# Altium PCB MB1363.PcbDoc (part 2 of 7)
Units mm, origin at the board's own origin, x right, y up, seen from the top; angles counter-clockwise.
Board outline 70 x 133.34 mm, 6 copper layers (Top Layer, Signal Layer 1, Signal Layer 2, Signal Layer 3, Signal Layer 4, Bottom Layer), stack 1.57 mm thick; 355 components, 293 nets, 1446 pads, 1145 vias.

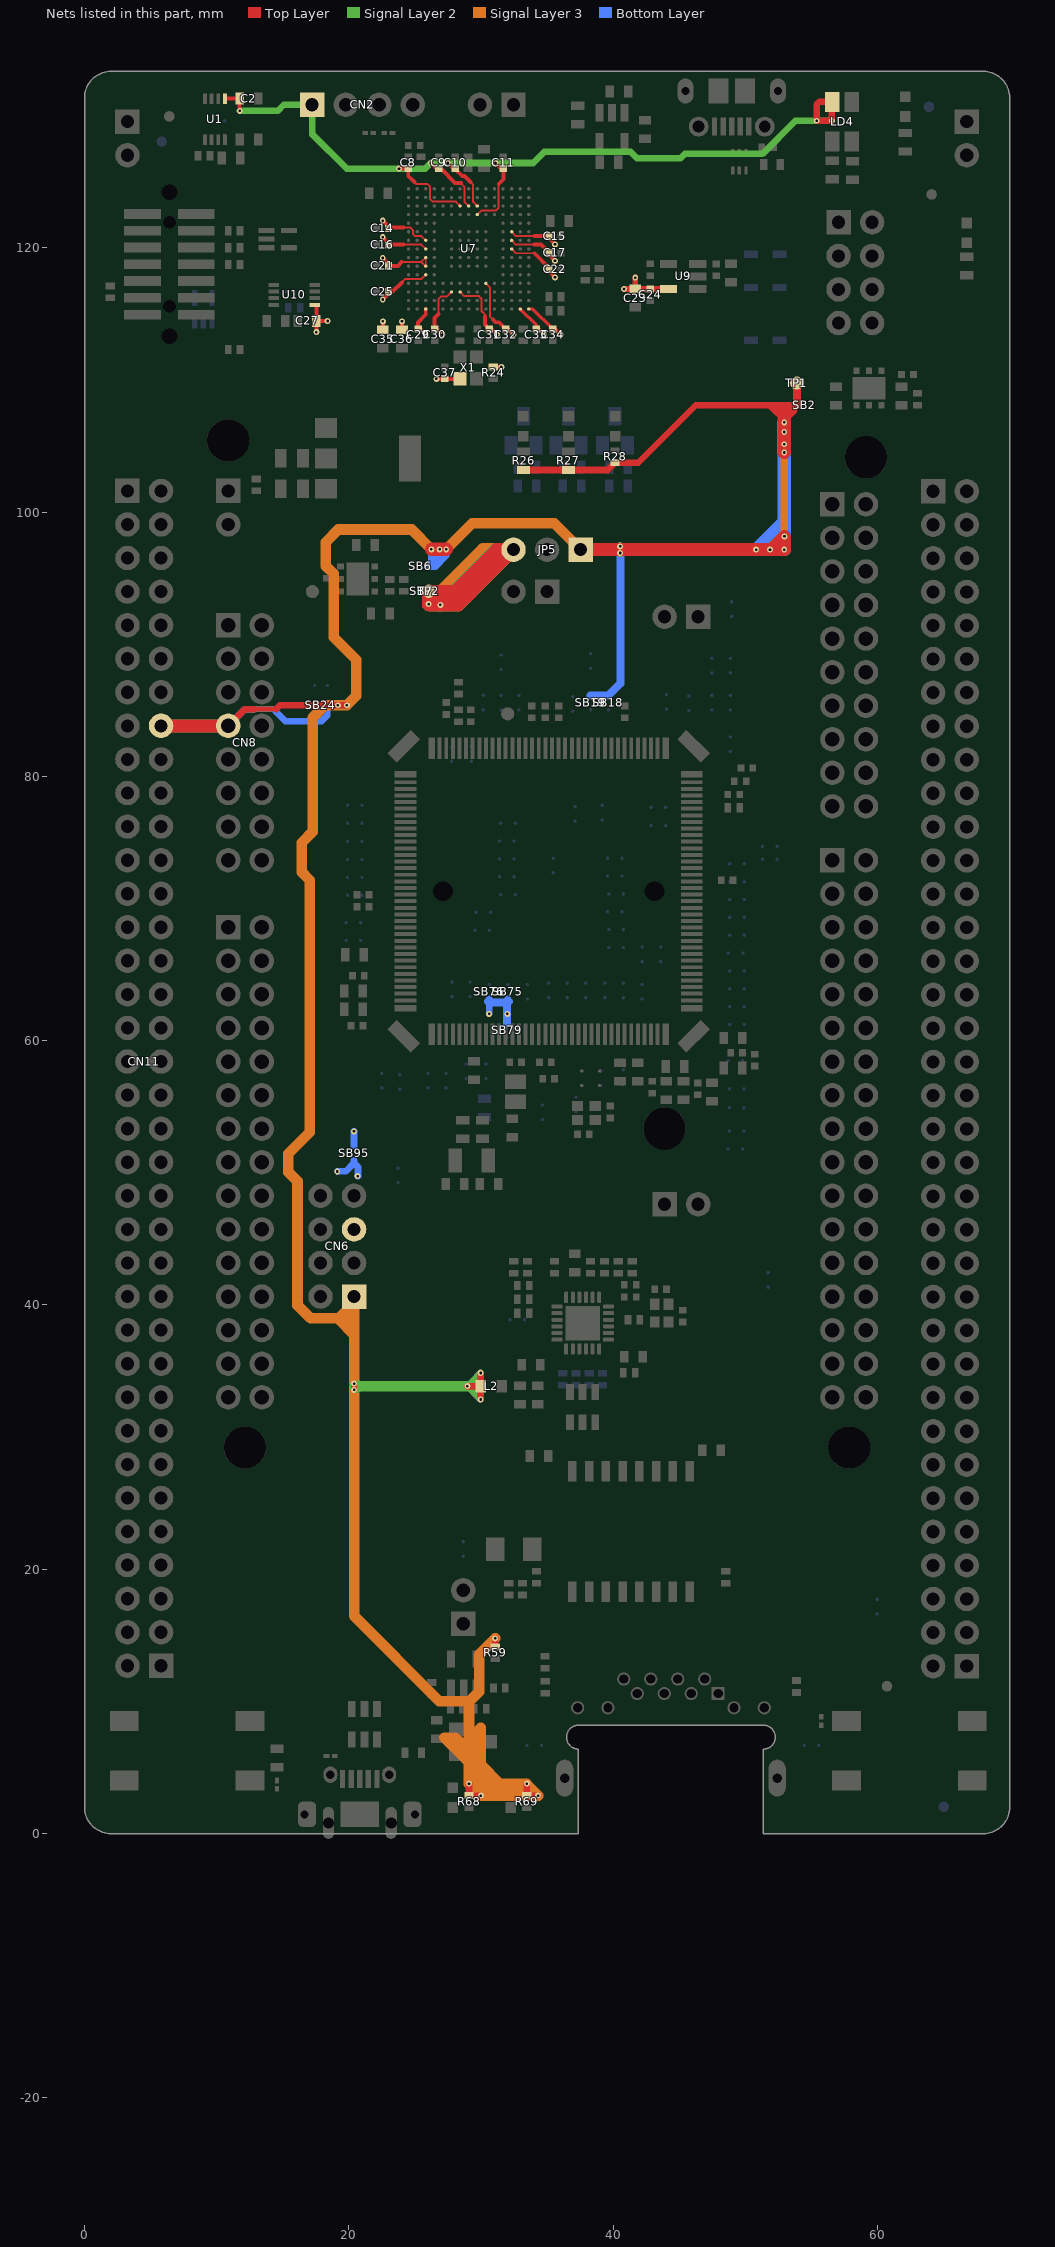
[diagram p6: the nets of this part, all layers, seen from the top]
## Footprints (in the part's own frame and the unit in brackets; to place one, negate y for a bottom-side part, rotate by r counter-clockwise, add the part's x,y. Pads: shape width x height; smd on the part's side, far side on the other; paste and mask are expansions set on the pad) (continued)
ICC_LQFP144_20X20_P050_SOCKET_YAMAICHI_IC149-144-145-B5_NM [mm]
  rect 1x2.5 smd rot 45 mask+0.05: 0(-10.96,-10.96) 0(10.96,10.96)
  rect 1x2.5 smd rot 135 mask+0.05: 0(-10.96,10.96) 0(10.96,-10.96)
  round 0 hole 1.5 unplated mask+0.05: 0(0,8) 0(0,-8)
  rect 1.65x0.5 smd mask+0.05: 1(-10.825,8.85) 36(-10.825,-8.85) 73(10.825,-8.85) 108(10.825,8.85)
  rect 1.65x0.3 smd mask+0.05: 2(-10.825,8.25) 3(-10.825,7.75) 4(-10.825,7.25) 5(-10.825,6.75) 6(-10.825,6.25) 7(-10.825,5.75) 8(-10.825,5.25) 9(-10.825,4.75) 10(-10.825,4.25) 11(-10.825,3.75) 12(-10.825,3.25) 13(-10.825,2.75) 14(-10.825,2.25) 15(-10.825,1.75) 16(-10.825,1.25) 17(-10.825,0.75) 18(-10.825,0.25) 19(-10.825,-0.25) 20(-10.825,-0.75) 21(-10.825,-1.25) 22(-10.825,-1.75) 23(-10.825,-2.25) 24(-10.825,-2.75) 25(-10.825,-3.25) 26(-10.825,-3.75) 27(-10.825,-4.25) 28(-10.825,-4.75) 29(-10.825,-5.25) 30(-10.825,-5.75) 31(-10.825,-6.25) 32(-10.825,-6.75) 33(-10.825,-7.25) 34(-10.825,-7.75) 35(-10.825,-8.25) 74(10.825,-8.25) 75(10.825,-7.75) 76(10.825,-7.25) 77(10.825,-6.75) 78(10.825,-6.25) 79(10.825,-5.75) 80(10.825,-5.25) 81(10.825,-4.75) 82(10.825,-4.25) 83(10.825,-3.75) 84(10.825,-3.25) 85(10.825,-2.75) 86(10.825,-2.25) 87(10.825,-1.75) 88(10.825,-1.25) 89(10.825,-0.75) 90(10.825,-0.25) 91(10.825,0.25) 92(10.825,0.75) 93(10.825,1.25) 94(10.825,1.75) 95(10.825,2.25) 96(10.825,2.75) 97(10.825,3.25) 98(10.825,3.75) 99(10.825,4.25) 100(10.825,4.75) 101(10.825,5.25) 102(10.825,5.75) 103(10.825,6.25) 104(10.825,6.75) 105(10.825,7.25) 106(10.825,7.75) 107(10.825,8.25)
  rect 0.5x1.65 smd mask+0.05: 37(-8.85,-10.825) 72(8.85,-10.825) 109(8.85,10.825) 144(-8.85,10.825)
  rect 0.3x1.65 smd mask+0.05: 38(-8.25,-10.825) 39(-7.75,-10.825) 40(-7.25,-10.825) 41(-6.75,-10.825) 42(-6.25,-10.825) 43(-5.75,-10.825) 44(-5.25,-10.825) 45(-4.75,-10.825) 46(-4.25,-10.825) 47(-3.75,-10.825) 48(-3.25,-10.825) 49(-2.75,-10.825) 50(-2.25,-10.825) 51(-1.75,-10.825) 52(-1.25,-10.825) 53(-0.75,-10.825) 54(-0.25,-10.825) 55(0.25,-10.825) 56(0.75,-10.825) 57(1.25,-10.825) 58(1.75,-10.825) 59(2.25,-10.825) 60(2.75,-10.825) 61(3.25,-10.825) 62(3.75,-10.825) 63(4.25,-10.825) 64(4.75,-10.825) 65(5.25,-10.825) 66(5.75,-10.825) 67(6.25,-10.825) 68(6.75,-10.825) 69(7.25,-10.825) 70(7.75,-10.825) 71(8.25,-10.825) 110(8.25,10.825) 111(7.75,10.825) 112(7.25,10.825) 113(6.75,10.825) 114(6.25,10.825) 115(5.75,10.825) 116(5.25,10.825) 117(4.75,10.825) 118(4.25,10.825) 119(3.75,10.825) 120(3.25,10.825) 121(2.75,10.825) 122(2.25,10.825) 123(1.75,10.825) 124(1.25,10.825) 125(0.75,10.825) 126(0.25,10.825) 127(-0.25,10.825) 128(-0.75,10.825) 129(-1.25,10.825) 130(-1.75,10.825) 131(-2.25,10.825) 132(-2.75,10.825) 133(-3.25,10.825) 134(-3.75,10.825) 135(-4.25,10.825) 136(-4.75,10.825) 137(-5.25,10.825) 138(-5.75,10.825) 139(-6.25,10.825) 140(-6.75,10.825) 141(-7.25,10.825) 142(-7.75,10.825) 143(-8.25,10.825)
  silkscreen extent -10.1,-10.1 10.1,10.1, body extent -11,-11 11,11, height 1.6
ICC_UFBGA201_176+25_10X10_P065 [mm] "IPC"
  round 0.25 smd mask+0.05: A1(-4.55,4.55) A2(-3.9,4.55) A3(-3.25,4.55) A4(-2.6,4.55) A5(-1.95,4.55) A6(-1.3,4.55) A7(-0.65,4.55) A8(0,4.55) A9(0.65,4.55) A10(1.3,4.55) A11(1.95,4.55) A12(2.6,4.55) A13(3.25,4.55) A14(3.9,4.55) A15(4.55,4.55) B1(-4.55,3.9) B2(-3.9,3.9) B3(-3.25,3.9) B4(-2.6,3.9) B5(-1.95,3.9) B6(-1.3,3.9) B7(-0.65,3.9) B8(0,3.9) B9(0.65,3.9) B10(1.3,3.9) B11(1.95,3.9) B12(2.6,3.9) B13(3.25,3.9) B14(3.9,3.9) B15(4.55,3.9) C1(-4.55,3.25) C2(-3.9,3.25) C3(-3.25,3.25) C4(-2.6,3.25) C5(-1.95,3.25) C6(-1.3,3.25) C7(-0.65,3.25) C8(0,3.25) C9(0.65,3.25) C10(1.3,3.25) C11(1.95,3.25) C12(2.6,3.25) C13(3.25,3.25) C14(3.9,3.25) C15(4.55,3.25) D1(-4.55,2.6) D2(-3.9,2.6) D3(-3.25,2.6) D4(-2.6,2.6) D5(-1.95,2.6) D6(-1.3,2.6) D7(-0.65,2.6) D8(0,2.6) D9(0.65,2.6) D10(1.3,2.6) D11(1.95,2.6) D12(2.6,2.6) D13(3.25,2.6) D14(3.9,2.6) D15(4.55,2.6) E1(-4.55,1.95) E2(-3.9,1.95) E3(-3.25,1.95) E4(-2.6,1.95) E12(2.6,1.95) E13(3.25,1.95) E14(3.9,1.95) E15(4.55,1.95) F1(-4.55,1.3) F2(-3.9,1.3) F3(-3.25,1.3) F4(-2.6,1.3) F6(-1.3,1.3) F7(-0.65,1.3) F8(0,1.3) F9(0.65,1.3) F10(1.3,1.3) F12(2.6,1.3) F13(3.25,1.3) F14(3.9,1.3) F15(4.55,1.3) G1(-4.55,0.65) G2(-3.9,0.65) G3(-3.25,0.65) G4(-2.6,0.65) G6(-1.3,0.65) G7(-0.65,0.65) G8(0,0.65) G9(0.65,0.65) G10(1.3,0.65) G12(2.6,0.65) G13(3.25,0.65) G14(3.9,0.65) G15(4.55,0.65) H1(-4.55,0) H2(-3.9,0) H3(-3.25,0) H4(-2.6,0) H6(-1.3,0) H7(-0.65,0) H8(0,0) H9(0.65,0) H10(1.3,0) H12(2.6,0) H13(3.25,0) H14(3.9,0) H15(4.55,0) J1(-4.55,-0.65) J2(-3.9,-0.65) J3(-3.25,-0.65) J4(-2.6,-0.65) J6(-1.3,-0.65) J7(-0.65,-0.65) J8(0,-0.65) J9(0.65,-0.65) J10(1.3,-0.65) J12(2.6,-0.65) J13(3.25,-0.65) J14(3.9,-0.65) J15(4.55,-0.65) K1(-4.55,-1.3) K2(-3.9,-1.3) K3(-3.25,-1.3) K4(-2.6,-1.3) K6(-1.3,-1.3) K7(-0.65,-1.3) K8(0,-1.3) K9(0.65,-1.3) K10(1.3,-1.3) K12(2.6,-1.3) K13(3.25,-1.3) K14(3.9,-1.3) K15(4.55,-1.3) L1(-4.55,-1.95) L2(-3.9,-1.95) L3(-3.25,-1.95) L4(-2.6,-1.95) L12(2.6,-1.95) L13(3.25,-1.95) L14(3.9,-1.95) L15(4.55,-1.95) M1(-4.55,-2.6) M2(-3.9,-2.6) M3(-3.25,-2.6) M4(-2.6,-2.6) M5(-1.95,-2.6) M6(-1.3,-2.6) M7(-0.65,-2.6) M8(0,-2.6) M9(0.65,-2.6) M10(1.3,-2.6) M11(1.95,-2.6) M12(2.6,-2.6) M13(3.25,-2.6) M14(3.9,-2.6) M15(4.55,-2.6) N1(-4.55,-3.25) N2(-3.9,-3.25) N3(-3.25,-3.25) N4(-2.6,-3.25) N5(-1.95,-3.25) N6(-1.3,-3.25) N7(-0.65,-3.25) N8(0,-3.25) N9(0.65,-3.25) N10(1.3,-3.25) N11(1.95,-3.25) N12(2.6,-3.25) N13(3.25,-3.25) N14(3.9,-3.25) N15(4.55,-3.25) P1(-4.55,-3.9) P2(-3.9,-3.9) P3(-3.25,-3.9) P4(-2.6,-3.9) P5(-1.95,-3.9) P6(-1.3,-3.9) P7(-0.65,-3.9) P8(0,-3.9) P9(0.65,-3.9) P10(1.3,-3.9) P11(1.95,-3.9) P12(2.6,-3.9) P13(3.25,-3.9) P14(3.9,-3.9) P15(4.55,-3.9) R1(-4.55,-4.55) R2(-3.9,-4.55) R3(-3.25,-4.55) R4(-2.6,-4.55) R5(-1.95,-4.55) R6(-1.3,-4.55) R7(-0.65,-4.55) R8(0,-4.55) R9(0.65,-4.55) R10(1.3,-4.55) R11(1.95,-4.55) R12(2.6,-4.55) R13(3.25,-4.55) R14(3.9,-4.55) R15(4.55,-4.55)
  silkscreen extent -5.22,-5.07 5.07,5.23, body extent -5.07,-5.07 5.07,5.07, height 0.61
ICC_VQFN24-EPAD_4X4_P050 [mm]
  rrect50% 0.85x0.3 smd mask+0.05: 1(-1.95,1.25) 2(-1.95,0.75) 3(-1.95,0.25) 4(-1.95,-0.25) 5(-1.95,-0.75) 6(-1.95,-1.25) 13(1.95,-1.25) 14(1.95,-0.75) 15(1.95,-0.25) 16(1.95,0.25) 17(1.95,0.75) 18(1.95,1.25)
  rrect50% 0.3x0.85 smd mask+0.05: 7(-1.25,-1.95) 8(-0.75,-1.95) 9(-0.25,-1.95) 10(0.25,-1.95) 11(0.75,-1.95) 12(1.25,-1.95) 19(1.25,1.95) 20(0.75,1.95) 21(0.25,1.95) 22(-0.25,1.95) 23(-0.75,1.95) 24(-1.25,1.95)
  rect 2.6x2.6 smd paste-10 mask+0.05: EP(0,0)
  silkscreen extent -2,-2 2,2, body extent -2.05,-2.05 2.05,2.05, height 1.1
ICC_VSSOP8_DCU_R-PDSO-G8_2X2P30_P050 [mm]
  rect 0.3x0.8 smd mask+0.05: 1(-0.75,-1.55) 2(-0.25,-1.55) 3(0.25,-1.55) 4(0.75,-1.55) 5(0.75,1.55) 6(0.25,1.55) 7(-0.25,1.55) 8(-0.75,1.55)
  silkscreen extent -1.05,-1.2 1.05,1.2, body extent -1.05,-1.62 1.05,1.62, height 0.9
L0603 [mm]
  rect 0.8x0.95 smd mask+0.05: 1(-0.8,0) 2(0.8,0)
  silkscreen extent -1.33,-0.6 1.33,0.6, body extent -0.87,-0.47 0.87,0.47, height 0.95
L0805_H0P9 [mm]
  rect 1.1x1.6 smd mask+0.05: 1(-0.75,0) 2(0.75,0)
  silkscreen extent -0.08,-0.7 0.08,0.7, body extent -1.07,-0.7 1.07,0.7, height 1.2
LED_0603_OSRAM_LG-Q396-PS-35_GREEN_1A2K_H0P4 [mm]
  rect 0.8x0.8 smd mask+0.05: 1(-0.75,0) 2(0.75,0)
  silkscreen extent -0.85,-0.53 1.28,0.53, body extent -0.85,-0.45 0.85,0.45, height 0.6
LED_0603_OSRAM_LS-Q976-NR-1_RED_1A2K_H0P8 [mm]
  rect 0.8x0.8 smd mask+0.05: 1(-0.75,0) 2(0.75,0)
  silkscreen extent -0.85,-0.53 1.28,0.53, body extent -0.85,-0.45 0.85,0.45, height 0.8
LED_0603_OSRAM_LY-Q396-P1Q2-36_YELLOW_1A2K_H0P4 [mm]
  rect 0.8x0.8 smd mask+0.05: 1(-0.75,0) 2(0.75,0)
  silkscreen extent -0.85,-0.53 1.28,0.53, body extent -0.85,-0.45 0.85,0.45, height 0.4
LED_0603_RED [mm]
  rect 0.8x0.8 smd mask+0.05: 1(-0.75,0) 2(0.75,0)
  silkscreen extent -0.25,-0.4 1.25,0.4, body extent -0.8,-0.4 0.8,0.4, height 0.6
LED_0603_VISHAY_VLMS1300-GS08_RED_1A2K_H0P8 [mm]
  rect 0.8x0.8 smd mask+0.05: 1(-0.75,0) 2(0.75,0)
  silkscreen extent -0.85,-0.53 1.28,0.53, body extent -0.85,-0.45 0.85,0.45, height 0.8
LED_BI-GR_HSMF-A201-A00J1 [mm]
  rect 1.1x1.5 smd mask+0.05: 1(-0.75,-1.5) 2(-0.75,1.5) 3(0.75,1.5) 4(0.75,-1.5)
  silkscreen extent -1.65,-1.85 1.65,1.85, body extent -1.5,-1.85 1.5,1.85, height 2.1
MIRE_PLACE_SMD_0P8MM [mm]
  round 0.8 smd paste-10 mask+0.2: 1(0,0)
  Top Layer keep-out circle w0.01: c0,0 r0.804
MOS_SOT23-5L [mm]
  rect 0.6x1.3 smd mask+0.05: 1(-0.95,-1.1) 2(0,-1.1) 3(0.95,-1.1) 4(0.95,1.1) 5(-0.95,1.1)
  silkscreen extent -1.6,-0.95 1.6,0.97, body extent -1.52,-1.25 1.52,1.25, height 1.45
NPN_SOT23 [mm]
  rect 1x1.4 smd mask+0.05: 1(-0.95,-1.1) 2(0.95,-1.1) 3(0,1.1)
  silkscreen extent -1.63,-0.82 1.63,0.82, body extent -1.56,-1.25 1.56,1.25, height 1.1
OSC_NDK_NZ2520SB_4P [mm]
  rect 1x1 smd mask+0.05: 1(-0.825,-0.625) 2(0.825,-0.625) 3(0.825,0.625) 4(-0.825,0.625)
  silkscreen extent -1.43,-1.22 1.2,1.05, body extent -1.3,-1.05 1.3,1.05, height 0.91
R0402 [mm]
  rect 0.51x0.7 smd mask+0.05: 1(-0.45,0) 2(0.45,0)
  silkscreen extent -0.72,-0.43 0.72,0.43, body extent -0.52,-0.3 0.52,0.3, height 0.4
R0603 [mm]
  rect 0.64x1 smd mask+0.05: 1(-0.7,0) 2(0.7,0)
  silkscreen extent -1.05,-0.58 1.05,0.58, body extent -0.9,-0.5 0.9,0.5, height 0.56
REG_SOT23-5L [mm]
  rect 0.6x1.3 smd mask+0.05: 1(-0.95,-1.1) 2(0,-1.1) 3(0.95,-1.1) 4(0.95,1.1) 5(-0.95,1.1)
  silkscreen extent -1.6,-0.95 1.6,0.97, body extent -1.52,-1.25 1.52,1.25, height 1.1
REG_SOT223-TAB [mm]
  rect 1.5x1.65 smd mask+0.05: 1(-2.3,-3.175) 2(0,-3.175) 3(2.3,-3.175)
  rect 3.5x1.65 smd mask+0.05: 4(0,3.175)
  silkscreen extent -3.35,-2.15 3.35,2.12, body extent -3.35,-3.48 3.35,3.48, height 1.8
Sheetbox_6L2S [mil] "Sheetbox 6 layers / 2 silkscreens"
  round 20 on Mech16: 1(813.5,208.05) 1(2736.63,208.05)
SOLDER-BRIDGE_R0402-0R [mil]
  round 10 smd paste-393.7: 1(-17.72,0) 2(20.67,0)
  Top Layer region: 1.48,13.78 8.37,0 1.48,-13.78 30.51,-13.78 30.51,13.78
  Top Layer region: -30.51,-13.78 -30.51,13.78 -8.37,13.78 -1.48,0 -8.37,-13.78
  silkscreen extent -11,-17 11,17, body extent -36,-20 36,20, height 20
SOLDER-BRIDGE_R0603-0R [mil]
  round 10 smd paste-393.7: 1(-19.68,0) 2(23.62,0)
  Top Layer region: -47.24,-19.69 -47.24,19.68 -15.75,19.68 3.94,0 -15.75,-19.69 -47.24,-19.69
  Top Layer region: -5.91,19.68 13.78,0 -5.91,-19.69 47.24,-19.69 47.24,19.68 -5.91,19.68
  silkscreen extent -50,-23 50,23, body extent -36,-20 36,20, height 22
SWI_WEALTHMETAL_TD-0341_4P_BLACK [mm]
  rect 1.52x2.16 smd mask+0.05: 1(-2.25,-4.75) 2(-2.25,4.75) 3(2.25,-4.75) 4(2.25,4.75)
  silkscreen extent -3,-3.5 3,3.5, body extent -3,-5.15 3,5.15, height 7.55
SWI_WEALTHMETAL_TD-0341_4P_BLUE [mm]
  rect 1.52x2.16 smd mask+0.05: 1(-2.25,-4.75) 2(-2.25,4.75) 3(2.25,-4.75) 4(2.25,4.75)
  silkscreen extent -3,-3.5 3,3.5, body extent -3,-5.15 3,5.15, height 7.55
TP_SMD_1MM [mm]
  round 1 smd paste-10 mask+0.05: 1(0,0)
  silkscreen extent -0.7,-0.7 0.7,0.7
TRS_DGKYD_KMS-1102NL [mm]
  rect 0.64x1.55 smd mask+0.05: 1(-4.445,-4.575) 2(-3.175,-4.575) 3(-1.905,-4.575) 4(-0.635,-4.575) 5(0.635,-4.575) 6(1.905,-4.575) 7(3.175,-4.575) 8(4.445,-4.575) 9(4.445,4.575) 10(3.175,4.575) 11(1.905,4.575) 12(0.635,4.575) 13(-0.635,4.575) 14(-1.905,4.575) 15(-3.175,4.575) 16(-4.445,4.575)
  silkscreen extent -6.35,-3.7 6.35,3.7, body extent -6.35,-4.7 6.35,4.7, height 6.3

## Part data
B1: library part MCD-00002, "Non-Open Push-Button 0.1A 24V", Manufacturer=WEALTHMETAL, Manufacturer_Part_Number=TD-0341
B2: library part MCD-00001, "Non-Open Push-Button 0.1A 24V BLACK", Manufacturer=WEALTHMETAL, Manufacturer_Part_Number=TD-0341
C1 C3 C18 C63 C69 C72: library part MCD-00238, "Capacitor, MLCC, 1uF, 6V3, X5R, 10%, 0603, T=0,8mm", Manufacturer=YAGEO, Manufacturer_Part_Number=CC0603KRX5R5BB105, Package=C0603
C2 C4: library part MCD-00211, "Capacitor, MLCC, 100nF, 16V, X7R, 10%, 0603, T=0,8mm", Manufacturer=YAGEO, Manufacturer_Part_Number=CC0603KRX7R7BB104, Package=C0603
C5: library part MCD-00016, "Capacitor, MLCC, 20pF, 50V, NPO, 5%, 0402, T=0,5mm", Manufacturer=YAGEO, Manufacturer_Part_Number=CC0402JRNPO9BN200, Package=C0402
C6: library part MCD-00205, "Capacitor, MLCC, 100pF, 50V, NPO, 5%, 0402, T=0,5mm", Manufacturer=YAGEO, Manufacturer_Part_Number=CC0402JRNPO9BN101, Package=C0402
C7 C12 C13: library part MCD-00012, "Capacitor, MLCC, 2.2uF, 10V, X5R, 10%, 0603, T=0,8mm", Alternate_Manufacturer=KEMET, Alternate_Manufacturer_Part_Number=C0603C225K8PACTU, Manufacturer=YAGEO, Manufacturer_Part_Number=CC0603KRX5R6BB225, Package=C0603
C8 C9 C10 C11 C14 C15 C16 C17 C20 C21 C22 C24 C25 C28 C29 C30 C31 C32 C33 C34 C37: library part MCD-00102, "Capacitor, MLCC, 100nF, 16V, X7R, 10%, 0402, T=0,5mm", Alternate_Manufacturer=MURATA, Alternate_Manufacturer_Part_Number=GCM155R71C104KA55D, Manufacturer=YAGEO, Manufacturer_Part_Number=CC0402KRX7R7BB104, Package=C0402
C19: library part MCD-00011, "Capacitor, MLCC, 10nF, 16V, X7R, 10%, 0402, T=0.5mm", Manufacturer=YAGEO, Manufacturer_Part_Number=CC0402KRX7R7BB103, Package=C0402
C23 C36: library part MCD-00010, "Capacitor, MLCC, 1uF, 16V, X5R, 10%, 0603, T=0,8mm", Manufacturer=YAGEO, Manufacturer_Part_Number=CC0603KRX5R7BB105, Package=C0603
C26 C27 C60 C66 C70 C79 C84 C85 C86 C88 C89: library part MCD-00237, "Capacitor, MLCC, 100nF, 6V3, X5R, 10%, 0603, T=0,8mm", Manufacturer=YAGEO, Manufacturer_Part_Number=CC0603KRX5R5BB104, Package=C0603
C35 C91: library part MCD-00009, "Capacitor, MLCC, 4.7uF, 16V, X5R, 10%, 0603, T=0.8mm", Manufacturer=YAGEO, Manufacturer_Part_Number=CC0603KRX5R7BB475, Package=C0603
C38 C44 C46 C47 C48 C49 C50 C51 C52 C53 C54 C55 C56 C57 C58 C59 C61 C62 C71 C73: library part MCD-00006, "Capacitor, MLCC, 100nF, 16V, X7R, 10%, 0402, T=0.5mm", Alternate_Manufacturer=MURATA, Alternate_Manufacturer_Part_Number=GCM155R71C104KA55D, Manufacturer=YAGEO, Manufacturer_Part_Number=CC0402KRX7R7BB104, Package=C0402
C39 C43 C45 C67: library part MCD-01121, "Capacitor, MLCC, 4.7µF, 10V, X5R, 20%, 0603, T=0,8mm", Manufacturer=MURATA, Manufacturer_Part_Number=GRM188R61A475ME15, Package=C0603
C40: library part MCD-00097, "Capacitor, MLCC, 4.7uF, 16V, X5R, 20%, 0603, T=0,8mm", Alternate_Manufacturer=Murata, Alternate_Manufacturer_Part_Number=GRM188R61C475MAAJ, Manufacturer=MURATA, Manufacturer_Part_Number=GRM188R61C475KE11, Package=C0603
C41 C42: library part MCD-00014, "Capacitor, MLCC, 10uF, 25V, X5R, 10%, 0805, T=0,85mm", Manufacturer=YAGEO, Manufacturer_Part_Number=CC0805KRX5R8BB106, Package=C0805
C64: library part MCD-01225, "Capacitor, MLCC, 220pF, 50V, NPO, 5%, 0402, T=0,5mm", Manufacturer=YAGEO, Manufacturer_Part_Number=CC0402JRNPO9BN221, Package=C0402
C65 C68: library part MCD-01716, "Capacitor, MLCC, 10uF, 6V3, X5R, 20%, 0402, T=0.5mm", Manufacturer=YAGEO, Manufacturer_Part_Number=CC0402MRX5R5BB106, Package=C0402
C74 C76 C81 C83: library part MCD-01374, "Capacitor, MLCC, 5.6pF, 50V, NPO, 5%, 0402, T=0,5mm", Manufacturer=YAGEO, Manufacturer_Part_Number=CC0402BRNPO9BN5R6, Package=C0402
C75: library part MCD-01341, "Capacitor, MLCC, 10uF, 6V3, X5R, 20%, 0603, T=0,8mm", Manufacturer=MURATA, Manufacturer_Part_Number=GRM188R60J106ME47D, Package=C0603
C77 C78: library part MCD-01367, "Capacitor,5.1pF,0.25pF,50V,NPO,0603", Manufacturer=YAGEO, Manufacturer_Part_Number=CC0603CRNPO9BN5R1, Package=C0603
C80: library part MCD-00095, "Capacitor, MLCC, 1uF, 6V3, X5R, 10%, 0402, T=0,5mm", Alternate_Manufacturer=MURATA, Alternate_Manufacturer_Part_Number=GRM155R60J105KE19, Manufacturer_Part_Number=GRM155R61E105KA12, Package=C0402
C82: library part MCD-00724, "Capacitor, MLCC, 470pF, 50V, NPO, 5%, 0402, T=0,5mm", Manufacturer=YAGEO, Manufacturer_Part_Number=CC0402JRNPO9BN471, Package=C0402
C87: library part MCD-01124, "Capacitor, MLCC, 10µF, 10V, X5R, 10%, 0603, T=0.8mm", Manufacturer=MURATA, Manufacturer_Part_Number=GRM188R61A106KAAL, Package=C0603
C90: library part MCD-00722, "Capacitor, MLCC, 1nF, 2KV, X7R, 10%, 1206, T=1,25mm", Manufacturer=YAGEO, Manufacturer_Part_Number=CC1206KKX7RDBB102, Package=C1206
CN1: library part MCD-00028, "USB-MICRO-B, 0.65mm, RA, SMT, Bottom Mount,", Manufacturer=MOLEX, Manufacturer_Part_Number=1050170001
CN2: library part MCD-00029, "Header, 4x1, 2,54mm, VR, TH, Height 5.84mm/2.54mm", Manufacturer=SAMTEC, Manufacturer_Part_Number=TSW-104-07-x-S
CN3 CN4 CN15 CN16: library part MCD-00214, "Header, 2x1, 2,54mm, VR, TH, Height 5.84mm/10.16mm", Manufacturer=SAMTEC, Manufacturer_Part_Number=TSW-102-09-x-S
CN5: library part MCD-01226, "Header 5x2, 1.27mm, Dual row, Straight, Surface mount, vertical male connector. 3.05mm lead. Mates with FFSD connector. Footprint compatible with FTSH-107-01-L-DV,-K,-A,-P,-ES (STDC14 MEDIUM)", Alternate_Manufacturer=JIUBABA, Alternate_Manufacturer_Part_Number=P127B-2x05MGF-079-1A, Manufacturer=SAMTEC, Manufacturer_Part_Number=FTSH-105-01-L-DV-K
CN6: library part MCD-00633, "Header, 4x2, 2,54mm, VR, TH, Height 5.84mm/2.54mm", Manufacturer=SAMTEC, Manufacturer_Part_Number=TSW-104-07-x-D
CN7: library part MCD-01039, "Socket, 10x2, 2.54mm, VR, TH, Height 8.51mm/10mm, Low insertion force.", Manufacturer=SAMTEC, Manufacturer_Part_Number=SSW-110-23-x-D
CN8: library part MCD-01037, "Socket, 8x2, 2.54mm, VR, TH, Height 8.51mm/10mm, Low insertion force.", Manufacturer=SAMTEC, Manufacturer_Part_Number=SSW-108-23-x-D
CN9: library part MCD-01040, "Socket, 15x2, 2.54mm, VR, TH, Height 8.51mm/10mm, Low insertion force.", Manufacturer=SAMTEC, Manufacturer_Part_Number=SSW-115-23-x-D
CN10: library part MCD-01041, "Socket, 17x2, 2.54mm, VR, TH, Height 8.51mm/10mm, Low insertion force", Manufacturer=SAMTEC, Manufacturer_Part_Number=SSW-117-23-x-D
CN11 CN12: library part MCD-01210, "Header, 35x2, 2,54mm, VR, TH, Height 5.84mm/2.54mm", Manufacturer=SAMTEC, Manufacturer_Part_Number=TSW-135-07-x-D
CN13: library part MCD-00661, "USB-MICRO-AB Receptacle, RA, SMT + DIP, Standard, Top Mount, USB certified (symbol & footprint compatible with MCD-00022)", Manufacturer=HIROSE, Manufacturer_Part_Number=ZX62RD-AB-5P8(30)
CN14: library part MCD-00717, "RJ45 jack, single port, with LEDS, Metal shielded dip low profile", Manufacturer="DONGGUAN KEYOUDA ELECTRONIC TECHNOLOGY", Manufacturer_Part_Number=KRJ-CB4.2GYZNL
D1 D2 D3: library part MCD-00034, Manufacturer=STMICROELECTRONICS
JP1: library part MCD-00045, "Header, 2x1, 2,54mm, VR, TH, Height 5.84mm/2.54mm", Alternate_Manufacturer="JIUBABA; LIANYI", Alternate_Manufacturer_Part_Number=313102S111116;313102S111116, Manufacturer=SAMTEC, Manufacturer_Part_Number=TSW-102-07-x-S
JP2: library part MCD-00686, "Header, 4x2, 2,54mm, VR, TH, Height 5.84mm/2.54mm - Shunt Fitted 1-2", Manufacturer=SAMTEC, Manufacturer_Part_Number=TSW-104-07-x-D
JP3 JP4 JP6 JP7 JP8: library part MCD-00683, "Header, 2x1, 2,54mm, VR, TH, Height 5.84mm/2.54mm - Shunt Fitted by default", Alternate_Manufacturer=LIANYI, Alternate_Manufacturer_Part_Number=313102S111116, Manufacturer=SAMTEC, Manufacturer_Part_Number=TSW-102-07-x-S
JP5: library part MCD-00684, "Header, 3x1, 2,54mm, VR, TH, Height 5.84mm/2.54mm - Shunt Fitted 1-2 by default", Manufacturer=SAMTEC, Manufacturer_Part_Number=TSW-103-07-F-S
L1: library part MCD-01340, "Inductor, 2.2uH, 20%, Isat 1.2A, DCR 0.228Ohm, 0805", Manufacturer=MURATA, Manufacturer_Part_Number=DFE201210U-2R2M{}P2, Package=L0805
L2: library part MCD-00047, "SMD Chip ferrite bead, 600R@100MHz +/-25%, 350mA, 500mohm DC, 0603, T=0.8mm", Manufacturer=TAI-TECH, Manufacturer_Part_Number=FCM1608KF-601T03
LD1 LD5 LD8: library part MCD-00588, "LED Green, 0603 SMD, Forward Voltage Typ=2V, Max=2.5V", Alternate_Manufacturer="VISHAY SEMICONDUCTOR OPTO DIVISION", Alternate_Manufacturer_Part_Number=VLMTG1300-GS08, Manufacturer="OSRAM OPTO SEMICONDUCTORS", Manufacturer_Part_Number="LG Q396-PS-35", Package="LED 0603"
LD2: library part MCD-01061, "LED Yellow, 0603 SMD, Forward Voltage min=1.7V, Typ=2V, Max=2.3V", Manufacturer="OSRAM OPTO SEMICONDUCTORS", Manufacturer_Part_Number="LY Q396-P1Q2-36"
LD3: library part MCD-00586, "LED Red, 0603 SMD, Forward Voltage Typ=2V, Max=2.5V", Alternate_Manufacturer="VISHAY SEMICONDUCTOR OPTO DIVISION", Alternate_Manufacturer_Part_Number=VLMS1300-GS08, Manufacturer="OSRAM OPTO SEMICONDUCTORS", Manufacturer_Part_Number="LS Q976-NR-1", Package="LED 0603"
LD4: library part MCD-00051, "LED Bicolor", Alternate_Manufacturer=EVERLUCK, Alternate_Manufacturer_Part_Number=LE-RGW35280, Manufacturer="AVAGO TECHNOLOGIES", Manufacturer_Part_Number=HSMF-A201-A00J1
LD6: library part MCD-00049, "LED, Red, 0603", Manufacturer=EVERLIGHT, Manufacturer_Part_Number=19-213-R6C-AP1Q2B/3T, Package="LED 0603"
LD7: library part MCD-00587, "LED Red, 0603 SMD, 2V Forward Voltage", Alternate_Manufacturer="OSRAM OPTO SEMICONDUCTORS", Alternate_Manufacturer_Part_Number="LS Q976-NR-1", Manufacturer=VISHAY, Manufacturer_Part_Number=VLMS1300-GS08, Package="LED 0603"
Q1 Q2 Q3 T1: library part MCD-00073, "NPN Bipolar Transistor", Alternate_Manufacturer="ON SEMICONDUCTOR", Alternate_Manufacturer_Part_Number="MMBT2222LT1G / MMBT2222ALT1G / MMBT2222ALT3G", Manufacturer_Part_Number=BSR14, Package=SOT23
R1 R4 R67 R71 R72 R73: library part MCD-00223, "Resistor,100K,0603,1%,1/10W", Manufacturer=YAGEO, Manufacturer_Part_Number=RC0603FR-07100KL, Package=R0603
R2: library part MCD-00070, "Resistor,1K,0603,1%,1/10W", Manufacturer=YAGEO, Manufacturer_Part_Number=RC0603FR-071KL, Package=R0603
R3 R10 R11 R13 R23 R29: library part MCD-00481, "Resistor,47R,0402,1%,1/16W", Manufacturer=YAGEO, Manufacturer_Part_Number=RC0402FR-0747RL, Package=R0402
R5 R17 R21 R70: library part MCD-00119, "Resistor,100R,0402,1%,1/16W", Manufacturer=YAGEO, Manufacturer_Part_Number=RC0402FR-07100RL, Package=R0402
R6: library part MCD-00185, "Resistor,3K,0402,1%,1/16W", Manufacturer=YAGEO, Manufacturer_Part_Number=RC0402FR-073KL, Package=R0402
R7 R36 R37 R38: library part MCD-00220, "Resistor,10K,0603,1%,1/10W", Manufacturer=YAGEO, Manufacturer_Part_Number=RC0603FR-0710KL, Package=R0603
R8 R9 R77: library part MCD-00197, "Resistor,330R,0603,1%,1/10W", Manufacturer=YAGEO, Manufacturer_Part_Number=RC0603FR-07330RL, Package=R0603
R12: library part MCD-00500, "Resistor,620R,0603,1%,1/10W", Manufacturer=YAGEO, Manufacturer_Part_Number=RC0603FR-07620RL, Package=R0603
R14 R18 R20: library part MCD-00065, "Resistor,4K7,0402,1%,1/16W", Alternate_Manufacturer=YAGEO, Alternate_Manufacturer_Part_Number=RT0402FRE074K7L, Manufacturer_Part_Number=RC0402FR-074K7L, Package=R0402
R15: library part MCD-00055, "Resistor,2K7,0402,1%,1/16W", Manufacturer=YAGEO, Manufacturer_Part_Number=RC0402FR-072K7L, Package=R0402
R22 R24 R25 R30 R43 R45 R46 R49 R51 R60 R63 R66: library part MCD-00053, "Resistor,10K,0402,1%,1/16W", Manufacturer=YAGEO, Manufacturer_Part_Number=RC0402FR-0710KL, Package=R0402
R26: library part MCD-00462, "Resistor,360R,0603,1%,1/10W", Manufacturer=YAGEO, Manufacturer_Part_Number=RC0603FR-07360RL, Package=R0603
R27: library part MCD-00354, "Resistor,470R,0603,1%,1/10W", Manufacturer=YAGEO, Manufacturer_Part_Number=RC0603FR-07470RL, Package=R0603
R28 R61 R62 R69: library part MCD-00441, "Resistor,270R,0402,1%,1/16W", Manufacturer=YAGEO, Manufacturer_Part_Number=RC0402FR-07270RL, Package=R0402
R31: library part MCD-00443, "Resistor,27K,0402,1%,1/16W", Manufacturer=YAGEO, Manufacturer_Part_Number=RC0402FR-0727KL, Package=R0402
R32: library part MCD-00493, "Resistor,56K,0402,1%,1/16W", Manufacturer=YAGEO, Manufacturer_Part_Number=RC0402FR-0756KL, Package=R0402
R33 R34 R35 R53: library part MCD-00052, "Resistor,0R,0402,5%,1/16W", Manufacturer=YAGEO, Manufacturer_Part_Number=RC0402JR-070RL, Package=R0402
R39 R40 R41 R42: library part MCD-00056, "Resistor,0R,0603,5%,1/10W", Manufacturer=YAGEO, Manufacturer_Part_Number=RC0603JR-070RL, Package=R0603
R44 R47 R48 R52: library part MCD-00455, "Resistor,33R,0402,1%,1/16W", Manufacturer=YAGEO, Manufacturer_Part_Number=RC0402FR-0733RL, Package=R0402
R50: library part MCD-00068, "Resistor,1K5,0402,1%,1/16W", Manufacturer=YAGEO, Manufacturer_Part_Number=RC0402FR-071K5L, Package=R0402
R54: library part MCD-00723, "Resistor,12K1,0402,1%,1/16W", Manufacturer=YAGEO, Manufacturer_Part_Number=RC0402FR-0712K1L, Package=R0402
R55 R56 R57 R58: library part MCD-00515, "Resistor,75R,0402,1%,1/16W", Manufacturer=YAGEO, Manufacturer_Part_Number=RC0402FR-0775RL, Package=R0402
R59 R64 R65: library part MCD-00063, "Resistor,47K,0402,1%,1/16W", Manufacturer=YAGEO, Manufacturer_Part_Number=RC0402FR-0747KL, Package=R0402
R68: library part MCD-00461, "Resistor,360R,0402,1%,1/16W", Manufacturer=YAGEO, Manufacturer_Part_Number=RC0402FR-07360RL, Package=R0402
R74 R75 R76: library part MCD-00222, "Resistor,47K,0603,1%,1/10W", Manufacturer=YAGEO, Manufacturer_Part_Number=RC0603FR-0747KL, Package=R0603
R78 R79 R80 R81: library part MCD-00565, "Resistor,49R9,0402,1%,1/16W", Manufacturer=YAGEO, Manufacturer_Part_Number=RC0402FR-0749R9L, Package=R0402
SB2 SB3 SB4 SB5 SB6 SB7 SB8 SB9 SB10 SB11 SB12 SB13 SB15 SB16 SB17 SB18 SB19 SB20 SB21 SB22 SB23 SB25 SB26 SB27 SB28 SB29 SB30 SB31 SB32 SB33 SB34 SB35 SB36 SB39 SB40 SB41 SB42 SB43 SB44 SB45 SB46 SB47 SB48 SB49 SB50 SB51 SB52 SB53 SB54 SB55 SB56 SB57 SB58 SB59 SB60 SB61 SB62 SB63 SB64 SB65 SB66 SB67 SB68 SB69 SB70 SB71 SB72 SB73 SB74 SB75 SB76 SB77 SB78 SB79 SB80 SB81 SB82 SB83 SB84 SB85 SB86 SB87 SB88 SB89 SB90 SB91 SB92 SB93 SB94 SB95 SB96 SB97 SB98 SB99 SB100 SB101 SB102 SB103 SB104: library part MCD-00071, "Solder Bridge ON", Manufacturer=YAGEO, Manufacturer_Part_Number=RC0603JR-070RL, Package=SB0603
SB14 SB24 SB37 SB38: library part MCD-01618, "Solder Bridge 0402 ON", Manufacturer=YAGEO, Manufacturer_Part_Number=RC0402JR-070RL, Package=SB0402
TP1 TP2 TP3 TP4: library part MCD-00074, "Test Point 1mm", Manufacturer=n/a
U1 U10: library part MCD-00264, "Dual bit dual supply bus transceiver", Manufacturer="TEXAS INSTRUMENTS"
U2: library part MCD-00159, "500mA, Enhanced single channel power switches with active high enable pin", Alternate_Manufacturer="TEXAS INSTRUMENTS", Alternate_Manufacturer_Part_Number=TPS2051C, Manufacturer=STMICROELECTRONICS
U3 U4 U20 U22 U23: library part MCD-00170, "ESD protection 6V1", Manufacturer=STMICROELECTRONICS, Manufacturer_Part_Number=ESDALC6V1-1U2
U5: library part MCD-00649, "Common mode filter with ESD protection for USB 2.0 interface", Manufacturer=STMICROELECTRONICS
U6 U21: library part MCD-00251, "High power transient voltage suppressor, 7V breakdown", Manufacturer=STMICROELECTRONICS, Manufacturer_Part_Number=ESDA7P60-1U1M
U7: library part MCD-00596, "STM32F723IEK  (STM32F7) BGA176", Manufacturer=STMICROELECTRONICS, Manufacturer_Part_Number=STM32F723IEK6
U8 U24: library part MCD-00136, "Dual Transil array for ESD protection", Manufacturer=STMICROELECTRONICS
U9: library part MCD-00086, "Ultra low drop-low noise BiCMOS voltage, regulators low ESR capacitors compatible", Manufacturer=STMICROELECTRONICS
U11: library part MCD-01025, "LDO, 3.3V, 1.3A, Very low quiescent current BiCMOS voltage regulator", Manufacturer=STMICROELECTRONICS, Package=DFN6-3x3
U12: library part MCD-00088, "IC REG LDO 5V 0.8A SOT223", Manufacturer=STMICROELECTRONICS, Package=SOT-223
U13: library part MCD-00581, "LDO Linear Voltage Regulator IC Positive Adjustable 1 Output Adjustable 1.3A 6-DFN (3x3)", Manufacturer=STMICROELECTRONICS, Package="DFN6 (3x3)"
U14: library part MCD-01401, "STM32H745ZIT6U, LQFP144 package, 20x20, with socket footprint", Manufacturer=STMICROELECTRONICS, Manufacturer_Part_Number=STM32H745ZIT6U, Package="LQFP144 20x20"
U15: library part MCD-00719, "10/100M RMII Ethernet transceiver", Manufacturer=MICROCHIP
U16: library part MCD-00250, "Very low capacitance ESD protection , 4 lines", Manufacturer=STMICROELECTRONICS
U17: library part MCD-00718, "Discrete Magnetic Transformer Module, 16 pins, SMT, 100 Base-TX", Manufacturer="DONGGUAN KEYOUDA ELECTRONIC TECHNOLOGY"
U18: library part MCD-00083, "Enhanced single channel power switches with active low enable pin", Alternate_Manufacturer="TEXAS INSTRUMENTS", Alternate_Manufacturer_Part_Number=TPS2041C, Manufacturer=STMICROELECTRONICS
U19: library part MCD-00163, "Very low capacitance ESD protection", Manufacturer=STMICROELECTRONICS
X1: library part MCD-00597, "Oscillator 25Mhz, +-50ppm, Vcc:3.3V typ, square wave: [0.1Vcc;0.9Vcc], Enable pin, SMD", Alternate_Manufacturer=NDK, Alternate_Manufacturer_Part_Number="NZ2520SB 25MHz END4869B", Manufacturer_Part_Number="NZ2520SH 25MHz END4869C"
X2 X4: library part MCD-01364, "Crystal 25MHz, 6pF, +-20ppm, 80ohms max, SMD", Manufacturer=NDK, Manufacturer_Part_Number="NX2016SA 25MHz EXS00A-CS11321", Package=NX2016SA
X3: library part MCD-00091, "Crystal 32.768kHz, 6pF, +-20ppm, 50Kohms max, SMD", Manufacturer=NDK, Manufacturer_Part_Number="NX3215SA 32.768KHz EXS00A-MU00525"

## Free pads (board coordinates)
  round 3.2 hole 3.2 unplated: 0(10.866,105.409) 0(12.136,29.209) 0(43.886,53.339) 0(57.856,29.209) 0(59.126,104.139)

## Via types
v1: diameter 0.45, hole 0.2, Top Layer to Bottom Layer, tented both sides, 1136 vias
v2: diameter 0.6, hole 0.3, Top Layer to Bottom Layer, tented both sides, 9 vias

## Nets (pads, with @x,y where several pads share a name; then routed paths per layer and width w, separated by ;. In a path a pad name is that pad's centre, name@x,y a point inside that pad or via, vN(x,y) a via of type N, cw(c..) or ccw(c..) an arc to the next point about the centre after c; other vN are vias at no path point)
1V2_MCU: SB75.2 SB76.2 SB79.1 SB95.2 | length 6.8
  Bottom Layer w0.4: v1(31.991,62.029) 31.991,62.729 32.215,62.953 SB75.2@32.015,63.153
  Bottom Layer w0.5: SB95.2@20.391,52.034 v1(20.391,53.134) ; v1(30.616,62.029) 30.616,62.879 ; SB76.2@30.616,63.153 30.616,62.879 ; 30.89,62.879 30.616,62.879 ; 31.741,62.879 SB75.2@32.015,63.153
  Bottom Layer w0.6: 30.516,62.979 30.616,62.879 ; 30.89,62.879 31.741,62.879 ; SB79.1@31.966,61.329 31.966,62.953
1V2_VOUTCORE: CN6.5 SB95.1 | length 2.9
  Bottom Layer w0.5: v1(19.121,50.105) 19.762,50.105 20.391,50.734 ; SB95.1@20.391,50.934 20.391,50.734 ; v1(20.666,49.754) 20.691,49.729 20.691,50.434 20.391,50.734
1V8: JP5.3 SB7.2 TP2.1 | length 58.6
  Top Layer w0.5: TP2.1@26.041,94.004 TP2.1@26.066,93.979
  Top Layer w1: TP2.1@26.041,94.004 v1(26.041,93.029) 26.091,92.979 v1(26.916,92.979) ; TP2.1@26.066,93.979 27.916,93.979 ; v1(26.916,92.979) 28.281,92.979 29.281,93.979 ; v1(26.916,92.979) 27.406,93.469 ; 27.406,93.469 27.497,93.469 28.007,93.979 ; 27.406,93.469 27.916,93.979 ; 27.916,93.979 28.007,93.979 ; 28.007,93.979 31.182,97.154 JP5.3@32.456,97.154 29.3,93.998 ; 28.007,93.979 29.281,93.979 ; 29.281,93.979 29.3,93.998 ; 29.281,93.979 29.3,93.979 29.3,93.998
  Signal Layer 2 w1: v1(26.041,93.029) 26.091,92.979 v1(26.916,92.979) 28.281,92.979 JP5.3@32.456,97.154 31.129,97.154 27.75,93.775 26.787,93.775 v1(26.041,93.029)
  Signal Layer 3 w0.5: v1@26.866,93.029 v1(26.916,92.979)
  Signal Layer 3 w1: v1@26.866,93.029 v1(26.041,93.029) 26.916,93.904 ; v1(26.916,92.979) v1@26.916,93.183 ; v1@26.916,93.183 30.461,96.729 32.031,96.729 JP5.3@32.456,97.154 30.166,97.154 26.916,93.904 ; v1@26.916,93.183 26.916,93.904
  Bottom Layer w0.5: 26.041,93.854 v1@26.891,93.004 ; 26.041,93.854 v1(26.041,93.029) 26.066,93.004 v1@26.891,93.004 ; 26.041,93.854 SB7.2@26.041,94.004 26.471,94.004 26.916,93.559 v1@26.916,93.004 ; v1@26.891,93.004 v1(26.916,92.979) v1@26.916,93.004 ; v1@26.891,93.004 v1@26.916,93.004
3V3: CN6.1 CN8.7 CN11.16 JP5.1 L2.2 R26.2 R27.2 R28.2 R59.2 R68.2 R69.2 SB2.2 SB6.1 SB18.2 SB19.2 SB24.1 TP1.1 | length 358.9
  Top Layer w0.4: 12.845,85.089 14.501,85.089
  Top Layer w0.45: v1(20.4,33.575) v1(20.4,34.05)
  Top Layer w0.5: CN8.7@10.866,83.819 12.136,85.089 12.845,85.089 ; 14.501,85.089 14.791,85.379 v1(19.166,85.379) v1(19.841,85.379) ; v1(28.966,33.854) L2.2@29.966,33.854 ; v1(29.091,3.779) R68.2@29.091,2.879 v1(29.991,2.879) ; v1(29.966,32.854) L2.2@29.966,33.854 ; v1(29.966,34.854) L2.2@29.966,33.854 ; R59.2@31.066,14.129 v1(31.066,14.779) ; R26.2@33.216,103.179 R27.2@36.616,103.179 39.591,103.179 R28.2@40.141,103.729 41.891,103.729 46.241,108.079 51.85,108.079 ; v1(33.466,3.779) R69.2@33.466,2.879 v1(34.316,2.879) ; v1(52.941,106.779) 52.941,106.988 51.989,107.94 ; 53.45,107.775 53.754,108.079 ; SB2.2@53.891,108.079 53.754,108.079 ; 51.85,108.079 52.128,108.079 ; 51.85,108.079 51.989,107.94 ; 51.989,107.94 52.267,107.94 ; 52.128,108.079 52.267,107.94 ; 52.128,108.079 52.5,108.079 ; 52.267,107.94 52.941,107.266 52.941,107.638 52.5,108.079 ; 52.5,108.079 53.754,108.079
  Top Layer w0.6: SB2.2@53.891,108.079 TP1.1@53.891,109.754
  Top Layer w1: CN11.16@5.786,83.819 CN8.7@10.866,83.819 ; v1(26.241,97.179) v1(26.866,97.179) v1(27.366,97.179) ; JP5.1@37.536,97.154 v1(50.816,97.154) v1(51.866,97.154) v1@51.966,97.154 ; v1(52.941,104.504) v1(52.941,105.129) v1(52.941,106.054) v1(52.941,106.779) ; v1@52.941,106.988 52.941,107.266 53.45,107.775 ; v1@51.966,97.154 52.941,98.129 v1(52.941,97.154) v1@51.966,97.154
  Signal Layer 2 w0.4: v1@20.4,33.7 v1@20.4,33.854
  Signal Layer 2 w0.5: v1(19.166,85.379) v1(19.841,85.379) ; v1@20.4,33.7 v1(20.4,33.575) 20.646,33.575 20.925,33.854 20.729,34.05 v1(20.4,34.05) v1@20.4,33.854 ; v1(26.241,97.179) v1(26.866,97.179) v1(27.366,97.179) ; v1(28.966,33.854) 29.606,34.494 ; v1(28.966,33.854) 29.606,33.854 ; v1(28.966,33.854) 29.606,33.214 ; 29.606,33.214 29.606,33.854 ; 29.606,33.214 v1(29.966,32.854) 29.966,33.9 ; 29.606,33.854 29.92,33.854 29.966,33.9 ; 29.606,33.854 29.606,34.494 ; 29.606,34.494 v1(29.966,34.854) 29.966,33.9
  Signal Layer 2 w0.6: v1(40.525,96.9) v1(40.525,97.4) ; v1(50.816,97.154) v1(51.866,97.154) v1@51.966,97.154 ; v1(52.941,104.504) v1(52.941,105.129) v1(52.941,106.054) v1(52.941,106.779) ; v1@51.966,97.154 v1(52.941,97.154) 52.966,97.179 v1(52.966,98.154) v1@51.966,97.154
  Signal Layer 2 w0.8: v1@20.4,33.854 20.925,33.854 v1(28.966,33.854)
  Signal Layer 2 w1: CN11.16@5.786,83.819 CN8.7@10.866,83.819
  Signal Layer 3 w0.5: v1(19.166,85.379) v1(19.841,85.379)
  Signal Layer 3 w0.6: JP5.1@37.536,97.154 40.271,97.154 ; v1(52.941,106.779) v1(52.941,106.054) v1(52.941,105.129) v1(52.941,104.504) 52.941,98.179 v1(52.966,98.154) ; 40.271,97.154 40.279,97.154 v1(40.525,97.4) 40.771,97.154 40.779,97.154 ; 40.271,97.154 v1(40.525,96.9) 40.779,97.154 ; 40.779,97.154 v1(50.816,97.154) v1(51.866,97.154) v1@51.966,97.154 ; v1@51.966,97.154 v1(52.941,97.154) 52.966,97.179 v1(52.966,98.154) ; v1@51.966,97.154 v1(52.966,98.154)
  Signal Layer 3 w0.8: 19.25,39 17.1,39 16.111,39.989 16.111,49.373 15.425,50.059 15.425,51.45 17.05,53.075 17.05,72.138 16.425,72.763 16.425,74.975 17.25,75.8 17.25,84.429 18.2,85.379 v1(19.166,85.379) v1(19.841,85.379) 20.55,86.088 20.55,88.825 18.841,90.534 18.841,95.325 18.25,95.916 18.25,97.725 19.2,98.675 24.745,98.675 v1(26.241,97.179) v1(26.866,97.179) v1(27.366,97.179) 29.337,99.15 35.54,99.15 JP5.1@37.536,97.154 ; 19.399,39.149 19.2,38.95 ; CN6.1@20.391,40.639 CN6.1@20.391,40.141 ; 28.95,10.024 26.851,10.024 20.391,16.484 20.391,37.759 ; v1(31.066,14.779) 29.85,13.563 29.85,10.75 29.091,9.991 29.091,6.234 ; 19.2,38.95 20.391,38.95 ; 19.2,38.95 CN6.1@20.391,40.141 ; 19.2,38.95 20.391,37.759 ; 20.391,37.759 20.391,38.95 ; 20.391,38.95 CN6.1@20.391,40.141 ; 29.091,5.394 27.235,7.25 28.075,7.25 29.091,6.234 ; 29.091,5.394 v1(29.091,3.779) v1(29.991,2.879) 30.871,2.879 ; 29.091,5.394 29.091,6.234 ; 29.091,6.234 29.525,5.8 ; 29.525,4.825 30.931,3.419 33.106,3.419 ; 29.525,4.825 29.525,4.225 30.871,2.879 ; 29.525,4.825 29.525,5.8 ; 29.525,5.8 29.525,7.554 29.969,7.998 29.969,5.231 31.421,3.779 v1(33.466,3.779) ; 30.871,2.879 32.566,2.879 ; 32.566,2.879 33.106,3.419 ; 32.566,2.879 v1(34.316,2.879) 33.466,3.729 v1(33.466,3.779) ; 33.106,3.419 v1(33.466,3.779)
  Bottom Layer w0.4: 12.845,85.089 14.281,85.089 14.466,84.904
  Bottom Layer w0.45: v1(20.4,33.575) v1(20.4,34.05)
  Bottom Layer w0.5: CN8.7@10.866,83.819 12.136,85.089 12.845,85.089 ; 14.466,84.904 15.191,84.179 17.929,84.179 18.375,84.625 SB24.1@18.375,85.375 18.379,85.379 v1(19.166,85.379) v1(19.841,85.379) ; SB6.1@25.975,95.879 26.95,96.854 ; SB6.1@25.975,95.879 SB6.1@25.941,95.879 25.941,95.929 26.241,96.229 26.241,96.754 ; SB6.1@25.975,95.879 26.554,95.879 27.366,96.691 v1(27.366,97.179) ; 26.241,96.754 26.341,96.854 26.95,96.854 ; 26.241,96.754 v1(26.241,97.179) v1(26.866,97.179) v1@27.275,97.179 ; 26.95,96.854 27.041,96.854 v1(27.366,97.179) ; 26.95,96.854 v1@27.275,97.179 ; v1@27.275,97.179 v1(27.366,97.179) ; 29.219,34.106 v1(28.966,33.854) v1(29.966,32.854) 29.966,33.359 ; 29.219,34.106 v1(29.966,34.854) 29.966,34.37 ; 29.219,34.106 29.461,33.864 ; 29.461,33.864 29.966,34.37 ; 29.461,33.864 29.966,33.359 ; 29.966,33.359 29.966,34.37
  Bottom Layer w0.6: SB19.2@38.291,86.129 SB18.2@39.641,86.129 40.541,87.029 40.541,96.884 v1(40.525,96.9) v1(40.525,97.4)
  Bottom Layer w1: v1(50.816,97.154) v1@50.841,97.154 ; v1(52.941,106.779) v1(52.941,106.054) v1(52.941,105.129) v1(52.941,104.504) 52.941,99.254 ; v1@50.841,97.154 52.941,99.254 ; v1@50.841,97.154 v1(51.866,97.154) ; v1(51.866,97.154) v1@52.941,98.229 ; v1(51.866,97.154) v1(52.941,97.154) v1@52.941,98.229 ; v1@52.941,98.229 52.941,99.254
3V3_STLK: C2.2 C8.2 C9.2 C10.2 C11.2 C14.2 C15.2 C16.2 C17.2 C21.2 C22.2 C23.2 C24.2 C25.2 C27.2 C29.2 C30.2 C31.2 C32.2 C33.2 C34.2 C35.2 C36.2 C37.2 CN2.1 LD4.4 R24.1 U1.1 U7.C1 U7.C5 U7.C6 U7.C7 U7.C8 U7.C9 U7.F3 U7.G3 U7.G13 U7.H13 U7.J12 U7.J13 U7.K4 U7.N8 U7.N9 U7.N10 U7.P1 U7.R1 U9.5 U10.1 X1.4 | length 142.1
  Top Layer w0.15: 23.996,118.924 25.486,118.924 U7.C7@25.816,119.254 25.816,118.634 U7.C6@25.825,118.625 ; 24.016,117.379 24.271,117.634 25.496,117.634 U7.C5@25.816,117.954 ; 24.116,120.229 25.491,120.229 U7.C8@25.816,119.904 ; 24.141,121.529 24.644,121.529 24.836,121.336 24.836,121.059 25.016,120.879 25.491,120.879 U7.C9@25.816,120.554 ; 24.966,124.954 25.091,124.829 25.941,124.829 26.146,124.624 26.146,123.671 26.339,123.479 28.091,123.479 U7.G13@28.416,123.154 ; 25.471,118.916 U7.C6@25.801,118.586 ; 26.791,114.979 26.791,116.131 26.984,116.324 27.436,116.324 U7.F3@27.766,116.654 ; U7.G3@28.416,116.654 28.736,116.334 29.839,116.334 30.036,116.136 30.036,115.209 30.291,114.954 30.291,114.779 ; 28.466,124.904 28.746,124.624 28.746,123.474 U7.H13@29.066,123.154 ; 29.216,124.954 29.396,124.774 29.396,123.474 U7.J13@29.716,123.154 ; U7.J12@29.716,122.504 30.041,122.829 31.144,122.829 31.336,123.021 31.336,124.799 31.341,124.804 ; U7.K4@30.366,117.304 30.686,116.984 30.686,114.759 30.891,114.554 ; U7.N8@32.316,119.904 32.641,119.579 34.041,119.579 ; U7.N9@32.316,120.554 32.641,120.229 34.041,120.229 ; U7.N10@32.316,121.204 32.641,120.879 34.041,120.879
  Top Layer w0.25: U7.P1@32.966,115.354 34.166,114.154 C33.2@34.166,113.854 ; U7.R1@33.616,115.354 33.916,115.354 C34.2@35.416,113.854
  Top Layer w0.3: U1.1@10.616,131.279 C2.2@11.741,131.279 v1(11.741,130.354) ; U10.1@17.416,115.679 17.541,115.554 C27.2@17.541,114.454 ; v1(17.541,113.604) C27.2@17.541,114.454 ; v1(18.391,114.454) C27.2@17.541,114.454 ; v1(22.562,116.083) 22.991,116.512 C25.2@22.991,116.679 23.316,116.679 24.016,117.379 ; v1(22.562,119.225) 22.991,118.796 C21.2@22.991,118.629 23.701,118.629 23.996,118.924 ; v1(22.562,120.8) 22.991,120.371 C16.2@22.991,120.204 23.016,120.229 24.116,120.229 ; v1(22.562,122.05) 22.991,121.621 C14.2@22.991,121.454 23.066,121.529 24.141,121.529 ; C35.2@22.566,113.779 v1(22.566,114.429) ; v1(23.791,125.979) C8.2@24.491,125.979 24.491,125.429 24.966,124.954 ; C36.2@24.016,113.779 v1(24.016,114.429) ; U7.C1@25.816,115.354 25.816,114.929 25.241,114.354 C29.2@25.241,113.854 25.408,113.854 v1(25.837,113.425) ; v1(26.195,126.408) 26.624,125.979 C9.2@26.791,125.979 26.966,125.979 28.041,124.904 28.466,124.904 ; v1(26.616,110.079) C37.2@27.241,110.079 X1.4@28.416,110.079 ; 26.791,114.979 26.491,114.679 C30.2@26.491,113.854 26.658,113.854 v1(27.087,113.425) ; v1(27.47,126.408) 27.899,125.979 C10.2@28.041,125.979 ; C10.2@28.066,125.979 C10.2@28.041,125.979 ; 29.216,124.954 28.741,125.429 28.579,125.429 28.041,125.967 C10.2@28.041,125.979 ; 30.291,114.779 30.291,114.179 C31.2@30.616,113.854 30.783,113.854 v1(31.212,113.425) ; 30.891,114.554 31.086,114.359 31.361,114.359 C32.2@31.866,113.854 32.033,113.854 v1(32.462,113.425) ; R24.1@30.916,110.979 v1(31.541,110.979) ; v1(31.095,126.408) 31.524,125.979 C11.2@31.691,125.979 31.716,125.954 31.716,125.179 31.341,124.804 ; 34.041,119.579 35.141,118.479 C22.2@35.141,118.379 C22.2@35.166,118.354 ; 34.041,120.229 34.541,120.229 C17.2@35.141,119.629 C17.2@35.166,119.604 ; 34.041,120.879 C15.2@35.141,120.879 C15.2@35.166,120.854 ; C33.2@34.166,113.854 34.333,113.854 v1(34.762,113.425) ; C22.2@35.141,118.354 C22.2@35.166,118.354 ; C17.2@35.141,119.604 C17.2@35.166,119.604 ; C15.2@35.141,120.854 C15.2@35.166,120.854 ; C34.2@35.416,113.854 35.583,113.854 v1(36.012,113.425) ; v1(35.595,117.758) 35.166,118.187 C22.2@35.166,118.354 ; v1(35.595,119.008) 35.166,119.437 C17.2@35.166,119.604 ; v1(35.595,120.258) 35.166,120.687 C15.2@35.166,120.854
  Top Layer w0.45: v1(40.816,116.879) C23.2@41.666,116.879 ; v1(41.666,117.729) C23.2@41.666,116.879 ; U9.5@44.191,116.879 C24.2@42.791,116.879 C23.2@41.666,116.879
  Top Layer w0.5: v1(55.391,129.604) 55.391,130.829 55.591,131.029 LD4.4@56.566,131.029 56.541,131.004 v1(56.541,129.604) v1(55.391,129.604)
  Signal Layer 2 w0.5: v1(11.741,130.354) 14.616,130.354 15.071,130.809 CN2.1@17.216,130.809 17.216,128.604 19.846,125.974 25.761,125.974 v1(26.195,126.408) v1(27.47,126.408) v1(31.095,126.408) 33.945,126.408 34.791,127.254 41.316,127.254 41.816,126.754 45.066,126.754 45.411,127.099 51.286,127.099 53.791,129.604 v1(55.391,129.604) v1(56.541,129.604)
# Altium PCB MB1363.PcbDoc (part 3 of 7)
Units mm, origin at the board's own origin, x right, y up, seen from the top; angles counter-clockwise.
Board outline 70 x 133.34 mm, 6 copper layers (Top Layer, Signal Layer 1, Signal Layer 2, Signal Layer 3, Signal Layer 4, Bottom Layer), stack 1.57 mm thick; 355 components, 293 nets, 1446 pads, 1145 vias.

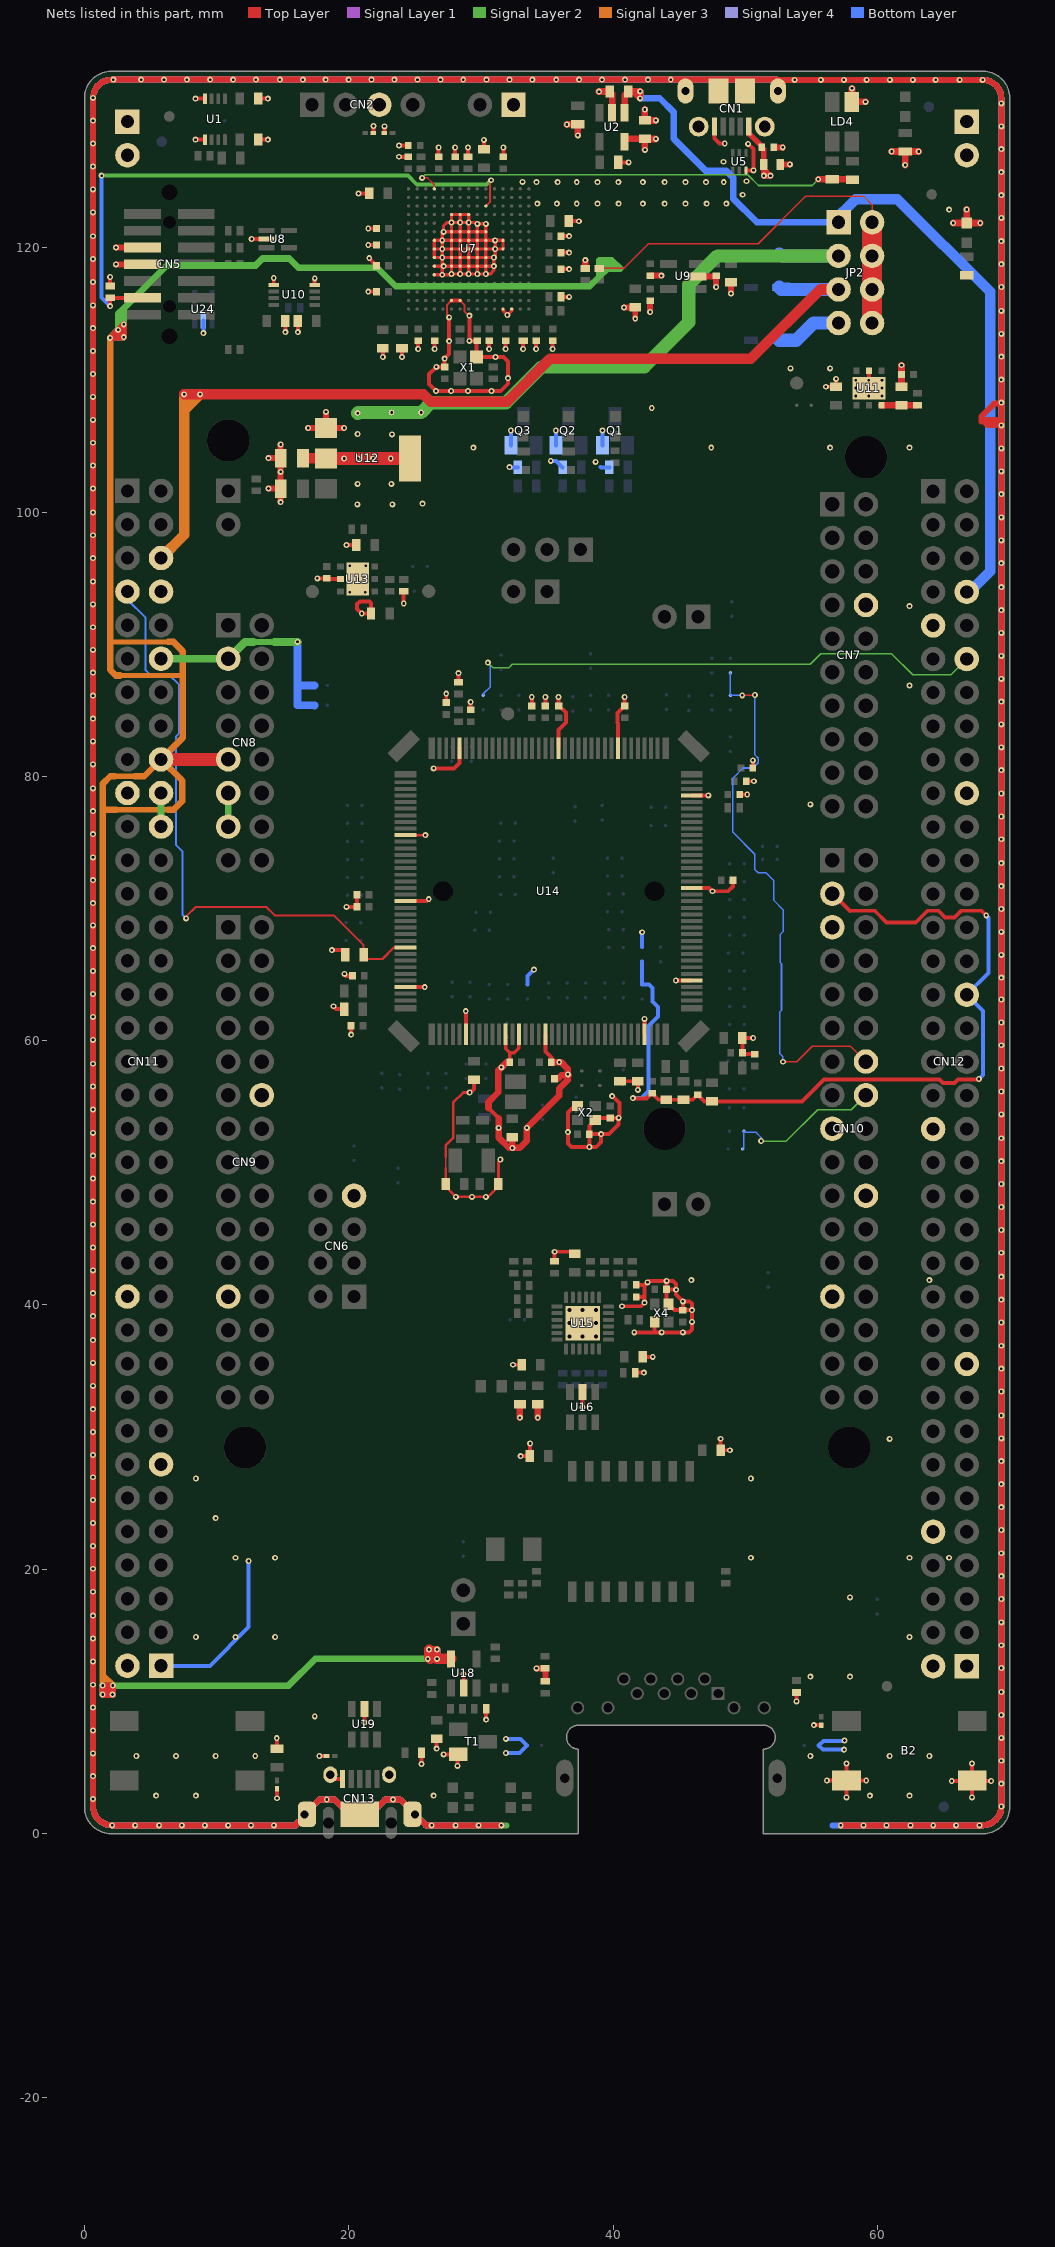
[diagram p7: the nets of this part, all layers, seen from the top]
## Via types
v1: diameter 0.45, hole 0.2, Top Layer to Bottom Layer, tented both sides, 1136 vias
v2: diameter 0.6, hole 0.3, Top Layer to Bottom Layer, tented both sides, 9 vias

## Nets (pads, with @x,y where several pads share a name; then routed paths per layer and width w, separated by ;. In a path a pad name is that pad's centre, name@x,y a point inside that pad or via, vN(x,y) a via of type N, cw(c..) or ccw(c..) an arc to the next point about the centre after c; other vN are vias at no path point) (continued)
5V: C40.2 CN8.9 CN11.18 JP2.2 JP2.4 JP2.6 JP2.8 R12.2 R15.1 R25.2 U11.6 U18.5 | length 319.9
  Top Layer w0.12: R15.1@38.941,118.429 40.791,118.429 42.666,120.304 50.966,120.304 54.566,123.904 58.93,123.904 59.59,123.244 JP2.2@59.59,121.919
  Top Layer w0.45: v1(2.541,113.779) 2.956,114.194 v1(2.966,114.204)
  Top Layer w0.5: v1(1.941,113.179) v1(2.541,113.779) ; v1(2.141,11.204) 2.141,10.554 v1(2.116,10.529) v1(1.366,10.529) ; v1@2.956,114.194 2.966,114.194 2.966,113.804 ; U18.5@27.736,13.229 U18.5@27.741,13.224 ; U11.6@60.298,108.076 61.813,108.076 C40.2@61.816,108.079 R25.2@63.016,108.079 ; v1(1.366,10.529) 2.041,11.204 v1(1.366,11.204) v1(1.366,10.529) ; 2.391,113.229 2.341,113.179 1.954,113.179 2.004,113.229 2.391,113.229 ; 2.391,113.229 v1(2.966,113.229) 2.966,113.804 ; 2.391,113.229 2.966,113.804 ; v1(25.966,13.229) 26.066,13.329 v1(26.666,13.929) ; v1(25.966,13.229) 26.166,13.229 v1(26.666,13.229) v1(26.666,13.929) ; v1(25.966,13.229) 25.966,13.829 v1(26.066,13.929) v1(26.666,13.929)
  Top Layer w0.8: v1(26.066,13.929) 26.066,13.329 v1@26.166,13.229 ; v1(26.666,13.229) U18.5@27.736,13.229
  Top Layer w1: CN11.18@5.786,81.279 CN8.9@10.866,81.279
  Top Layer w1.5: JP2.8@59.59,114.299 JP2.6@59.59,116.839 JP2.4@59.59,119.379 JP2.2@59.59,121.919
  Signal Layer 2 w0.5: v1(1.941,113.179) v1@1.966,113.179 ; v1(26.666,13.229) v1(25.966,13.229) ; 40.541,118.429 40.516,118.429 ; v1@1.466,10.529 v1(2.116,10.529) 2.116,11.179 v1@1.466,10.529 ; v1@1.466,10.529 v1(1.366,10.529) v1(1.366,11.204) v1(2.141,11.204) 15.441,11.204 17.466,13.229 v1(25.966,13.229) ; v1@1.966,113.179 2.916,113.179 v1(2.966,113.229) v1@2.966,113.354 ; v1@1.966,113.179 1.966,113.204 v1(2.541,113.779) ; v1(2.541,113.779) v1@2.966,113.354 ; v1(2.541,113.779) v1(2.966,114.204) ; v1(2.541,113.779) 2.541,114.979 2.966,115.404 ; v1@2.966,113.354 v1(2.966,114.204) ; v1(2.966,114.204) 2.966,115.404 ; 2.966,115.404 6.216,118.654 12.941,118.654 13.466,119.179 15.491,119.179 16.191,118.479 22.141,118.479 23.541,117.079 38.216,117.079 38.941,117.804 ; v1(25.966,13.229) 25.966,13.829 v1(26.066,13.929) ; v1(26.066,13.929) v1(26.666,13.929) 26.666,13.329 v1(26.066,13.929) ; 38.941,117.804 38.941,118.429 ; 38.941,117.804 39.566,118.429 ; 38.941,118.429 38.941,119.054 ; 38.941,118.429 39.566,118.429 ; 38.941,119.054 39.466,119.054 ; 38.941,119.054 39.566,118.429 ; 39.466,119.054 40.091,118.429 ; 39.466,119.054 39.891,119.054 40.516,118.429 ; 39.566,118.429 40.091,118.429 ; 40.091,118.429 40.516,118.429
  Signal Layer 2 w1: CN11.18@5.786,81.279 CN8.9@10.866,81.279
  Signal Layer 2 w1.5: JP2.8@59.59,114.299 JP2.6@59.59,116.839 JP2.4@59.59,119.379 JP2.2@59.59,121.919
  Signal Layer 3 w0.4: 1.941,90.179 1.951,90.169 6.347,90.169 ; 2.286,80.009 3.807,80.009 ; 2.401,77.469 6.347,77.469 ; 2.685,87.629 7.416,87.629 7.441,87.654
  Signal Layer 3 w0.5: 2.286,80.009 1.946,80.009 1.366,79.429 1.366,77.454 ; 2.401,77.469 1.381,77.469 1.366,77.454 ; 2.685,87.629 2.366,87.629 1.941,88.054 1.941,90.179 v1(1.941,113.179) v1@1.991,113.229 ; v1@2.941,113.254 2.541,113.654 v1(2.541,113.779) ; 3.807,80.009 4.516,80.009 CN11.18@5.786,81.279 ; 6.347,77.469 6.731,77.469 7.391,78.129 7.391,79.674 CN11.18@5.786,81.279 ; 6.347,90.169 6.726,90.169 7.416,89.479 7.416,87.629 7.416,82.909 CN11.18@5.786,81.279 ; v1(1.366,11.204) v1(1.366,10.529) v1@1.466,10.529 ; v1(1.366,11.204) v1(2.141,11.204) 1.366,11.979 ; v1(1.366,11.204) 1.366,11.979 ; 1.366,11.979 1.366,77.454 ; v1@1.466,10.529 v1(2.116,10.529) 2.116,11.179 v1@1.466,10.529 ; v1@1.991,113.229 v1(2.541,113.779) ; v1@1.991,113.229 v1(2.966,113.229) v1(2.966,114.204) v1(2.541,113.779) ; v1(26.066,13.929) v1(26.666,13.929) v1@26.666,13.329 ; v1(26.066,13.929) 25.966,13.829 v1(25.966,13.229) v1(26.666,13.229) v1@26.666,13.329 ; v1(26.066,13.929) v1@26.666,13.329
  Signal Layer 3 w1.5: JP2.8@59.59,114.299 JP2.6@59.59,116.839 JP2.4@59.59,119.379 JP2.2@59.59,121.919
  Bottom Layer w0.5: v1(2.141,11.204) v1(1.366,11.204) v1(1.366,10.529) v1@1.491,10.529 ; v1(26.066,13.929) 25.966,13.829 v1(25.966,13.229) v1(26.666,13.229) v1@26.666,13.354 ; v1@1.491,10.529 v1(2.116,10.529) 2.116,11.154 v1@1.491,10.529 ; v1(2.541,113.779) 2.541,113.654 v1(2.966,113.229) ; v1(2.541,113.779) v1(1.941,113.179) 2.916,113.179 v1(2.966,113.229) ; v1(2.541,113.779) v1(2.966,114.204) v1(2.966,113.229) ; v1@26.666,13.354 v1(26.666,13.929) 26.091,13.929 v1@26.666,13.354
  Bottom Layer w1.5: JP2.8@59.59,114.299 JP2.6@59.59,116.839 JP2.4@59.59,119.379 JP2.2@59.59,121.919
5V_EXT: CN11.6 D2.1 JP2.5 | length 73.8
  Top Layer w0.8: v1(7.541,108.904) v1(8.741,108.904) 25.641,108.904 26.191,108.354 31.991,108.354 35.221,111.584 50.421,111.584 55.676,116.839 JP2.5@57.05,116.839
  Signal Layer 3 w0.8: CN11.6@5.786,96.519 7.541,98.274 7.541,107.704 ; 7.541,107.704 v1(7.541,108.904) v1(8.741,108.904) 7.541,107.704
  Bottom Layer w1: D2.1@52.57,117 52.72,116.85 53.245,116.85 53.256,116.839 JP2.5@57.05,116.839
5V_USB_CHGR: C3.2 C6.2 CN1.1 D3.1 JP2.7 R1.2 R2.2 U2.5 U6.1 | length 21
  Top Layer w0.4: U2.5@40.866,128.014 U2.5@40.866,128.229 ; C3.2@42.394,128.229 C3.2@42.396,128.227 ; CN1.1@50.266,129.158 50.266,128.626 51.249,127.643 C6.2@51.249,127.593 51.399,127.443 U6.1@51.399,126.293 U6.1@51.399,125.946 ; U6.1@51.399,125.946 v1(51.399,125.446) v1(51.899,125.446) U6.1@51.399,125.946
  Top Layer w0.5: v1(36.498,129.324) 36.503,129.329 R1.2@37.325,129.329 37.325,128.507 v1(37.33,128.502) ; U2.5@40.866,128.229 C3.2@42.394,128.229 ; v1(42.401,127.401) 42.396,127.406 C3.2@42.396,128.227 43.218,128.227 v1(43.223,128.232) ; v1(61.066,127.279) R2.2@62.091,127.279 ; v1(62.091,126.254) R2.2@62.091,127.279 ; v1(63.116,127.279) R2.2@62.091,127.279
  Signal Layer 1 w0.4: v1@51.416,125.429 51.433,125.446 v1(51.899,125.446)
  Signal Layer 2 w0.4: v1(51.399,125.446) v1(51.899,125.446)
  Signal Layer 3 w0.4: v1(51.399,125.446) v1(51.899,125.446)
  Signal Layer 4 w0.4: v1(51.399,125.446) v1(51.899,125.446)
  Bottom Layer w0.4: v1(51.399,125.446) v1(51.899,125.446)
  Bottom Layer w1: D3.1@52.57,113 53.851,113 55.15,114.299 JP2.7@57.05,114.299
5V_USB_STLK: C1.2 CN12.8 JP2.1 U2.1 | length 64.5
  Top Layer w0.508: U2.1@40.866,130.214 40.866,131.537 C1.2@41.148,131.82 41.525,131.82 ; 41.525,131.82 v1@42.041,131.82 ; 41.525,131.82 v1(42.041,131.304) v1@42.041,131.82 ; v1@42.041,131.82 42.05,131.82 v1(42.041,131.829) v1@42.041,131.82
  Bottom Layer w0.5: v1(42.041,131.304) 43.516,131.304 44.591,130.229 44.591,128.229 47.016,125.804 48.566,125.804 49.071,125.299 49.071,123.724 50.876,121.919 56.586,121.919 JP2.1@57.05,121.919
  Bottom Layer w0.508: v1(42.041,131.304) v1(42.041,131.829)
  Bottom Layer w0.8: JP2.1@56.586,121.919 58.346,123.679 61.491,123.679 68.516,116.654 68.516,95.504 66.966,93.954 CN12.8@66.746,93.954
5V_VIN: C41.2 D1.1 JP2.3 U12.2 U12.4 | length 55.6
  Top Layer w0.8: C41.2@16.541,104.074 U12.2@18.246,104.074
  Top Layer w1: U12.2@18.246,104.074 U12.2@18.266,104.054 v1(19.641,104.054) v1(20.691,104.054) v1(23.166,104.054) U12.4@24.616,104.054
  Signal Layer 2 w1: v1(20.666,107.479) 20.716,107.529 v1(23.241,107.529) v1(25.466,107.529) 26.191,108.254 31.866,108.254 34.591,110.979 42.341,110.979 45.716,114.354 45.716,117.204 47.891,119.379 JP2.3@57.05,119.379
  Bottom Layer w1: D1.1@52.57,119.5 52.695,119.375 53.27,119.375 53.274,119.379 JP2.3@57.05,119.379
  other v1: 20.641,100.579 23.291,100.579 25.566,100.629 20.666,102.129 23.216,102.129 21.841,104.079 23.266,105.879 20.666,105.904
AGND: C69.2 C70.1 C71.1 C72.2 C73.1 CN10.3 CN12.32 SB61.2 SB68.1 | length 67.5
  Top Layer w0.3: v1(41.491,55.654) 41.516,55.629 42.516,55.629 42.916,56.029 C71.1@42.941,56.029 43.441,55.529 C69.2@44.016,55.529 C70.1@45.316,55.529 46.016,55.529 C73.1@46.391,55.904 46.891,55.404 C72.2@47.466,55.404 54.291,55.404 55.961,57.074 64.676,57.074 64.946,56.804 65.821,56.804 66.091,57.074 67.646,57.074 67.666,57.054 v1(67.666,57.104) ; CN10.3@56.586,71.119 57.901,69.804 57.926,69.829 59.791,69.829 60.691,68.929 62.891,68.929 63.791,69.829 64.621,69.829 ; 64.631,69.829 64.621,69.829 ; v1(68.226,69.479) 67.876,69.829 66.321,69.829 66.321,69.819 65.831,69.329 65.121,69.329 64.621,69.829
  Bottom Layer w0.3: v1(41.491,55.654) 42.141,55.654 42.666,56.179 42.666,61.104 43.391,61.829 43.391,62.548 42.975,62.963 42.975,64.001 42.723,64.254 SB68.1@42.191,64.254 SB61.2@42.191,65.979 ; v1(67.666,57.104) 67.966,57.404 67.966,62.254 CN12.32@66.746,63.474 68.391,65.119 68.391,69.314 v1(68.226,69.479) v1@68.241,69.479
ARD_D0_RX: CN10.16 SB94.2 SB96.1 | length 12.5
  Signal Layer 2 w0.12: v1(51.191,52.404) 53.101,52.404 55.471,54.774 58.021,54.774 CN10.16@59.126,55.879
  Bottom Layer w0.12: SB96.1@49.791,51.804 49.891,51.904 SB94.2@49.891,53.154 49.991,53.054 50.816,53.054 51.191,52.68 v1(51.191,52.404)
ARD_D1_TX: CN10.14 SB11.1 SB15.2 | length 42.1
  Top Layer w0.12: v1(49.766,86.129) 50.691,86.129 v1(50.718,86.155) ; v1(52.843,58.404) 53.884,58.404 55.066,59.585 57.96,59.585 CN10.14@59.126,58.419
  Bottom Layer w0.12: SB11.1@48.866,87.829 SB15.2@48.866,86.129 v1(49.766,86.129) ; v1(50.718,86.155) 50.702,86.155 50.696,86.149 50.696,81.647 50.971,81.372 50.971,81.036 50.564,80.629 49.823,80.629 49.06,79.865 49.06,75.771 50.716,74.114 50.716,72.954 50.966,72.704 51.566,72.704 52.161,72.109 52.161,70.609 52.856,69.914 52.856,68.255 52.631,68.03 52.631,65.912 52.733,65.81 52.733,62.287 52.616,62.17 52.616,59.011 52.843,58.784 v1(52.843,58.404)
BOOT0: CN11.7 R36.1 U14.135 | length 47.1
  Top Layer w0.155: v1(7.691,69.254) 7.691,69.404 8.391,70.104 13.766,70.104 14.391,69.479 18.866,69.479 21.116,67.229 R36.1@21.116,66.504 21.441,66.179 22.541,66.179 23.416,67.054 U14.135@24.291,67.054
  Bottom Layer w0.155: CN11.7@3.246,93.979 3.246,93.376 4.616,92.006 4.616,88.023 4.911,87.728 6.353,87.728 7.156,86.926 7.156,83.252 6.909,83.005 6.909,74.813 7.395,74.326 7.395,69.549 v1(7.691,69.254)
GND: B2.3 B2.4 C1.1 C2.1 C3.1 C4.2 C5.1 C6.1 C7.1 C8.1 C9.1 C10.1 C11.1 C12.1 C13.1 C14.1 C15.1 C16.1 C17.1 C18.2 C19.1 C20.1 C21.1 C22.1 C23.1 C24.1 C25.1 C26.2 C27.1 C28.1 C29.1 C30.1 C31.1 C32.1 C33.1 C34.1 C35.1 C36.1 C37.1 C38.2 C39.1 C40.1 C41.1 C42.1 C43.2 C44.2 C45.1 C46.1 C47.1 C48.1 C49.1 C50.1 C51.2 C52.1 C53.2 C54.1 C55.1 C56.1 C57.1 C58.1 C59.1 C60.1 C61.2 C62.2 C63.1 C64.1 C65.1 C66.1 C67.1 C68.1 C74.2 C75.1 C76.2 C77.2 C78.2 C79.1 C80.1 C81.1 C82.1 C83.1 C84.1 C85.2 C86.1 C87.1 C88.1 C89.1 C91.1 CN1.5 CN1.6 CN1.7 CN1.8 CN1.9 CN1.10 CN1.11 CN2.3 CN3.1 CN3.2 CN4.1 CN4.2 CN5.5 CN5.7 CN6.7 CN7.8 CN8.11 CN8.13 CN9.12 CN9.23 CN10.5 CN10.17 CN10.22 CN10.27 CN11.8 CN11.19 CN11.20 CN11.22 CN11.49 CN11.60 CN12.9 CN12.20 CN12.39 CN12.54 CN12.63 CN13.5 CN13.6 CN13.7 CN13.8 CN13.9 CN13.10 CN15.1 CN15.2 CN16.1 CN16.2 JP1.1 LD4.1 LD5.2 Q1.2 Q2.2 Q3.2 R6.1 R7.2 R14.1 R17.1 R18.2 R22.1 R32.1 R33.2 R36.2 R38.2 R45.2 R54.2 R60.1 R61.1 R62.1 R66.1 R67.1 R71.1 R72.1 R73.1 SB61.1 SB74.1 SB101.2 SB102.2 T1.2 U1.4 U1.5 U2.2 U3.2 U4.2 U5.3 U6.2 U7.D5 U7.D6 U7.D7 U7.D8 U7.D9 U7.F2 U7.F6 U7.F7 U7.F8 U7.F9 U7.F10 U7.F12 U7.G2 U7.G6 U7.G7 U7.G8 U7.G9 U7.G10 U7.G12 U7.H6 U7.H7 U7.H8 U7.H9 U7.H10 U7.H12 U7.J6 U7.J7 U7.J8 U7.J9 U7.J10 U7.K6 U7.K7 U7.K8 U7.K9 U7.K10 U7.M1 U7.M8 U7.M9 U7.N1 U8.2 U9.2 U10.4 U10.5 U11.2 U11.EP U12.1 U13.2 U13.EP U14.6 U14.12 U14.14 U14.18 U14.33 U14.41 U14.55 U14.69 U14.80 U14.89 U14.104 U14.118 U14.128 U14.141 U15.EP U16.2 U18.2 U19.2 U20.2 U21.2 U22.2 U23.2 U24.2 X1.2 X2.2 X2.4 X4.2 X4.4 | length 2616.2
  Top Layer w0.12: 27.321,50.354 27.321,51.234
  Top Layer w0.15: v1@27.129,118.604 27.148,118.623 v1@27.15,118.625 ; v1(27.591,114.729) 27.441,114.879 27.441,115.679 U7.F2@27.766,116.004 ; U7.G2@28.416,116.004 28.741,115.679 28.741,115.204 29.091,114.854 v1(29.116,114.854)
  Top Layer w0.2: U14.118@24.291,75.554 v1(25.791,75.554) ; 27.321,50.354 27.321,49.159 C77.2@27.316,49.154 27.316,48.954 v1(28.091,48.179) v1(29.316,48.179) v1(30.366,48.179) 30.541,48.179 31.316,48.954 C78.2@31.316,49.154 31.316,50.854 v1(31.466,51.004) ; 27.321,51.234 27.321,52.059 27.896,52.634 27.896,55.313 28.662,56.079 v1(29.141,56.079) ; 32.091,51.904 32.341,51.904 v1(32.366,51.879)
  Top Layer w0.25: U7.D5@26.466,117.954 v1(27.066,117.954) ; U7.D6@26.466,118.604 v1@27.129,118.604 ; U7.M1@31.666,115.354 31.666,115.229 v1(31.991,114.904) 32.316,115.229 U7.N1@32.316,115.354 ; U14.12@31.866,60.479 31.866,59.379 32.166,59.079 C64.1@32.166,58.379 ; U7.D8@26.466,119.904 U7.D9@26.466,120.554 v1(27.066,120.554) ; U7.D8@26.466,119.904 U7.D7@26.466,119.254 v1(27.066,119.254) ; U7.D8@26.466,119.904 v1(27.066,119.904) ; v1(27.066,117.954) 27.716,117.954 v1(27.766,118.004) ; v1(27.066,117.954) 27.066,118.504 v1(27.166,118.604) ; v1(27.066,119.254) 27.066,118.704 27.148,118.623 v1(27.166,118.604) ; v1(27.066,119.254) v1(27.066,119.904) ; v1(27.066,119.254) U7.F7@27.766,119.254 ; v1(27.066,119.904) v1(27.066,120.554) ; v1(27.066,119.904) U7.F8@27.766,119.904 ; v1(27.066,120.554) 27.066,121.104 v1(27.166,121.204) ; v1(27.066,120.554) U7.F9@27.766,120.554 ; v1(27.166,118.604) U7.F6@27.766,118.604 ; v1(27.166,121.204) 27.166,121.679 27.391,121.904 v1(27.766,121.904) ; v1(27.166,121.204) U7.F10@27.766,121.204 ; v1(27.766,118.004) v1(28.416,118.004) ; v1(27.766,118.004) U7.F6@27.766,118.604 ; U7.F6@27.766,118.604 U7.G6@28.416,118.604 ; U7.F6@27.766,118.604 U7.F7@27.766,119.254 ; U7.F7@27.766,119.254 U7.G7@28.416,119.254 ; U7.F7@27.766,119.254 U7.F8@27.766,119.904 ; U7.F8@27.766,119.904 U7.G8@28.416,119.904 ; U7.F8@27.766,119.904 U7.F9@27.766,120.554 ; U7.F9@27.766,120.554 U7.G9@28.416,120.554 ; U7.F9@27.766,120.554 U7.F10@27.766,121.204 ; U7.F10@27.766,121.204 v1(27.766,121.904) ; U7.F10@27.766,121.204 U7.G10@28.416,121.204 ; v1(27.766,121.904) v1(28.416,121.904) ; v1(27.766,121.904) U7.F12@27.766,122.504 U7.G12@28.416,122.504 ; v1(28.416,118.004) v1(29.066,118.004) ; v1(28.416,118.004) U7.G6@28.416,118.604 ; U7.G6@28.416,118.604 U7.G7@28.416,119.254 ; U7.G6@28.416,118.604 U7.H6@29.066,118.604 ; U7.G7@28.416,119.254 U7.G8@28.416,119.904 ; U7.G7@28.416,119.254 U7.H7@29.066,119.254 ; U7.G8@28.416,119.904 U7.G9@28.416,120.554 ; U7.G8@28.416,119.904 U7.H8@29.066,119.904 ; U7.G9@28.416,120.554 U7.G10@28.416,121.204 ; U7.G9@28.416,120.554 U7.H9@29.066,120.554 ; U7.G10@28.416,121.204 v1(28.416,121.904) ; U7.G10@28.416,121.204 U7.H10@29.066,121.204 ; v1(28.416,121.904) v1(29.066,121.904) ; v1(28.416,121.904) U7.G12@28.416,122.504 ; U7.G12@28.416,122.504 U7.H12@29.066,122.504 v1(29.066,121.904) ; v1(29.066,118.004) v1(29.716,118.004) ; v1(29.066,118.004) U7.H6@29.066,118.604 ; U7.H6@29.066,118.604 U7.H7@29.066,119.254 ; U7.H6@29.066,118.604 U7.J6@29.716,118.604 ; U7.H7@29.066,119.254 U7.H8@29.066,119.904 ; U7.H7@29.066,119.254 U7.J7@29.716,119.254 ; U7.H8@29.066,119.904 U7.H9@29.066,120.554 ; U7.H8@29.066,119.904 U7.J8@29.716,119.904 ; U7.H9@29.066,120.554 U7.H10@29.066,121.204 ; U7.H9@29.066,120.554 U7.J9@29.716,120.554 ; U7.H10@29.066,121.204 v1(29.066,121.904) ; U7.H10@29.066,121.204 U7.J10@29.716,121.204 ; v1(29.066,121.904) 29.616,121.904 v1(29.716,121.804) ; v1(29.716,118.004) v1(30.366,118.004) ; v1(29.716,118.004) U7.J6@29.716,118.604 ; U7.J6@29.716,118.604 U7.J7@29.716,119.254 ; U7.J6@29.716,118.604 U7.K6@30.366,118.604 ; U7.J7@29.716,119.254 U7.J8@29.716,119.904 ; U7.J7@29.716,119.254 U7.K7@30.366,119.254 ; U7.J8@29.716,119.904 U7.K8@30.366,119.904 ; U7.J8@29.716,119.904 U7.J9@29.716,120.554 ; U7.J9@29.716,120.554 U7.K9@30.366,120.554 ; U7.J9@29.716,120.554 U7.J10@29.716,121.204 ; U7.J10@29.716,121.204 U7.K10@30.366,121.204 ; U7.J10@29.716,121.204 v1(29.716,121.804) ; v1(29.716,121.804) v1(30.366,121.804) U7.K10@30.366,121.204 ; v1(30.366,118.004) 30.691,118.004 30.966,118.279 v1(30.966,118.604) ; v1(30.366,118.004) U7.K6@30.366,118.604 ; U7.K6@30.366,118.604 U7.K7@30.366,119.254 ; U7.K6@30.366,118.604 v1(30.966,118.604) ; U7.K7@30.366,119.254 U7.K8@30.366,119.904 ; U7.K7@30.366,119.254 v1(30.966,119.254) ; U7.K8@30.366,119.904 v1(31.066,119.904) ; U7.K8@30.366,119.904 U7.K9@30.366,120.554 ; U7.K9@30.366,120.554 v1(31.066,120.554) ; U7.K9@30.366,120.554 U7.K10@30.366,121.204 ; v1(30.966,118.604) v1(30.966,119.254) ; v1(30.966,119.254) 31.066,119.354 v1(31.066,119.904) ; v1(31.066,119.904) v1(31.066,120.554) ; v1(31.066,119.904) U7.M8@31.666,119.904 U7.M9@31.666,120.554 v1(31.066,120.554)
  Top Layer w0.254: 32.166,59.079 32.516,59.079 32.866,59.429 U14.14@32.866,60.479
  Top Layer w0.3: R17.1@1.941,117.104 v1(1.941,117.779) ; v1(8.391,128.179) U1.5@9.116,128.179 ; v1(8.391,131.279) U1.4@9.116,131.279 ; v1(12.641,120.654) U8.2@13.766,120.654 ; C4.2@13.141,128.179 v1(13.866,128.179) ; C2.1@13.141,131.279 v1(13.866,131.279) ; U10.5@14.316,117.179 v1(14.316,117.704) ; v1(14.541,7.229) 14.566,7.204 R67.1@14.566,6.429 ; v1(14.566,2.679) U23.2@14.566,3.391 ; v1(15.191,113.604) C26.2@15.191,114.454 ; v1(16.141,113.604) C27.1@16.141,114.454 ; U10.4@17.416,117.179 v1(17.416,117.679) ; v1(17.616,94.979) C44.2@18.316,94.979 18.366,94.929 U13.2@19.366,94.929 ; v1(17.766,5.879) U22.2@18.304,5.879 ; CN13.6@18.598,4.464 18.923,4.139 CN13.5@19.523,4.139 ; v1(18.716,66.854) 19.716,66.854 R36.2@19.716,66.504 ; v1(18.841,62.604) 18.841,62.553 19.016,62.379 R38.2@19.666,62.379 ; v1(19.666,65.054) 19.641,65.029 19.766,64.904 C58.1@20.266,64.904 ; v1(19.816,70.129) C57.1@20.616,70.129 C56.1@20.616,71.029 ; v1(19.816,97.504) C43.2@20.566,97.504 ; v1(20.166,60.454) C59.1@20.166,61.129 ; v1@20.791,124.104 C12.1@21.416,124.104 ; v1(21.166,8.404) U19.2@21.166,9.429 ; v1(21.466,116.679) C25.1@22.091,116.679 ; v1(21.466,120.204) C16.1@22.091,120.204 ; v1(21.466,121.454) C14.1@22.091,121.454 ; v1(21.541,119.204) 21.541,119.179 C21.1@22.091,118.629 ; U3.2@21.853,128.679 21.853,129.191 v1(21.866,129.204) ; v1(22.566,111.729) C35.1@22.566,112.379 ; U4.2@22.679,128.679 22.679,129.166 v1(22.691,129.179) ; v1(23.791,126.879) C8.1@24.491,126.879 ; v1(23.791,127.729) C5.1@24.491,127.729 ; v1(24.016,111.729) C36.1@24.016,112.379 ; v1(24.15,93.075) R32.1@24.15,94 ; U14.141@24.291,64.054 v1(25.741,64.054) ; U14.128@24.291,70.554 25.891,70.554 v1(26.042,70.705) ; v1(25.241,112.329) C29.1@25.241,112.954 ; v1(25.491,5.264) U21.2@25.491,6.129 ; v1(26.416,80.604) 27.966,80.604 28.366,81.004 U14.104@28.366,82.129 ; v1(26.491,112.329) C30.1@26.491,112.954 ; v1(26.641,6.429) C91.1@26.641,7.179 ; C9.1@26.791,126.879 v1(26.791,127.579) ; v1(27.166,6.004) T1.2@28.291,6.004 28.216,5.929 v1(28.216,5.129) ; C46.1@27.366,85.579 v1(27.366,86.254) ; v1(27.591,114.729) v1(27.591,112.929) 27.591,111.954 v1(27.241,111.604) C37.1@27.241,110.979 v1(26.616,110.979) 26.066,110.429 26.066,109.679 v1(26.591,109.154) v1(27.741,109.154) v1(29.016,109.154) v1(30.791,109.154) 31.491,109.154 32.041,109.704 v1(32.041,110.129) 32.036,110.134 32.036,111.384 31.691,111.729 v1(31.091,111.729) X1.2@29.666,111.729 29.666,112.904 C28.1@29.716,112.954 v1(29.116,112.954) v1(29.116,114.854) ; U7.F2@27.766,116.004 U7.G2@28.416,116.004 ; C10.1@28.041,126.879 v1(28.041,127.579) ; R33.2@28.291,87.129 v1(28.291,87.804) ; v1(28.666,12.054) 28.691,12.029 U18.2@28.691,11.024 ; v1(28.841,62.229) 28.866,62.254 U14.6@28.866,60.479 ; R6.1@29.016,126.879 v1(29.016,127.579) ; v1(29.141,56.079) 29.216,56.079 29.466,56.329 C63.1@29.466,57.054 ; v1(29.216,85.629) C51.2@29.216,85.029 C51.2@29.233,85.029 ; C7.1@30.216,127.454 v1(30.216,128.154) ; v1(30.391,8.629) R66.1@30.391,9.454 ; 30.564,54.904 31.331,54.136 ; v1(30.616,112.329) C31.1@30.616,112.954 ; C11.1@31.691,126.879 v1(31.691,127.579) ; v1(31.866,112.329) C32.1@31.866,112.954 ; v1(32.416,35.479) C85.2@33.066,35.479 ; v1(32.996,28.566) C88.1@33.696,28.566 33.721,28.591 v1(33.721,29.516) ; v1(33.191,112.329) R22.1@33.191,112.954 ; C47.1@33.839,85.329 v1(33.839,86.004) ; v1(34.166,112.329) C33.1@34.166,112.954 ; U14.18@34.866,60.479 34.866,59.179 35.316,58.729 C65.1@35.316,58.379 ; C48.1@34.866,85.329 v1(34.866,86.004) ; v1(35.416,112.329) C34.1@35.416,112.954 ; R45.2@35.566,43.304 v1(35.566,44.029) 36.741,44.029 36.891,43.879 C79.1@37.091,43.879 ; C68.1@35.566,57.129 C68.1@35.816,57.129 ; U14.89@35.866,82.129 35.866,83.512 36.416,84.062 36.416,84.829 35.916,85.329 C49.1@35.866,85.329 v1(35.866,86.004) ; R18.2@36.041,116.279 v1(36.666,116.279) ; C22.1@36.041,118.379 v1(36.666,118.379) ; C17.1@36.041,119.629 v1(36.666,119.629) ; C15.1@36.041,120.879 v1(36.666,120.879) ; C13.1@36.625,122.025 v1@37.375,122.025 ; X2.4@37.291,55.054 37.066,55.054 36.566,54.554 v1(36.566,53.079) 36.566,52.229 36.841,51.954 v1(38.191,51.954) ; v1(37.691,32.229) U16.2@37.691,33.429 ; v1(39.916,55.804) 39.933,55.804 40.466,55.271 40.466,54.204 v1(40.416,54.154) ; U14.80@40.366,82.129 40.366,84.012 40.316,84.062 40.316,84.796 40.849,85.329 C50.1@40.866,85.329 v1(40.866,86.004) ; R7.2@40.373,126.459 41.161,126.459 v1(41.166,126.454) ; C66.1@40.516,56.929 C67.1@41.866,56.929 v1(41.866,56.279) ; v1(40.666,39.904) 42.091,39.904 v1(42.366,40.179) 42.366,40.629 ; v1(41.591,37.929) 43.141,37.929 ; R54.2@41.666,34.879 v1(42.316,34.879) ; C82.1@41.741,40.604 42.341,40.604 42.366,40.629 ; C80.1@41.741,41.529 42.366,41.529 ; C84.1@42.241,36.079 v1(42.991,36.079) ; U14.33@42.366,60.479 v1(42.366,61.654) ; X4.4@43.141,38.704 43.141,37.929 ; v1(44.741,64.554) U14.41@45.941,64.554 ; U14.55@45.941,71.554 47.241,71.554 47.491,71.304 v1(47.516,71.304) 48.691,71.304 49.066,71.679 C55.1@49.066,72.129 ; U14.69@45.941,78.554 v1@47.202,78.554 ; CN1.5@47.666,129.158 47.666,128.254 48.041,127.879 v1(48.441,127.879) ; v1(48.129,29.879) C89.1@48.129,29.009 v1(48.829,29.009) ; C54.1@49.566,78.629 v1(50.141,78.629) ; U5.3@50.041,125.854 v1(50.616,125.854) 50.616,127.454 v1(50.216,127.854) ; C53.2@50.066,79.629 v1(50.641,79.629) ; C52.1@50.566,80.629 v1(50.566,81.204) ; v1(50.591,60.204) C60.1@49.766,60.204 49.791,60.179 C61.2@49.791,59.079 49.891,58.979 C62.2@50.716,58.979 ; v1(53.866,10.004) R61.1@53.866,10.679 ; v1(55.185,8.21) U20.2@55.748,8.21 ; v1(56.091,109.479) C39.1@56.866,109.479 v1(56.866,110.079) ; v1(56.16,4.023) B2.3@57.653,4.023 ; v1(57.653,2.74) B2.3@57.653,4.023 ; v1(57.653,5.305) B2.3@57.653,4.023 ; v1(59.145,4.023) B2.3@57.653,4.023 ; v1(59.341,109.979) 59.348,109.986 U11.2@59.348,110.676 ; v1(65.616,3.979) B2.4@67.109,3.979 ; v1(67.153,2.74) B2.4@67.153,3.979 ; v1(67.153,5.305) B2.4@67.153,4.023 ; v1(68.602,3.979) B2.4@67.153,3.979 ; v1(38.191,51.954) C76.2@38.191,52.929 ; v1(38.191,51.954) 38.716,51.954 39.091,52.329 v1(39.091,52.929) ; C76.2@38.191,52.929 v1(39.091,52.929) ; C76.2@38.191,52.929 38.191,53.554 X2.2@38.641,54.004 38.791,54.154 C74.2@39.766,54.154 v1(40.416,54.154) ; v1(39.091,52.929) 39.691,52.929 40.416,53.654 v1(40.416,54.154) ; 42.366,40.629 42.366,41.529 ; 42.366,41.529 42.403,41.529 v1(42.591,41.716) 42.703,41.829 v1(44.041,41.829) ; 43.141,37.929 v1(43.666,37.929) v1(45.266,37.929) 45.741,37.929 45.966,38.154 v1(45.966,38.729) v1(45.966,39.604) ; C81.1@44.041,41.179 v1(44.041,41.829) ; C81.1@44.041,41.179 44.741,41.179 v1(44.766,41.154) ; C81.1@44.041,41.179 44.041,40.204 X4.2@44.191,40.054 44.641,39.604 C83.1@45.266,39.604 ; v1(44.041,41.829) 44.516,41.829 44.766,41.579 v1(44.766,41.154) ; v1(44.766,41.154) 44.766,40.779 v1(45.266,40.279) ; C83.1@45.266,39.604 v1(45.266,40.279) ; C83.1@45.266,39.604 v1(45.966,39.604) ; v1(45.266,40.279) 45.791,40.279 45.966,40.104 v1(45.966,39.604) ; B2.4@67.109,3.979 B2.4@67.153,4.023 ; B2.4@67.109,3.979 B2.4@67.153,3.979 ; B2.4@67.153,3.979 B2.4@67.153,4.023 ; 20.625,92.675 20.625,93.025 20.825,93.225 21.575,93.225 21.675,93.125 C45.1@21.675,92.325 v1(20.975,92.325) 20.625,92.675
  Top Layer w0.45: v1(2.381,118.744) CN5.7@4.389,118.744 ; v1(2.381,120.014) CN5.5@4.389,120.014 ; v1@13.921,101.774 C42.1@14.841,101.774 ; v1@13.921,104.074 C41.1@14.841,104.074 ; v1(14.841,100.744) C42.1@14.841,101.774 ; v1(14.841,105.104) C41.1@14.841,104.074 ; v1(16.916,106.354) U12.1@18.266,106.354 ; v1(18.266,107.579) U12.1@18.266,106.354 ; v1(19.641,106.354) U12.1@18.266,106.354 ; v1@31.55,0.625 25.837,0.625 CN13.9@24.998,1.464 23.883,2.579 v1(23.341,2.579) 22.741,2.579 21.626,1.464 CN13.10@20.823,1.464 20.006,1.464 18.891,2.579 v1(18.327,2.579) 17.763,2.579 CN13.8@16.648,1.464 16.648,1.33 15.947,0.629 v1(14.329,0.629) v1(12.591,0.629) v1(10.866,0.629) v1(9.104,0.629) v1(7.366,0.629) v1(5.641,0.629) v1(3.829,0.629) v1(2.091,0.629) cw(c2.091,2.079) 0.641,2.079 v1(0.641,2.616) v1(0.641,4.354) v1(0.641,6.079) v1(0.641,7.804) v1(0.641,9.541) v1(0.641,11.266) v1(0.641,13.029) v1(0.641,14.766) v1(0.641,16.491) v1(0.641,18.304) v1(0.641,20.041) v1(0.641,21.766) v1(0.641,23.504) v1(0.641,25.241) v1(0.641,26.966) v1(0.641,28.654) v1(0.641,30.391) v1(0.641,32.116) v1(0.641,33.879) v1(0.641,35.616) v1(0.641,37.341) v1(0.641,39.154) v1(0.641,40.891) v1(0.641,42.616) v1(0.641,44.354) v1(0.641,46.091) v1(0.641,47.816) v1(0.641,49.566) v1(0.641,51.304) v1(0.641,53.029) v1(0.641,54.791) v1(0.641,56.529) v1(0.641,58.254) v1(0.641,60.066) v1(0.641,61.804) v1(0.641,63.529) v1(0.641,65.266) v1(0.641,67.004) v1(0.641,68.729) v1(0.641,70.404) v1(0.641,72.141) v1(0.641,73.866) v1(0.641,75.629) v1(0.641,77.366) v1(0.641,79.091) v1(0.641,80.904) v1(0.641,82.641) v1(0.641,84.366) v1(0.641,86.104) v1(0.641,87.841) v1(0.641,89.566) v1(0.641,91.279) v1(0.641,93.016) v1(0.641,94.741) v1(0.641,96.504) v1(0.641,98.241) v1(0.641,99.966) v1(0.641,101.779) v1(0.641,103.516) v1(0.641,105.241) v1(0.641,106.979) v1(0.641,108.716) v1(0.641,110.441) v1(0.641,112.179) v1(0.641,113.916) v1(0.641,115.641) v1(0.641,117.404) v1(0.641,119.141) v1(0.641,120.866) v1(0.641,122.679) v1(0.641,124.416) v1(0.641,126.141) v1(0.641,127.879) v1(0.641,129.616) 0.641,131.294 cw(c2.062,131.294) 2.062,132.715 CN1.8@45.441,132.715 ; v1(34.191,12.504) 34.822,12.504 R60.1@34.841,12.523 34.866,12.498 R62.1@34.866,11.529 ; v1(40.816,115.479) C23.1@41.666,115.479 v1(41.666,114.629) ; v1(42.791,115.129) C24.1@42.791,115.979 ; C19.1@42.791,117.879 v1(43.641,117.879) ; CN1.8@45.466,131.858 45.466,132.69 CN1.8@45.441,132.715 ; U9.2@46.391,117.829 47.752,117.829 C20.1@47.794,117.87 v1(47.794,117.02) ; v1(48.916,116.529) C18.2@48.916,117.379 ; C6.1@52.149,127.593 v1(52.83,127.593) ; U6.2@52.649,126.293 53.355,126.293 v1(53.366,126.304) ; v1(57.216,0.625) v1(58.941,0.625) v1(60.678,0.625) v1(62.491,0.625) v1(64.216,0.625) v1(65.954,0.625) v1(67.716,0.625) 67.938,0.625 ccw(c67.938,2.053) v1(69.366,2.053) v1(69.366,3.778) v1(69.366,5.515) v1(69.366,7.253) v1(69.366,8.978) v1(69.366,10.715) v1(69.366,12.528) v1(69.366,14.253) v1(69.366,15.99) v1(69.366,17.753) v1(69.366,19.478) v1(69.366,21.215) v1(69.366,22.979) v1(69.366,24.704) v1(69.366,26.441) v1(69.366,28.179) v1(69.366,29.904) v1(69.366,31.641) v1(69.366,33.454) v1(69.366,35.179) v1(69.366,36.916) v1(69.366,38.679) v1(69.366,40.404) v1(69.366,42.141) v1(69.366,43.954) v1(69.366,45.679) v1(69.366,47.416) v1(69.366,49.154) v1(69.366,50.879) v1(69.366,52.616) v1(69.366,54.429) v1(69.366,56.154) v1(69.366,57.891) v1(69.366,59.654) v1(69.366,61.379) v1(69.366,63.116) v1(69.366,64.766) v1(69.366,66.491) v1(69.366,68.229) v1(69.366,69.966) v1(69.366,71.691) v1(69.366,73.429) v1(69.366,75.241) v1(69.366,76.966) v1(69.366,78.704) v1(69.366,80.466) v1(69.366,82.191) v1(69.366,83.929) v1(69.366,85.654) v1(69.366,87.379) v1(69.366,89.116) v1(69.366,90.854) v1(69.366,92.579) v1(69.366,94.316) v1(69.366,96.129) v1(69.366,97.854) v1(69.366,99.591) v1(69.366,101.354) v1(69.366,103.079) v1(69.366,104.816) v1(69.366,106.554) ; 67.85,106.85 67.85,107.225 67.925,107.3 ; v1@69.35,108.2 68.825,108.2 67.925,107.3 ; v1@69.375,106.575 v1@69.366,106.575 ; C42.1@14.841,101.774 v1(14.841,103.044) C41.1@14.841,104.074 ; CN1.8@45.441,132.715 52.341,132.715 52.352,132.704 v1(53.729,132.704) v1(55.712,132.704) v1(57.449,132.704) v1(59.174,132.704) v1(60.937,132.704) v1(62.674,132.704) v1(64.399,132.704) v1(66.212,132.704) v1(67.949,132.704) cw(c67.949,131.278) 69.375,131.278 69.366,131.269 v1(69.366,130.916) v1(69.366,129.179) v1(69.366,127.454) v1(69.366,125.716) v1(69.366,123.979) v1(69.366,122.254) v1(69.366,120.491) v1(69.366,118.754) v1(69.366,117.029) v1(69.366,115.216) v1(69.366,113.479) v1(69.366,111.754) v1(69.366,110.016) v1(69.366,108.279) v1@69.366,106.575 ; 67.925,107.3 67.925,107 67.95,106.975 ; 67.95,106.975 68.945,106.975 v1@69.345,106.575 ; 67.95,106.975 68.35,106.575 v1@69.345,106.575 ; v1@69.345,106.575 v1(69.366,106.554) ; v1@69.345,106.575 v1@69.366,106.575 ; v1(69.366,106.554) v1@69.366,106.575
  Top Layer w0.5: 30.564,54.904 30.564,55.349 31.307,56.092 31.307,57.745 v1(31.541,57.979) 31.941,58.379 C64.1@32.166,58.379 ; 31.331,54.136 v1(31.331,53.4) 31.331,52.664 32.091,51.904 ; v1@32.341,51.904 v1@32.491,51.904 ; C75.1@32.366,52.679 32.366,52.029 v1@32.491,51.904 ; v1(32.941,31.479) C86.1@32.941,32.479 ; v1(34.291,31.479) C87.1@34.291,32.479 ; C65.1@35.316,58.379 v1(35.916,58.379) 36.055,58.379 36.566,57.868 v1(36.566,57.454) v1@36.566,57.379 ; C68.1@35.816,57.129 36.066,57.379 v1@36.566,57.379 ; v1@36.63,57.379 v1@36.566,57.379 ; R14.1@37.891,118.429 v1(37.891,119.054) ; v1(38.923,131.804) 38.907,131.82 C1.1@39.748,131.82 39.916,131.652 U2.2@39.916,130.214 ; v1(42.391,130.454) 42.396,130.449 C3.1@42.396,129.627 43.218,129.627 v1(43.223,129.632) ; v1(58.066,132.054) LD4.1@58.066,131.029 v1(59.091,131.029) ; C40.1@61.816,109.479 C38.2@61.816,110.404 v1(61.816,111.104) ; v1(65.721,121.869) LD5.2@66.746,121.869 ; v1(66.746,122.894) LD5.2@66.746,121.869 ; v1(67.771,121.869) LD5.2@66.746,121.869 ; v1@32.491,51.904 32.941,51.904 33.466,52.429 v1(33.466,53.406) 35.914,55.854 35.914,56.371 36.566,57.023 v1@36.566,57.379
  Signal Layer 1 w0.45: v1@31.575,0.625 25.837,0.625 CN13.9@24.998,1.464 23.883,2.579 v1(23.341,2.579) 22.741,2.579 21.626,1.464 20.006,1.464 18.891,2.579 v1(18.327,2.579) 17.763,2.579 CN13.8@16.648,1.464 16.648,1.33 15.947,0.629 v1(14.329,0.629) v1(12.591,0.629) v1(10.866,0.629) v1(9.104,0.629) v1(7.366,0.629) v1(5.641,0.629) v1(3.829,0.629) v1(2.091,0.629) cw(c2.091,2.079) 0.641,2.079 v1(0.641,2.616) v1(0.641,4.354) v1(0.641,6.079) v1(0.641,7.804) v1(0.641,9.541) v1(0.641,11.266) v1(0.641,13.029) v1(0.641,14.766) v1(0.641,16.491) v1(0.641,18.304) v1(0.641,20.041) v1(0.641,21.766) v1(0.641,23.504) v1(0.641,25.241) v1(0.641,26.966) v1(0.641,28.654) v1(0.641,30.391) v1(0.641,32.116) v1(0.641,33.879) v1(0.641,35.616) v1(0.641,37.341) v1(0.641,39.154) v1(0.641,40.891) v1(0.641,42.616) v1(0.641,44.354) v1(0.641,46.091) v1(0.641,47.816) v1(0.641,49.566) v1(0.641,51.304) v1(0.641,53.029) v1(0.641,54.791) v1(0.641,56.529) v1(0.641,58.254) v1(0.641,60.066) v1(0.641,61.804) v1(0.641,63.529) v1(0.641,65.266) v1(0.641,67.004) v1(0.641,68.729) v1(0.641,70.404) v1(0.641,72.141) v1(0.641,73.866) v1(0.641,75.629) v1(0.641,77.366) v1(0.641,79.091) v1(0.641,80.904) v1(0.641,82.641) v1(0.641,84.366) v1(0.641,86.104) v1(0.641,87.841) v1(0.641,89.566) v1(0.641,91.279) v1(0.641,93.016) v1(0.641,94.741) v1(0.641,96.504) v1(0.641,98.241) v1(0.641,99.966) v1(0.641,101.779) v1(0.641,103.516) v1(0.641,105.241) v1(0.641,106.979) v1(0.641,108.716) v1(0.641,110.441) v1(0.641,112.179) v1(0.641,113.916) v1(0.641,115.641) v1(0.641,117.404) v1(0.641,119.141) v1(0.641,120.866) v1(0.641,122.679) v1(0.641,124.416) v1(0.641,126.141) v1(0.641,127.879) v1(0.641,129.616) 0.641,131.294 cw(c2.062,131.294) 2.062,132.715 CN1.8@45.441,132.715 ; CN1.8@45.466,131.858 45.466,132.69 CN1.8@45.441,132.715 ; v1(57.216,0.625) v1(58.941,0.625) v1(60.678,0.625) v1(62.491,0.625) v1(64.216,0.625) v1(65.954,0.625) v1(67.716,0.625) 67.938,0.625 ccw(c67.938,2.053) v1(69.366,2.053) v1(69.366,3.778) v1(69.366,5.515) 69.366,5.552 69.375,5.561 69.375,131.278 ccw(c67.949,131.278) v1(67.949,132.704) v1(66.212,132.704) v1(64.399,132.704) v1(62.674,132.704) v1(60.937,132.704) v1(59.174,132.704) v1(57.449,132.704) v1(55.712,132.704) v1(53.729,132.704) 52.352,132.704 52.341,132.715 CN1.8@45.441,132.715
  Signal Layer 2 w0.3: v1(26.042,70.705) v1@26.067,70.679 ; v1(47.202,78.559) v1@47.207,78.554
  Signal Layer 2 w0.45: 31.925,0.625 25.837,0.625 CN13.9@24.998,1.464 23.883,2.579 v1(23.341,2.579) 22.741,2.579 21.626,1.464 20.006,1.464 18.891,2.579 v1(18.327,2.579) 17.763,2.579 CN13.8@16.648,1.464 16.648,1.33 15.947,0.629 v1(14.329,0.629) v1(12.591,0.629) v1(10.866,0.629) v1(9.104,0.629) v1(7.366,0.629) v1(5.641,0.629) v1(3.829,0.629) v1(2.091,0.629) cw(c2.091,2.079) 0.641,2.079 v1(0.641,2.616) v1(0.641,4.354) v1(0.641,6.079) v1(0.641,7.804) v1(0.641,9.541) v1(0.641,11.266) v1(0.641,13.029) v1(0.641,14.766) v1(0.641,16.491) v1(0.641,18.304) v1(0.641,20.041) v1(0.641,21.766) v1(0.641,23.504) v1(0.641,25.241) v1(0.641,26.966) v1(0.641,28.654) v1(0.641,30.391) v1(0.641,32.116) v1(0.641,33.879) v1(0.641,35.616) v1(0.641,37.341) v1(0.641,39.154) v1(0.641,40.891) v1(0.641,42.616) v1(0.641,44.354) v1(0.641,46.091) v1(0.641,47.816) v1(0.641,49.566) v1(0.641,51.304) v1(0.641,53.029) v1(0.641,54.791) v1(0.641,56.529) v1(0.641,58.254) v1(0.641,60.066) v1(0.641,61.804) v1(0.641,63.529) v1(0.641,65.266) v1(0.641,67.004) v1(0.641,68.729) v1(0.641,70.404) v1(0.641,72.141) v1(0.641,73.866) v1(0.641,75.629) v1(0.641,77.366) v1(0.641,79.091) v1(0.641,80.904) v1(0.641,82.641) v1(0.641,84.366) v1(0.641,86.104) v1(0.641,87.841) v1(0.641,89.566) v1(0.641,91.279) v1(0.641,93.016) v1(0.641,94.741) v1(0.641,96.504) v1(0.641,98.241) v1(0.641,99.966) v1(0.641,101.779) v1(0.641,103.516) v1(0.641,105.241) v1(0.641,106.979) v1(0.641,108.716) v1(0.641,110.441) v1(0.641,112.179) v1(0.641,113.916) v1(0.641,115.641) v1(0.641,117.404) v1(0.641,119.141) v1(0.641,120.866) v1(0.641,122.679) v1(0.641,124.416) v1(0.641,126.141) v1(0.641,127.879) v1(0.641,129.616) 0.641,131.294 cw(c2.062,131.294) 2.062,132.715 CN1.8@45.441,132.715 ; CN1.8@45.466,131.858 45.466,132.69 CN1.8@45.441,132.715 ; v1(57.216,0.625) v1(58.941,0.625) v1(60.678,0.625) v1(62.491,0.625) v1(64.216,0.625) v1(65.954,0.625) v1(67.716,0.625) 67.938,0.625 ccw(c67.938,2.053) v1(69.366,2.053) v1(69.366,3.778) v1(69.366,5.515) 69.366,5.552 69.375,5.561 69.375,131.278 ccw(c67.949,131.278) v1(67.949,132.704) v1(66.212,132.704) v1(64.399,132.704) v1(62.674,132.704) v1(60.937,132.704) v1(59.174,132.704) v1(57.449,132.704) v1(55.712,132.704) v1(53.729,132.704) 52.352,132.704 52.341,132.715 CN1.8@45.441,132.715
  Signal Layer 2 w0.5: CN11.22@5.786,76.199 CN11.20@5.786,78.739 ; CN8.13@10.866,76.199 CN8.11@10.866,78.739
  Signal Layer 3 w0.45: 28.65,0.625 25.837,0.625 CN13.9@24.998,1.464 23.883,2.579 v1(23.341,2.579) 22.741,2.579 21.626,1.464 20.006,1.464 18.891,2.579 v1(18.327,2.579) 17.763,2.579 CN13.8@16.648,1.464 16.648,1.33 15.947,0.629 v1(14.329,0.629) v1(12.591,0.629) v1(10.866,0.629) v1(9.104,0.629) v1(7.366,0.629) v1(5.641,0.629) v1(3.829,0.629) v1(2.091,0.629) cw(c2.091,2.079) 0.641,2.079 v1(0.641,2.616) v1(0.641,4.354) v1(0.641,6.079) v1(0.641,7.804) v1(0.641,9.541) v1(0.641,11.266) v1(0.641,13.029) v1(0.641,14.766) v1(0.641,16.491) v1(0.641,18.304) v1(0.641,20.041) v1(0.641,21.766) v1(0.641,23.504) v1(0.641,25.241) v1(0.641,26.966) v1(0.641,28.654) v1(0.641,30.391) v1(0.641,32.116) v1(0.641,33.879) v1(0.641,35.616) v1(0.641,37.341) v1(0.641,39.154) v1(0.641,40.891) v1(0.641,42.616) v1(0.641,44.354) v1(0.641,46.091) v1(0.641,47.816) v1(0.641,49.566) v1(0.641,51.304) v1(0.641,53.029) v1(0.641,54.791) v1(0.641,56.529) v1(0.641,58.254) v1(0.641,60.066) v1(0.641,61.804) v1(0.641,63.529) v1(0.641,65.266) v1(0.641,67.004) v1(0.641,68.729) v1(0.641,70.404) v1(0.641,72.141) v1(0.641,73.866) v1(0.641,75.629) v1(0.641,77.366) v1(0.641,79.091) v1(0.641,80.904) v1(0.641,82.641) v1(0.641,84.366) v1(0.641,86.104) v1(0.641,87.841) v1(0.641,89.566) v1(0.641,91.279) v1(0.641,93.016) v1(0.641,94.741) v1(0.641,96.504) v1(0.641,98.241) v1(0.641,99.966) v1(0.641,101.779) v1(0.641,103.516) v1(0.641,105.241) v1(0.641,106.979) v1(0.641,108.716) v1(0.641,110.441) v1(0.641,112.179) v1(0.641,113.916) v1(0.641,115.641) v1(0.641,117.404) v1(0.641,119.141) v1(0.641,120.866) v1(0.641,122.679) v1(0.641,124.416) v1(0.641,126.141) v1(0.641,127.879) v1(0.641,129.616) 0.641,131.294 cw(c2.062,131.294) 2.062,132.715 CN1.8@45.441,132.715 ; CN1.8@45.466,131.858 45.466,132.69 CN1.8@45.441,132.715 ; v1(57.216,0.625) v1(58.941,0.625) v1(60.678,0.625) v1(62.491,0.625) v1(64.216,0.625) v1(65.954,0.625) v1(67.716,0.625) 67.938,0.625 ccw(c67.938,2.053) v1(69.366,2.053) v1(69.366,3.778) v1(69.366,5.515) 69.366,5.552 69.375,5.561 69.375,131.278 ccw(c67.949,131.278) v1(67.949,132.704) v1(66.212,132.704) v1(64.399,132.704) v1(62.674,132.704) v1(60.937,132.704) v1(59.174,132.704) v1(57.449,132.704) v1(55.712,132.704) v1(53.729,132.704) 52.352,132.704 52.341,132.715 CN1.8@45.441,132.715
  Signal Layer 4 w0.45: v1@31.525,0.625 25.837,0.625 CN13.9@24.998,1.464 23.883,2.579 v1(23.341,2.579) 22.741,2.579 21.626,1.464 20.006,1.464 18.891,2.579 v1(18.327,2.579) 17.763,2.579 CN13.8@16.648,1.464 16.648,1.33 15.947,0.629 v1(14.329,0.629) v1(12.591,0.629) v1(10.866,0.629) v1(9.104,0.629) v1(7.366,0.629) v1(5.641,0.629) v1(3.829,0.629) v1(2.091,0.629) cw(c2.091,2.079) 0.641,2.079 v1(0.641,2.616) v1(0.641,4.354) v1(0.641,6.079) v1(0.641,7.804) v1(0.641,9.541) v1(0.641,11.266) v1(0.641,13.029) v1(0.641,14.766) v1(0.641,16.491) v1(0.641,18.304) v1(0.641,20.041) v1(0.641,21.766) v1(0.641,23.504) v1(0.641,25.241) v1(0.641,26.966) v1(0.641,28.654) v1(0.641,30.391) v1(0.641,32.116) v1(0.641,33.879) v1(0.641,35.616) v1(0.641,37.341) v1(0.641,39.154) v1(0.641,40.891) v1(0.641,42.616) v1(0.641,44.354) v1(0.641,46.091) v1(0.641,47.816) v1(0.641,49.566) v1(0.641,51.304) v1(0.641,53.029) v1(0.641,54.791) v1(0.641,56.529) v1(0.641,58.254) v1(0.641,60.066) v1(0.641,61.804) v1(0.641,63.529) v1(0.641,65.266) v1(0.641,67.004) v1(0.641,68.729) v1(0.641,70.404) v1(0.641,72.141) v1(0.641,73.866) v1(0.641,75.629) v1(0.641,77.366) v1(0.641,79.091) v1(0.641,80.904) v1(0.641,82.641) v1(0.641,84.366) v1(0.641,86.104) v1(0.641,87.841) v1(0.641,89.566) v1(0.641,91.279) v1(0.641,93.016) v1(0.641,94.741) v1(0.641,96.504) v1(0.641,98.241) v1(0.641,99.966) v1(0.641,101.779) v1(0.641,103.516) v1(0.641,105.241) v1(0.641,106.979) v1(0.641,108.716) v1(0.641,110.441) v1(0.641,112.179) v1(0.641,113.916) v1(0.641,115.641) v1(0.641,117.404) v1(0.641,119.141) v1(0.641,120.866) v1(0.641,122.679) v1(0.641,124.416) v1(0.641,126.141) v1(0.641,127.879) v1(0.641,129.616) 0.641,131.294 cw(c2.062,131.294) 2.062,132.715 CN1.8@45.441,132.715 ; CN1.8@45.466,131.858 45.466,132.69 CN1.8@45.441,132.715 ; v1(57.216,0.625) v1(58.941,0.625) v1(60.678,0.625) v1(62.491,0.625) v1(64.216,0.625) v1(65.954,0.625) v1(67.716,0.625) 67.938,0.625 ccw(c67.938,2.053) v1(69.366,2.053) v1(69.366,3.778) v1(69.366,5.515) 69.366,5.552 69.375,5.561 69.375,131.278 ccw(c67.949,131.278) v1(67.949,132.704) v1(66.212,132.704) v1(64.399,132.704) v1(62.674,132.704) v1(60.937,132.704) v1(59.174,132.704) v1(57.449,132.704) v1(55.712,132.704) v1(53.729,132.704) 52.352,132.704 52.341,132.715 CN1.8@45.441,132.715
  Bottom Layer w0.3: CN16.1@5.786,12.699 9.486,12.699 12.416,15.629 v1(12.416,20.629) ; v1(8.991,113.529) U24.2@8.991,114.504 ; v1(31.875,6.1) 32.9,6.1 SB101.2@33.475,6.675 32.975,7.175 v1(31.875,7.175) ; v1(32.15,103.392) 32.157,103.385 R73.1@32.811,103.385 ; Q3.2@32.258,105.047 v1(32.258,106.165) ; SB74.1@33.509,64.253 33.509,64.879 v1(34.009,65.379) ; v1(35.275,103.875) 35.67,103.875 R72.1@36.166,103.379 ; Q2.2@35.666,105.047 v1(35.666,106.165) ; 39.05,103.392 39.057,103.385 R71.1@39.711,103.385 ; Q1.2@39.191,105.047 v1(39.191,106.165) ; SB61.1@42.191,67.079 v1(42.191,68.204) ; v1@57.45,6.375 v1@57.425,6.35 ; v1(57.475,6.35) v1@57.425,6.35 ; v1@57.5,6.35 57.45,6.3 57.375,6.3 v1@57.425,6.35 ; v1@57.5,7.025 55.9,7.025 SB102.2@55.55,6.675 55.875,6.35 v1@57.425,6.35
  Bottom Layer w0.45: v1@31.55,0.625 25.837,0.625 CN13.9@24.998,1.464 23.883,2.579 v1(23.341,2.579) 22.741,2.579 21.626,1.464 20.006,1.464 18.891,2.579 v1(18.327,2.579) 17.763,2.579 CN13.8@16.648,1.464 16.648,1.33 15.947,0.629 v1(14.329,0.629) v1(12.591,0.629) v1(10.866,0.629) v1(9.104,0.629) v1(7.366,0.629) v1(5.641,0.629) v1(3.829,0.629) v1(2.091,0.629) cw(c2.091,2.079) 0.641,2.079 v1(0.641,2.616) v1(0.641,4.354) v1(0.641,6.079) v1(0.641,7.804) v1(0.641,9.541) v1(0.641,11.266) v1(0.641,13.029) v1(0.641,14.766) v1(0.641,16.491) v1(0.641,18.304) v1(0.641,20.041) v1(0.641,21.766) v1(0.641,23.504) v1(0.641,25.241) v1(0.641,26.966) v1(0.641,28.654) v1(0.641,30.391) v1(0.641,32.116) v1(0.641,33.879) v1(0.641,35.616) v1(0.641,37.341) v1(0.641,39.154) v1(0.641,40.891) v1(0.641,42.616) v1(0.641,44.354) v1(0.641,46.091) v1(0.641,47.816) v1(0.641,49.566) v1(0.641,51.304) v1(0.641,53.029) v1(0.641,54.791) v1(0.641,56.529) v1(0.641,58.254) v1(0.641,60.066) v1(0.641,61.804) v1(0.641,63.529) v1(0.641,65.266) v1(0.641,67.004) v1(0.641,68.729) v1(0.641,70.404) v1(0.641,72.141) v1(0.641,73.866) v1(0.641,75.629) v1(0.641,77.366) v1(0.641,79.091) v1(0.641,80.904) v1(0.641,82.641) v1(0.641,84.366) v1(0.641,86.104) v1(0.641,87.841) v1(0.641,89.566) v1(0.641,91.279) v1(0.641,93.016) v1(0.641,94.741) v1(0.641,96.504) v1(0.641,98.241) v1(0.641,99.966) v1(0.641,101.779) v1(0.641,103.516) v1(0.641,105.241) v1(0.641,106.979) v1(0.641,108.716) v1(0.641,110.441) v1(0.641,112.179) v1(0.641,113.916) v1(0.641,115.641) v1(0.641,117.404) v1(0.641,119.141) v1(0.641,120.866) v1(0.641,122.679) v1(0.641,124.416) v1(0.641,126.141) v1(0.641,127.879) v1(0.641,129.616) 0.641,131.294 cw(c2.062,131.294) 2.062,132.715 CN1.8@45.441,132.715 ; CN1.8@45.466,131.858 45.466,132.69 CN1.8@45.441,132.715 ; 56.6,0.625 v1(57.216,0.625) v1(58.941,0.625) v1(60.678,0.625) v1(62.491,0.625) v1(64.216,0.625) v1(65.954,0.625) v1(67.716,0.625) 67.938,0.625 ccw(c67.938,2.053) v1(69.366,2.053) v1(69.366,3.778) v1(69.366,5.515) 69.366,5.552 69.375,5.561 69.375,131.278 ccw(c67.949,131.278) v1(67.949,132.704) v1(66.212,132.704) v1(64.399,132.704) v1(62.674,132.704) v1(60.937,132.704) v1(59.174,132.704) v1(57.449,132.704) v1(55.712,132.704) v1(53.729,132.704) 52.352,132.704 52.341,132.715 CN1.8@45.441,132.715
  other v1: 26.266,0.629 28.079,0.629 29.816,0.629 31.541,0.629 5.417,2.875 8.417,2.875 26.417,2.875 59.417,2.875 62.417,2.875 3.917,5.875 6.917,5.875 9.917,5.875 12.917,5.875 54.917,5.875 60.917,5.875 63.917,5.875 57.5,7.05 17.417,8.875 54.917,11.875 57.917,11.875 8.417,14.875 11.417,14.875 14.417,14.875 62.417,14.875 57.917,17.875 11.417,20.875 14.417,20.875 50.417,20.875 62.417,20.875 65.417,20.875 9.917,23.875 8.417,26.875 50.417,26.875 60.917,29.875 45.917,41.875 63.917,41.875 54.917,77.875 62.417,86.875 62.417,92.875 20.066,93.929 21.241,93.929 20.666,94.929 20.066,95.929 21.266,95.929 13.916,101.779 38.675,103.8 13.916,104.079 29.417,104.875 47.417,104.875 56.417,104.875 62.417,104.875 42.917,107.875 58.341,108.779 59.341,108.779 60.341,108.779 58.341,109.379 59.348,109.376 60.341,109.379 58.341,109.979 60.341,109.979 53.417,110.875 56.417,110.875 37.4,122 65.417,122.875 34.266,123.329 35.741,123.329 37.241,123.329 38.816,123.329 40.416,123.329 42.241,123.329 43.891,123.329 45.466,123.329 47.066,123.329 48.566,123.329 49.791,124.004 20.725,124.1 34.191,124.954 35.791,124.954 37.241,124.954 38.816,124.954 40.391,124.954 42.241,124.954 43.891,124.954 45.466,124.954 47.016,124.954 48.366,124.954 33.141,124.979 50.091,125.029 48.341,126.504 0.641,131.341 2.178,132.716 4.279,132.716 6.016,132.716 7.741,132.716 9.503,132.716 11.241,132.716 12.966,132.716 14.778,132.716 16.516,132.716 18.241,132.716 19.978,132.716 21.716,132.716 23.441,132.716 25.191,132.716 26.929,132.716 28.654,132.716 30.416,132.716 32.153,132.716 33.878,132.716 35.691,132.716 37.429,132.716 39.154,132.716 40.891,132.716 42.628,132.716 44.354,132.716
  other v2: 36.691,37.629 37.691,37.629 38.691,37.629 36.691,38.629 37.691,38.629 38.691,38.629 36.691,39.629 37.691,39.629 38.691,39.629
GNDDetect: CN5.11 R17.2 U7.K13 | length 45.2
  Top Layer w0.15: U7.K13@30.366,123.154 30.691,123.479 30.691,125.029 v1(30.766,125.104)
  Top Layer w0.3: v1(1.941,115.579) R17.2@1.941,116.204 CN5.11@4.389,116.204
  Signal Layer 2 w0.3: v1(1.291,125.454) 24.466,125.454 25.136,124.784 30.396,124.784 30.741,125.129 v1(30.766,125.104)
  Bottom Layer w0.3: v1(1.291,125.454) 1.291,116.229 v1(1.941,115.579)
IOREF: CN8.3 CN11.12 SB14.2 SB24.2 | length 18.2
  Signal Layer 2 w0.45: 12.774,90.169 14.356,90.169
  Signal Layer 2 w0.6: CN11.12@5.786,88.899 CN8.3@10.866,88.899 12.136,90.169 12.774,90.169 ; 14.356,90.169 16.106,90.169 v1(16.116,90.179)
  Bottom Layer w0.6: v1(16.116,90.179) 16.116,88.375 ; 16.12,88.379 16.116,88.375 ; SB24.2@17.4,85.375 17.396,85.379 16.116,85.379 16.116,86.9 ; SB14.2@17.4,86.875 17.396,86.879 16.137,86.879 16.116,86.9 ; 16.116,86.9 16.116,88.375
LED_STLK: R8.2 R9.2 U7.D15 | length 34.7
  Top Layer w0.12: v1(25.541,125.279) 25.952,125.279 26.466,124.764 U7.D15@26.466,124.454 ; R8.2@56.564,125.179 R8.2@56.566,125.177 ; R9.2@58.091,125.177 R9.2@58.116,125.152
  Top Layer w0.5: v1(55.516,125.179) R8.2@56.564,125.179 ; R8.2@56.566,125.177 R9.2@58.091,125.177
  Signal Layer 2 w0.12: v1(25.541,125.279) 25.771,125.509 50.184,125.509 50.989,124.704 55.066,124.704 55.541,125.179 v1(55.516,125.179)
MORPH_R_12: CN12.12 SB23.2 | length 40.8
  Signal Layer 2 w0.12: v1(30.516,88.604) 30.916,88.204 32.091,88.204 32.361,88.474 54.907,88.474 55.702,89.269 61.065,89.269 62.655,87.679 65.043,87.679 65.048,87.674 65.384,87.674 65.389,87.679 65.566,87.679 66.746,88.859 CN12.12@66.746,88.874
  Bottom Layer w0.12: SB23.2@30.166,86.129 30.166,86.239 30.691,86.764 30.691,88.429 v1(30.516,88.604)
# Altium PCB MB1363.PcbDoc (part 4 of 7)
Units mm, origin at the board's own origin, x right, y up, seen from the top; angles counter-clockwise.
Board outline 70 x 133.34 mm, 6 copper layers (Top Layer, Signal Layer 1, Signal Layer 2, Signal Layer 3, Signal Layer 4, Bottom Layer), stack 1.57 mm thick; 355 components, 293 nets, 1446 pads, 1145 vias.

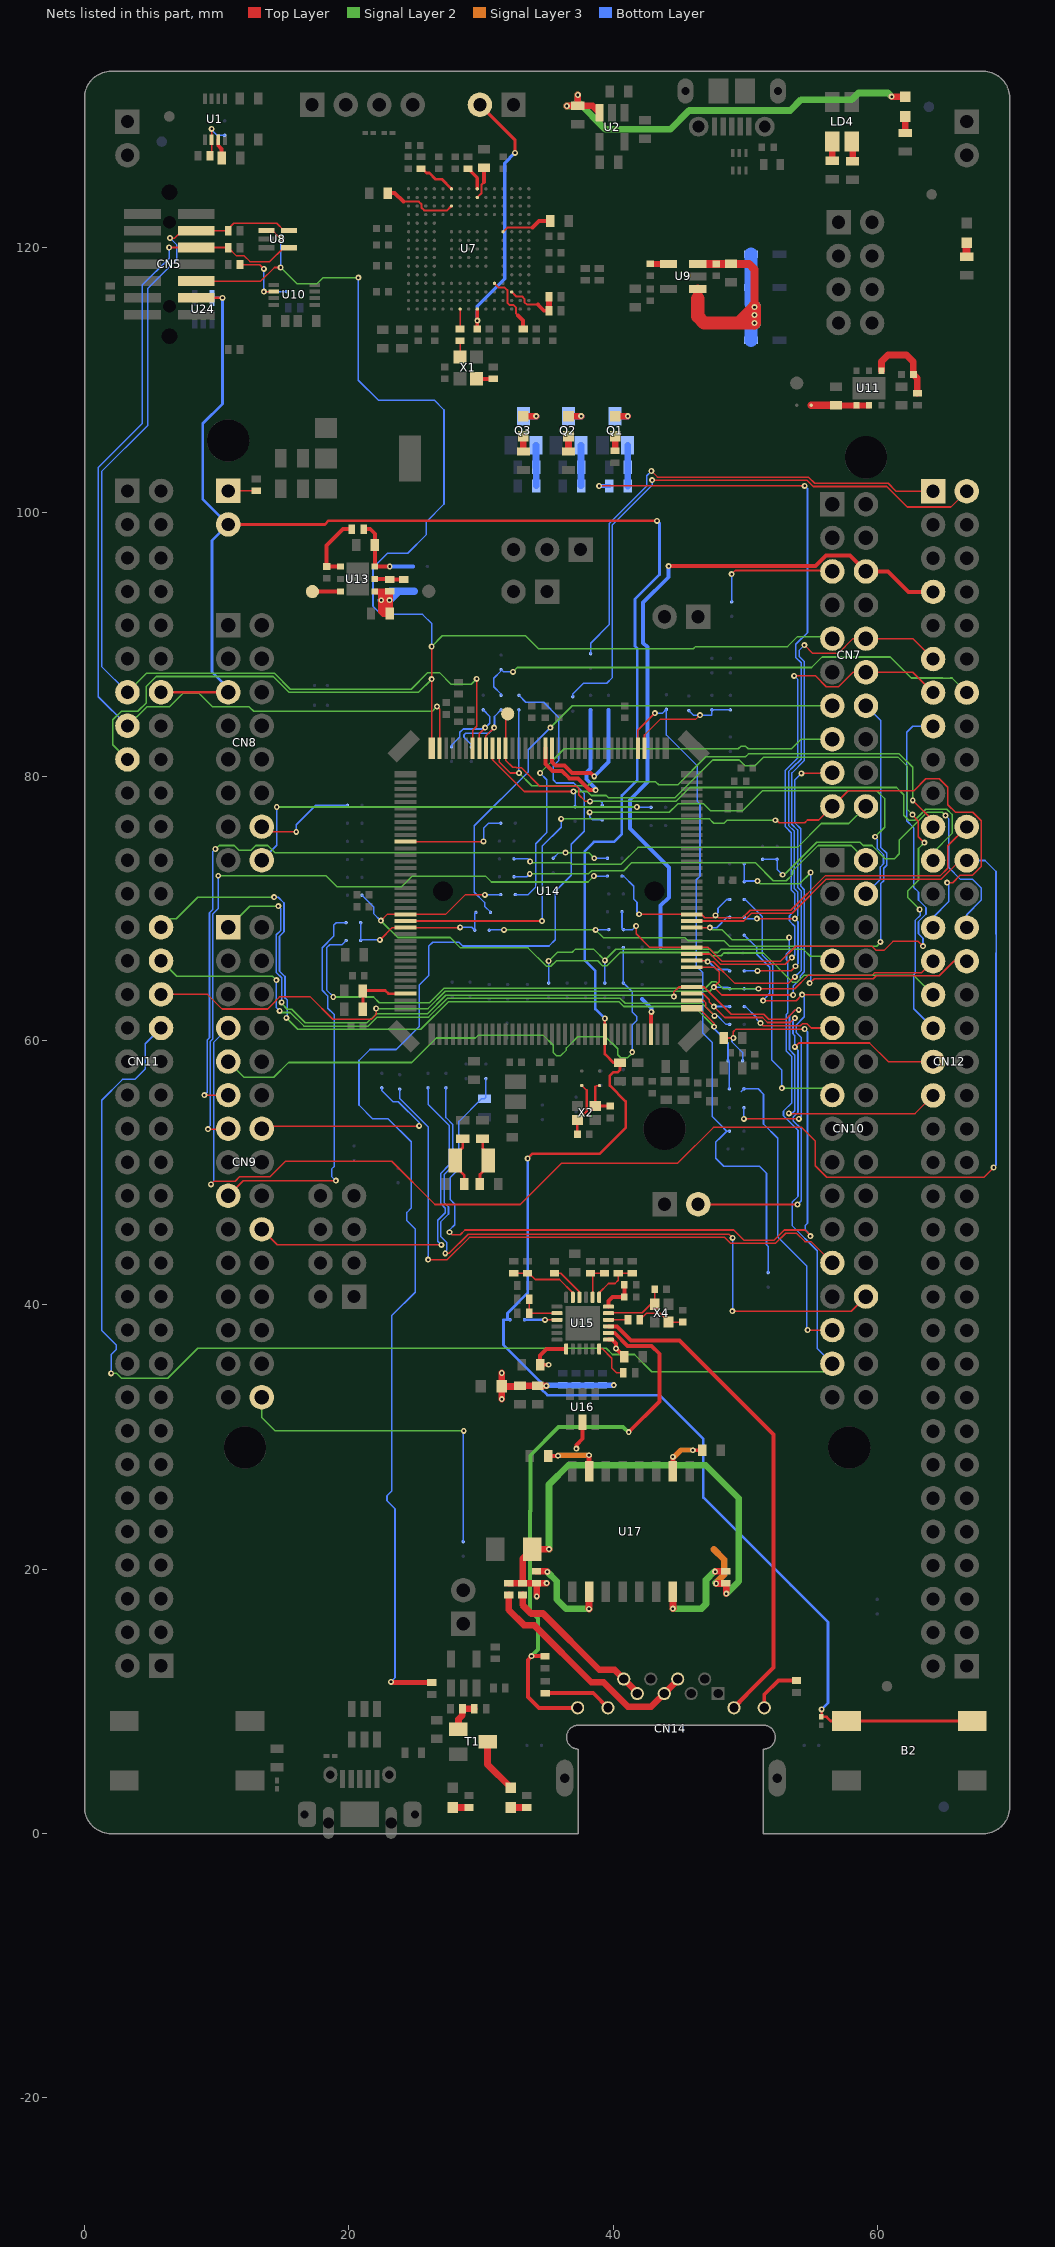
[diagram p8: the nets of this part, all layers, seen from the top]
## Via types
v1: diameter 0.45, hole 0.2, Top Layer to Bottom Layer, tented both sides, 1136 vias
v2: diameter 0.6, hole 0.3, Top Layer to Bottom Layer, tented both sides, 9 vias

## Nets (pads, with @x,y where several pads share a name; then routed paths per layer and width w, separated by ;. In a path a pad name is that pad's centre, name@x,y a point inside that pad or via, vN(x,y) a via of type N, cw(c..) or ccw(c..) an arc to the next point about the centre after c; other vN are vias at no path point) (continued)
MORPH_R_14: CN12.14 SB10.2 SB22.2 | length 39.3
  Signal Layer 2 w0.12: v1(32.416,87.904) 32.746,88.234 55.007,88.234 55.802,89.029 60.966,89.029 62.556,87.439 64.944,87.439 64.949,87.434 65.483,87.434 65.488,87.439 65.641,87.439 CN12.14@66.746,86.334
  Bottom Layer w0.12: SB22.2@31.516,86.129 31.516,86.229 30.966,86.779 30.966,87.429 31.516,87.979 SB10.2@31.516,88.079 31.691,87.904 v1(32.416,87.904)
MORPH_R_28: CN12.28 SB37.2 SB38.2 | length 29.1
  Signal Layer 2 w0.12: v1(52.816,72.554) 52.952,72.554 55.402,75.004 58.676,75.004 58.916,74.764 59.584,74.764 60.574,73.774 61.284,73.774 61.648,74.139 61.648,75.179 63.748,77.279 64.901,77.279 v1(65.141,77.039)
  Bottom Layer w0.12: SB38.2@51.3,73.725 SB37.2@52.4,73.725 52.4,72.97 v1(52.816,72.554) ; v1(65.141,77.039) 65.401,76.779 65.401,73.077 66.279,72.199 67.204,72.199 67.851,71.552 67.851,70.636 66.746,69.531 CN12.28@66.746,68.554
MORPH_R_29: CN12.29 SB59.2 SB77.2 | length 54.1
  Top Layer w0.12: v1(50.991,63.929) 53.741,63.929 54.746,64.934 59.584,64.934 59.799,65.149 63.341,65.149 CN12.29@64.206,66.014
  Signal Layer 2 w0.12: v1(18.816,63.304) 21.871,63.304 22.3,62.875 26.1,62.875 27.198,63.974 46.963,63.974 47.448,64.459 47.784,64.459 48.314,63.929 v1(50.991,63.929)
  Signal Layer 3 w0.12: v1@18.691,63.304 v1(18.816,63.304)
  Bottom Layer w0.12: v1@18.791,63.354 18.311,63.834 18.311,67.022 18.548,67.259 19.471,67.259 SB59.2@19.791,67.579 ; v1(18.816,63.304) v1@18.839,63.304 ; SB77.2@49.916,63.929 v1(50.991,63.929)
MORPH_R_30: CN12.30 SB43.2 SB47.2 | length 27.9
  Top Layer w0.12: v1(54.868,64.354) 55.208,64.694 59.683,64.694 59.898,64.909 64.664,64.909 65.769,66.014 CN12.30@66.746,66.014
  Signal Layer 2 w0.12: v1(50.916,72.079) 51.13,71.865 54.101,71.865 54.941,72.705 v1(54.941,72.729)
  Bottom Layer w0.12: SB43.2@49.916,73.379 SB47.2@49.916,72.029 49.966,72.079 v1(50.916,72.079) ; v1(54.868,64.354) 54.843,64.329 54.816,64.329 54.941,64.454 v1(54.941,72.729)
NetC7_2: C7.2 U7.J14 | length 2.5
  Top Layer w0.15: U7.J14@29.716,123.804 30.036,124.124 30.036,124.774 30.216,124.954
  Top Layer w0.3: 30.216,124.954 C7.2@30.216,126.054
NetC12_2: C12.2 U7.F13 | length 5.6
  Top Layer w0.15: 24.141,123.479 24.146,123.484 25.289,123.484 25.496,123.276 25.496,123.021 25.694,122.824 27.436,122.824 U7.F13@27.766,123.154
  Top Layer w0.3: C12.2@22.975,124.15 22.979,124.154 23.466,124.154 24.141,123.479
NetC13_2: C13.2 U7.M10 | length 3.8
  Top Layer w0.15: U7.M10@31.666,121.204 31.987,121.525 33.9,121.525
  Top Layer w0.3: 33.9,121.525 34.4,122.025 C13.2@35.1,122.025
NetC18_1: C18.1 C20.2 D1.2 D2.2 D3.2 U9.1 U9.3 | length 26
  Top Layer w0.45: C20.2@47.785,118.779 C20.2@47.794,118.77 ; C18.1@48.907,118.77 C18.1@48.916,118.779
  Top Layer w0.6: U9.3@46.391,118.779 C20.2@47.785,118.779 ; C20.2@47.794,118.77 C18.1@48.907,118.77 ; C18.1@48.916,118.779 50.266,118.779 50.691,118.354 v1(50.691,115.504)
  Top Layer w0.7: 46.391,116.154 U9.1@46.391,116.879
  Top Layer w1: 46.391,116.154 46.391,114.804 46.896,114.299 49.486,114.299 ; 49.486,114.299 v1(50.691,115.504) v1(50.691,114.904) v1(50.691,114.299) 49.486,114.299
  Signal Layer 2 w1: v1(50.691,114.299) v1(50.691,114.904) v1(50.691,115.504)
  Signal Layer 3 w1: v1(50.691,114.299) v1(50.691,114.904) v1(50.691,115.504)
  Bottom Layer w1: D3.2@50.43,113 50.43,114.038 v1(50.691,114.299) v1(50.691,114.904) v1(50.691,115.504) 50.43,115.765 D2.2@50.43,117 D1.2@50.43,119.5
NetC19_2: C19.2 U9.4 | length 1.4
  Top Layer w0.45: C19.2@42.791,118.779 U9.4@44.191,118.779
NetC28_2: C28.2 JP1.2 U7.J1 | length 20.1
  Top Layer w0.25: C28.2@29.716,113.854 v1(29.716,114.479) U7.J1@29.716,115.354 ; JP1.2@29.916,130.809 32.566,128.159 v1(32.566,127.179)
  Bottom Layer w0.25: v1(29.716,114.479) 29.716,115.579 31.791,117.654 31.791,126.404 v1(32.566,127.179)
NetC38_1: C38.1 R25.1 U11.1 | length 6
  Top Layer w0.5: U11.1@60.298,110.676 60.298,111.386 60.791,111.879 62.191,111.879 62.716,111.354 C38.1@62.716,110.404 63.016,110.104 R25.1@63.016,108.979
NetC39_2: C39.2 SB2.1 U11.4 U11.5 | length 4.4
  Top Layer w0.45: C39.2@56.866,108.079 56.869,108.076 U11.4@58.398,108.076 U11.5@59.348,108.076
  Top Layer w0.6: SB2.1@54.991,108.079 C39.2@56.866,108.079
NetC43_1: C43.1 R30.1 SB6.2 U13.6 | length 6.3
  Top Layer w0.3: R30.1@21.116,98.704 21.616,98.704 21.966,98.354 C43.1@21.966,97.504 U13.6@21.966,95.879 v1(23.091,95.879)
  Bottom Layer w0.3: v1(23.091,95.879) SB6.2@24.841,95.879
NetC44_1: C44.1 R30.2 U13.1 | length 5.1
  Top Layer w0.3: U13.1@19.366,95.879 C44.1@18.316,95.879 18.316,97.479 19.541,98.704 R30.2@20.216,98.704
NetC45_2: C45.2 R31.1 SB7.1 U13.4 | length 13.2
  Top Layer w0.3: R31.1@23.066,93.979 23.072,93.972 R31.1@23.076,93.969 ; v1@23.075,93.328 v1(23.076,93.33)
  Top Layer w0.45: U13.4@21.966,93.979 22.475,93.979 R31.1@23.066,93.979
  Top Layer w0.5: 22.475,93.979 22.45,93.954 v1(22.45,93.325) ; v1@23.075,93.328 C45.2@23.075,92.325 ; R31.1@23.076,93.969 v1(23.076,93.33) 22.75,93.33 ; R31.1@23.1,94 23.072,93.972 22.75,93.65 22.75,93.33 ; v1(22.45,93.325) 22.45,92.475 22.6,92.325 C45.2@23.075,92.325 ; v1(22.45,93.325) 22.455,93.33 22.75,93.33 ; 22.75,93.33 22.75,92.65 C45.2@23.075,92.325
  Signal Layer 2 w0.45: v1(22.45,93.325) 23.072,93.325 v1(23.076,93.33)
  Signal Layer 3 w0.45: v1(22.45,93.325) 23.072,93.325 v1(23.076,93.33)
  Bottom Layer w0.6: SB7.1@24.941,94.004 23.75,94.004 ; 23.75,94.004 v1(23.076,93.33) 23.072,93.325 v1(22.45,93.325) 23.129,94.004 23.75,94.004
NetC60_2: C60.2 R77.1 SB81.1 SB82.1 | length 66.4
  Top Layer w0.12: v1(27.616,45.504) 27.796,45.323 28.435,45.323 28.785,45.674 49.121,45.674 49.881,44.914 52.187,44.914 52.947,45.674 54.521,45.674 54.918,45.277 v1(54.918,45.203) ; C60.2@48.366,60.204 v1(49.093,60.204) 49.093,60.681 49.291,60.879 v1(54.491,60.879)
  Bottom Layer w0.12: v1(27.616,45.504) 27.616,45.678 28.017,46.079 28.017,47.619 27.682,47.954 27.682,49.665 28.324,50.307 28.324,53.887 30.041,55.604 R77.1@30.266,55.604 30.366,55.704 SB82.1@30.366,57.129 ; v1(49.093,60.204) 48.991,60.204 48.991,59.904 49.791,59.104 SB81.1@49.791,58.479 ; v1(54.491,60.879) 54.701,60.669 54.701,46.187 54.536,46.022 54.536,45.686 54.918,45.304 v1(54.918,45.203)
NetC80_2: C80.2 C82.2 U15.6 | length 2.7
  Top Layer w0.3: U15.6@39.641,39.879 39.641,40.304 39.941,40.604 C82.2@40.841,40.604 C80.2@40.841,41.529
NetC81_2: C81.2 U15.5 X4.3 | length 4.9
  Top Layer w0.12: U15.5@39.641,39.379 39.641,39.409 42.196,39.409 42.841,40.054 X4.3@43.141,40.054 C81.2@43.141,41.179
NetC83_2: C83.2 R53.1 X4.1 | length 3.8
  Top Layer w0.12: R53.1@42.016,38.879 42.516,39.379 43.566,39.379 44.191,38.754 X4.1@44.191,38.704 C83.2@45.266,38.704
NetC84_2: C84.2 C85.1 C86.2 C87.2 C88.2 C89.2 L2.1 R78.2 R79.2 R80.2 R81.2 U15.1 U15.19 U16.5 U17.2 U17.7 | length 25.9
  Top Layer w0.3: C88.2@35.096,28.566 35.121,28.591 v1(35.821,28.591) ; v1(35.116,35.479) C85.1@34.466,35.479 34.466,36.179 34.966,36.679 U15.19@36.441,36.679 ; v1(37.216,29.129) 37.216,29.404 37.691,29.879 U16.5@37.691,31.129 ; U15.1@39.641,37.379 39.916,37.379 40.216,37.079 v1(40.216,36.704) C84.2@40.841,36.079 ; v1(46.029,29.009) C89.2@46.729,29.009
  Top Layer w0.4: v1@38.15,28.575 38.171,28.554 U17.7@38.171,27.434 ; U17.2@44.521,27.434 44.525,27.438 v1@44.525,28.45
  Top Layer w0.5: v1(31.565,32.875) 31.565,33.875 L2.1@31.566,33.874 ; L2.1@31.566,33.854 L2.1@31.566,33.874 ; v1(31.566,34.854) L2.1@31.566,33.874 ; v1(34.941,33.879) C87.2@34.291,33.879 33.021,33.879 32.975,33.832 31.608,33.832 L2.1@31.566,33.874
  Signal Layer 3 w0.4: v1@35.8,28.6 35.829,28.629 v1(38.166,28.629) ; v1(44.516,28.504) 44.604,28.504 45.125,29.025 v1@46.025,29.025
  Bottom Layer w0.4: v1(34.941,33.879) 34.991,33.929 R81.2@36.191,33.929 R80.2@37.191,33.929 R79.2@38.191,33.929 R78.2@39.191,33.929 v1(40.041,33.929)
NetC90_2: C90.2 R55.1 R56.1 R57.1 R58.1 | length 41.6
  Top Layer w0.3: R55.1@34.141,18.904 R55.1@34.191,18.954 R55.1@34.216,18.929 ; R56.1@48.516,18.979 48.566,18.929 R56.1@48.616,18.979
  Top Layer w0.5: R57.1@32.091,18.954 R58.1@33.141,18.954 ; v1(34.216,17.954) R55.1@34.216,18.929 ; v1(34.966,18.954) R55.1@34.191,18.954 R58.1@33.141,18.954 ; v1(35.141,21.529) C90.2@33.866,21.529 33.141,20.804 R58.1@33.141,18.954 ; v1(47.791,18.929) 48.566,18.929 v1(48.566,18.154)
  Signal Layer 2 w0.5: v1(35.141,21.529) 35.141,26.416 36.6,27.875 47,27.875 49.5,25.375 49.5,19.088 v1(48.566,18.154) ; v1@47.775,18.975 47.728,18.975 47.775,18.929 v1(47.791,18.929)
  Signal Layer 3 w0.5: 47.596,21.529 48.4,20.725 48.4,19.6 v1@47.775,18.975
NetCN7_5: CN7.5 SB8.2 | length 9.9
  Top Layer w0.127: v1(48.966,95.304) 49.233,95.57 56.519,95.57 CN7.5@56.586,95.503
  Bottom Layer w0.127: SB8.2@48.966,93.204 v1(48.966,95.304)
NetCN7_6: CN7.6 CN12.7 SB60.1 | length 53.3
  Top Layer w0.3: v1(44.191,95.904) 55.297,95.904 56.091,96.698 57.931,96.698 CN7.6@59.126,95.503 60.792,95.503 62.341,93.954 CN12.7@64.206,93.954
  Bottom Layer w0.3: SB60.1@43.591,67.079 43.591,70.223 44.216,70.848 44.216,73.104 41.266,76.054 41.266,78.229 42.6,79.563 42.6,89.774 42.271,90.103 42.271,93.155 44.18,95.064 44.18,95.893 v1(44.191,95.904)
NetCN7_13: CN7.13 SB53.2 | length 38.9
  Signal Layer 2 w0.12: v1(35.241,83.679) 36.905,85.343 CN7.13@56.586,85.343
  Bottom Layer w0.12: SB53.2@30.716,69.704 30.716,69.729 30.266,70.179 30.266,70.454 29.491,71.229 29.491,76.254 33.566,80.329 33.566,82.004 v1(35.241,83.679)
NetCN7_14: CN7.14 SB56.1 SB57.1 | length 50.2
  Signal Layer 2 w0.12: v1(31.742,68.379) v1(38.667,68.379) 39.268,67.779 45.441,67.779 45.666,67.554 48.391,67.554 48.801,67.144 59.931,67.144 60.216,67.429 v1(60.216,67.479)
  Bottom Layer w0.12: SB57.1@30.616,68.354 30.642,68.379 v1(31.742,68.379) ; v1(38.667,68.379) 38.64,68.379 38.616,68.404 SB56.1@39.666,68.404 ; CN7.14@59.126,85.343 60.231,84.238 60.231,74.639 60.691,74.179 60.691,73.277 60.461,73.047 60.461,72.095 60.231,71.865 v1@60.231,67.479 ; v1(60.216,67.479) v1@60.231,67.479 ; v1@60.231,67.479 60.246,67.479 60.231,67.464 v1@60.231,67.479
NetCN7_15: CN7.15 SB49.2 | length 34.3
  Signal Layer 2 w0.12: v1(34.467,80.255) 36.291,82.079 49.468,82.079 49.673,82.284 50.009,82.284 50.214,82.079 53.491,82.079 54.215,82.803 CN7.15@56.586,82.803
  Bottom Layer w0.12: SB49.2@32.591,71.054 33.566,71.054 34.136,71.624 34.136,74.903 34.981,75.748 34.981,79.741 v1(34.467,80.255)
NetCN7_20: CN7.20 SB41.1 | length 28.7
  Signal Layer 2 w0.12: v1(33.717,73.555) 33.813,73.459 36.759,73.459 36.879,73.339 40.592,73.339 41.872,74.619 53.942,74.619 55.752,76.429 57.832,76.429 CN7.20@59.126,77.723
  Bottom Layer w0.12: SB41.1@32.491,73.754 33.566,73.754 33.717,73.603 v1(33.717,73.555)
NetCN8_14: CN8.14 SB30.1 | length 7.8
  Top Layer w0.12: CN8.14@13.406,76.199 13.801,75.804 v1(16.016,75.804)
  Bottom Layer w0.12: v1(16.016,75.804) 16.016,76.329 17.491,77.804 SB30.1@19.891,77.804
NetCN8_16: CN8.16 SB31.1 | length 32.8
  Signal Layer 2 w0.12: v1(14.541,77.679) v1(41.791,77.679)
  Bottom Layer w0.12: CN8.16@13.406,73.659 14.541,74.794 v1(14.541,77.679) ; v1(41.791,77.679) 41.816,77.654 SB31.1@42.866,77.654
NetCN9_9: CN9.9 SB62.2 SB69.2 | length 43.7
  Signal Layer 2 w0.12: CN9.9@10.866,58.419 12.061,57.224 14.311,57.224 15.437,58.35 24.764,58.35 26.614,60.2 29.575,60.2 29.8,60.425 34.694,60.425 35.461,59.658 35.461,59.111 35.698,58.874 36.034,58.874 36.461,59.301 36.461,59.447 37.318,60.304 39.414,60.304 40.336,59.382 40.336,58.936 40.573,58.699 41.086,58.699 41.441,59.054 v1(41.441,59.129)
  Bottom Layer w0.12: SB62.2@40.766,67.054 SB69.2@40.766,64.354 40.791,64.354 41.446,63.699 41.446,62.174 41.771,61.849 41.771,61.511 41.441,61.181 v1(41.441,59.129)
NetCN9_11: CN9.11 SB39.2 SB40.2 | length 52.3
  Top Layer w0.12: v1(9.066,55.879) CN9.11@10.866,55.879
  Signal Layer 2 w0.12: v1(9.891,74.504) 9.941,74.504 10.201,74.764 11.324,74.764 11.684,74.404 12.588,74.404 12.948,74.764 13.864,74.764 14.399,74.229 v1(36.391,74.229) 38.141,74.229 v1(38.566,73.804)
  Bottom Layer w0.12: v1(9.066,55.879) 9.281,56.094 9.281,60.053 9.451,60.223 9.451,69.678 9.711,69.938 9.711,74.324 v1(9.891,74.504) ; SB39.2@35.466,73.804 35.891,74.229 v1(36.391,74.229) ; v1(38.566,73.804) SB40.2@39.566,73.804
NetCN9_13: CN9.13 SB44.2 | length 51.6
  Top Layer w0.12: v1(9.341,53.304) 10.831,53.304 CN9.13@10.866,53.339
  Signal Layer 2 w0.12: v1(10.116,72.479) 18.266,72.479 19.086,71.659 23.996,71.659 24.791,72.454 30.341,72.454 30.791,72.004 38.091,72.004 v1(38.541,72.454)
  Bottom Layer w0.12: v1(9.341,53.304) 9.291,53.354 9.521,53.584 9.521,59.953 9.691,60.123 9.691,69.579 10.116,70.004 v1(10.116,72.479) ; v1(38.541,72.454) SB44.2@39.566,72.454
NetCN9_14: CN9.14 SB88.1 | length 16.4
  Top Layer w0.12: CN9.14@13.406,53.339 13.406,53.539 25.301,53.539 v1(25.316,53.554)
  Bottom Layer w0.12: SB88.1@22.491,56.429 22.491,56.229 23.341,55.379 23.739,55.379 25.316,53.802 v1(25.316,53.554)
NetCN9_17: CN9.17 SB55.2 | length 29.9
  Top Layer w0.12: CN9.17@10.866,48.259 12.011,49.404 v1(19.016,49.404)
  Bottom Layer w0.12: v1(19.016,49.404) 18.691,49.729 18.691,50.283 18.891,50.483 18.891,61.982 18.411,62.462 18.411,63.384 17.986,63.809 17.986,67.036 18.841,67.891 18.841,68.729 19.041,68.929 SB55.2@19.791,68.929
NetCN9_20: CN9.20 SB86.1 | length 27.4
  Top Layer w0.12: 26.441,44.547 26.447,44.553 v1(26.992,44.553)
  Top Layer w0.127: CN9.20@13.406,45.719 14.578,44.547 26.441,44.547
  Bottom Layer w0.12: SB86.1@25.991,56.429 25.991,55.193 27.604,53.58 27.604,50.605 26.962,49.963 26.962,47.655 27.297,47.321 27.297,46.986 26.722,46.411 26.722,44.822 v1(26.992,44.553)
NetCN9_30: CN9.30 SB99.1 | length 25.6
  Signal Layer 2 w0.12: CN9.30@13.406,33.019 13.406,31.489 14.416,30.479 v1(28.691,30.479)
  Bottom Layer w0.12: SB99.1@28.646,22.089 v1@28.646,30.434
NetCN10_2: CN10.2 SB45.1 | length 29.3
  Signal Layer 2 w0.12: v1(33.686,72.624) 38.138,72.624 38.373,72.859 40.791,72.859 41.391,73.459 50.761,73.459 52.115,72.105 53.091,72.105 53.566,72.58 53.566,72.829 55.501,74.764 58.021,74.764 CN10.2@59.126,73.659
  Bottom Layer w0.12: SB45.1@32.491,72.404 33.466,72.404 v1(33.686,72.624)
NetCN10_4: CN10.4 SB28.1 | length 33.5
  Signal Layer 2 w0.12: v1(38.221,77.274) 44.244,77.274 44.884,77.914 46.844,77.914 47.369,77.389 49.776,77.389 51.305,78.918 59.941,78.918 60.536,78.323 60.536,78.211 60.541,78.206 60.541,76.154 v1(59.816,75.429)
  Bottom Layer w0.12: v1(38.221,77.274) 38.221,76.924 38.441,76.704 SB28.1@39.166,76.704 ; CN10.4@59.126,71.119 60.221,72.214 60.221,73.146 60.451,73.376 60.451,74.079 59.991,74.539 59.991,75.204 59.791,75.404 59.741,75.404 59.736,75.409 59.756,75.429 v1(59.816,75.429)
NetCN10_7: CN10.7 SB70.2 SB73.2 | length 26.5
  Signal Layer 2 w0.12: v1(35.116,66.029) 35.786,66.699 36.909,66.699 37.114,66.904 38.541,66.904 v1(39.366,66.079) 40.198,66.911 47.336,66.911 47.573,66.674 47.909,66.674 48.139,66.904 54.396,66.904 54.916,66.384 56.241,66.384 CN10.7@56.586,66.039
  Bottom Layer w0.12: SB73.2@35.116,64.354 v1(35.116,66.029) ; SB70.2@39.366,64.354 v1(39.366,66.079)
NetCN10_9: CN10.9 SB58.2 SB93.2 | length 26.5
  Top Layer w0.12: v1(49.891,54.079) 54.091,54.079 v1(54.043,54.079) ; v1(54.291,63.479) 56.566,63.479 CN10.9@56.586,63.499
  Top Layer w0.127: v1(51.343,63.029) 53.841,63.029 v1(54.291,63.479)
  Bottom Layer w0.12: v1(49.891,54.079) SB93.2@49.891,54.929 ; v1(54.043,54.079) 54.221,54.257 54.221,60.237 53.846,60.612 53.846,61.188 54.461,61.803 54.461,63.284 54.266,63.479 v1(54.291,63.479)
  Bottom Layer w0.127: SB58.2@49.916,67.979 49.926,67.979 50.857,67.047 50.857,66.545 51.841,65.561 51.841,63.577 51.343,63.078 v1(51.343,63.029)
NetCN10_11: CN10.11 SB78.2 | length 7.6
  Top Layer w0.127: v1(51.141,61.329) 51.347,61.122 54.157,61.122 54.322,61.287 54.66,61.287 54.989,60.959 CN10.11@56.586,60.959
  Bottom Layer w0.127: SB78.2@49.916,62.579 50.016,62.579 50.866,61.729 50.866,61.604 v1(51.141,61.329)
NetCN10_15: CN10.15 SB51.2 | length 19.6
  Signal Layer 2 w0.12: v1(52.766,56.404) 56.061,56.404 CN10.15@56.586,55.879
  Bottom Layer w0.12: SB51.2@49.916,70.679 49.989,70.679 51.271,69.397 51.271,66.476 52.085,65.662 52.085,63.476 51.991,63.382 51.991,58.528 52.766,57.754 v1(52.766,56.404)
NetCN10_25: CN10.25 SB87.2 | length 46.5
  Top Layer w0.12: v1(25.996,43.433) 27.446,43.433 29.122,45.11 48.437,45.11 48.873,44.674 52.286,44.674 53.046,45.434 53.878,45.434 54.513,44.798 54.967,44.798 CN10.25@56.586,43.179
  Bottom Layer w0.12: SB87.2@23.841,56.329 23.841,55.617 25.996,53.462 v1(25.996,43.433)
NetCN10_28: CN10.28 SB85.1 | length 52.2
  Top Layer w0.127: v1(27.291,43.904) 27.572,43.904 29.022,45.354 48.766,45.354 v1(49.041,45.079) ; v1(49.016,39.529) 58.016,39.529 CN10.28@59.126,40.639
  Bottom Layer w0.12: v1(27.291,43.904) 27.291,44.061 27.397,44.167 27.397,44.721 26.962,45.155 26.962,46.312 27.537,46.886 27.537,47.421 27.202,47.755 27.202,49.864 27.844,50.505 27.844,53.68 27.341,54.183 SB85.1@27.341,56.429
  Bottom Layer w0.127: v1(49.016,39.529) 49.041,39.554 v1(49.041,45.079)
NetCN10_29: CN10.29 SB89.2 | length 23.1
  Top Layer w0.12: v1(54.716,38.104) 56.581,38.104 CN10.29@56.586,38.099
  Bottom Layer w0.12: 49.691,56.154 SB89.2@49.891,56.354 50.974,56.354 51.374,55.954 51.374,53.695 52.449,52.62 52.449,45.146 54.641,42.954 54.641,38.104 v1(54.716,38.104)
NetCN12_1: CN12.1 SB9.2 | length 37.7
  Top Layer w0.12: v1(42.891,103.104) 43.351,102.644 54.765,102.644 55.241,102.168 60.806,102.168 61.4,101.574 CN12.1@64.206,101.574
  Bottom Layer w0.12: SB9.2@38.291,89.279 38.291,90.079 39.701,91.489 39.701,99.126 42.538,101.963 42.538,102.75 v1(42.891,103.104)
NetCN12_2: CN12.2 SB20.1 | length 45
  Top Layer w0.12: v1(42.943,102.406) 42.941,102.404 54.666,102.404 55.142,101.928 60.706,101.928 62.255,100.379 65.551,100.379 CN12.2@66.746,101.574
  Bottom Layer w0.12: SB20.1@36.941,86.029 36.941,86.229 37.752,87.04 39.502,87.04 39.941,87.479 39.941,99.027 42.943,102.028 v1(42.943,102.406)
NetCN14_4: CN14.4 CN14.5 R57.2 | length 17.9
  Top Layer w0.5: R57.2@32.091,18.054 32.091,16.929 33.241,15.779 34.016,15.779 38.341,11.454 39.266,11.454 41.116,9.604 42.863,9.604 CN14.5@43.859,10.6 44.879,11.62 CN14.4@44.879,11.7
NetCN14_7: CN14.7 CN14.8 R58.2 | length 12.3
  Top Layer w0.5: R58.2@33.141,18.054 33.141,17.304 33.791,16.654 34.691,16.654 38.941,12.404 40.095,12.404 CN14.8@40.799,11.7 41.819,10.68 CN14.7@41.819,10.6
NetCN14_9: CN14.9 R61.2 | length 3.9
  Top Layer w0.3: CN14.9@51.429,9.52 51.429,10.516 52.491,11.579 R61.2@53.866,11.579
NetCN14_10: CN14.10 U15.3 | length 39
  Top Layer w0.3: U15.3@39.641,38.379 40.291,38.379 41.341,37.329 45,37.329 52.125,30.204 52.125,12.575 CN14.10@49.175,9.625 ; CN14.10@49.139,9.52 50.091,10.472
NetCN14_11: CN14.11 R62.2 | length 5.2
  Top Layer w0.3: R62.2@34.866,10.629 38.489,10.629 CN14.11@39.599,9.52
NetCN14_12: CN14.12 R60.2 U15.2 | length 43.9
  Top Layer w0.3: R60.2@34.841,13.423 34.835,13.429 v1(33.816,13.429) 33.541,13.154 33.541,10.354 34.375,9.52 CN14.12@37.309,9.52 ; U15.2@39.641,37.879 40.116,37.879 41.091,36.904 42.891,36.904 43.486,36.309 43.486,32.711 v1@41.175,30.4
  Signal Layer 2 w0.3: 33.721,24.4 33.721,16.879 34.316,16.284 34.316,13.929 v1(33.816,13.429) ; 33.725,24.4 33.725,28.625 35.869,30.769 40.756,30.769 v1@41.175,30.35
  other v1: 41.175,30.375
NetJP3_1: JP3.1 R29.2 | length 2.1
  Top Layer w0.12: JP3.1@10.866,101.599 10.871,101.604 R29.2@12.991,101.604
NetLD1_1: LD1.1 R28.1 | length 1.1
  Top Layer w0.5: R28.1@40.141,104.629 LD1.1@40.141,105.747
NetLD1_2: LD1.2 Q1.3 | length 1.9
  Top Layer w0.5: LD1.2@40.141,107.247 41.092,107.247 v1(41.099,107.254)
  Bottom Layer w0.5: Q1.3@40.141,107.247 41.092,107.247 v1(41.099,107.254)
NetLD2_1: LD2.1 R27.1 | length 1.2
  Top Layer w0.5: R27.1@36.616,104.579 LD2.1@36.616,105.747
NetLD2_2: LD2.2 Q2.3 | length 1.9
  Top Layer w0.5: LD2.2@36.616,107.247 37.567,107.247 v1(37.574,107.254)
  Bottom Layer w0.5: Q2.3@36.616,107.247 37.567,107.247 v1(37.574,107.254)
NetLD3_1: LD3.1 R26.1 | length 1.2
  Top Layer w0.5: LD3.1@33.208,105.747 33.208,104.587 R26.1@33.216,104.579
NetLD3_2: LD3.2 Q3.3 | length 1.9
  Top Layer w0.5: LD3.2@33.208,107.247 34.159,107.247 v1(34.166,107.254)
  Bottom Layer w0.5: Q3.3@33.208,107.247 34.159,107.247 v1(34.166,107.254)
NetLD4_2: LD4.2 R9.1 | length 1.5
  Top Layer w0.5: LD4.2@58.066,128.029 58.116,127.979 R9.1@58.116,126.552
NetLD4_3: LD4.3 R8.1 | length 1.5
  Top Layer w0.5: R8.1@56.566,126.577 LD4.3@56.566,128.029
NetLD5_1: LD5.1 R12.1 | length 1
  Top Layer w0.6: R12.1@66.746,119.319 LD5.1@66.746,120.369
NetLD6_1: LD6.1 R2.1 | length 1.2
  Top Layer w0.5: R2.1@62.091,128.679 LD6.1@62.091,129.929
NetLD6_2: LD6.2 R1.1 U2.3 | length 31.9
  Top Layer w0.5: v1(36.498,130.724) 36.503,130.729 R1.1@37.325,130.729 ; v1(37.32,131.555) 37.325,131.55 R1.1@37.325,130.729 ; U2.3@38.966,130.214 38.451,130.729 R1.1@37.325,130.729 ; v1(61.066,131.429) LD6.2@62.091,131.429
  Signal Layer 2 w0.5: v1(36.498,130.724) 36.986,130.724 37.32,131.058 ; v1(37.32,131.555) 37.32,131.058 ; v1(61.066,131.429) 60.791,131.704 58.557,131.704 58.057,131.204 54.216,131.204 53.391,130.379 45.741,130.379 44.316,128.954 39.424,128.954 37.32,131.058
NetLD7_1: LD7.1 R68.1 | length 1.2
  Top Layer w0.5: LD7.1@27.866,1.979 R68.1@29.091,1.979
NetLD8_1: LD8.1 R69.1 | length 1.2
  Top Layer w0.5: LD8.1@32.241,1.979 R69.1@33.466,1.979
NetLD8_2: LD8.2 T1.3 | length 4.2
  Top Layer w0.5: T1.3@30.491,6.954 30.491,5.229 LD8.2@32.241,3.479
NetQ1_1: Q1.1 R71.2 R76.2 | length 3.1
  Bottom Layer w0.5: Q1.1@41.091,105.047 41.091,103.405 R71.2@41.111,103.385 41.114,103.382 R76.2@41.114,101.967
NetQ2_1: Q2.1 R72.2 R74.2 | length 3.1
  Bottom Layer w0.5: R74.2@37.566,101.979 R72.2@37.566,103.379 Q2.1@37.566,105.047
NetQ3_1: Q3.1 R73.2 R75.2 | length 3.1
  Bottom Layer w0.5: Q3.1@34.158,105.047 34.158,103.387 R73.2@34.166,103.379 R75.2@34.166,101.979
NetR3_2: R3.2 SB13.2 U1.6 | length 3.3
  Top Layer w0.12: R3.2@9.491,126.954 9.616,127.079 U1.6@9.616,128.179 v1(9.616,128.991)
  Bottom Layer w0.12: v1(9.616,128.991) 9.616,128.9 10.016,128.5 SB13.2@10.6,128.5
NetR4_1: R4.1 U1.7 | length 1.5
  Top Layer w0.3: U1.7@10.116,128.179 10.116,127.729 10.366,127.479 R4.1@10.366,126.779
NetR5_1: R5.1 U7.F15 | length 2.9
  Top Layer w0.2: R5.1@25.466,125.979 25.566,125.979 25.891,125.654 26.086,125.654 26.561,125.179 27.041,125.179 U7.F15@27.766,124.454
NetR6_2: R6.2 U7.J15 | length 1.8
  Top Layer w0.25: R6.2@29.016,125.979 29.716,125.279 U7.J15@29.716,124.454
NetR13_2: R13.2 SB5.2 U10.6 | length 6.1
  Top Layer w0.12: R13.2@11.766,118.729 11.786,118.709 13.261,118.709 v1(13.566,118.404) ; v1(13.566,116.679) U10.6@14.316,116.679
  Bottom Layer w0.12: v1(13.566,118.404) v1(13.566,116.679) SB5.2@15.291,116.679
NetR18_1: R18.1 R20.1 U7.N3 | length 4.6
  Top Layer w0.15: U7.N3@32.316,116.654 32.646,116.324 33.099,116.324 33.286,116.136 33.286,115.881 33.484,115.684 34.296,115.684
  Top Layer w0.3: 34.296,115.684 34.751,115.229 R20.1@35.141,115.229
  Top Layer w0.45: R20.1@35.141,115.229 R18.1@35.141,116.279
NetR21_1: R21.1 X1.3 | length 1.2
  Top Layer w0.12: X1.3@28.416,111.729 R21.1@28.416,112.954
NetR21_2: R21.2 U7.G1 | length 1.5
  Top Layer w0.12: R21.2@28.416,113.854 U7.G1@28.416,115.354
NetR22_2: R22.2 U7.L4 | length 4.8
  Top Layer w0.15: U7.L4@31.016,117.304 31.341,116.979 31.794,116.979 31.991,116.782 31.991,115.829 32.146,115.674 32.449,115.674 32.636,115.486 32.636,115.034 32.791,114.879
  Top Layer w0.3: 32.791,114.879 33.191,114.479 R22.2@33.191,113.854
NetR24_2: R24.2 X1.1 | length 1.3
  Top Layer w0.3: X1.1@29.666,110.079 R24.2@30.916,110.079
NetR31_2: R31.2 R32.2 U13.5 | length 2.2
  Top Layer w0.3: U13.5@21.966,94.929 23.066,94.929 23.095,94.9 R31.2@23.1,94.9 R32.2@24.15,94.9
NetR37_1: R37.1 R38.1 U14.142 | length 4.7
  Top Layer w0.2: R38.1@21.066,62.379 R37.1@21.066,63.753 21.111,63.798 22.75,63.798 22.994,63.554 U14.142@24.291,63.554
NetR43_1: R43.1 R44.2 U15.11 | length 5.4
  Top Layer w0.127: R43.1@32.466,42.404 R44.2@33.516,42.404 33.616,42.404 34.091,41.929 35.941,41.929 36.941,40.929 U15.11@36.941,40.579
NetR45_1: R45.1 U15.10 | length 2.9
  Top Layer w0.127: R45.1@35.566,42.404 36.041,42.404 37.441,41.004 U15.10@37.441,40.579
NetR46_1: R46.1 R47.2 U15.8 | length 2.9
  Top Layer w0.127: U15.8@38.441,40.579 38.441,42.254 R46.1@38.291,42.404 R47.2@39.341,42.404
NetR48_2: R48.2 R49.1 U15.7 | length 3.8
  Top Layer w0.127: U15.7@38.941,40.579 38.941,40.929 39.641,41.629 40.141,41.629 40.391,41.879 R48.2@40.391,42.404 R49.1@41.441,42.404
NetR51_1: R51.1 R52.2 U15.14 | length 3.1
  Top Layer w0.12: R51.1@33.641,40.379 R52.2@33.641,39.379 U15.14@35.741,39.379
NetR53_2: R53.2 U15.4 | length 1.5
  Top Layer w0.12: U15.4@39.641,38.879 R53.2@41.116,38.879
NetR54_1: R54.1 U15.24 | length 3
  Top Layer w0.12: U15.24@38.941,36.679 39.191,36.679 39.891,35.979 39.891,35.229 40.241,34.879 R54.1@40.766,34.879
NetR55_2: R55.2 U17.10 | length 7.2
  Top Layer w0.5: R55.2@34.191,19.854 34.971,19.854 v1@35,19.825 ; U17.10@38.171,18.284 38.171,17.004 v1@38.175,17
  Signal Layer 2 w0.5: v1@35,19.825 35.725,19.1 35.725,17.725 36.446,17.004 v1(38.166,17.004)
  other v1: 35.016,19.804
NetR56_2: R56.2 U17.15 | length 7.5
  Top Layer w0.5: U17.15@44.521,18.284 44.521,17.029 v1@44.525,17.025 ; v1@47.725,19.825 47.754,19.854 R56.2@48.516,19.854
  Signal Layer 2 w0.5: v1(44.516,17.029) 46.679,17.029 47.025,17.375 47.025,19.2 v1@47.675,19.85
  other v1: 47.716,19.829
NetR63_2: R63.2 SB21.2 | length 99.5
  Top Layer w0.12: v1(23.191,11.479) v1@23.241,11.429
  Top Layer w0.4: v1@23.241,11.429 R63.2@26.266,11.429
  Bottom Layer w0.12: v1(23.191,11.479) 23.166,11.479 23.491,11.804 23.491,24.579 22.886,25.184 22.886,25.567 23.251,25.932 23.251,39.203 25.016,40.968 25.016,45.754 24.391,46.379 24.391,47.003 24.722,47.334 24.722,52.346 22.989,54.078 21.814,54.078 20.766,55.127 20.766,58.504 21.591,59.329 23.582,59.329 25.336,61.083 25.336,64.222 26.041,64.927 26.041,67.154 26.341,67.454 28.327,67.454 28.617,67.164 35.149,67.164 35.611,67.626 35.611,71.299 36.821,72.509 36.821,74.859 37.816,75.854 37.816,78.704 37.021,79.499 35.698,79.499 35.461,79.736 35.461,80.774 35.866,81.179 35.866,84.479 34.746,85.599 33.671,85.599 33.666,85.604 33.391,85.604 SB21.2@32.866,86.129
NetR65_2: R65.2 R66.2 T1.1 | length 2.6
  Top Layer w0.5: T1.1@28.291,7.904 28.291,8.654 28.591,8.954 R65.2@28.591,9.454 R66.2@29.491,9.454
NetR76_1: R76.1 SB54.2 SB65.2 | length 62.2
  Top Layer w0.127: v1(38.939,101.967) 38.951,101.979 v1(54.491,101.979) ; v1(50.866,69.229) v1(53.741,69.229) ; v1(50.916,65.279) 53.466,65.279 53.816,65.629 v1(53.793,65.629)
  Bottom Layer w0.12: 53.593,80.679 53.271,80.357 53.271,76.278 53.711,75.838 53.711,71.499 53.974,71.236 53.974,69.462 v1(53.741,69.229)
  Bottom Layer w0.127: SB65.2@49.916,65.279 v1(50.916,65.279) ; SB54.2@49.916,69.329 50.016,69.229 v1(50.866,69.229) ; 53.593,80.679 54.218,81.304 54.218,88.589 53.82,88.987 53.82,89.982 54.698,90.86 54.698,101.772 v1(54.491,101.979) ; v1(53.741,69.229) 53.978,68.992 53.978,65.814 v1(53.793,65.629)
  Bottom Layer w0.3: v1(38.939,101.967) R76.1@39.714,101.967
NetSB15_1: SB15.1 SB16.1 SB103.2 U14.76 | length 9.5
  Top Layer w0.12: U14.76@42.366,82.129 42.366,83.129 43.546,84.309 46.221,84.309 46.541,84.629 v1(46.566,84.629)
  Bottom Layer w0.12: SB103.2@45.725,84.975 46.071,84.629 v1(46.566,84.629) 47.466,84.629 SB16.1@47.466,85.029 SB15.1@48.866,85.029
NetSB17_1: SB17.1 SB94.1 SB104.2 U14.77 | length 52.7
  Top Layer w0.127: U14.77@41.866,82.129 41.866,83.491 v1(43.154,84.779)
  Bottom Layer w0.12: SB17.1@44.025,85.075 44.025,83.12 46.37,80.775 46.37,78.101 46.568,77.903 46.568,72.442 46.292,72.167 46.292,65.627 46.766,65.154 46.766,60.577 47.484,59.858 47.484,54.261 48.091,53.654 48.591,53.154 ; SB94.1@48.791,53.154 48.591,53.154 ; SB104.2@51.725,42.45 51.725,44.427 51.602,44.55 51.602,49.968 51.071,50.499 48.371,50.499 47.766,51.104 47.766,52.329 48.091,52.654 48.591,53.154
  Bottom Layer w0.127: v1(43.154,84.779) 43.729,84.779 SB17.1@44.025,85.075
NetSB18_1: SB18.1 U14.90 | length 10.2
  Top Layer w0.3: U14.90@35.366,82.129 35.366,81.079 35.616,80.829 36.299,80.829 36.884,80.244 38.301,80.244 38.566,79.979 v1(38.566,80.004)
  Bottom Layer w0.3: v1(38.566,80.004) 39.641,81.079 SB18.1@39.641,85.029
NetSB19_1: SB19.1 U14.91 | length 12.3
  Top Layer w0.3: U14.91@34.866,82.129 34.866,80.942 35.399,80.409 36.125,80.409 36.71,79.824 37.321,79.824 38.191,78.954 v1(38.666,78.954)
  Bottom Layer w0.3: SB19.1@38.291,85.029 38.291,80.604 37.966,80.279 37.966,79.779 38.666,79.079 v1(38.666,78.954)
NetSB32_1: SB32.1 U14.119 | length 8.4
  Top Layer w0.12: U14.119@24.291,75.054 30.166,75.054 v1(30.191,75.079)
  Bottom Layer w0.12: v1(30.191,75.079) 30.191,76.079 30.566,76.454 SB32.1@31.491,76.454
NetSB68_2: SB68.2 U14.34 | length 3
  Top Layer w0.3: U14.34@42.866,60.479 42.866,62.154 v1(42.891,62.179)
  Bottom Layer w0.3: SB68.2@42.191,63.154 42.891,62.454 v1(42.891,62.179)
NetSB98_2: SB98.2 U15.15 | length 2.5
  Top Layer w0.12: v1(34.841,38.879) U15.15@35.741,38.879
  Bottom Layer w0.2: SB98.2@33.291,38.879 v1(34.841,38.879)
NetTP3_1: TP3.1 U13.3 | length 2.1
  Top Layer w0.3: TP3.1@17.241,93.979 U13.3@19.366,93.979
NRST: B2.1 B2.2 C66.2 CN5.12 CN8.5 CN11.14 JP3.2 SB98.1 U14.27 U20.1 U24.5 | length 203.1
  Top Layer w0.2: CN11.14@5.786,86.359 CN8.5@10.866,86.359 ; CN5.12@8.453,116.204 v1(10.441,116.204) ; JP3.2@10.866,99.059 18.176,99.059 18.466,99.349 43.296,99.349 v1(43.316,99.329) ; v1(33.529,51.085) 33.898,51.454 38.991,51.454 40.941,53.404 40.941,55.408 39.741,56.608 39.741,57.354 39.991,57.604 40.341,57.604 40.516,57.779 C66.2@40.516,58.329 40.016,58.329 39.366,58.979 U14.27@39.366,60.479 v1(39.366,61.679) ; v1(55.766,9.404) 55.766,8.853 U20.1@55.748,8.835 56.135,8.835 56.447,8.523 B2.1@57.653,8.523 B2.2@67.153,8.523
  Bottom Layer w0.2: U24.5@9.641,116.204 v1(10.441,116.204) 10.441,108.179 8.941,106.679 8.941,100.984 JP3.2@10.866,99.059 9.641,97.834 9.641,87.904 10.866,86.679 CN8.5@10.866,86.359 ; 32,38.9 32,39.375 33.529,40.904 v1(33.529,51.085) ; SB98.1@32.191,38.879 31.7,38.879 31.7,36.975 34.496,34.179 34.496,33.695 35.016,33.175 43.5,33.175 46.825,29.85 46.825,25.421 53.441,18.805 53.445,18.805 56.25,16 56.25,9.888 v1(55.766,9.404) ; v1(39.366,61.679) 38.646,62.399 38.646,65.274 37.849,66.071 37.849,74.338 38.549,75.037 40.049,75.037 40.649,75.638 40.649,78.551 41.825,79.727 41.825,89.676 41.654,89.847 41.654,93.411 43.499,95.256 43.499,99.146 v1(43.316,99.329)
OSC32_IN: C77.1 R41.2 X3.2 | length 4
  Top Layer w0.12: X3.2@27.966,50.579 27.966,50.857 X3.2@28.041,50.932 X3.2@28.041,51.329
  Top Layer w0.2: X3.2@27.966,50.579 28.716,49.829 C77.1@28.716,49.154 ; X3.2@28.041,51.329 28.616,51.904 R41.2@28.616,52.579
OSC32_OUT: C78.1 R42.1 X3.1 | length 3.9
  Top Layer w0.12: X3.1@30.541,50.504 X3.1@30.541,50.932
  Top Layer w0.2: C78.1@29.916,49.154 29.916,49.879 X3.1@30.541,50.504 ; R42.1@30.116,52.579 30.116,51.884 30.541,51.459 X3.1@30.541,50.932
OSC_IN: C76.1 SB3.2 X2.1 | length 4.2
  Top Layer w0.12: X2.1@37.291,54.004 X2.1@37.296,54.004 ; SB3.2@37.616,56.604 37.996,56.224
  Top Layer w0.2: C76.1@37.291,52.929 X2.1@37.291,54.004 ; X2.1@37.296,54.004 37.352,54.004 37.996,54.648 37.996,56.224
OSC_OUT: C74.1 SB4.2 X2.3 | length 2.9
  Top Layer w0.12: 38.641,56.504 38.741,56.604 SB4.2@38.966,56.604
  Top Layer w0.2: 38.641,56.504 X2.3@38.641,55.054 C74.1@39.766,55.054
PA0: CN11.28 SB81.2 SB89.1 U14.37 | length 61.5
  Top Layer w0.127: U14.37@45.941,62.454 46.491,62.454 47.641,61.304 v1(47.641,61.054)
  Signal Layer 2 w0.127: CN11.28@5.786,68.579 6.428,69.22 6.95,69.22 7.358,69.628 7.358,69.648 8.563,70.854 v1(14.341,70.854) ; v1(15.266,61.729) 16.133,60.862 20.335,60.862 20.344,60.854 25.441,60.854 27.54,62.953 40.437,62.953 40.802,62.587 46.107,62.587 v1(47.641,61.054)
  Bottom Layer w0.127: v1(14.341,70.854) 14.657,70.854 15.092,70.419 15.092,68.243 14.754,67.905 14.754,65.26 15.16,64.855 15.16,63.238 15.325,63.073 15.325,61.788 v1(15.266,61.729) ; v1(47.641,61.054) 47.641,60.904 48.691,59.854 SB81.2@48.691,58.479 48.791,58.379 SB89.1@48.791,56.354
PA1: CN11.30 SB80.1 U14.38 | length 50.4
  Top Layer w0.12: U14.38@45.941,63.054 46.816,63.054 47.016,62.854 47.016,62.529 v1(47.666,61.879)
  Signal Layer 2 w0.12: CN11.30@5.786,66.039 5.806,66.039 6.976,64.869 14.221,64.869 v1(14.511,64.579) ; v1(14.766,62.254) 14.886,62.134 15.572,62.134 16.6,61.106 21.47,61.106 22.148,61.784 26.027,61.784 27.439,63.196 40.537,63.196 40.903,62.831 46.714,62.831 v1(47.666,61.879)
  Bottom Layer w0.12: v1(14.511,64.579) 14.511,62.509 v1(14.766,62.254) ; v1(47.666,61.879) 47.891,61.879 48.541,61.229 SB80.1@48.816,61.229
PA2: CN12.35 JP7.2 SB78.1 U14.39 | length 43.7
  Top Layer w0.12: JP7.2@46.426,47.624 46.446,47.604 v1(53.941,47.604)
  Top Layer w0.127: U14.39@45.941,63.554 46.816,63.554 47.266,63.104 47.266,62.929 v1(47.616,62.579) 48.441,61.754 51.294,61.754 51.678,61.369 53.406,61.369 v1(53.741,61.704) ; v1(53.741,59.529) 54.041,59.829 59.391,59.829 60.826,58.394 CN12.35@64.206,58.394
  Bottom Layer w0.12: v1(53.741,61.704) 53.606,61.569 53.606,60.512 53.741,60.377 v1(53.741,59.529) 53.981,59.289 53.981,54.589 53.638,54.247 53.638,53.911 54.221,53.328 54.221,47.884 v1(53.941,47.604)
  Bottom Layer w0.127: v1(47.616,62.579) SB78.1@48.816,62.579
PA3: CN9.1 CN12.37 U14.40 | length 75
  Top Layer w0.12: 51.066,61.997 51.395,61.997 51.779,61.613 53.077,61.613 53.793,62.329 v1(54.041,62.329) ; v1(53.293,54.504) 53.316,54.481 53.872,54.481 53.875,54.484 62.836,54.484 CN12.37@64.206,55.854
  Top Layer w0.127: v1(44.591,63.329) 44.591,63.679 44.966,64.054 U14.40@45.941,64.054 46.891,64.054 48.944,62.001 51.066,62.001
  Signal Layer 2 w0.12: CN9.1@10.866,68.579 10.891,68.579 12.491,70.179 v1(14.666,70.179) ; v1(14.916,62.904) 14.916,62.804 15.346,62.374 15.671,62.374 16.699,61.346 21.371,61.346 22.049,62.024 25.927,62.024 27.34,63.436 44.484,63.436 v1(44.591,63.329)
  Bottom Layer w0.12: v1(14.666,70.179) 14.849,69.996 14.849,68.344 14.511,68.006 14.511,65.159 14.916,64.754 v1(14.916,62.904) ; v1(53.293,54.504) 53.368,54.429 53.481,54.429 53.741,54.689 53.741,58.904 53.336,59.309 53.336,61.872 53.793,62.329 v1(54.041,62.329)
PA4: CN7.17 CN11.32 SB77.1 U14.43 | length 75.7
  Top Layer w0.12: CN11.32@5.786,63.499 9.303,63.499 10.408,62.394 13.864,62.394 14.511,63.041 14.511,63.072 14.748,63.309 17.092,63.309 18.772,61.629 21.716,61.629 22.067,61.979 v1(22.067,62.429) ; U14.43@45.941,65.554 47.658,65.554 48.021,65.191 48.021,64.459 v1(47.616,64.054) 48.216,63.454 v1(53.618,63.454) ; v1(54.241,80.229) 56.552,80.229 CN7.17@56.586,80.263
  Signal Layer 2 w0.12: v1(22.067,62.429) 25.993,62.429 27.298,63.734 47.296,63.734 v1(47.616,64.054)
  Bottom Layer w0.12: v1(47.616,64.054) 48.691,64.054 SB77.1@48.816,63.929 ; v1(53.618,63.454) 53.618,64.131 54.146,64.659 54.146,64.894 54.461,65.209 54.461,71.428 54.191,71.698 54.191,76.037 53.751,76.477 53.751,79.739 v1(54.241,80.229)
PA5: CN7.10 CN12.11 SB65.1 U14.44 | length 48.2
  Top Layer w0.12: v1(47.143,65.979) 47.572,65.979 49.218,64.334 51.159,64.334 51.164,64.329 53.241,64.329 v1(53.741,64.829) ; v1(54.466,89.929) 55.077,89.318 57.044,89.318 58.149,90.423 CN7.10@59.126,90.423 62.657,90.423 CN12.11@64.206,88.874
  Top Layer w0.127: U14.44@45.941,66.054 46.991,66.054 47.141,65.904 47.141,65.978 v1(47.143,65.979)
  Bottom Layer w0.12: v1(53.741,64.829) 54.221,65.309 54.221,71.328 53.951,71.598 53.951,75.938 53.511,76.378 53.511,80.258 53.52,80.258 54.461,81.199 54.461,88.69 54.063,89.088 54.063,89.526 v1(54.466,89.929)
  Bottom Layer w0.127: v1(47.143,65.979) 47.238,65.979 47.838,65.379 48.716,65.379 SB65.1@48.816,65.279
PA6: CN7.12 CN12.13 U14.45 | length 42.6
  Top Layer w0.12: v1(53.691,87.604) 55.302,87.604 56.128,86.778 57.044,86.778 58.149,87.883 CN7.12@59.126,87.883 62.657,87.883 CN12.13@64.206,86.334
  Top Layer w0.127: U14.45@45.941,66.554 47.342,66.554 48.117,65.779 53.017,65.779 v1(53.516,66.279)
  Bottom Layer w0.12: v1(53.516,66.279) 53.734,66.497 53.734,68.663 53.336,69.061 53.336,69.456 53.734,69.854 53.734,70.176 53.723,70.187 53.723,71.147 53.471,71.399 53.471,75.739 53.031,76.179 53.031,80.462 53.974,81.405 53.974,87.321 v1(53.691,87.604)
PA7: CN12.15 SB52.1 SB56.2 U14.46 | length 46
  Top Layer w0.12: v1(41.741,68.679) 41.741,68.081 42.768,67.054 U14.46@45.941,67.054 47.186,67.054 48.217,66.023 52.687,66.023 53.808,67.144 59.584,67.144 59.901,66.827 60.486,66.827 61.17,67.51 63.084,67.51 v1(63.441,67.154)
  Bottom Layer w0.12: SB56.2@40.766,68.404 41.466,68.404 v1(41.741,68.679) ; v1(63.441,67.154) 63.441,67.756 63.101,68.096 63.101,69.012 63.666,69.577 63.666,70.071 63.101,70.636 63.101,71.244 62.728,71.616 62.728,76.121 62.206,76.644 62.206,83.344 62.656,83.794 CN12.15@64.206,83.794
  Bottom Layer w0.127: SB52.1@40.666,69.754 40.666,68.504 SB56.2@40.766,68.404
PA8: CN12.23 SB28.2 TP4.1 U14.97 | length 47.1
  Top Layer w0.12: TP4.1@32.016,84.729 31.866,84.579 U14.97@31.866,82.129 31.866,81.204 32.391,80.679 32.641,80.679 32.66,80.66 33.035,80.66 34.436,79.259 37.211,79.259 37.396,79.074 37.396,78.599 37.866,78.129 v1@38.266,78.129
  Signal Layer 2 w0.12: v1(38.241,78.104) 44.734,78.104 45.788,79.158 61.437,79.158 61.991,78.604 61.991,77.055 62.367,76.679 62.809,76.679 63.649,77.519 65.234,77.519 65.641,77.112 65.641,75.679 64.206,74.244 CN12.23@64.206,73.634
  Bottom Layer w0.12: v1(38.241,78.104) 39.066,78.104 39.166,78.004 SB28.2@39.166,77.804
PA9: CN12.21 SB21.1 U14.98 | length 44.6
  Top Layer w0.12: U14.98@31.366,82.129 31.366,81.104 32.215,80.255 v1(32.867,80.255) ; v1(62.666,78.179) 64.206,76.639 CN12.21@64.206,76.174
  Signal Layer 2 w0.12: v1(32.867,80.255) 33.843,79.279 38.071,79.279 38.391,79.599 43.201,79.599 43.441,79.359 44.896,79.359 47.011,81.474 50.009,81.474 50.233,81.698 61.647,81.698 62.666,80.679 v1(62.666,78.179)
  Bottom Layer w0.12: SB21.1@32.866,85.029 32.866,80.256 v1(32.867,80.255)
PA10: CN12.33 SB29.1 U14.99 | length 58.7
  Top Layer w0.12: U14.99@30.866,82.129 30.866,81.264 33.277,78.854 v1(36.991,78.854) ; v1(62.644,77.105) 62.641,77.102 62.641,77.054 63.091,76.604 63.091,75.429 v1(63.541,74.979)
  Signal Layer 2 w0.12: v1(36.991,78.854) 38.041,78.854 38.346,78.549 39.471,78.549 39.626,78.394 44.685,78.394 47.525,81.234 49.536,81.234 49.971,80.799 50.734,80.799 51.393,81.458 61.548,81.458 62.261,80.744 62.261,77.487 v1(62.644,77.105) ; v1(63.191,69.929) 63.191,69.931 62.286,70.836 62.286,71.324 63.101,72.139 63.101,74.539 v1(63.541,74.979)
  Signal Layer 3 w0.12: v1(63.541,74.979) v1@63.541,75.029
  Bottom Layer w0.12: v1(36.991,78.854) 37.116,78.729 SB29.1@37.116,77.704 ; v1(63.191,69.929) 63.247,69.872 63.247,69.497 62.843,69.093 62.843,65.091 62.733,64.981 62.733,62.406 CN12.33@64.206,60.934
PA11: SB22.1 SB26.1 U14.100 | length 7
  Top Layer w0.127: U14.100@30.366,82.129 30.366,83.054 v1(30.991,83.679)
  Bottom Layer w0.127: SB26.1@29.266,82.229 29.266,82.404 28.716,82.954 28.716,83.154 28.833,83.27 30.582,83.27 v1(30.991,83.679) 31.016,83.679 31.016,84.529 SB22.1@31.516,85.029
PA12: SB23.1 SB27.1 U14.101 | length 6.9
  Top Layer w0.127: U14.101@29.866,82.129 29.866,83.229 v1(30.316,83.679)
  Bottom Layer w0.127: SB27.1@27.766,82.229 27.766,82.354 28.391,82.979 28.391,83.326 28.644,83.579 30.216,83.579 v1(30.316,83.679) 30.666,84.029 30.666,84.529 SB23.1@30.166,85.029
PA13: CN5.4 CN11.13 R10.1 U8.5 U14.102 | length 81.5
  Top Layer w0.12: v1(6.466,120.729) 6.816,120.729 7.371,121.284 CN5.4@8.453,121.284 10.861,121.284 10.861,121.424 11.291,121.854 14.541,121.854 15.091,121.304 U8.5@15.466,121.304 ; U14.102@29.366,82.129 29.366,83.489 29.676,83.799 29.676,87.369 v1(29.666,87.379)
  Signal Layer 2 w0.12: CN11.13@3.246,86.359 4.681,87.794 14.374,87.794 15.569,86.599 24.724,86.599 25.975,87.85 26.85,87.85 27.725,86.975 29.262,86.975 v1(29.666,87.379)
  Bottom Layer w0.12: CN11.13@3.246,86.359 1.286,88.319 1.286,103.061 4.775,106.55 4.775,116.913 6.991,119.129 6.991,120.204 v1(6.466,120.729)
PA14: CN5.6 CN11.15 R11.2 U8.4 U14.107 | length 77.7
  Top Layer w0.12: v1(6.401,120.014) CN5.6@8.453,120.014 10.856,120.014 R11.2@10.866,120.004 11.491,119.379 12.091,119.379 12.521,118.949 14.011,118.949 15.066,120.004 U8.4@15.466,120.004 ; v1(26.666,85.279) 26.866,85.079 U14.107@26.866,82.129
  Signal Layer 2 w0.12: CN11.15@3.246,83.819 3.266,83.819 4.701,85.254 6.441,85.254 6.441,85.279 7.441,86.279 8.666,86.279 9.691,85.254 12.466,85.254 12.796,84.924 26.311,84.924 v1(26.666,85.279)
  Bottom Layer w0.12: CN11.15@3.246,83.819 1.046,86.019 1.046,103.371 4.35,106.675 4.35,117.152 6.401,119.203 v1(6.401,120.014)
PA15: CN5.10 CN7.9 CN11.17 U8.1 U14.108 | length 126.7
  Top Layer w0.12: CN5.10@8.453,117.474 13.336,117.474 14.366,118.504 v1(14.841,118.504) ; U8.1@13.766,121.304 14.216,121.304 14.841,120.679 v1(14.916,120.679) ; U14.108@26.266,82.129 26.261,82.134 26.261,85.452 26.266,85.457 v1(26.266,87.354) v1(26.266,89.829)
  Signal Layer 2 w0.12: CN11.17@3.246,81.279 2.141,82.384 2.141,84.277 2.788,84.924 4.032,84.924 4.681,85.573 4.681,86.817 5.418,87.554 14.274,87.554 15.469,86.359 25.271,86.359 v1(26.266,87.354) ; v1(14.841,118.504) 16.071,117.274 17.584,117.274 18.039,117.729 v1(20.716,117.729) ; v1(26.266,89.829) 27.066,90.629 33.366,90.629 34.346,89.649 46.059,89.649 46.229,89.819 53.192,89.819 53.947,90.574 56.586,90.574 CN7.9@56.586,90.423
  Bottom Layer w0.12: v1(14.841,118.504) 14.841,120.604 v1(14.916,120.679) ; v1(20.716,117.729) 20.716,109.979 22.226,108.469 26.456,108.469 27.2,107.725 27.2,100.604 25.866,99.27 25.866,98.291 24.45,96.875 22.925,96.875 21.825,95.775 21.825,92.875 22.45,92.25 25.575,92.25 26.266,91.559 v1(26.266,89.829)
PB0: CN10.31 CN11.34 SB54.1 U14.49 | length 130.3
  Top Layer w0.127: U14.49@45.941,68.554 47.266,68.554 v1(47.316,68.554)
  Signal Layer 2 w0.12: v1(2.016,34.829) 2.413,34.829 2.788,34.454 6.297,34.454 8.561,36.718 39.477,36.718 39.941,36.254 41.61,36.254 42.921,34.943 55.97,34.943 CN10.31@56.586,35.559 ; v1(47.316,68.554) 47.486,68.384 48.24,68.384 49,67.624 53.186,67.624 53.341,67.779 53.318,67.802 v1(53.318,67.804)
  Bottom Layer w0.12: v1(2.016,34.829) 2.016,36.256 2.396,36.636 2.396,36.974 1.293,38.077 1.293,55.489 2.871,57.067 3.806,57.067 4.598,57.859 4.598,59.771 CN11.34@5.786,60.959 ; v1(53.318,67.804) 53.318,66.781 53.111,66.574 53.111,66.111 53.213,66.009 53.213,62.088 53.096,61.971 53.096,59.209 53.501,58.804 53.501,55.284 52.888,54.672 52.888,54.322 53.981,53.229 53.981,48.217 53.536,47.772 53.536,46.013 55.441,44.108 55.441,36.704 CN10.31@56.586,35.559
  Bottom Layer w0.127: v1(47.316,68.554) 47.841,68.554 48.616,69.329 SB54.1@48.816,69.329
PB1: CN9.7 CN12.24 U14.50 | length 126.8
  Top Layer w0.12: v1(9.566,49.129) 9.801,49.364 11.395,49.364 11.725,49.694 14.031,49.694 15.208,50.871 23.249,50.871 26.516,47.604 32.964,47.604 36.099,50.739 44.89,50.739 47.585,53.434 53.776,53.434 54.272,53.434 55.291,52.414 55.291,50.531 56.153,49.669 68.056,49.669 v1(68.791,50.404) ; U14.50@45.941,69.054 49.881,69.054 50.461,69.634 53.538,69.634 56.128,72.224 64.825,72.224 66.235,73.634 CN12.24@66.746,73.634
  Bottom Layer w0.12: v1(9.566,49.129) 9.761,49.324 9.761,59.854 CN9.7@10.866,60.959 ; CN12.24@66.746,73.634 68.135,73.634 68.961,72.808 68.961,68.052 68.97,68.043 68.97,66.668 68.961,66.659 68.961,50.574 v1(68.791,50.404)
PB2: CN12.22 SB44.1 SB51.1 U14.51 | length 34.2
  Top Layer w0.12: v1(47.741,69.479) 47.781,69.479 47.966,69.294 49.782,69.294 50.362,69.874 53.439,69.874 56.029,72.464 64.726,72.464 65.311,73.049 65.311,74.739 CN12.22@66.746,76.174
  Top Layer w0.127: v1(41.958,69.565) 41.969,69.554 U14.51@45.941,69.554 46.676,69.554 46.932,69.297 47.585,69.297 47.741,69.454 v1(47.741,69.479)
  Signal Layer 2 w0.127: v1@41.927,69.565 v1(41.958,69.565)
  Bottom Layer w0.127: SB44.1@40.666,72.454 40.776,72.454 41.55,71.68 41.55,70.713 41.797,70.466 41.797,69.726 v1(41.958,69.565) ; v1(47.741,69.479) 47.933,69.67 47.933,70.012 48.599,70.679 SB51.1@48.816,70.679
PB3: CN12.31 SB49.1 SB50.2 U14.130 | length 58.3
  Top Layer w0.12: v1(22.416,69.079) 22.891,69.554 U14.130@24.291,69.554 27.316,69.554 28.791,71.029 v1(30.291,71.029)
  Signal Layer 2 w0.12: v1(22.416,69.079) 23.691,67.804 27.666,67.804 28.453,67.016 33.553,67.016 34.946,65.624 35.284,65.624 35.709,66.049 38.823,66.049 39.198,65.674 39.534,65.674 40.531,66.671 47.216,66.671 47.453,66.434 48.17,66.434 48.366,66.63 51.367,66.63 53.573,64.424 53.909,64.424 54.419,64.934 62.746,64.934 CN12.31@64.206,63.474
  Bottom Layer w0.12: SB50.2@20.991,71.004 21.866,70.129 21.866,69.629 v1(22.416,69.079) ; v1(30.291,71.029) 31.466,71.029 SB49.1@31.491,71.054
PB4: CN7.19 CN12.27 U14.131 | length 64.8
  Top Layer w0.12: U14.131@24.291,69.054 v1(34.616,69.054) ; CN7.19@56.586,77.723 57.781,78.918 62.755,78.918 63.656,79.819 64.664,79.819 65.311,79.172 65.311,77.859 65.891,77.279 67.204,77.279 67.851,76.632 67.851,73.176 67.204,72.529 66.269,72.529 65.694,71.954 v1(65.266,71.954)
  Top Layer w0.127: v1(52.266,76.679) 52.316,76.729 52.567,76.477 54.484,76.477 54.701,76.694 55.557,76.694 CN7.19@56.586,77.723
  Signal Layer 2 w0.12: v1(36.066,76.779) 47.291,76.779 47.616,76.454 48.391,76.454 48.616,76.679 v1(52.266,76.679)
  Bottom Layer w0.12: v1(34.616,69.054) 34.616,74.704 36.066,76.154 v1(36.066,76.779) ; CN12.27@64.206,68.554 64.206,69.344 65.401,70.539 65.401,71.819 v1(65.266,71.954)
PB5: SB53.1 SB55.1 SB57.2 SB59.1 U14.132 | length 11.9
  Top Layer w0.12: v1(22.341,67.629) 22.366,67.629 23.291,68.554 U14.132@24.291,68.554 28.416,68.554 v1(28.416,68.579)
  Bottom Layer w0.12: SB59.1@20.891,67.579 20.941,67.629 v1(22.341,67.629) ; v1(28.416,68.579) 29.291,68.579 SB57.2@29.516,68.354
  Bottom Layer w0.127: SB59.1@20.891,67.579 SB55.1@20.891,68.929 ; SB57.2@29.516,68.354 29.516,69.604 SB53.1@29.616,69.704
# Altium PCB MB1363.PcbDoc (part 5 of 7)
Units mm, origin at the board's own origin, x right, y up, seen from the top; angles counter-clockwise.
Board outline 70 x 133.34 mm, 6 copper layers (Top Layer, Signal Layer 1, Signal Layer 2, Signal Layer 3, Signal Layer 4, Bottom Layer), stack 1.57 mm thick; 355 components, 293 nets, 1446 pads, 1145 vias.

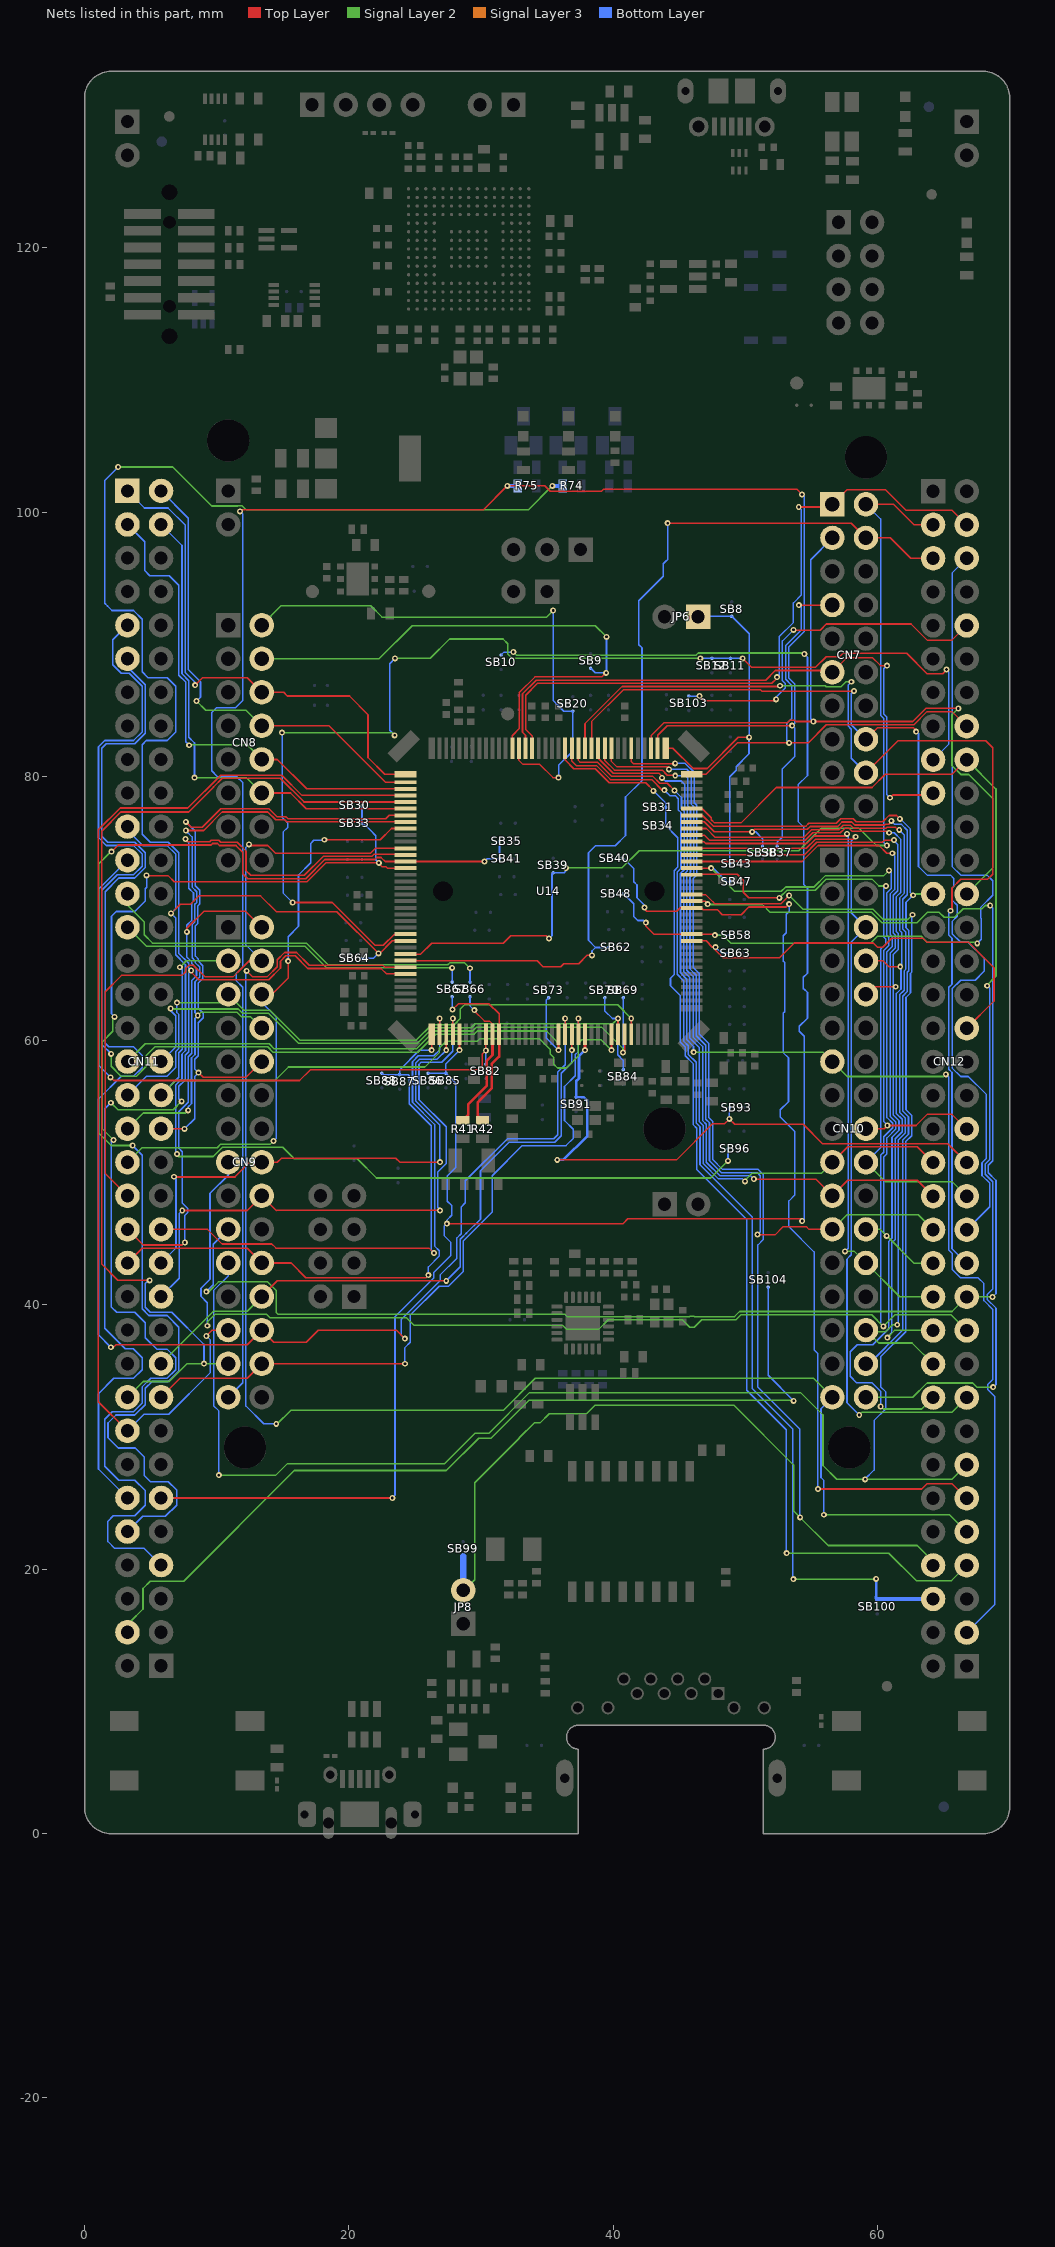
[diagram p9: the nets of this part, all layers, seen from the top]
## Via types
v1: diameter 0.45, hole 0.2, Top Layer to Bottom Layer, tented both sides, 1136 vias
v2: diameter 0.6, hole 0.3, Top Layer to Bottom Layer, tented both sides, 9 vias

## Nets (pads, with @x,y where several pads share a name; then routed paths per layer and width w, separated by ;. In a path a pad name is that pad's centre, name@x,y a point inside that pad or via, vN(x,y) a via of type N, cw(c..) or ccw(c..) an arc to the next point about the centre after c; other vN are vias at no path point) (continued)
PB6: CN12.17 SB11.2 SB12.2 U14.133 | length 90.8
  Top Layer w0.12: v1(15.741,70.454) 18.731,70.454 21.974,67.212 22.609,67.212 23.452,68.054 U14.133@24.291,68.054 ; v1(49.791,88.929) 50.471,88.249 55.311,88.249 56.116,89.054 57.119,89.054 57.38,89.315 62.202,89.315 63.748,87.769 64.931,87.769 65.218,88.055 65.216,88.057 v1(65.216,88.079)
  Signal Layer 2 w0.12: v1(14.941,83.304) 23.291,83.304 23.491,83.104 v1(23.466,83.104) ; v1(23.491,88.929) 26.16,88.929 27.62,90.389 31.666,90.389 32.016,90.039 32.016,89.256 32.343,88.929 v1(46.591,88.929)
  Bottom Layer w0.12: v1(14.941,83.304) 14.946,83.299 14.946,76.897 15.371,76.472 15.371,76.136 15.021,75.786 15.021,71.174 v1(15.741,70.454) ; v1(23.466,83.104) 23.091,83.479 23.091,88.529 v1(23.491,88.929) ; v1(46.591,88.929) SB12.2@47.466,88.929 SB11.2@48.866,88.929 v1(49.791,88.929) ; CN12.17@64.206,81.254 65.401,82.449 65.401,87.873 65.216,88.058 v1(65.216,88.079)
PB7: CN11.21 SB64.2 SB96.2 U14.134 | length 94.5
  Top Layer w0.12: v1(6.541,69.629) 7.236,70.324 8.009,70.324 8.639,70.954 13.318,70.954 14.518,69.754 19.092,69.754 v1(22.242,66.604) ; v1@22.292,66.554 23.291,67.554 U14.134@24.291,67.554
  Signal Layer 2 w0.127: v1@7.091,51.229 9.728,51.229 10.431,51.932 14.991,51.932 15.869,51.054 20.641,51.054 22.091,49.604 47.391,49.604 v1(48.691,50.904)
  Bottom Layer w0.12: CN11.21@3.246,76.199 3.246,75.92 4.402,74.764 6.244,74.764 6.891,74.117 6.891,69.979 v1(6.541,69.629) 6.891,69.279 6.891,66.497 7.636,65.752 7.636,59.251 7.371,58.986 7.371,57.124 6.891,56.644 6.891,51.528 v1(6.991,51.429) ; SB64.2@20.991,66.229 21.866,66.229 v1(22.242,66.604)
  Bottom Layer w0.127: v1(48.691,50.904) SB96.2@48.691,51.804
PB8: CN7.2 CN12.3 SB39.1 U14.136 | length 76.2
  Top Layer w0.12: U14.136@24.291,66.554 25.441,66.554 26.266,67.379 31.689,67.379 32.239,67.929 34.942,67.929 v1(35.142,67.729) ; CN7.2@59.126,100.583 61.212,100.583 62.761,99.034 CN12.3@64.206,99.034
  Signal Layer 2 w0.12: v1(36.416,73.054) 36.461,73.099 40.692,73.099 41.972,74.379 54.041,74.379 55.743,76.081 58.591,76.081 59.648,75.024 59.663,75.024 59.918,74.769 v1(60.701,74.769) v1@60.701,74.764
  Bottom Layer w0.12: v1(35.142,67.729) 35.142,67.705 35.371,67.934 35.371,72.609 SB39.1@35.466,72.704 36.291,72.704 36.416,72.829 v1(36.416,73.054) ; CN7.2@59.126,100.583 60.231,99.478 60.231,84.614 60.471,84.374 60.471,74.999 v1(60.701,74.769)
PB9: CN7.4 CN12.5 SB62.1 U14.137 | length 73.4
  Top Layer w0.127: U14.137@24.291,66.054 34.241,66.054 34.691,65.604 36.041,65.604 36.266,65.829 37.391,65.829 38.017,66.454 v1(38.392,66.454) ; v1(44.116,99.154) 44.116,99.151 58.018,99.151 CN7.4@59.126,98.043 60.952,98.043 62.501,96.494 CN12.5@64.206,96.494
  Bottom Layer w0.127: v1(38.392,66.454) 38.392,66.78 38.666,67.054 ; SB62.1@39.666,67.054 38.666,67.054 ; v1(44.116,99.154) 44.116,96.404 44.025,96.312 44.022,96.312 43.783,96.073 43.783,95.138 41.938,93.293 41.938,89.964 42.175,89.727 42.175,79.676 40.933,78.434 40.933,75.52 40.166,74.754 38.666,74.754 38.132,74.22 38.132,67.587 38.666,67.054
PB10: CN10.32 CN12.25 U14.66 | length 62.1
  Top Layer w0.12: U14.66@45.941,77.054 46.741,77.054 47.561,76.234 54.585,76.234 54.802,76.451 56.877,76.451 57.212,76.786 58.16,76.786 58.385,76.561 60.4,76.561 60.873,77.034 61.439,77.034 v1(61.693,76.78)
  Signal Layer 2 w0.12: v1(62.691,71.004) 62.781,71.094 CN12.25@64.206,71.094
  Bottom Layer w0.12: CN10.32@59.126,35.559 59.371,35.559 61.896,38.084 61.896,52.464 62.346,52.914 62.346,54.244 61.911,54.679 61.911,63.37 62.253,63.713 62.253,65.179 62.363,65.289 62.363,68.33 62.151,68.542 62.151,70.464 v1(62.691,71.004) 62.488,71.206 62.488,76.022 61.731,76.78 v1(61.693,76.78)
PB11: CN10.34 CN12.18 U14.67 | length 83.3
  Top Layer w0.12: U14.67@45.941,77.554 46.741,77.554 47.423,76.872 47.423,76.711 47.66,76.474 49.661,76.474 52.345,79.158 59.584,79.158 60.575,80.149 65.641,80.149 CN12.18@66.746,81.254
  Signal Layer 2 w0.12: CN10.34@59.126,33.019 62.668,33.019 63.748,34.099 67.204,34.099 67.525,33.778 v1(68.744,33.778)
  Signal Layer 2 w0.127: CN12.18@66.746,81.254 68.957,79.042 68.957,64.87 68.241,64.154 v1(68.291,64.154)
  Bottom Layer w0.12: v1(68.291,64.154) 68.481,63.964 68.481,51.006 68.146,50.671 68.146,49.899 68.721,49.324 68.721,41.203 68.289,40.771 68.289,40.435 68.961,39.763 68.961,33.974 68.744,33.757 v1(68.744,33.778)
PB12: CN7.7 CN12.16 U14.72 | length 37.2
  Top Layer w0.12: U14.72@45.941,80.154 47.018,80.154 49.393,82.529 v1(53.316,82.529) 54.749,82.529 56.128,83.908 62.757,83.908 63.748,84.899 65.641,84.899 CN12.16@66.746,83.794 ; v1(54.043,92.956) 54.066,92.933 56.556,92.933 CN7.7@56.586,92.963
  Bottom Layer w0.12: v1(53.316,82.529) 53.138,82.707 53.138,83.998 53.494,84.354 53.494,86.889 53.046,87.337 53.046,89.893 54.214,91.061 54.214,92.856 54.091,92.979 54.068,92.956 v1(54.043,92.956)
PB13: JP6.1 SB8.1 SB43.1 U14.73 | length 30.4
  Top Layer w0.127: U14.73@43.966,82.129 44.516,82.129 46.058,80.587 47.107,80.587 49.474,82.954 v1(50.291,82.954)
  Bottom Layer w0.127: JP6.1@46.426,92.074 46.456,92.104 SB8.1@48.966,92.104 50.291,90.779 v1(50.291,82.954) 50.291,82.879 50.274,82.862 50.274,81.699 49.3,80.724 49.3,80.449 48.816,79.966 SB43.1@48.816,73.379
PB14: CN9.29 R75.1 SB37.1 U14.74 | length 155.8
  Top Layer w0.12: v1(11.766,100.054) 11.871,100.159 30.171,100.159 v1(31.991,101.979) 34.818,101.979 35.235,101.562 39.107,101.562 39.28,101.735 53.883,101.735 v1(54.289,101.329) ; U14.74@43.366,82.129 43.366,83.104 44.091,83.829 53.542,83.829 v1(53.543,83.83)
  Bottom Layer w0.12: CN9.29@10.866,33.019 11.971,34.124 11.971,64.049 11.466,64.554 11.466,65.076 11.971,65.581 11.971,79.529 11.521,79.979 10.066,79.979 9.618,80.427 9.618,84.829 9.993,85.204 11.441,85.204 11.971,85.734 11.971,99.849 v1(11.766,100.054) ; SB37.1@52.4,74.7 52.4,75.009 52.791,75.4 52.791,80.561 53.734,81.504 53.734,83.639 v1(53.543,83.83) 53.734,84.021 53.734,86.988 53.286,87.436 53.286,89.793 54.454,90.961 54.454,101.216 54.289,101.381 v1(54.289,101.329)
  Bottom Layer w0.3: v1(31.991,101.979) R75.1@32.766,101.979
PB15: CN7.3 CN12.26 U14.75 | length 57.9
  Top Layer w0.12: U14.75@42.866,82.129 42.866,83.079 43.856,84.069 53.209,84.069 53.375,84.235 53.711,84.235 53.798,84.148 v1(55.141,84.148) 62.658,84.148 63.649,85.139 65.74,85.139
  Top Layer w0.127: 64.316,85.142 66.103,85.142 v1(66.116,85.129)
  Signal Layer 2 w0.127: v1(66.116,85.129) 65.638,84.65 65.638,83.335 65.641,83.331 65.641,81.801 65.638,81.798 65.638,80.795 66.287,80.145 66.882,80.145 68.711,78.317 68.711,73.058 CN12.26@66.746,71.094
  Bottom Layer w0.12: v1(55.141,84.148) 54.941,84.348 54.941,96.398 CN7.3@56.586,98.043
PC0: CN9.3 CN11.38 U14.28 | length 54.7
  Top Layer w0.127: v1(39.866,59.279) U14.28@39.866,60.479
  Signal Layer 2 w0.12: CN11.38@5.786,55.879 6.891,56.984 14.41,56.984 15.43,58.004 25.754,58.004 26.825,59.075 26.825,59.425 27.36,59.96 29.724,59.96 29.914,60.15 34.425,60.15 35.221,59.354 35.221,59.012 35.511,58.722 35.511,58.211 35.793,57.929 36.441,57.929 37.366,58.854 37.366,59.804 37.626,60.064 39.081,60.064 v1(39.866,59.279) ; v1(7.216,65.554) 7.701,66.039 CN9.3@10.866,66.039
  Bottom Layer w0.12: CN11.38@5.786,55.879 7.131,57.224 7.131,59.085 7.396,59.35 7.396,65.374 v1(7.216,65.554)
PC1: CN11.36 SB70.1 SB84.2 U14.29 | length 47.8
  Top Layer w0.127: U14.29@40.366,60.479 v1(40.366,61.679)
  Signal Layer 2 w0.12: v1(6.516,62.429) 6.591,62.429 6.626,62.394 11.632,62.394 11.962,62.064 13.931,62.064 16.191,59.804 25.19,59.804 26.36,60.974 29.269,60.974 29.569,61.274 39.961,61.274 v1(40.366,61.679)
  Bottom Layer w0.12: CN11.36@5.786,58.419 6.891,59.524 6.891,61.887 6.516,62.262 v1(6.516,62.429) ; SB70.1@39.366,63.254 39.366,62.252 39.939,61.679 v1(40.366,61.679) 40.336,61.649 40.336,58.936 40.766,58.506 SB84.2@40.766,57.804
PC2: CN11.35 SB69.1 U14.30 | length 45.4
  Top Layer w0.12: v1(40.741,59.104) 40.866,59.229 40.866,59.604
  Top Layer w0.127: 40.866,59.604 U14.30@40.866,60.479
  Signal Layer 2 w0.12: CN11.35@3.246,58.419 4.598,59.771 13.966,59.771 14.363,59.374 25.1,59.374 26.46,60.734 29.368,60.734 29.634,61 39.145,61 40.741,59.404 v1(40.741,59.104)
  Bottom Layer w0.12: v1(40.741,59.104) 40.771,59.134 40.771,63.249 SB69.1@40.766,63.254
PC3: CN9.5 CN11.37 U14.31 | length 48.8
  Top Layer w0.127: U14.31@41.366,60.479 v1(41.366,61.679)
  Signal Layer 2 w0.12: v1(6.991,62.879) 10.246,62.879 CN9.5@10.866,63.499 12.061,62.304 14.03,62.304 16.29,60.044 25.091,60.044 26.261,61.214 27.974,61.214 28.436,61.676 28.436,62.397 28.749,62.709 40.336,62.709 v1(41.366,61.679)
  Bottom Layer w0.12: CN11.37@3.246,55.879 4.681,57.314 6.244,57.314 6.891,57.961 6.891,59.184 7.141,59.434 7.141,61.977 6.991,62.127 v1(6.991,62.879)
PC4: CN12.34 SB63.2 U14.47 | length 32
  Top Layer w0.127: U14.47@45.941,67.554 47.031,67.554 47.506,67.079 v1(47.741,67.079) 47.741,66.844 48.318,66.266 52.586,66.266 53.707,67.387 59.685,67.387 60.002,67.07 60.385,67.07 61.069,67.754 63.438,67.754 63.747,67.445 66.882,67.445 67.205,67.122 68.816,65.512 68.816,63.004 CN12.34@66.746,60.934
  Bottom Layer w0.127: v1(47.741,67.079) 48.191,66.629 SB63.2@48.716,66.629
PC5: CN12.6 SB48.2 SB58.1 U14.48 | length 63.2
  Top Layer w0.127: v1(42.466,68.929) 42.466,68.679 43.091,68.054 U14.48@45.941,68.054 47.616,68.054 v1(47.691,67.979)
  Signal Layer 2 w0.12: v1(47.691,67.979) 48.305,67.979 48.9,67.384 59.494,67.384 60.004,67.894 63.303,67.894 63.748,67.449 67.456,67.449 v1(67.546,67.359)
  Signal Layer 3 w0.12: v1(67.546,67.359) v1@67.546,67.374
  Bottom Layer w0.12: CN12.6@66.746,96.494 65.641,95.389 65.641,73.176 66.288,72.529 68.291,72.529 68.721,72.099 68.721,71.007 67.821,70.107 67.821,69.279 67.853,69.246 67.853,67.667 v1(67.546,67.359)
  Bottom Layer w0.127: SB48.2@40.766,71.104 40.809,71.104 41.55,70.363 41.55,69.395 41.857,69.087 42.307,69.087 v1(42.466,68.929) ; v1(47.691,67.979) SB58.1@48.816,67.979
PC6: CN7.1 CN12.4 U14.93 | length 51.9
  Top Layer w0.12: U14.93@33.866,82.129 33.866,83.054 33.379,83.541 33.379,86.141 34.277,87.04 52.002,87.04 52.393,87.431 v1(52.393,87.505) ; v1(54.041,100.379) 56.382,100.379 CN7.1@56.586,100.583 57.691,101.688 60.607,101.688 62.156,100.139 65.641,100.139 CN12.4@66.746,99.034
  Bottom Layer w0.12: v1(52.393,87.505) 52.566,87.678 52.566,90.576 53.638,91.648 53.638,93.123 54.214,93.699 54.214,100.204 54.041,100.377 v1(54.041,100.379)
PC7: CN7.11 CN12.19 U14.94 | length 47
  Top Layer w0.12: U14.94@33.366,82.129 33.366,83.104 33.139,83.331 33.139,86.241 34.178,87.28 51.541,87.28 52.27,88.009 56.46,88.009 CN7.11@56.586,87.883 57.691,88.988 59.607,88.988 60.216,88.379 v1(60.716,88.379) ; v1(60.941,78.379) 61.15,78.588 64.08,78.588 CN12.19@64.206,78.714
  Bottom Layer w0.12: v1(60.716,88.379) 60.471,88.134 60.471,84.713 60.711,84.473 60.711,78.609 v1(60.941,78.379)
PC8: CN8.2 SB20.2 U14.95 | length 41.8
  Top Layer w0.12: U14.95@32.866,82.129 32.866,81.204 33.141,80.929 34.412,80.929 35.437,79.904 v1(35.866,79.904)
  Signal Layer 2 w0.12: CN8.2@13.406,91.439 14.871,92.904 21.646,92.904 22.5,92.05 34.962,92.05 v1(35.461,92.549)
  Bottom Layer w0.12: v1(35.461,92.549) 35.461,85.734 36.266,84.929 SB20.2@36.941,84.929 36.941,81.904 35.866,80.829 v1(35.866,79.904)
PC9: CN8.4 SB9.1 U14.96 | length 43.1
  Top Layer w0.12: U14.96@32.366,82.129 32.366,83.079 32.899,83.611 32.899,86.34 34.079,87.52 39.132,87.52 39.441,87.829 v1(39.466,87.829)
  Signal Layer 2 w0.12: CN8.4@13.406,88.899 22.286,88.899 24.787,91.4 38.645,91.4 v1(39.491,90.554)
  Bottom Layer w0.12: SB9.1@38.291,88.179 38.641,87.829 v1(39.466,87.829) 39.491,87.854 v1(39.491,90.554)
PC10: CN8.6 CN11.1 U14.109 | length 38.9
  Top Layer w0.12: v1(8.366,86.904) 8.929,87.467 10.991,87.467
  Top Layer w0.127: 10.991,87.467 12.298,87.467 CN8.6@13.406,86.359 15.061,86.359 15.341,86.079 20.041,86.079 21.45,84.67 21.45,81.42 22.716,80.154 U14.109@24.291,80.154
  Bottom Layer w0.12: 6.316,100.304 7.611,99.009 7.611,87.853 8.366,87.098 v1(8.366,86.904)
  Bottom Layer w0.127: CN11.1@3.246,101.599 4.541,100.304 6.316,100.304
PC11: CN8.8 CN11.2 U14.110 | length 35.7
  Top Layer w0.127: CN8.8@13.406,83.819 18.501,83.819 22.766,79.554 U14.110@24.291,79.554
  Signal Layer 2 w0.127: v1(8.466,85.704) 9.159,85.01 12.214,85.01 CN8.8@13.406,83.819
  Bottom Layer w0.127: CN11.2@5.786,101.599 7.854,99.53 7.854,88.079 8.775,87.159 8.775,85.987 8.466,85.679 v1(8.466,85.704)
PC12: CN8.10 CN11.3 U14.111 | length 37.3
  Top Layer w0.127: CN8.10@13.406,81.279 14.591,81.279 16.816,79.054 U14.111@24.291,79.054
  Signal Layer 2 w0.12: v1(7.916,82.354) 7.946,82.384 12.301,82.384 CN8.10@13.406,81.279
  Bottom Layer w0.12: 4.551,97.754 4.551,95.569 4.941,95.179 6.416,95.179 7.131,94.464 7.131,87.654 7.653,87.132 7.653,82.617 v1(7.916,82.354)
  Bottom Layer w0.127: CN11.3@3.246,99.059 4.551,97.754
PC13: CN11.23 SB82.2 U14.9 | length 50
  Top Layer w0.12: v1(1.966,57.229) 2.211,56.984 16.271,56.984 17.091,57.804 29.891,57.804 30.094,58.007 30.094,58.982 v1(30.366,59.254) U14.9@30.366,60.479
  Bottom Layer w0.12: v1(1.966,57.229) 1.066,58.129 1.066,71.479 CN11.23@3.246,73.659
  Bottom Layer w0.127: SB82.2@30.366,58.229 v1(30.366,59.254)
PC14: CN11.25 SB66.1 | length 30.5
  Signal Layer 2 w0.12: CN11.25@3.246,71.119 3.246,70.249 4.516,68.979 4.516,68.009 5.141,67.384 16.777,67.384 18.411,65.749 19.185,65.749 19.191,65.744 27.483,65.744 27.648,65.909 28.736,65.909 v1(29.166,65.479)
  Bottom Layer w0.12: SB66.1@29.166,64.429 v1(29.166,65.479)
PC14-MCU: R41.1 SB66.2 U14.10 | length 11.2
  Top Layer w0.12: v1(29.492,62.304) 29.492,62.253 30.261,61.484 30.636,61.484 30.866,61.254 U14.10@30.866,60.479
  Top Layer w0.2: R41.1@28.616,53.979 29.025,54.388 29.025,55.175 30.425,56.575 30.425,58.475 30.866,58.916 U14.10@30.866,60.479
  Bottom Layer w0.12: SB66.2@29.166,63.329 29.166,62.63 v1(29.492,62.304)
PC15: CN11.27 SB67.1 | length 26.8
  Signal Layer 2 w0.12: CN11.27@3.246,68.579 4.681,67.144 16.677,67.144 18.317,65.504 v1(27.816,65.504)
  Bottom Layer w0.127: SB67.1@27.816,64.529 v1(27.816,65.504)
PC15-MCU: R42.2 SB67.2 U14.11 | length 13.9
  Top Layer w0.127: v1(27.841,62.354) 28.291,62.804 30.59,62.804 31.366,62.028 U14.11@31.366,60.479
  Top Layer w0.2: R42.2@30.116,53.979 29.75,54.345 29.75,55.338 30.8,56.388 30.8,58.238 31.366,58.804 U14.11@31.366,60.479
  Bottom Layer w0.127: SB67.2@27.816,63.329 27.816,62.379 v1(27.841,62.354)
PD0: CN9.25 CN11.57 U14.112 | length 84.8
  Top Layer w0.12: CN11.57@3.246,30.479 1.046,32.679 1.046,75.955 2.692,77.601 7.816,77.601 10.306,80.091 14.918,80.091 16.455,78.554 U14.112@24.291,78.554 ; v1(9.216,37.654) 9.661,38.099 CN9.25@10.866,38.099
  Bottom Layer w0.12: CN11.57@3.246,30.479 4.496,31.729 6.366,31.729 9.521,34.884 9.521,37.349 v1(9.216,37.654)
PD1: CN9.27 CN11.55 U14.113 | length 80.3
  Top Layer w0.127: v1(4.926,41.868) 2.522,41.868 1.289,43.101 1.289,75.854 2.743,77.307 7.894,77.307 9.758,79.17 9.758,79.198 10.407,79.847 14.817,79.847 16.61,78.054 U14.113@24.291,78.054
  Signal Layer 2 w0.127: CN11.55@3.246,33.019 4.438,34.21 6.398,34.21 7.746,35.559 v1(9.041,35.559) CN9.27@10.866,35.559
  Bottom Layer w0.127: v1(4.926,41.868) 4.841,41.868 4.601,41.629 4.601,39.818 4.965,39.454 6.591,39.454 9.041,37.004 v1(9.041,35.559)
PD2: CN8.12 CN11.4 U14.114 | length 37.2
  Top Layer w0.12: CN8.12@13.406,78.739 15.581,78.739 16.766,77.554 U14.114@24.291,77.554
  Signal Layer 2 w0.12: v1(8.316,79.904) 12.241,79.904 CN8.12@13.406,78.739
  Bottom Layer w0.12: CN11.4@5.786,99.059 7.371,97.474 7.371,87.754 7.893,87.232 7.893,82.95 8.321,82.522 8.321,79.984 8.316,79.979 v1(8.316,79.904)
PD3: CN9.10 CN11.40 U14.115 | length 50.2
  Top Layer w0.12: v1(7.666,76.555) 8.076,76.145 8.91,76.145 10.309,77.544 13.963,77.544 14.558,76.949 15.233,76.949 15.388,76.794 22.791,76.794 23.051,77.054 U14.115@24.291,77.054 ; v1(8.616,57.579) 8.971,57.224 12.211,57.224 CN9.10@13.406,58.419
  Top Layer w0.127: CN11.40@5.786,53.339 7.576,53.339 v1(7.566,53.329)
  Bottom Layer w0.12: v1(7.566,53.329) 8.331,54.094 8.331,57.294 v1(8.616,57.579) 8.331,57.864 8.331,58.588 8.596,58.853 8.596,61.361 8.971,61.736 8.971,62.072 8.596,62.447 8.596,64.355 8.951,64.71 8.951,65.671 8.603,66.019 8.603,66.187 8.386,66.404 8.386,68.697 8.576,68.887 8.576,70.212 8.726,70.362 8.726,71.371 8.373,71.724 8.373,75.847 v1@7.666,76.554
PD4: CN9.8 CN11.39 U14.116 | length 50.5
  Top Layer w0.12: v1(7.666,75.905) 9.009,75.905 10.408,77.304 13.864,77.304 14.459,76.709 15.134,76.709 15.289,76.554 U14.116@24.291,76.554
  Signal Layer 2 w0.12: CN11.39@3.246,53.339 4.434,54.527 7.639,54.527 v1(7.841,54.729) ; v1(8.566,61.904) 8.816,62.154 11.532,62.154 11.862,61.824 12.541,61.824 CN9.8@13.406,60.959
  Bottom Layer w0.12: v1(7.666,75.905) 7.666,75.879 8.133,75.412 8.133,71.625 8.486,71.272 8.486,70.462 8.336,70.312 8.336,68.987 8.146,68.797 8.146,66.27 8.363,66.053 8.363,65.919 8.711,65.571 8.711,64.809 8.356,64.454 8.356,62.114 v1(8.566,61.904) 8.356,61.694 8.356,58.952 8.091,58.687 8.091,55.242 7.847,54.998 7.847,54.735 v1(7.841,54.729)
PD5: CN9.6 CN11.41 U14.117 | length 44.5
  Top Layer w0.12: CN9.6@13.406,63.499 14.161,63.499 15.403,64.741 v1(15.403,66.016) ; v1(18.141,75.204) 22.366,75.204 23.216,76.054 U14.117@24.291,76.054
  Signal Layer 2 w0.12: CN11.41@3.246,50.799 4.351,51.904 10.041,51.904 10.313,52.175 14.062,52.175 v1(14.291,52.404)
  Bottom Layer w0.12: CN9.6@13.406,63.499 13.406,62.889 14.511,61.784 14.511,52.599 14.291,52.379 v1(14.291,52.404) ; v1(15.403,66.016) 15.403,67.867 16.187,68.651 16.187,72.535 17.116,73.464 17.116,74.562 17.111,74.567 17.111,74.922 17.348,75.159 18.096,75.159 v1(18.141,75.204)
PD6: CN9.4 CN11.43 U14.120 | length 51.5
  Top Layer w0.12: CN11.43@3.246,48.259 1.556,49.948 1.556,63.694 2.796,64.934 7.371,64.934 7.661,65.224 7.661,65.472 7.898,65.709 8.234,65.709 9.092,64.851 11.266,64.851 11.861,65.446 ; 11.861,65.447 12.453,66.039 CN9.4@13.406,66.039 ; v1(12.441,74.854) 12.531,74.764 13.864,74.764 14.44,74.187 21.642,74.187 22.008,74.554 U14.120@24.291,74.554
  Bottom Layer w0.12: v1(12.441,74.854) 12.211,74.624 12.211,67.234 CN9.4@13.406,66.039
PD7: CN9.2 CN11.45 U14.121 | length 63.3
  Top Layer w0.12: v1(7.741,68.229) 7.741,68.504 9.016,69.779 12.206,69.779 CN9.2@13.406,68.579 ; 7.748,75.047 9.476,75.047 9.585,75.156 10.161,75.156 10.306,75.011 11.553,75.011 12.218,74.346 12.218,72.854 12.566,72.506 16.629,72.506 18.071,73.947 21.741,73.947 21.9,74.107 24.291,74.107 U14.121@24.291,74.054
  Top Layer w0.127: CN11.45@3.246,45.719 4.431,44.534 7.397,44.534 v1(7.591,44.729)
  Bottom Layer w0.12: v1(7.591,44.729) 7.591,46.778 7.796,46.983 7.796,47.318 7.396,47.718 7.396,51.596 7.159,51.834 7.151,51.834 7.131,51.854 7.131,54.621 7.851,55.341 7.851,58.787 8.116,59.052 8.116,64.554 8.471,64.909 8.471,65.472 8.123,65.82 8.123,65.953 7.741,66.335 v1(7.741,68.229) ; v1(7.641,75.254) 7.893,75.002 7.893,71.525 8.246,71.172 8.246,70.561 8.096,70.411 8.096,69.086 7.741,68.731 v1@7.741,68.34
PD8: CN12.10 SB103.1 | length 27.1
  Top Layer w0.12: v1(46.525,86.075) 46.876,85.724 52.224,85.724 v1(52.325,85.825) ; v1(53.643,91.081) 53.664,91.06 55.66,91.06 56.128,91.528 62.529,91.528 63.748,90.309 65.641,90.309 CN12.10@66.746,91.414
  Signal Layer 2 w0.12: v1@53.643,91.031 v1(53.643,91.081)
  Bottom Layer w0.12: SB103.1@45.725,86.075 v1(46.525,86.075) ; v1(52.325,85.825) 52.325,85.987 53.023,86.685 53.023,87.021 52.806,87.237 52.806,90.243 v1(53.643,91.081)
PD9: CN11.69 SB104.1 | length 68.2
  Signal Layer 2 w0.12: CN11.69@3.45,15.25 3.45,16.025 4.425,17 4.425,18.55 4.975,19.1 7.5,19.1 15.875,27.475 27.375,27.475 29.825,29.925 30.75,29.925 33.625,32.8 53.6,32.8 v1(53.65,32.75)
  Bottom Layer w0.12: SB104.1@51.725,41.35 51.725,34.675 v1(53.65,32.75)
PD10: CN12.65 JP8.2 SB99.2 U14.78 | length 123.5
  Top Layer w0.12: U14.78@41.366,82.129 41.366,81.129 41.541,80.954 44.691,80.954 v1(44.691,80.979)
  Signal Layer 2 w0.12: JP8.2@28.606,18.454 JP8.2@28.646,18.414 JP8.2@28.739,18.414 ; JP8.2@28.725,18.4 JP8.2@28.739,18.414 ; CN12.65@64.4,20.4 63,21.8 56.27,21.8 v1(54.141,23.929) 54.141,23.934 53.65,24.425 53.65,27.9 49.15,32.4 38.6,32.4 37.975,31.775 35.16,31.775 34.459,31.074 34.024,31.074 32.9,29.95 32.9,29.925 29.525,26.55 29.525,19.2 JP8.2@28.739,18.414
  Bottom Layer w0.12: v1(44.691,80.979) 45.455,80.979 46.13,80.304 46.13,78.002 46.328,77.804 46.328,72.541 46.052,72.266 46.052,65.528 46.526,65.054 46.526,60.477 47.244,59.759 47.244,54.161 47.526,53.879 47.526,51.004 48.272,50.259 50.972,50.259 51.362,49.868 51.362,44.951 50.95,44.539 50.95,33.775 54.125,30.6 v1@54.125,23.929
  Bottom Layer w0.5: JP8.2@28.646,18.414 SB99.2@28.646,20.989
PD11: CN10.23 CN12.45 U14.81 | length 61.1
  Top Layer w0.12: U14.81@39.866,82.129 39.866,81.129 40.281,80.714 44.156,80.714 44.291,80.579 44.266,80.579 v1(44.218,80.53) ; v1(50.918,45.328) 50.918,45.302 52.235,45.302 52.847,45.914 54.62,45.914 54.815,45.719 CN10.23@56.586,45.719
  Signal Layer 2 w0.12: CN10.23@56.586,45.719 57.691,46.824 63.076,46.824 CN12.45@64.206,45.694
  Bottom Layer w0.12: v1(44.218,80.53) 45.564,80.53 45.89,80.204 45.89,77.902 46.088,77.705 46.088,72.641 45.812,72.366 45.812,65.428 46.286,64.955 46.286,60.378 47.004,59.659 47.004,54.062 47.286,53.78 47.286,50.905 48.172,50.019 50.872,50.019 51.122,49.769 51.122,45.535 50.916,45.329 v1(50.918,45.328)
PD12: CN10.21 CN12.43 U14.82 | length 56.8
  Top Layer w0.12: U14.82@39.366,82.129 39.366,81.204 40.096,80.474 43.701,80.474 44.096,80.079 44.669,80.079 v1(44.693,80.055) ; v1(50.641,49.529) 55.316,49.529 CN10.21@56.586,48.259 57.756,49.429 63.011,49.429 CN12.43@64.206,48.234
  Bottom Layer w0.12: v1(44.693,80.055) 45.474,80.055 45.65,79.879 45.65,77.752 45.848,77.554 45.848,72.74 45.572,72.465 45.572,65.329 46.046,64.856 46.046,60.278 46.764,59.56 46.764,53.963 47.046,53.681 47.046,50.806 48.073,49.779 50.391,49.779 v1(50.641,49.529)
PD13: CN10.19 CN12.41 U14.83 | length 57.3
  Top Layer w0.12: U14.83@38.866,82.129 38.866,81.364 39.997,80.234 43.466,80.234 43.716,79.984 43.716,79.903 v1(43.693,79.88) ; CN10.19@56.586,50.799 57.756,51.969 63.011,51.969 CN12.41@64.206,50.774
  Signal Layer 2 w0.12: v1(49.968,49.354) 49.968,49.429 50.507,49.968 55.755,49.968 CN10.19@56.586,50.799
  Bottom Layer w0.12: v1(43.693,79.88) 43.923,79.65 45.139,79.65 45.41,79.379 45.41,77.652 45.608,77.454 45.608,72.84 45.332,72.564 45.332,65.229 45.806,64.756 45.806,60.179 46.524,59.46 46.524,53.863 46.806,53.581 46.806,50.706 47.973,49.539 49.781,49.539 v1(49.968,49.354) v1(49.968,49.354)
PD14: CN7.16 CN12.46 U14.84 | length 77.3
  Top Layer w0.12: U14.84@38.366,82.129 38.366,84.154 40.772,86.56 51.148,86.56 51.26,86.448 58.21,86.448 v1(58.216,86.454) ; CN7.16@59.126,82.803 59.991,83.668 62.726,83.668 62.966,83.428 v1(62.919,83.38)
  Bottom Layer w0.12: v1(58.216,86.454) 58.021,86.259 58.021,83.908 CN7.16@59.126,82.803 ; v1(62.919,83.38) 62.965,83.38 63.101,83.244 63.101,73.176 63.748,72.529 65.516,72.529 65.757,72.288 65.757,71.667 65.641,71.552 65.641,70.636 66.041,70.236 66.041,69.412 65.641,69.012 65.641,68.096 66.288,67.449 66.874,67.449 68.061,66.262 68.061,65.256 67.384,64.579 66.288,64.579 65.641,63.932 65.641,57.936 66.288,57.289 66.874,57.289 68.241,55.922 68.241,51.105 67.906,50.77 67.906,49.8 68.481,49.225 68.481,47.429 CN12.46@66.746,45.694
PD15: CN7.18 CN12.48 U14.85 | length 84.1
  Top Layer w0.12: U14.85@37.866,82.129 37.866,83.993 40.673,86.8 52.612,86.8 52.618,86.806 v1(52.618,86.853)
  Top Layer w0.127: CN7.18@59.126,80.263 61.549,82.685 68.184,82.685 68.711,82.159 68.711,72.598 68.314,72.202 66.287,72.202 65.638,71.553 65.638,70.635 65.639,70.634 65.639,69.949 v1(65.519,69.83)
  Signal Layer 2 w0.12: v1(52.618,86.853) 56.053,86.853 56.128,86.778 57.24,86.778 57.616,87.154 58.017,87.154 v1(58.018,87.155)
  Signal Layer 3 w0.12: v1(58.018,87.155) v1@58.018,87.177
  Bottom Layer w0.127: v1(58.018,87.155) 57.778,86.915 57.778,83.807 58.018,83.567 58.018,81.371 CN7.18@59.126,80.263 ; v1(65.519,69.83) 65.519,69.801 65.541,69.779 65.398,69.635 65.398,67.995 65.638,67.755 65.638,64.272 65.398,64.032 65.398,57.835 65.638,57.595 65.638,44.262 CN12.48@66.746,43.154
PE0: CN10.33 CN12.64 U14.138 | length 114.3
  Top Layer w0.12: v1(12.266,65.279) 12.695,64.851 13.838,64.851 14.586,65.599 14.586,66.121 15.133,66.668 16.037,66.668 16.999,65.706 22.589,65.706 22.741,65.554 U14.138@24.291,65.554
  Signal Layer 2 w0.12: v1@14.506,30.975 v1(14.506,31.004) ; v1@14.55,30.975 15.6,32.025 31.675,32.025 34.1,34.45 55.155,34.45 CN10.33@56.586,33.019 ; v1(55.941,24.129) 65.451,24.129 CN12.64@66.746,22.834
  Bottom Layer w0.12: v1(12.266,65.279) 12.211,65.224 12.211,32.359 13.566,31.004 v1(14.506,31.004) v1@14.511,30.999 ; v1(55.941,24.129) 55.916,24.154 55.916,26.754 55.721,26.949 55.721,32.154 CN10.33@56.586,33.019
PE1: CN11.61 R74.1 U14.139 | length 151.9
  Top Layer w0.127: v1(8.066,65.304) 8.016,65.254 8.016,65.229 8.638,64.607 13.939,64.607 14.829,65.498 14.829,66.02 15.234,66.424 15.936,66.424 16.898,65.462 22.435,65.462 22.844,65.054 U14.139@24.291,65.054
  Signal Layer 2 w0.12: v1(2.541,103.406) 2.543,103.404 6.666,103.404 9.616,100.454 11.593,100.454 11.598,100.459 11.934,100.459 12.234,100.159 33.571,100.159 v1(35.391,101.979)
  Signal Layer 2 w0.127: v1(1.991,55.304) 2.525,54.77 6.707,54.77 v1(7.341,55.404)
  Signal Layer 3 w0.12: v1@2.489,103.406 v1(2.541,103.406)
  Bottom Layer w0.12: 1.734,92.885 1.526,93.094 1.526,102.392 v1(2.541,103.406) ; v1(7.341,55.404) 7.131,55.614 7.131,56.545 7.611,57.025 7.611,58.886 7.876,59.151 7.876,65.114 7.879,65.118
  Bottom Layer w0.127: 1.734,92.885 2.073,92.547 3.705,92.547 4.354,91.898 4.354,87.915 4.802,87.467 6.245,87.467 6.894,86.818 6.894,83.36 6.245,82.71 4.678,82.71 4.354,82.387 4.354,75.615 4.962,75.007 6.345,75.007 7.134,74.217 7.134,66.597 7.879,65.852 7.879,65.491 v1(8.066,65.304) 7.879,65.118 ; v1(1.991,55.304) 1.536,54.849 1.536,38.233 3.091,36.679 3.694,36.679 4.354,36.018 4.354,35.1 3.705,34.45 2.215,34.45 1.049,33.285 1.049,27.595 CN11.61@3.246,25.399
  Bottom Layer w0.3: v1(35.391,101.979) R74.1@36.166,101.979
PE2: CN11.46 SB87.1 SB88.2 U14.1 | length 42.3
  Top Layer w0.12: CN11.46@5.786,45.719 9.303,45.719 10.408,44.614 14.167,44.614 14.477,44.304 26.066,44.304 v1(26.441,43.929)
  Top Layer w0.127: v1(26.266,59.279) U14.1@26.266,60.479
  Bottom Layer w0.12: SB88.2@22.491,57.529 22.591,57.429 SB87.1@23.841,57.429 ; v1(26.266,59.279) 25.334,59.279 23.841,57.786 SB87.1@23.841,57.429 ; v1(26.441,43.929) 26.235,44.134 26.235,53.561 24.567,55.23 24.567,57.354 24.492,57.429 SB87.1@23.841,57.429
PE3: CN9.22 CN11.47 U14.2 | length 47.6
  Top Layer w0.12: 25.241,42.07 25.834,42.07 v1(26.017,42.253)
  Top Layer w0.127: CN11.47@3.246,43.179 4.354,44.287 12.298,44.287 CN9.22@13.406,43.179 15.634,43.179 16.743,42.07 25.241,42.07 ; U14.2@26.866,60.479 v1(26.866,61.679)
  Bottom Layer w0.12: v1@26.016,42.254 26.016,42.879 26.846,43.709 26.846,44.097 26.482,44.46 26.482,53.664 24.814,55.333 24.814,58.409 25.258,58.854 26.419,58.854 26.866,59.301 v1(26.866,61.679)
PE4: CN9.16 CN11.48 U14.3 | length 40.1
  Top Layer w0.127: v1(6.766,49.704) 6.78,49.69 11.378,49.69 12.486,50.799 CN9.16@13.406,50.799 14.591,50.799 14.907,51.115 23.55,51.115 23.866,50.799 26.886,50.799 v1(26.891,50.804) ; v1(27.366,59.279) U14.3@27.366,60.479
  Bottom Layer w0.12: v1(26.891,50.804) 26.891,53.605 25.061,55.435 25.061,58.307 25.36,58.607 26.694,58.607 v1(27.366,59.279)
  Bottom Layer w0.127: CN11.48@5.786,43.179 6.916,44.309 6.916,49.554 v1(6.766,49.704)
PE5: CN9.18 CN11.50 U14.4 | length 46.6
  Top Layer w0.12: 14.511,47.153 v1(26.892,47.153)
  Top Layer w0.127: v1(7.391,47.15) 12.298,47.15 CN9.18@13.406,48.259 14.511,47.153 ; U14.4@27.866,60.479 v1(27.866,61.679)
  Bottom Layer w0.12: v1(26.892,47.153) 26.972,47.154 26.722,47.404 26.722,50.063 27.364,50.704 27.364,53.481 25.308,55.537 25.308,58.205 25.462,58.36 27.025,58.36 27.866,59.201 v1(27.866,61.679)
  Bottom Layer w0.127: CN11.50@5.786,40.639 7.166,42.019 7.166,46.925 v1(7.391,47.15)
PE6: CN11.62 SB10.1 SB85.2 SB86.2 U14.5 | length 152.1
  Top Layer w0.12: CN11.62@5.786,25.399 v1(23.291,25.399) ; v1(27.416,46.154) 40.741,46.154 41.106,46.519 54.128,46.519 v1(54.293,46.353)
  Top Layer w0.127: v1(28.366,59.279) U14.5@28.366,60.479
  Signal Layer 2 w0.12: v1(32.441,89.404) 32.676,89.169 46.258,89.169 46.423,89.334 54.436,89.334 54.468,89.302 v1(54.468,89.255)
  Signal Layer 3 w0.12: v1(54.468,89.255) v1@54.468,89.306
  Bottom Layer w0.12: v1(23.291,25.399) 23.491,25.599 23.491,39.104 26.422,42.035 26.422,42.46 27.696,43.734 27.696,44.761 27.202,45.255 27.202,45.954 27.402,46.154 v1(27.416,46.154) 27.416,46.426 27.777,46.787 27.777,47.52 27.442,47.854 27.442,49.764 28.084,50.406 28.084,56.786 SB85.2@27.341,57.529 ; SB86.2@25.991,57.529 SB85.2@27.341,57.529 ; v1(28.366,59.279) 27.341,58.254 SB85.2@27.341,57.529 ; SB10.1@31.516,89.179 31.741,89.404 v1(32.441,89.404) ; v1(54.293,46.353) 54.293,46.361 54.461,46.529 54.461,60.336 54.086,60.711 54.086,61.089 54.701,61.704 54.701,63.642 54.459,63.884 54.436,63.884 54.386,63.934 54.386,64.795 54.701,65.11 54.701,71.527 54.431,71.797 54.431,76.137 53.991,76.577 53.991,79.354 54.701,80.064 54.701,89.023 v1(54.468,89.255)
PE7: CN10.20 CN12.44 U14.57 | length 47.2
  Top Layer w0.127: U14.57@45.941,72.554 45.941,72.592 49.397,72.592 49.841,72.148 49.841,71.229 50.266,70.804 v1(52.566,70.804)
  Signal Layer 2 w0.12: v1(52.566,70.804) 52.57,70.804 53.15,71.385 55.291,71.385 55.481,71.575 55.481,71.577 56.128,72.224 59.584,72.224 60.104,71.704 v1(60.643,71.705) ; CN10.20@59.126,50.799 60.586,49.339 65.641,49.339 CN12.44@66.746,48.234
  Signal Layer 3 w0.12: v1@60.617,71.705 v1(60.643,71.705)
  Bottom Layer w0.12: CN10.20@59.126,50.799 60.231,51.904 60.231,66.923 60.382,67.074 60.384,67.074 60.621,67.311 60.621,67.697 60.471,67.847 60.471,71.532 v1(60.643,71.705)
PE8: CN10.18 CN12.40 SB47.1 U14.58 | length 46.5
  Top Layer w0.12: U14.58@45.941,73.054 v1(47.416,73.054) ; CN10.18@59.126,53.339 60.501,53.339 v1(60.741,53.579) 62.908,53.579 63.748,54.419 65.641,54.419 CN12.40@66.746,53.314
  Signal Layer 2 w0.12: v1(47.416,73.054) 49.173,71.297 52.723,71.297 53.051,71.625 55.191,71.625 55.241,71.674 55.241,71.676 56.029,72.464 60.451,72.464 v1(60.866,72.879)
  Bottom Layer w0.12: v1(47.416,73.054) 47.591,73.054 48.616,72.029 SB47.1@48.816,72.029 ; v1(60.741,53.579) 60.741,53.609 60.471,53.879 60.471,66.823 60.482,66.834 60.483,66.834 60.861,67.212 60.861,67.796 60.711,67.946 60.711,71.199 61.048,71.537 61.048,72.696 v1(60.866,72.879)
PE9: CN9.15 CN12.52 U14.59 | length 126.8
  Top Layer w0.12: U14.59@45.941,73.554 54.291,73.554 55.501,74.764 60.106,74.764 60.691,74.179 v1(61.116,74.179) ; v1@60.441,38.354 v1(60.441,38.379)
  Signal Layer 2 w0.12: v1(9.291,38.429) 9.291,38.479 9.308,38.496 9.308,38.737 9.858,39.287 13.781,39.287 14.024,39.044 24.351,39.044 24.941,38.454 36.187,38.454 36.492,38.149 38.89,38.149 39.625,38.884 45.238,38.884 45.798,38.324 46.134,38.324 46.694,38.884 49.283,38.884 49.663,39.264 59.556,39.264 v1(60.441,38.379) 61.326,39.264 65.556,39.264 CN12.52@66.746,38.074
  Bottom Layer w0.12: v1(9.291,38.429) 9.291,40.179 8.811,40.659 8.811,41.274 9.491,41.954 9.491,48.447 10.866,49.822 CN9.15@10.866,50.799 ; v1(60.441,38.379) 60.231,38.589 60.231,51.324 60.471,51.564 60.471,52.736 61.146,53.411 61.146,53.747 60.711,54.182 60.711,66.722 61.101,67.112 61.101,67.895 60.951,68.045 60.951,71.1 61.288,71.437 61.288,74.006 v1(61.116,74.179)
PE10: CN10.24 CN12.47 U14.60 | length 53
  Top Layer w0.12: U14.60@45.941,74.054 54.452,74.054 55.402,75.004 58.13,75.004 58.329,75.004 60.363,75.004 60.533,75.174 61.238,75.174 v1(61.243,75.18)
  Signal Layer 2 w0.12: CN10.24@59.126,45.719 60.201,45.719 v1(60.691,45.229) 62.766,43.154 CN12.47@64.206,43.154 ; v1@61.243,75.176 v1(61.243,75.18)
  Bottom Layer w0.12: v1(60.691,45.229) 60.471,45.449 60.471,51.204 60.711,51.444 60.711,52.637 61.386,53.312 61.386,53.846 60.951,54.281 60.951,66.623 61.341,67.013 61.341,67.995 61.191,68.145 61.191,71.001 61.528,71.338 61.528,74.841 61.243,75.126 v1(61.243,75.18)
PE11: CN10.6 CN12.56 U14.61 | length 66.8
  Top Layer w0.12: U14.61@45.941,74.554 54.612,74.554 55.302,75.244 58.156,75.244 v1(58.341,75.429)
  Signal Layer 2 w0.12: v1(58.616,31.679) 58.826,31.889 65.641,31.889 CN12.56@66.746,32.994
  Bottom Layer w0.12: v1(58.341,75.429) 58.021,75.109 58.021,69.684 CN10.6@59.126,68.579 58.021,67.474 58.021,43.804 57.691,43.474 57.691,32.604 v1(58.616,31.679)
PE12: CN10.26 CN12.49 U14.62 | length 52
  Top Layer w0.12: U14.62@45.941,75.054 46.866,75.054 47.001,74.919 54.638,74.919 55.203,75.484 57.521,75.484 v1(57.691,75.654)
  Signal Layer 2 w0.12: v1(57.541,44.054) 58.251,44.054 CN10.26@59.126,43.179 61.691,40.614 CN12.49@64.206,40.614
  Bottom Layer w0.12: v1(57.541,44.054) 57.781,44.294 57.781,75.644 57.771,75.654 v1(57.691,75.654)
PE13: CN10.10 CN12.55 U14.63 | length 70.6
  Top Layer w0.12: U14.63@45.941,75.554 46.891,75.554 47.286,75.159 54.538,75.159 55.103,75.724 57.178,75.724 57.513,76.059 57.859,76.059 58.084,75.834 v1@60.686,75.834 ; CN10.10@59.126,63.499 59.706,64.079 v1(61.368,64.079) ; v1(60.231,32.319) v1@60.241,32.329
  Signal Layer 2 w0.12: v1(60.231,32.319) 60.421,32.129 63.341,32.129 CN12.55@64.206,32.994
  Bottom Layer w0.12: v1(60.231,32.319) 60.231,33.477 59.584,34.124 58.411,34.124 57.931,34.604 57.931,36.469 58.456,36.994 59.629,36.994 60.846,38.211 60.846,44.811 61.096,45.061 61.096,52.682 61.626,53.212 61.626,53.945 61.191,54.38 61.191,63.902 v1(61.368,64.079) ; v1(60.876,75.732) 61.264,75.732 61.768,75.228 61.768,71.239 61.431,70.901 61.431,68.244 61.581,68.094 61.581,66.913 61.191,66.523 61.191,64.229
PE14: CN10.8 CN12.51 U14.64 | length 62.7
  Top Layer w0.12: U14.64@45.941,76.054 47.052,76.054 47.707,75.399 54.439,75.399 55.004,75.964 57.078,75.964 57.413,76.299 57.958,76.299 58.183,76.074 60.646,76.074 60.708,76.137 61.358,76.137 61.54,75.955 v1(61.643,75.955) ; CN10.8@59.126,66.039 60.407,66.039 60.841,65.604 v1(61.718,65.604)
  Signal Layer 2 w0.12: v1(60.741,37.529) 61.286,38.074 CN12.51@64.206,38.074 ; v1@61.616,75.927 v1(61.643,75.955)
  Bottom Layer w0.12: v1(60.741,37.529) 60.716,37.554 61.086,37.924 61.086,44.712 61.336,44.962 61.336,52.583 61.866,53.113 61.866,54.045 61.431,54.48 61.431,63.569 61.773,63.912 61.773,65.549 v1(61.718,65.604) 61.821,65.707 61.821,68.194 61.671,68.344 61.671,70.802 62.008,71.139 62.008,75.586 61.643,75.951 v1(61.643,75.955)
PE15: CN10.30 CN12.53 SB38.1 U14.65 | length 64.9
  Top Layer w0.127: 46.785,76.554 46.897,76.554 47.647,75.804 v1(50.516,75.804) 50.703,75.99 54.686,75.99 54.903,76.207 56.978,76.207 57.313,76.542 58.059,76.542 58.284,76.317 60.545,76.317 60.607,76.38 60.842,76.38 61.066,76.604 v1(61.041,76.629)
  Signal Layer 2 w0.12: v1(61.491,38.504) 61.139,38.504 60.609,37.974 59.251,37.974 60.101,37.124 62.616,37.124 CN12.53@64.206,35.534
  Bottom Layer w0.12: v1(50.516,75.804) 50.777,75.804 51.3,75.281 SB38.1@51.3,74.7 ; v1(61.041,76.629) 61.31,76.36 61.811,76.36 62.248,75.923 62.248,71.04 61.911,70.702 61.911,68.443 62.123,68.231 62.123,65.389 62.013,65.279 62.013,63.812 61.671,63.47 61.671,54.579 62.106,54.144 62.106,53.013 61.576,52.483 61.576,38.589 v1(61.491,38.504)
PF6: CN11.9 SB73.1 U14.20 | length 85.5
  Top Layer w0.127: v1(35.866,59.279) U14.20@35.866,60.479
  Signal Layer 2 w0.127: v1(2.016,59.004) 2.016,58.054 2.759,57.31 3.934,57.31 4.678,58.054 4.678,58.878 5.327,59.527 13.865,59.527 14.262,59.13 25.2,59.13 26.56,60.49 29.469,60.49 29.703,60.725 34.95,60.725 35.866,59.809 v1(35.866,59.279)
  Bottom Layer w0.127: v1(2.016,59.004) 1.309,59.71 1.309,71.378 2.482,72.55 3.705,72.55 4.354,73.2 4.354,74.118 3.705,74.767 1.653,74.767 1.049,75.37 1.049,82.229 1.531,82.71 3.705,82.71 4.354,83.36 4.354,86.818 3.382,87.79 2.787,87.79 2.138,88.44 2.138,90.33 CN11.9@3.246,91.439 ; SB73.1@35.116,63.254 34.941,63.079 34.941,60.204 v1(35.866,59.279)
PF7: CN9.26 CN11.11 U14.21 | length 121.1
  Top Layer w0.12: 23.171,38.099 23.592,38.099 v1(24.239,37.452)
  Top Layer w0.127: v1(1.991,36.804) 2.193,36.804 2.38,36.99 12.298,36.99 CN9.26@13.406,38.099 14.326,37.179 16.766,37.179 17.686,38.099 23.171,38.099 ; U14.21@36.366,60.479 v1(36.366,61.679)
  Bottom Layer w0.12: v1(24.239,37.452) 24.241,37.454 23.971,37.724 23.971,38.905 26.902,41.836 26.902,42.261 28.176,43.535 28.176,45.067 28.497,45.387 28.497,47.42 28.804,47.728 28.804,49.392 31.998,52.586 35.51,52.586 35.796,52.873 35.796,57.254 ; 35.791,57.254 35.791,57.601 36.366,58.176 v1(36.366,61.679)
  Bottom Layer w0.127: v1(1.991,36.804) 1.049,37.745 1.049,55.589 2.77,57.31 3.705,57.31 4.354,57.96 4.354,58.878 3.705,59.527 1.842,59.527 1.556,59.813 1.556,71.276 2.584,72.303 3.807,72.303 4.601,73.097 4.601,74.22 3.807,75.014 1.755,75.014 1.296,75.473 1.296,82.127 1.633,82.463 3.807,82.463 4.601,83.257 4.601,86.92 3.484,88.037 3.246,88.037 CN11.11@3.246,88.899
PF8: CN9.24 CN11.54 U14.22 | length 48.9
  Top Layer w0.127: CN9.24@13.406,40.639 14.591,41.823 25.591,41.823 25.595,41.827 27.364,41.827 v1(27.366,41.829) ; v1(36.866,59.279) U14.22@36.866,60.479
  Signal Layer 2 w0.127: CN11.54@5.786,35.559 9.758,39.53 12.298,39.53 CN9.24@13.406,40.639
  Bottom Layer w0.127: v1(27.366,41.829) 28.419,42.882 28.419,44.966 28.534,45.08 28.535,45.08 28.859,45.404 ; 28.915,45.46 28.859,45.404 ; v1(36.866,59.279) 36.866,58.332 36.066,57.532 36.066,52.798 35.575,52.307 32.119,52.307 29.957,50.145 29.957,46.497 28.864,45.404 28.859,45.404
PF9: CN9.28 CN11.56 U14.23 | length 55.2
  Top Layer w0.12: CN11.56@5.786,33.019 7.221,34.454 12.301,34.454 CN9.28@13.406,35.559
  Top Layer w0.127: CN9.28@13.406,35.559 13.411,35.554 v1(24.241,35.554) ; U14.23@37.366,60.479 v1(37.366,61.679)
  Bottom Layer w0.12: v1(24.241,35.554) 24.241,36.779 24.648,37.185 24.648,39.237 26.831,41.42 27.535,41.42 28.666,42.552 28.666,44.862 30.841,47.036 30.841,49.776 33.125,52.06 36.433,52.06 36.971,52.598 36.971,53.299 36.316,53.954 36.316,56.529 37.136,57.349 37.136,58.945 37.366,59.175 v1(37.366,61.679)
PF10: CN12.42 SB91.1 SB93.1 U14.24 | length 46.3
  Top Layer w0.12: v1(35.766,50.979) 44.791,50.979 47.516,53.704 48.416,53.704 v1(48.791,54.079) 49.196,53.674 53.875,53.674 54.371,53.674 55.836,52.209 65.311,52.209 CN12.42@66.746,50.774
  Top Layer w0.2: v1(37.866,59.279) U14.24@37.866,60.479
  Bottom Layer w0.12: v1(48.791,54.079) 48.791,54.104 SB93.1@48.791,54.929
  Bottom Layer w0.2: v1@35.666,50.979 v1(35.766,50.979) 36.216,50.979 38.041,52.804 38.041,55.454 37.766,55.729 SB91.1@37.191,55.729 37.191,56.929 37.416,57.154 37.416,58.829 v1(37.866,59.279)
PF11: CN12.62 SB40.1 U14.52 | length 74.7
  Top Layer w0.12: v1(55.491,26.079) 63.348,26.079 63.748,26.479 65.641,26.479 CN12.62@66.746,25.374
  Top Layer w0.127: v1(42.368,70.08) 42.341,70.053 42.341,70.004 42.544,69.801 44.816,69.801 45.069,70.054 U14.52@45.941,70.054 46.666,70.054 46.816,69.904 47.894,69.904 48.26,69.537 49.681,69.537 50.261,70.117 53.08,70.117 53.291,70.329 v1(53.316,70.329)
  Signal Layer 2 w0.127: v1@42.316,70.131 v1(42.368,70.08)
  Bottom Layer w0.12: v1(53.316,70.329) 53.316,69.775 53.096,69.555 53.096,68.155 52.871,67.93 52.871,66.012 52.973,65.91 52.973,62.188 52.856,62.07 52.856,59.11 53.261,58.705 53.261,55.384 52.648,54.771 52.648,54.222 53.741,53.129 53.741,48.316 53.296,47.871 53.296,45.913 55.201,44.008 55.201,36.604 55.481,36.324 55.481,26.089 v1(55.491,26.079)
  Bottom Layer w0.127: SB40.1@40.666,73.804 40.776,73.804 41.55,73.03 41.55,72.029 41.797,71.782 41.797,70.815 42.368,70.244 v1(42.368,70.08)
PF14: CN9.19 CN12.50 U14.53 | length 122.2
  Top Layer w0.12: U14.53@45.941,70.554 46.985,70.554 v1@47.166,70.372 ; v1@47.143,70.277 v1(47.143,70.33)
  Signal Layer 2 w0.12: v1(9.216,41.004) 9.391,41.004 10.131,41.744 13.864,41.744 14.511,41.097 14.511,39.434 14.661,39.284 36.357,39.284 36.517,39.124 45.788,39.124 45.798,39.134 46.134,39.134 46.144,39.124 49.184,39.124 49.564,39.504 65.636,39.504 CN12.50@66.746,40.614 68.683,40.614 v1(68.694,40.603) ; v1(47.143,70.33) 47.143,70.306 51.291,70.306 51.893,69.704 59.564,69.704 60.339,68.929 62.991,68.929 63.766,69.704 64.666,69.704 65.041,69.329 65.831,69.329 66.491,69.989 67.904,69.989 68.144,70.229 v1(68.516,70.229)
  Bottom Layer w0.12: v1(9.216,41.004) 9.741,41.529 9.741,44.594 CN9.19@10.866,45.719 ; v1(68.516,70.229) 68.721,70.024 68.721,50.907 68.386,50.572 68.386,49.999 68.961,49.424 68.961,40.87 v1(68.694,40.603)
PF15: CN9.21 CN12.60 U14.54 | length 144.4
  Top Layer w0.12: U14.54@45.941,71.054 46.991,71.054 47.548,70.497 ; 47.548,70.497 47.684,70.361 52.698,70.361 53.341,71.004 53.341,71.003 v1(53.318,70.98)
  Signal Layer 2 w0.12: v1(10.166,27.129) 14.479,27.129 15.35,28 27.25,28 29.55,30.3 30.6,30.3 33.675,33.375 54.175,33.375 55.875,31.675 55.875,27.85 56.916,26.809 v1(59.066,26.809) 65.641,26.809 CN12.60@66.746,27.914 ; v1(53.318,70.98) 54.354,69.944 59.663,69.944 60.438,69.169 62.281,69.169 v1(62.641,69.529)
  Bottom Layer w0.12: v1(10.166,27.129) 10.166,31.979 9.761,32.384 9.761,41.097 10.866,42.202 CN9.21@10.866,43.179 ; v1(59.066,26.809) 59.041,26.809 59.741,27.509 59.741,31.256 60.636,32.151 60.636,33.411 60.231,33.816 60.231,36.079 62.136,37.984 62.136,52.365 62.586,52.815 62.586,54.343 62.151,54.778 62.151,63.271 62.493,63.613 62.493,65.08 62.603,65.19 62.603,69.491 v1(62.641,69.529)
PG6: CN10.13 CN12.70 U14.86 | length 95.4
  Top Layer w0.12: U14.86@37.366,82.129 37.366,81.204 37.516,81.054 38.837,81.054 39.897,79.994 43.006,79.994 43.525,79.475 44.095,79.475 v1(44.641,78.929)
  Signal Layer 2 w0.12: v1(46.091,59.129) 46.096,59.124 55.881,59.124 CN10.13@56.586,58.419 57.716,57.289 65.001,57.289 v1(65.166,57.454)
  Bottom Layer w0.12: v1(44.641,78.929) 45.17,78.4 45.17,77.553 45.368,77.355 45.368,72.939 45.092,72.664 45.092,65.13 45.566,64.657 45.566,60.08 46.079,59.566 46.079,59.141 v1(46.091,59.129) ; v1(65.166,57.454) 65.394,57.226 65.394,44.162 65.641,43.915 65.641,42.696 66.288,42.049 67.621,42.049 68.049,41.621 68.049,40.336 68.721,39.664 68.721,34.359 68.339,33.977 68.339,33.61 68.866,33.083 68.866,17.334 CN12.70@66.746,15.214
PG7: CN12.67 SB100.2 U14.87 | length 85.2
  Top Layer w0.12: U14.87@36.866,82.129 36.866,81.154 37.206,80.814 38.738,80.814 39.798,79.754 42.907,79.754 43.707,78.954 v1(43.866,78.954)
  Signal Layer 2 w0.12: v1(53.625,19.25) 59.875,19.25 v1(59.9,19.275)
  Bottom Layer w0.12: v1(43.866,78.954) 44.296,78.524 44.707,78.524 44.93,78.301 44.93,77.453 45.128,77.256 45.128,73.038 44.852,72.763 44.852,65.015 45.326,64.542 45.326,59.98 45.686,59.62 45.686,58.961 46.284,58.363 46.284,53.764 46.566,53.482 46.566,50.607 50.513,46.66 50.513,33.687 53.575,30.625 53.575,19.3 v1(53.625,19.25)
  Bottom Layer w0.2: v1(59.9,19.275) 59.9,17.95 59.875,17.925 59.875,17.825 SB100.2@59.975,17.725
  Bottom Layer w0.3: SB100.2@59.975,17.725 60.004,17.754 CN12.67@64.206,17.754
PG8: CN12.66 SB31.2 SB34.2 U14.88 | length 85.8
  Top Layer w0.12: U14.88@36.366,82.129 36.366,81.229 37.021,80.574 38.638,80.574 39.698,79.514 42.456,79.514 43.041,78.929 v1(43.041,78.904)
  Signal Layer 2 w0.12: v1(53.125,21.225) 60.85,21.225 62.925,19.15 65.602,19.15 CN12.66@66.746,20.294
  Bottom Layer w0.12: v1(43.041,78.904) 43.966,77.979 SB31.2@43.966,77.654 SB34.2@43.966,76.279 44.888,75.357 44.888,73.138 44.612,72.863 44.612,64.998 44.336,64.722 44.336,64.157 45.086,63.407 45.086,59.881 45.446,59.52 45.446,58.862 46.044,58.264 46.044,53.664 46.326,53.382 46.326,50.249 50.1,46.475 50.1,33.55 53.1,30.55 53.1,21.25 v1(53.125,21.225)
PG9: CN11.63 SB35.2 SB41.2 U14.122 | length 100
  Top Layer w0.127: v1(2.041,74.304) 2.541,74.804 9.577,74.804 9.686,74.912 10.06,74.912 10.205,74.767 11.452,74.767 11.974,74.245 11.974,73.2 11.971,73.196 11.971,72.632 12.341,72.262 16.73,72.262 18.172,73.704 21.938,73.704 22.097,73.863 22.436,73.863 22.745,73.554 U14.122@24.291,73.554 v1(30.266,73.554)
  Signal Layer 2 w0.127: v1(2.041,74.304) 1.991,74.304 1.078,73.39 1.078,53.014 2.021,52.07 3.64,52.07 v1(3.641,52.069)
  Bottom Layer w0.127: CN11.63@3.246,22.859 4.391,24.004 6.116,24.004 6.966,24.854 6.966,26.004 6.341,26.629 4.991,26.629 4.516,27.104 4.516,28.504 3.841,29.179 2.541,29.179 1.776,29.943 1.776,31.064 2.383,31.67 3.805,31.67 4.594,32.46 4.594,33.688 5.117,34.21 6.345,34.21 7.134,35 7.134,38.318 6.245,39.207 4.862,39.207 4.354,39.715 4.354,51.34 3.641,52.054 v1(3.641,52.069) ; v1(30.266,73.554) 30.466,73.754 SB41.2@31.391,73.754 SB35.2@31.391,75.104
PG10: CN11.66 SB30.2 SB33.2 U14.123 | length 94.9
  Top Layer w0.12: v1(4.691,72.505) 4.651,72.464 6.343,72.464 6.788,72.019 16.831,72.019 18.267,73.455 v1(22.267,73.455) 22.266,73.404 22.51,73.16 22.809,73.16 22.915,73.054 U14.123@24.291,73.054
  Signal Layer 2 w0.12: v1(2.191,52.479) 1.321,53.348 1.321,59.882 2.141,60.702 2.141,61.679 v1(2.266,61.804) ; v1@4.691,72.479 v1(4.691,72.505)
  Bottom Layer w0.12: v1(2.191,52.479) 2.141,52.479 2.02,52.358 2.02,39.854 2.43,39.444 3.803,39.444 4.591,38.656 4.591,37.529 5.456,36.664 6.244,36.664 6.891,36.017 6.891,35.101 6.244,34.454 5.016,34.454 4.351,33.789 4.351,32.561 3.704,31.914 2.093,31.914 1.533,31.354 1.533,27.796 2.585,26.744 3.803,26.744 4.591,25.956 4.591,24.842 3.803,24.054 2.18,24.054 1.766,23.639 1.766,22.104 2.291,21.579 4.526,21.579 CN11.66@5.786,20.319 ; v1(2.266,61.804) 2.04,62.03 2.04,69.423 2.391,69.774 3.803,69.774 4.591,70.562 4.591,71.504 4.696,71.609 v1@4.696,72.499 ; SB30.2@20.991,77.804 SB33.2@20.991,76.454 21.091,76.454 21.591,75.954 22.031,75.514 22.031,73.69 v1(22.267,73.455)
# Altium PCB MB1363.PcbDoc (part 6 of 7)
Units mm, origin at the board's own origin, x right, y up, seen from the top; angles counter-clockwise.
Board outline 70 x 133.34 mm, 6 copper layers (Top Layer, Signal Layer 1, Signal Layer 2, Signal Layer 3, Signal Layer 4, Bottom Layer), stack 1.57 mm thick; 355 components, 293 nets, 1446 pads, 1145 vias.

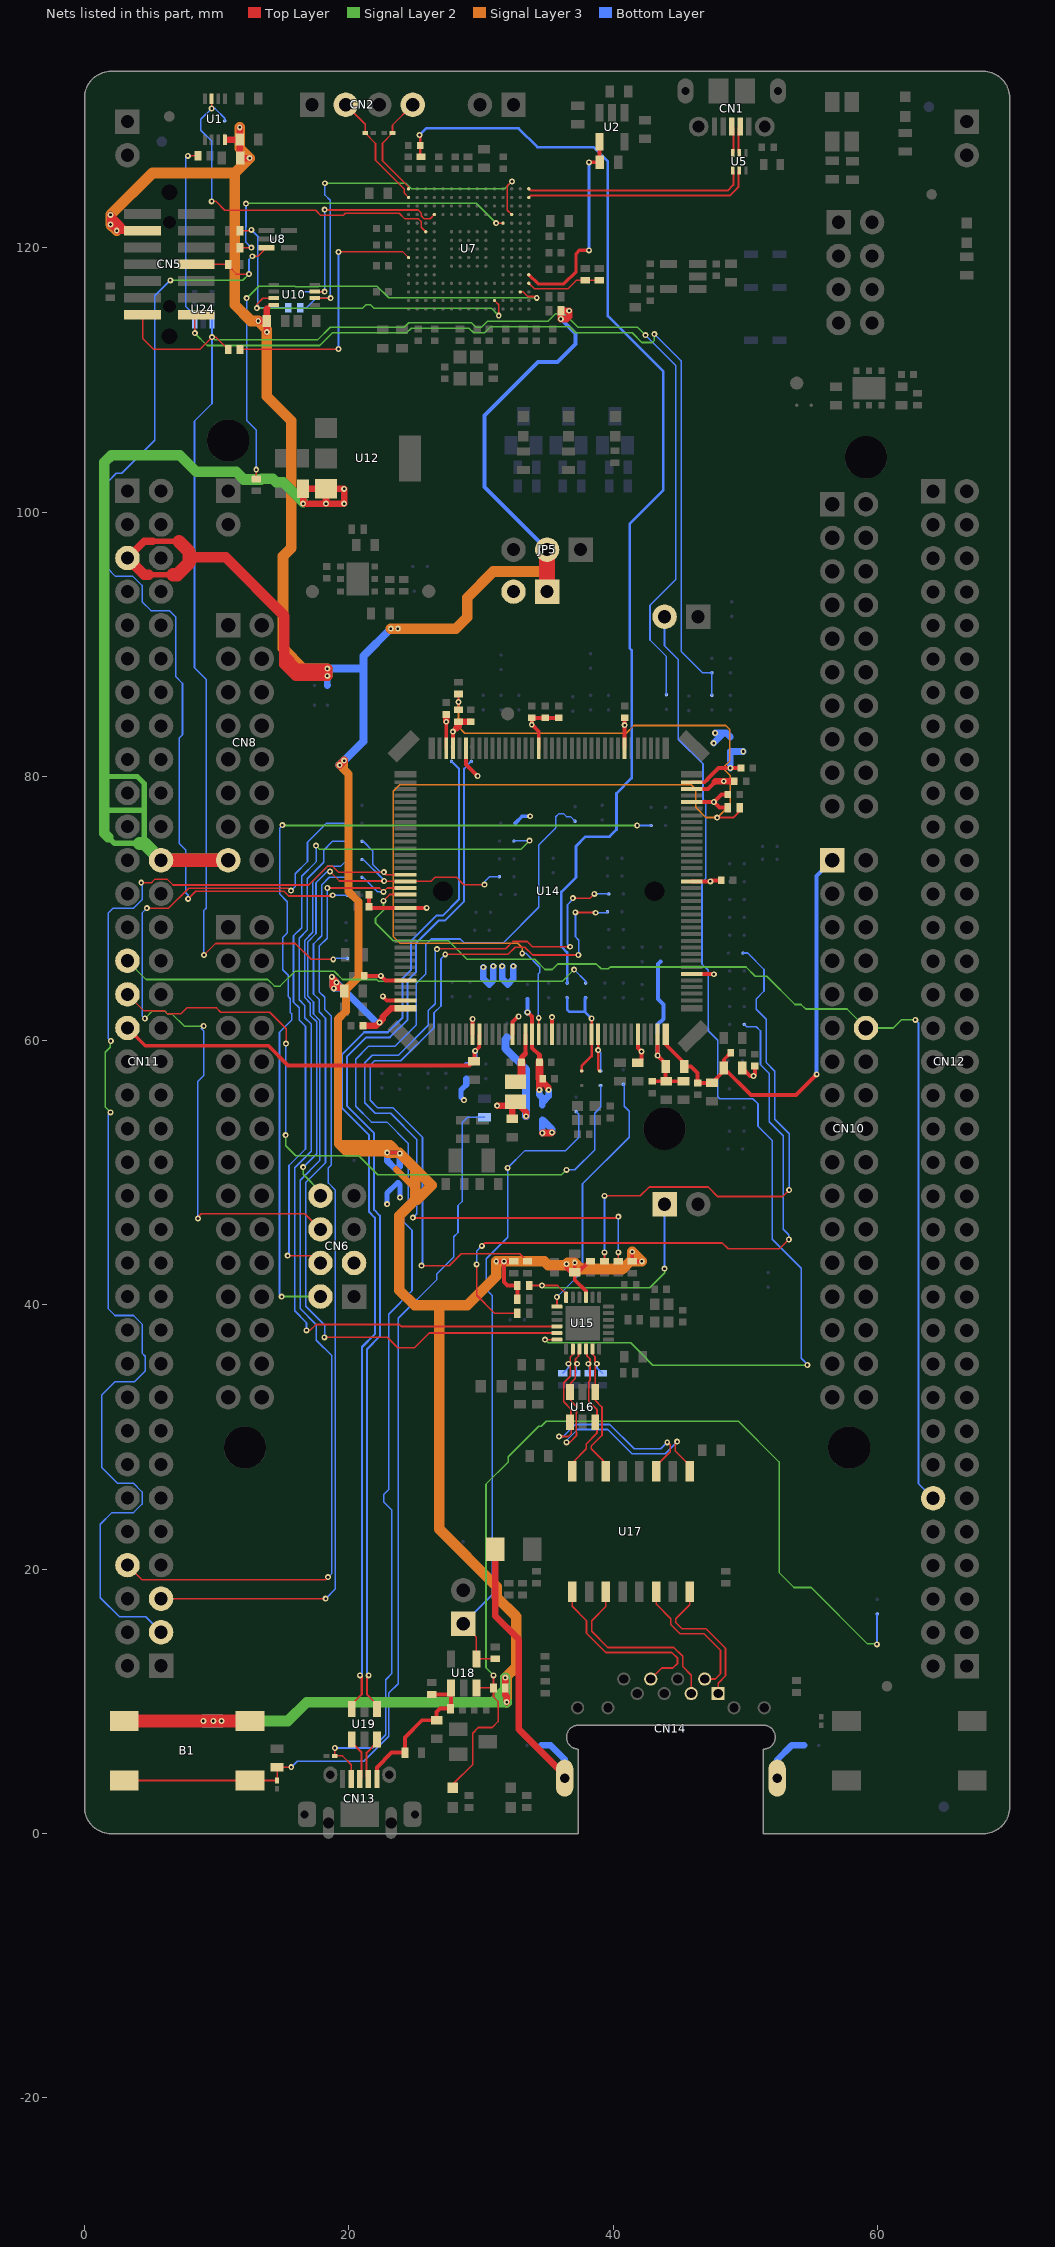
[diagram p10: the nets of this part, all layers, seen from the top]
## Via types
v1: diameter 0.45, hole 0.2, Top Layer to Bottom Layer, tented both sides, 1136 vias
v2: diameter 0.6, hole 0.3, Top Layer to Bottom Layer, tented both sides, 9 vias

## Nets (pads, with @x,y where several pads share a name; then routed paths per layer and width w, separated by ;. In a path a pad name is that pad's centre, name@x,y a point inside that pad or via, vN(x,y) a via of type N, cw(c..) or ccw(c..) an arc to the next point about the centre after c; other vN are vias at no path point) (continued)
PG11: CN11.70 SB36.2 U14.124 | length 95.1
  Top Layer w0.12: v1(4.291,71.954) 5.058,71.954 5.328,72.224 6.244,72.224 6.689,71.779 16.968,71.779 18.398,73.209 18.734,73.209 19.188,72.755 v1(22.642,72.755) 22.641,72.704 22.791,72.554 U14.124@24.291,72.554
  Signal Layer 2 w0.12: v1(1.966,54.579) 1.561,54.984 1.561,59.122 1.941,59.502 1.941,59.93 v1(1.991,59.979)
  Bottom Layer w0.12: v1(1.966,54.579) 1.78,54.393 1.78,39.729 2.305,39.204 3.704,39.204 4.351,38.557 4.351,36.366 4.598,36.119 4.598,34.999 3.806,34.207 2.316,34.207 1.293,33.184 1.293,27.696 2.485,26.504 3.704,26.504 4.351,25.857 4.351,24.941 3.704,24.294 2.081,24.294 1.191,23.404 1.191,17.854 2.641,16.404 4.621,16.404 CN11.70@5.786,15.239 ; v1(1.991,59.979) 1.8,60.17 1.8,69.663 2.151,70.014 3.704,70.014 4.351,70.661 4.351,71.894 v1(4.291,71.954) ; SB36.2@20.991,75.079 21.091,75.079 21.791,74.379 21.791,73.343 22.38,72.755 v1(22.642,72.755)
PG12: CN11.65 SB42.2 SB45.2 U14.125 | length 88.3
  Top Layer w0.12: CN11.65@3.246,20.319 4.351,19.214 18.226,19.214 v1(18.416,19.404) ; v1(18.566,72.804) 19.291,72.079 v1(22.666,72.079) 22.691,72.054 U14.125@24.291,72.054 26.216,72.054 26.541,72.379 28.116,72.379 28.691,71.804 v1(30.266,71.804)
  Bottom Layer w0.12: v1(18.416,19.404) 18.416,19.379 18.716,19.679 18.716,36.154 17.541,37.329 17.541,38.505 16.319,39.727 16.319,49.448 17.804,50.933 17.804,61.532 17.324,62.012 17.324,62.934 16.899,63.359 16.899,67.486 17.514,68.101 17.514,71.951 18.367,72.804 v1(18.566,72.804) ; SB42.2@20.991,73.704 21.091,73.704 22.666,72.129 v1(22.666,72.079) ; v1(30.266,71.804) 30.266,72.029 30.641,72.404 SB45.2@31.391,72.404
PG13: CN11.68 SB46.2 U14.126 | length 75.7
  Top Layer w0.12: CN11.68@5.786,17.779 v1(18.241,17.779) ; v1(18.366,71.554) 22.316,71.554 v1@22.604,71.266 ; v1@22.591,71.254 v1@22.604,71.266 ; v1(22.616,71.254) v1@22.604,71.266 ; U14.126@24.291,71.554 22.891,71.554 v1@22.604,71.266
  Bottom Layer w0.12: v1(18.241,17.779) 18.956,18.494 18.956,48.717 18.451,49.222 18.451,50.382 18.651,50.582 18.651,61.882 18.171,62.362 18.171,63.284 17.746,63.709 17.746,67.135 18.361,67.75 18.361,71.549 v1(18.366,71.554) ; SB46.2@20.991,72.354 21.091,72.354 22.191,71.254 v1(22.616,71.254)
PG14: CN10.12 CN12.61 U14.127 | length 85.4
  Top Layer w0.127: v1(22.616,70.579) 23.091,71.054 U14.127@24.291,71.054
  Signal Layer 2 w0.127: v1(22.616,70.579) 22.616,69.857 22.007,69.248 22.007,68.91 23.357,67.56 27.534,67.56 28.941,66.154 34.072,66.154 34.845,65.38 35.385,65.38 35.81,65.806 38.722,65.806 39.097,65.43 39.635,65.43 39.775,65.571 50.046,65.571 50.747,64.87 51.624,64.87 53.757,62.737 54.21,62.737 54.557,62.39 57.694,62.39 CN10.12@59.126,60.959 61.196,60.959 61.816,61.579 v1(62.866,61.579)
  Bottom Layer w0.127: v1(62.866,61.579) 63.098,61.347 63.098,26.482 CN12.61@64.206,25.374
PH0: CN11.29 SB71.2 | length 37.1
  Signal Layer 2 w0.12: CN11.29@3.246,66.039 4.656,64.629 13.865,64.629 14.365,64.129 14.791,64.129 15.916,65.254 18.891,65.254 19.516,64.629 22.118,64.629 22.248,64.499 36.161,64.499 v1(37.041,65.379)
  Bottom Layer w0.12: v1(37.041,65.379) 37.916,64.504 SB71.2@37.916,64.354
PH0-MCU: SB3.1 SB71.1 SB72.1 U14.25 | length 8.4
  Top Layer w0.2: SB3.1@37.616,57.704 37.616,58.091 38.366,58.841 U14.25@38.366,60.479 v1(38.366,61.679)
  Bottom Layer w0.2: SB72.1@36.516,63.254 36.516,62.354 36.691,62.179 37.866,62.179 ; SB71.1@37.916,63.254 37.866,63.204 37.866,62.179 ; v1(38.366,61.679) 37.866,62.179
PH1: CN11.31 SB90.2 | length 52.5
  Top Layer w0.12: CN11.31@3.246,63.499 4.466,62.279 6.029,62.279 6.284,62.024 7.286,62.024 7.741,62.479 9.984,62.479 10.309,62.154 14.016,62.154 15.266,60.904 15.266,59.779 v1(15.241,59.779)
  Signal Layer 2 w0.12: v1(15.216,52.854) 15.216,52.051 15.97,51.297 20.742,51.297 22.192,49.847 36.085,49.847 v1(36.463,50.226)
  Bottom Layer w0.12: v1(15.216,52.854) 15.216,59.754 v1(15.241,59.779) ; v1(36.463,50.226) 37.091,50.226 38.596,51.731 38.596,54.509 39.066,54.979 SB90.2@39.066,56.604
PH1-MCU: SB4.1 SB90.1 U14.26 | length 4.6
  Top Layer w0.127: U14.26@38.816,60.429 U14.26@38.866,60.479 ; 38.866,57.804 SB4.1@38.966,57.704
  Top Layer w0.2: 38.866,57.804 U14.26@38.866,60.479
  Signal Layer 2 w0.127: v1@38.866,59.176 v1(38.866,59.279)
  Bottom Layer w0.127: v1(38.866,59.279) 39.066,59.079 SB90.1@39.066,57.704
RD_N: R79.1 U15.22 U16.6 U17.8 | length 11.5
  Top Layer w0.11: 38.166,32.705 38.166,34.204
  Top Layer w0.13: U17.8@36.901,27.434 36.966,27.499 36.966,28.116 37.959,29.109 37.959,29.484 38.766,30.291 38.766,31.004 U16.6@38.641,31.129 38.766,31.254 38.766,32.105 38.166,32.705 ; U15.22@37.941,36.679 38.009,36.611 38.009,36.161 38.241,35.929 38.241,35.679 v1(38.116,35.554) 38.25,35.42 38.25,34.288 38.166,34.204
  Bottom Layer w0.13: R79.1@38.191,34.829 38.191,35.479 v1(38.116,35.554) v1@38.25,35.554
RD_P: R78.1 U15.23 U16.1 U17.6 | length 11.4
  Top Layer w0.13: U15.23@38.441,36.679 38.391,36.629 38.391,36.319 38.623,36.087 38.623,35.697 v1(38.766,35.554) 38.632,35.42 38.632,33.438 U16.1@38.641,33.429 38.641,32.781 39.148,32.274 39.148,30.133 38.341,29.326 38.341,29.134 39.441,28.034 U17.6@39.441,27.434
  Bottom Layer w0.13: v1(38.766,35.554) 38.766,35.254 R78.1@39.191,34.829
RMII_CRS_DV: R44.1 SB52.2 | length 54.4
  Top Layer w0.127: v1(25.491,42.979) 27.59,42.979 28.49,43.879 32.941,43.879 R44.1@33.516,43.304 ; v1(27.291,66.529) 32.041,66.529 32.591,67.079 33.316,67.079 33.914,66.481 34.418,66.481 34.42,66.479 v1(37.366,66.479) ; v1(37.141,69.704) 38.642,69.704 v1(38.667,69.68)
  Bottom Layer w0.127: v1(25.491,42.979) 25.572,43.06 25.572,52.698 23.341,54.929 22.166,54.929 21.616,55.479 21.616,58.152 21.943,58.479 23.935,58.479 26.443,60.987 26.443,62.102 26.966,62.626 26.966,66.204 v1(27.291,66.529) ; v1(37.141,69.704) 37.141,67.854 37.386,67.609 37.386,66.498 v1(37.366,66.479) ; v1(38.667,69.68) 39.492,69.68 SB52.2@39.566,69.754
RMII_MDC: SB84.1 U15.13 | length 19.3
  Top Layer w0.127: U15.13@35.741,39.879 v1(35.741,40.604)
  Bottom Layer w0.127: v1(35.741,40.604) 37.675,42.538 37.675,49.163 41.205,52.693 41.205,54.665 40.841,55.029 40.841,56.629 SB84.1@40.766,56.704
RMII_MDIO: JP7.1 R50.1 U15.12 | length 18.3
  Top Layer w0.127: R50.1@33.641,41.479 v1(34.616,41.479) 35.787,41.479 36.441,40.825 U15.12@36.441,40.579
  Signal Layer 2 w0.102: v1(34.616,41.479) 34.775,41.32 42.758,41.32 43.886,42.449 v1(43.886,42.749)
  Bottom Layer w0.127: v1(43.886,42.749) JP7.1@43.886,47.624
RMII_REF_CLK: R52.1 SB80.2 | length 49.4
  Top Layer w0.127: v1(29.666,43.079) 29.666,40.729 31.016,39.379 R52.1@32.741,39.379 ; v1(30.066,44.479) 30.274,44.687 48.261,44.687 48.698,44.25 52.587,44.25 v1(53.291,44.954)
  Bottom Layer w0.127: v1(29.666,43.079) 29.666,44.079 v1(30.066,44.479) ; SB80.2@49.916,61.229 50.093,61.052 50.814,61.052 51.141,60.725 51.141,58.176 51.798,57.52 51.798,53.87 52.873,52.795 52.873,45.738 53.286,45.324 53.286,44.959 v1(53.291,44.954)
RMII_RXD0: R47.1 SB63.1 | length 39.8
  Top Layer w0.127: R47.1@39.341,43.304 v1(39.341,43.979) ; v1(39.341,48.254) 42.041,48.254 42.716,48.929 47.191,48.929 47.918,48.202 52.814,48.202 v1(53.316,48.704)
  Bottom Layer w0.127: v1(39.341,43.979) v1(39.341,48.254) ; SB63.1@49.816,66.629 50.17,66.629 51.414,65.384 51.414,63.753 50.816,63.155 50.816,62.383 51.568,61.631 51.568,58.353 52.225,57.696 52.225,54.047 53.318,52.954 53.318,48.705 v1(53.316,48.704)
RMII_RXD1: R48.1 SB48.1 | length 62.5
  Top Layer w0.127: v1(24.841,46.604) 24.868,46.577 40.265,46.577 40.391,46.704 v1(40.391,46.679) ; v1(26.666,66.929) 26.693,66.956 31.864,66.956 32.414,67.506 33.493,67.506 33.895,67.104 v1(36.741,67.104) ; v1(36.951,70.78) 38.244,70.78 v1(38.568,71.104) ; R48.1@40.391,43.304 v1(40.391,43.979)
  Bottom Layer w0.127: v1(24.841,46.604) 25.145,46.908 25.145,52.521 23.164,54.502 21.989,54.502 21.189,55.302 21.189,58.329 21.766,58.906 23.758,58.906 26.016,61.164 26.016,62.279 26.539,62.803 26.539,66.802 v1(26.666,66.929) ; v1(36.741,67.104) 36.541,67.304 36.541,70.279 36.951,70.689 v1(36.951,70.78) ; v1(38.568,71.104) SB48.1@39.666,71.104 ; v1(40.391,43.979) v1(40.391,46.679)
RMII_TX_EN: SB36.1 U15.16 | length 59.6
  Top Layer w0.127: v1(16.791,38.079) 17.062,38.079 17.509,38.526 23.819,38.526 23.966,38.379 U15.16@35.741,38.379
  Bottom Layer w0.127: v1(16.791,38.079) 16.791,38.656 15.896,39.552 15.896,50.382 17.141,51.627 17.141,61.257 16.661,61.737 16.661,62.659 16.236,63.084 16.236,67.761 16.851,68.376 16.851,72.26 18.099,73.508 18.099,74.412 18.766,75.079 SB36.1@19.891,75.079
RMII_TXD0: SB46.1 U15.17 | length 56.7
  Top Layer w0.127: v1(18.141,37.554) 22.891,37.554 23.691,36.754 24.966,36.754 26.091,37.879 U15.17@35.741,37.879
  Bottom Layer w0.127: v1(18.141,37.554) 18.166,37.579 18.166,38.479 16.743,39.902 16.743,49.273 18.228,50.758 18.228,61.707 17.748,62.187 17.748,63.109 17.323,63.534 17.323,67.311 17.938,67.926 17.938,71.775 18.516,72.354 SB46.1@19.891,72.354
RMII_TXD1: JP6.2 U15.18 | length 84.4
  Top Layer w0.127: v1(34.841,37.379) U15.18@35.741,37.379
  Signal Layer 2 w0.102: v1(34.841,37.379) 35.091,37.129 41.316,37.129 42.066,36.379 42.991,35.454 v1(54.691,35.454)
  Bottom Layer w0.127: JP6.2@43.886,92.074 43.886,89.884 44.925,88.845 44.925,82.819 46.793,80.95 46.793,78.277 46.991,78.079 46.991,72.267 46.716,71.991 46.716,65.802 47.189,65.329 47.189,60.752 47.908,60.033 47.908,55.778 48.073,55.612 50.567,55.612 50.951,55.229 50.951,53.519 52.026,52.444 52.026,44.97 54.218,42.778 54.218,35.977 54.716,35.479 v1(54.691,35.454)
RX_N: CN14.6 U17.9 | length 14.1
  Top Layer w0.13: U17.9@36.901,18.284 36.901,17.199 37.984,16.116 37.984,15.161 39.441,13.704 44.426,13.704 44.871,13.259 44.871,12.884 44.516,12.529 43.668,12.529 CN14.6@42.839,11.7
RX_P: CN14.3 U17.11 | length 14.2
  Top Layer w0.13: U17.11@39.441,18.284 39.441,17.191 38.366,16.116 38.366,15.319 39.599,14.086 44.584,14.086 45.253,13.417 45.253,12.642 45.899,11.996 CN14.3@45.899,10.6
SHGND: C90.1 CN14.SH1 CN14.SH2 SB101.1 SB102.1 | length 27.2
  Top Layer w0.5: C90.1@31.066,21.529 31.066,16.484 32.866,14.684 32.866,7.884 CN14.SH2@36.35,4.4
  Bottom Layer w0.45: CN14.SH2@36.25,4.2 CN14.SH2@36.329,4.2
  Bottom Layer w0.5: SB101.1@34.575,6.675 35.275,6.675 36.329,5.621 CN14.SH2@36.329,4.2 ; CN14.SH2@36.25,4.2 CN14.SH2@36.3,4.15 ; CN14.SH1@52.409,4.2 52.409,5.584 53.5,6.675 SB102.1@54.45,6.675 ; CN14.SH1@52.425,4.225 CN14.SH1@52.425,4.45
SMPS_EN: CN6.4 SB35.1 | length 53.1
  Top Layer w0.12: v1(15.366,43.729) 17.301,43.729 CN6.4@17.851,43.179
  Signal Layer 2 w0.12: v1(17.516,74.754) 17.801,74.469 33.006,74.469 v1(33.666,75.129)
  Bottom Layer w0.12: v1(15.366,43.729) 15.366,43.754 15.472,43.86 15.472,50.558 16.717,51.803 16.717,61.081 16.237,61.561 16.237,62.483 15.812,62.908 15.812,67.937 16.427,68.552 16.427,72.435 17.516,73.524 v1(17.516,74.754) ; SB35.1@32.491,75.104 32.516,75.129 v1(33.666,75.129)
SMPS_PG: CN6.8 SB42.1 | length 28.7
  Signal Layer 2 w0.12: v1(16.541,50.429) 16.541,49.887 17.851,48.577 CN6.8@17.851,48.259
  Bottom Layer w0.12: v1(16.541,50.429) 17.564,51.452 17.564,61.432 17.084,61.912 17.084,62.834 16.659,63.259 16.659,67.586 17.274,68.201 17.274,72.085 18.398,73.209 19.396,73.209 SB42.1@19.891,73.704
SMPS_SW: CN6.6 SB33.1 | length 58.2
  Top Layer w0.12: v1(4.716,70.029) 4.701,70.014 6.353,70.014 7.878,71.539 15.431,71.539 v1(15.616,71.354) ; v1(8.586,46.549) 8.586,46.665 8.828,46.907 16.663,46.907 CN6.6@17.851,45.719
  Signal Layer 2 w0.12: v1(4.566,61.679) 5.166,62.279 6.029,62.279 6.284,62.024 6.621,62.024 7.541,61.104 v1(9.016,61.104)
  Bottom Layer w0.12: v1(4.566,61.679) 4.351,61.894 4.351,69.664 v1(4.716,70.029) ; v1(8.586,46.549) 8.571,46.549 8.571,56.911 9.021,57.361 9.021,60.739 8.836,60.924 v1(9.016,61.104) ; v1(15.616,71.354) 15.616,71.329 15.947,71.66 15.947,72.634 16.871,73.558 16.871,75.021 18.304,76.454 SB33.1@19.891,76.454
SMPS_V1: CN6.2 SB34.1 | length 67.7
  Signal Layer 2 w0.12: v1(14.916,40.628) 14.927,40.639 CN6.2@17.851,40.639 ; v1(14.966,76.304) 14.991,76.279 v1(41.816,76.279)
  Bottom Layer w0.12: v1(14.916,40.628) 14.916,40.639 14.751,40.804 14.751,60.641 15.671,61.561 15.671,62.031 15.568,62.134 15.568,63.174 15.403,63.339 15.403,64.955 14.998,65.361 14.998,67.804 15.336,68.142 15.336,70.519 14.781,71.074 14.781,76.094 14.966,76.279 v1(14.966,76.304) ; v1(41.816,76.279) SB34.1@42.866,76.279
STLK_MCO: C5.2 R5.2 SB72.2 | length 85.7
  Top Layer w0.2: v1(25.341,128.529) 25.391,128.479 C5.2@25.391,127.729 25.391,126.954 R5.2@25.466,126.879
  Bottom Layer w0.2: v1(25.341,128.529) 25.841,129.029 32.841,129.029 34.266,127.604 38.516,127.604 39.591,126.529 39.591,114.829 43.791,110.629 43.791,101.654 41.254,99.117 41.254,89.681 41.4,89.535 41.4,79.868 40.249,78.717 40.249,75.962 39.724,75.437 37.909,75.437 37.181,74.71 37.181,72.36 36.078,71.256 36.078,67.112 36.516,66.673 SB72.2@36.516,64.354
STLK_SWCLK: CN2.2 U3.1 U7.A14 | length 9
  Top Layer w0.12: CN2.2@19.756,130.809 21.229,129.336 U3.1@21.229,128.679 21.229,128.672 22.016,127.884 22.016,126.615 24.184,124.447 24.184,124.136 U7.A14@24.516,123.804
STLK_SWDIO: CN2.4 U4.1 U7.A15 | length 8.1
  Top Layer w0.12: U7.A15@24.516,124.454 24.516,124.604 22.541,126.579 22.541,127.909 23.303,128.672 U4.1@23.303,128.679 23.303,129.276 CN2.4@24.836,130.809
STLK_VCP_RX: SB13.1 U1.3 U7.C10 | length 27.5
  Top Layer w0.12: v1(9.616,123.504) 9.941,123.504 10.616,122.829 17.491,122.829 17.876,122.444 19.566,122.444 19.731,122.609 23.811,122.609 24.241,122.179 25.272,122.179 25.471,121.98 25.471,121.549 U7.C10@25.816,121.204 ; v1(9.616,130.529) U1.3@9.616,131.279
  Bottom Layer w0.12: v1(9.616,123.504) 9.616,128.079 8.8,128.895 8.8,129.713 v1(9.616,130.529) 9.871,130.529 10.6,129.8 SB13.1@10.6,129.6
STLK_VCP_TX: R23.1 U7.A7 | length 20.3
  Top Layer w0.12: R23.1@11.766,112.304 19.191,112.304 v1(19.216,112.329) ; v1(19.216,119.679) 24.091,119.679 U7.A7@24.516,119.254
  Bottom Layer w0.12: v1(19.216,112.329) v1(19.216,119.679)
T_NRSTa: R29.1 U7.P3 | length 38.1
  Top Layer w0.12: R29.1@12.991,102.504 v1(12.991,103.204) ; U7.P3@32.966,116.654 33.185,116.654 33.53,116.309 34.111,116.309 v1(34.216,116.204)
  Signal Layer 2 w0.12: v1(12.266,116.179) 13.171,117.084 15.922,117.084 15.972,117.034 17.683,117.034 17.733,117.084 22.134,117.084 23.014,116.204 v1(34.216,116.204)
  Bottom Layer w0.12: v1(12.266,116.179) 12.266,106.929 12.991,106.204 v1(12.991,103.204)
T_PWR_EN: R7.1 U2.4 U7.R5 | length 15.7
  Top Layer w0.25: U7.R5@33.616,117.954 34.316,117.254 36.266,117.254 37.191,118.179 37.191,119.554 37.441,119.804 v1(38.166,119.804) ; v1(38.166,126.454) 38.969,126.454 R7.1@38.973,126.459
  Top Layer w0.3: U2.4@38.966,128.014 38.973,128.006 R7.1@38.973,126.459
  Bottom Layer w0.25: v1(38.166,119.804) v1(38.166,126.454)
T_PWR_EXT: R14.2 R15.2 U7.R4 | length 5.8
  Top Layer w0.12: U7.R4@33.616,117.304 34.036,116.884 36.571,116.884 37.216,117.529 R14.2@37.891,117.529 R15.2@38.941,117.529
T_SWCLKa: R11.1 U7.M11 | length 24.4
  Top Layer w0.12: R11.1@11.766,120.004 v1(12.616,120.004) ; v1(31.141,121.854) U7.M11@31.666,121.854
  Signal Layer 2 w0.12: v1(12.216,123.329) 12.241,123.354 29.641,123.354 v1(31.141,121.854)
  Bottom Layer w0.12: v1(12.216,123.329) 12.216,121.552 12.211,121.547 12.211,120.409 v1(12.616,120.004)
T_SWDIO_IN: R70.2 U7.N12 U10.2 | length 30
  Top Layer w0.12: U10.2@17.416,116.179 v1(18.616,116.179) ; U7.N12@32.316,122.504 31.991,122.829 31.991,124.679 32.316,125.004 v1(32.341,125.004)
  Signal Layer 2 w0.12: v1(18.186,124.874) 24.321,124.874 24.741,124.454 31.791,124.454 v1(32.341,125.004)
  Bottom Layer w0.12: R70.2@16.316,115.454 16.791,115.454 17.516,116.179 v1(18.616,116.179) 18.591,116.204 18.591,123.581 18.186,123.986 v1(18.186,124.874)
T_SWDIOa: R10.2 R70.1 U7.L2 U10.7 | length 31.3
  Top Layer w0.12: R10.2@11.766,121.279 12.616,121.279 v1(12.616,121.354) ; v1(13.041,115.429) 13.041,115.729 13.491,116.179 U10.7@14.316,116.179 ; U7.L2@31.016,116.004 31.341,115.679 v1(31.341,114.854)
  Signal Layer 2 w0.12: v1(13.041,115.429) 21.043,115.429 21.298,115.684 21.634,115.684 21.889,115.429 30.766,115.429 v1(31.341,114.854)
  Bottom Layer w0.12: v1(12.616,121.354) 13.141,120.829 13.096,120.784 13.096,115.484 v1@13.066,115.454 ; v1(13.041,115.429) v1@13.066,115.454 ; R70.1@15.416,115.454 v1@13.066,115.454
T_SWO: CN5.8 R13.1 SB50.1 U8.3 | length 79
  Top Layer w0.12: v1(7.841,70.729) 8.411,71.299 15.098,71.299 15.448,70.949 18.711,70.949 v1(18.766,71.004) ; CN5.8@8.453,118.744 10.851,118.744 R13.1@10.866,118.729 10.866,118.629 11.491,118.004 v1(12.441,118.004) ; v1(12.691,119.354) 13.116,119.354 U8.3@13.766,120.004
  Signal Layer 2 w0.12: v1(6.491,117.529) 11.966,117.529 v1(12.441,118.004)
  Bottom Layer w0.12: v1(6.491,117.529) 5.319,116.356 5.319,105.431 2.816,102.929 2.403,102.929 1.766,102.292 1.766,95.704 2.341,95.129 3.659,95.129 4.351,94.437 4.351,93.219 5.026,92.544 6.401,92.544 6.891,92.054 6.891,87.555 7.413,87.033 7.413,83.145 7.166,82.898 7.166,74.919 7.653,74.432 7.653,71.192 7.841,71.004 v1(7.841,70.729) ; v1(12.441,118.004) 12.441,119.104 v1(12.691,119.354) ; v1(18.766,71.004) SB50.1@19.891,71.004
T_SWOa: SB5.1 U7.D12 U10.3 | length 17.6
  Top Layer w0.12: U10.3@17.416,116.679 v1(18.166,116.679) ; v1(18.166,122.879) 18.191,122.854 19.366,122.854 ; 19.366,122.849 25.252,122.849 25.471,122.63 25.471,122.418 25.69,122.199 26.161,122.199 U7.D12@26.466,122.504
  Bottom Layer w0.12: SB5.1@16.391,116.679 v1(18.166,116.679) v1(18.166,122.879)
T_VCP_RX: CN5.13 R23.2 SB17.2 SB64.1 U24.1 | length 134
  Top Layer w0.12: CN5.13@4.389,114.934 4.389,113.156 5.241,112.304 8.716,112.304 v1(9.641,113.229) 9.941,113.229 R23.2@10.866,112.304 ; v1(9.041,66.479) 9.915,67.354 15.945,67.354 17.145,66.154 v1(18.816,66.154)
  Signal Layer 2 w0.12: v1(9.641,113.229) 9.851,113.019 17.631,113.019 18.591,113.979 24.191,113.979 24.536,114.324 29.271,114.324 29.616,113.979 30.041,113.979 30.496,114.434 35.061,114.434 35.636,115.009 36.313,115.009 37.343,113.979 41.845,113.979 v1(42.443,113.382)
  Bottom Layer w0.12: v1@9.031,66.479 9.031,69.852 9.198,70.019 9.198,87.334 8.316,88.216 8.316,106.879 9.641,108.204 v1(9.641,113.229) U24.1@9.641,114.504 ; v1@19.016,66.229 SB64.1@19.891,66.229 ; v1(42.443,113.382) 44.721,111.103 44.721,94.884 42.781,92.944 42.781,90.314 44.025,89.07 SB17.2@44.025,86.175
T_VCP_TX: CN5.14 R3.1 SB12.1 SB16.2 U24.3 | length 82.6
  Top Layer w0.12: v1(7.816,126.954) R3.1@8.591,126.954 ; v1(8.341,113.529) 8.341,114.812 CN5.14@8.458,114.929
  Signal Layer 2 w0.12: v1(8.341,113.529) 9.271,112.599 17.805,112.599 18.765,113.559 24.365,113.559 24.71,113.904 29.097,113.904 29.442,113.559 30.261,113.559 30.716,114.014 36.714,114.014 37.169,113.559 41.436,113.559 42.166,112.829 42.975,112.829 43.116,112.97 v1(43.116,113.454)
  Bottom Layer w0.12: v1(7.816,126.954) 7.666,126.804 7.666,115.554 8.341,114.879 U24.3@8.341,114.504 v1(8.341,113.529) ; v1(43.116,113.454) 45.141,111.429 45.141,89.453 46.765,87.829 SB12.1@47.466,87.829 47.441,87.804 47.441,87.529 47.466,87.504 SB16.2@47.466,86.129
TD_N: R81.1 U15.20 U16.4 U17.3 | length 21.1
  Top Layer w0.13: v1@36.05,30.05 36.622,30.05 36.816,30.244 36.816,31.054 U16.4@36.741,31.129 36.801,31.189 36.801,32.13 36.256,32.675 36.256,34.105 36.75,34.6 36.75,35.42 v1(36.616,35.554) 36.759,35.697 36.759,36.062 36.991,36.294 36.991,36.629 U15.20@36.941,36.679 ; U17.3@43.251,27.434 43.251,27.839 44.309,28.897 44.309,29.416 v1@44.1,29.625
  Bottom Layer w0.13: v1(35.9,30.05) 36.23,30.05 37.139,30.96 39.74,30.96 41.58,29.12 43.607,29.12 v1(44.091,29.604) ; R81.1@36.191,34.829 36.616,35.254 v1(36.616,35.554)
TD_P: R80.1 U15.21 U16.3 U17.1 | length 21.6
  Top Layer w0.11: 37.216,30.379 37.216,31.815
  Top Layer w0.13: v1@36.475,29.6 36.712,29.6 37.216,30.104 37.216,30.379 ; 37.216,31.815 37.216,32.332 36.741,32.807 U16.3@36.741,33.429 36.741,34.05 37.132,34.441 37.132,35.42 v1(37.266,35.554) 37.141,35.679 37.141,35.904 37.373,36.136 37.373,36.611 U15.21@37.441,36.679 ; v1@44.837,29.637 44.691,29.491 44.691,28.954 45.791,27.854 U17.1@45.791,27.434
  Bottom Layer w0.13: v1(36.466,29.604) 36.466,29.746 37.297,30.578 39.582,30.578 41.422,28.738 43.925,28.738 v1(44.841,29.654) ; R80.1@37.191,34.829 37.191,35.479 v1(37.266,35.554)
TX_N: CN14.2 U17.14 | length 10.6
  Top Layer w0.13: U17.14@43.251,18.284 43.251,17.374 44.359,16.266 44.359,15.821 45.051,15.129 46.866,15.129 48.116,13.879 48.116,13.014 48.114,13.012 48.114,12.106 47.708,11.7 CN14.2@46.919,11.7
TX_P: CN14.1 U17.16 | length 11
  Top Layer w0.13: U17.16@45.791,18.284 45.791,17.316 44.741,16.266 44.741,15.979 45.209,15.511 47.024,15.511 48.498,14.037 48.498,12.856 48.496,12.854 48.496,11.947 47.939,11.39 CN14.1@47.939,10.6
USB_DEV_HS_CN_N: CN1.2 U5.5 | length 2.1
  Top Layer w0.155: U5.5@49.541,127.154 49.482,127.213 49.482,129.023 CN1.2@49.616,129.158
USB_DEV_HS_CN_P: CN1.3 U5.6 | length 2.1
  Top Layer w0.155: CN1.3@48.966,129.158 49.1,129.023 49.1,127.213 U5.6@49.041,127.154
USB_DEV_HS_N: U5.2 U7.R14 | length 17.5
  Top Layer w0.155: U7.R14@33.616,123.804 33.751,123.938 48.814,123.938 49.416,124.54 49.472,124.596 49.472,125.785 U5.2@49.541,125.854
USB_DEV_HS_P: U5.1 U7.R15 | length 16.8
  Top Layer w0.155: U7.R15@33.616,124.454 33.751,124.319 48.657,124.319 49.091,124.754 49.091,125.804 U5.1@49.041,125.854
USB_FS_CN_N: CN13.2 U19.6 | length 3.4
  Top Layer w0.155: CN13.2@21.473,4.139 21.338,4.273 21.338,6.122 22.116,6.9 U19.6@22.116,7.129
USB_FS_CN_P: CN13.3 U19.4 | length 3.4
  Top Layer w0.155: U19.4@20.216,7.129 20.216,6.9 20.957,6.158 20.957,4.273 CN13.3@20.823,4.139
USB_FS_ID: CN13.4 SB29.2 U22.1 | length 93.8
  Top Layer w0.12: v1(18.941,6.479) 18.941,5.891 U22.1@18.928,5.879 19.516,5.879 20.173,5.222 CN13.4@20.173,4.139
  Bottom Layer w0.12: v1(18.941,6.479) 21.791,6.479 22.786,7.474 22.786,11.647 23.251,12.112 23.251,24.479 22.646,25.084 22.646,25.666 23.011,26.031 23.011,39.303 24.776,41.068 24.776,45.654 24.151,46.279 24.151,47.103 24.482,47.433 24.482,52.246 22.889,53.838 21.714,53.838 20.526,55.027 20.526,58.604 21.491,59.569 23.483,59.569 25.096,61.182 25.096,64.321 25.801,65.026 25.801,67.253 26.242,67.694 28.426,67.694 28.716,67.404 31.691,67.404 34.376,70.089 34.376,74.803 35.661,76.088 35.661,76.949 35.896,77.184 36.234,77.184 36.464,76.954 36.766,76.954 SB29.2@37.116,76.604
USB_FS_N: SB26.2 U19.1 | length 78.8
  Top Layer w0.155: v1(21.491,11.979) 21.357,11.844 21.357,10.538 22.116,9.779 U19.1@22.116,9.429
  Bottom Layer w0.155: v1(21.491,11.979) 21.372,12.098 21.372,36.66 22.347,37.635 22.347,46.762 21.916,47.193 21.916,52.993 19.841,55.068 19.841,58.779 21.316,60.254 23.105,60.254 24.447,61.596 24.447,64.571 25.091,65.215 25.091,67.39 26.78,69.079 27.255,69.079 28.716,70.54 28.716,80.579 SB26.2@29.266,81.129
USB_FS_OVCR: LD7.2 R64.1 SB100.1 U18.3 | length 75.1
  Top Layer w0.12: LD7.2@27.866,3.479 27.866,3.729 29.366,5.229 29.366,7.604 29.791,8.029 30.841,8.029 31.291,8.479 31.291,10.004 30.941,10.354 R64.1@30.941,11.024 ; U18.3@29.641,11.024 R64.1@30.941,11.024 ; v1(30.941,11.979) R64.1@30.941,11.024
  Signal Layer 2 w0.12: v1(30.941,11.979) v1@30.944,11.981 ; v1@31,11.925 v1@30.944,11.981 ; v1(59.95,14.325) v1@59.921,14.354 ; v1@59.95,14.354 v1@59.921,14.354 ; v1@30.944,11.981 30.375,12.55 30.375,26.45 32.05,28.125 32.05,28.525 34.359,30.834 34.558,30.834 34.924,31.2 49.475,31.2 52.55,28.125 52.55,19.752 53.677,18.625 54.975,18.625 59.246,14.354 v1@59.921,14.354
  Bottom Layer w0.12: v1(59.95,14.325) 59.95,16.6 SB100.1@59.975,16.625 59.975,14.35 v1(59.95,14.325)
USB_FS_P: SB27.2 U19.3 | length 78.8
  Top Layer w0.155: U19.3@20.216,9.429 20.216,9.779 20.975,10.538 20.975,11.844 v1(20.841,11.979)
  Bottom Layer w0.155: v1(20.841,11.979) 20.991,12.129 20.991,36.818 21.966,37.793 21.966,46.604 21.535,47.035 21.535,52.835 19.46,54.91 19.46,58.937 21.158,60.635 22.947,60.635 24.066,61.754 24.066,64.729 24.71,65.373 24.71,67.548 26.622,69.46 27.097,69.46 28.335,70.698 28.335,80.56 SB27.2@27.766,81.129
USB_FS_PWR_EN: JP8.1 R59.1 SB91.2 U18.4 | length 49.1
  Top Layer w0.12: JP8.1@28.646,15.874 29.641,14.879 U18.4@29.641,13.224 29.646,13.229 R59.1@31.066,13.229
  Bottom Layer w0.12: JP8.1@28.646,15.874 30.85,18.078 30.85,40.725 30.4,41.175 30.4,43.5 32.016,45.116 v1(32.016,50.378) 33.292,51.655 36.367,51.655 37.391,52.679 37.391,54.429 SB91.2@37.191,54.629
USB_FS_VBUS: C91.2 CN13.1 R63.1 R65.1 U18.1 U21.1 | length 12.4
  Top Layer w0.3: CN13.1@22.123,4.139 22.123,5.011 23.241,6.129 U21.1@24.241,6.129 24.241,7.279 25.541,8.579 C91.2@26.641,8.579 26.641,9.204 26.891,9.454 R65.1@27.691,9.454 27.741,9.504 U18.1@27.741,10.629 ; R63.1@26.266,10.529 27.641,10.529 U18.1@27.741,10.629 ; U18.1@27.741,11.024 U18.1@27.741,10.629
VBAT: C63.2 CN11.33 SB83.2 U14.8 | length 31.2
  Top Layer w0.3: CN11.33@3.246,60.959 4.591,59.614 13.901,59.614 15.381,58.134 29.146,58.134 C63.2@29.466,58.454 29.516,58.504 29.516,59.189 v1(29.556,59.229) 29.864,59.537 29.864,60.476 U14.8@29.866,60.479
  Bottom Layer w0.3: SB83.2@28.866,58.229 29.241,58.229 29.564,58.551 29.564,59.221 v1(29.556,59.229)
VCAP: C54.2 C58.2 R35.1 SB75.1 U14.68 U14.103 U14.140 | length 13
  Top Layer w0.3: C58.2@21.166,64.904 v1(22.416,64.904) 22.766,64.554 U14.140@24.291,64.554 ; U14.103@28.866,82.129 28.866,80.904 v1(29.741,80.029) ; U14.68@45.941,78.054 v1(47.616,78.054) ; R35.1@48.666,77.629 48.041,77.629 v1(47.616,78.054) ; C54.2@48.666,78.629 48.191,78.629 v1(47.616,78.054)
  Bottom Layer w0.5: 31.594,64.681 31.594,64.701 ; v1(31.594,65.629) 31.594,64.701 ; SB75.1@32.005,64.29 31.594,64.701 ; SB75.1@32.015,64.253 32.444,64.681 v1(32.444,65.629)
VDD: B1.1 B1.2 C4.1 C26.1 C79.2 CN5.3 CN11.5 JP4.1 JP5.2 R4.2 R20.2 R43.2 R46.2 R49.2 R50.2 R51.2 R64.2 SB14.1 SB97.2 U1.8 U10.8 U15.9 | length 357.7
  Top Layer w0.3: U1.8@10.616,128.179 10.825,128.179 ; 13.791,115.391 14.079,115.679 U10.8@14.316,115.679 ; v1(22.891,51.523) 23.808,51.523 v1(23.854,51.478) ; v1(31.15,43.3) 31.154,43.304 v1(31.741,43.304) ; R43.2@32.466,43.304 v1(31.741,43.304) ; R51.2@32.741,40.429 R50.2@32.741,41.479 32.016,41.479 31.741,41.754 v1(31.741,43.304) ; v1(36.466,43.104) 36.466,42.784 36.771,42.479 C79.2@37.091,42.479 ; v1(37.091,43.204) C79.2@37.091,42.479 ; U15.9@37.941,40.579 37.941,41.054 37.091,41.904 C79.2@37.091,42.479 ; R46.2@38.291,43.304 38.154,43.304 37.329,42.479 C79.2@37.091,42.479 ; v1(41.441,44.029) R49.2@41.441,43.304 v1(42.166,43.304)
  Top Layer w0.4: 4.846,95.249 6.701,95.249
  Top Layer w0.45: 5.154,97.789 7.126,97.789
  Top Layer w0.5: CN5.3@4.389,121.284 CN5.3@3.161,121.284 ; 10.825,128.179 C4.1@11.741,128.179 ; v1(11.741,129.104) C4.1@11.741,128.179 ; v1(12.491,126.779) R4.2@11.766,126.779 11.741,126.804 C4.1@11.741,128.179 ; v1(13.141,114.454) C26.1@13.791,114.454 ; v1(13.791,113.604) C26.1@13.791,114.454 ; 13.791,115.391 C26.1@13.791,114.454 ; v1(31.841,11.804) R64.2@31.841,11.024 31.841,10.479 31.941,10.379 v1(31.941,9.954) ; v1(2.436,121.284) 2.436,122.009 ; v1(2.436,121.284) CN5.3@3.161,121.284 ; v1(2.436,121.284) v1(1.966,121.754) v1(1.966,122.479) 2.436,122.009 ; 2.436,122.009 CN5.3@3.161,121.284 ; v1(36.041,114.604) 36.491,114.604 36.666,114.779 v1(36.666,115.229) R20.2@36.041,115.229 v1(36.041,114.604)
  Top Layer w0.6: CN11.5@3.246,96.519 4.516,97.789 5.154,97.789 ; 7.126,97.789 7.136,97.779 ; v1(19.3,80.85) v1(19.637,81.188)
  Top Layer w0.8: CN11.5@3.246,96.519 4.516,95.249 4.846,95.249 ; 7.911,96.149 8.337,96.575 10.675,96.575 15.125,92.125 15.125,89.075 ; 15.125,89.075 16.05,88.15 v1(18.375,88.15) v1(18.375,87.6) 16,87.6 15.125,88.475 15.125,89.075
  Top Layer w1: B1.1@3.017,8.523 v1(8.991,8.523) v1(9.741,8.523) v1(10.366,8.523) B1.2@12.517,8.523 ; 6.701,95.249 7.011,95.249 7.911,96.149 7.911,97.004 7.136,97.779
  Top Layer w1.2: JP4.1@34.996,93.979 JP5.2@34.996,97.154
  Signal Layer 2 w0.3: v1(22.891,51.523) 23.808,51.523 v1(23.854,51.478)
  Signal Layer 2 w0.45: v1(18.375,87.6) v1(18.375,88.15)
  Signal Layer 2 w0.5: v1(1.966,122.479) v1(1.966,121.754) v1(2.436,121.284)
  Signal Layer 2 w0.8: v1(8.991,8.523) v1(9.741,8.523) v1(10.366,8.523) 15.373,8.523 16.804,9.954 30.875,9.954 ; v1(31.841,11.804) 31.841,10.92 ; 30.875,9.954 v1(31.941,9.954) 31.841,10.054 31.841,10.92 ; 30.875,9.954 31.841,10.92
  Signal Layer 2 w1: JP4.1@34.996,93.979 JP5.2@34.996,97.154
  Signal Layer 3 w0.5: v1(13.791,113.604) v1@13.791,113.804 ; 23.575,50.275 25.025,48.825 25.025,48.525
  Signal Layer 3 w0.6: v1(23.854,51.478) 23.808,51.523 23.156,52.175 19.175,52.175 ; 19.175,52.175 19.175,61.63 19.766,62.221 19.766,63.866 19.787,63.866 20.741,64.821 20.741,70.512 19.965,71.288 19.965,80.185 19.637,80.513 ; 19.175,52.175 19.475,51.875 ; 19.475,51.875 22.539,51.875 v1(22.891,51.523) 19.827,51.523 19.475,51.875 ; 19.637,80.513 v1(19.637,81.188) v1(19.3,80.85) 19.637,80.513
  Signal Layer 3 w0.8: v1(2.436,121.284) v1(1.966,121.754) v1(1.966,122.479) 5.141,125.654 11.366,125.654 ; v1(11.741,129.104) 11.741,127.529 v1(12.491,126.779) 11.366,125.654 ; v1(13.791,113.604) 13.791,108.759 15.641,106.909 15.641,97.279 15.016,96.654 15.016,89.692 16.558,88.15 ; v1@13.791,113.804 v1(13.141,114.454) 12.591,114.454 11.366,115.679 11.366,125.654 ; v1(22.891,51.523) v1@23.808,51.523 ; v1(23.175,91.175) v1(23.7,91.175) 28.075,91.175 28.95,92.05 28.95,93.525 30.925,95.5 34.771,95.5 34.996,95.725 ; v1(23.854,51.478) 25.025,50.306 ; 25.025,48.525 25.025,47.95 ; 25.025,48.825 25.025,50.306 ; v1(31.941,9.954) 31.941,11.704 v1(31.841,11.804) 32.65,12.613 32.65,16.425 31.2,17.875 31.2,18.675 26.825,23.05 26.825,39.975 ; 16.558,88.15 17.108,87.6 v1(18.375,87.6) v1(18.375,88.15) 16.558,88.15 ; 25.025,47.95 23.825,46.75 23.825,41.123 24.973,39.975 26.825,39.975 ; 25.025,47.95 25.169,47.95 26.275,49.056 25.025,50.306 ; 26.825,39.975 28.95,39.975 31.15,42.175 v1(31.15,43.3) 31.154,43.304 v1(31.741,43.304) 34.796,43.304 35.096,43.004 36.366,43.004 v1(36.466,43.104) 36.566,43.204 v1(37.091,43.204) 37.57,42.725 40.7,42.725 41.279,43.304 ; 41.279,43.304 41.441,43.466 v1(41.441,44.029) v1(42.166,43.304) 41.279,43.304
  Signal Layer 3 w1: v1(8.991,8.523) v1(9.741,8.523) v1(10.366,8.523) ; JP4.1@34.996,93.979 34.996,95.725 JP5.2@34.996,97.154
  Bottom Layer w0.3: JP5.2@34.996,97.154 30.25,101.9 30.25,107.3 34.3,111.35 35.775,111.35 37.15,112.725 37.15,113.495 v1(36.041,114.604) v1(36.666,115.229)
  Bottom Layer w0.5: v1(1.966,122.479) v1(1.966,121.754) v1(2.436,121.284) ; v1(13.141,114.454) 13.141,114.254 v1(13.791,113.604) ; v1(18.375,87.6) SB14.1@18.375,86.875 SB14.1@18.379,86.879 ; v1(22.891,51.523) 22.891,50.934 23.475,50.35 SB97.2@23.725,50.35 23.854,50.479 v1(23.854,51.478)
  Bottom Layer w0.6: v1(18.375,87.6) v1(18.375,88.15) 21.1,88.15 ; v1(19.3,80.85) v1(19.637,81.188) 21.1,82.65 21.1,88.15 ; v1(23.7,91.175) v1(23.175,91.175) 21.1,89.1 21.1,88.15
  Bottom Layer w1: v1(8.991,8.523) v1(9.741,8.523) v1(10.366,8.523) ; JP4.1@34.996,93.979 JP5.2@34.996,97.154
VDD_LDO: C51.1 C53.1 R34.1 SB25.1 SB76.1 U14.70 U14.105 U14.143 | length 13.8
  Top Layer w0.3: v1(22.566,63.353) 22.865,63.054 U14.143@24.291,63.054 ; U14.105@27.866,82.129 v1(27.866,83.379) 28.116,83.629 ; U14.70@45.941,79.054 47.166,79.054 47.691,79.579
  Top Layer w0.5: 28.116,83.629 28.291,83.804 R34.1@28.291,84.129 C51.1@29.216,84.129 ; 47.691,79.579 47.741,79.629 v1(48.366,79.629) C53.1@49.166,79.629
  Bottom Layer w0.5: v1(30.171,65.554) 30.171,64.698 SB76.1@30.616,64.253 30.925,64.561 30.925,65.617 v1(30.936,65.629) ; v1(47.604,82.516) 48.366,83.279 ; v1(47.719,83.279) 48.366,83.279 ; SB25.1@48.866,82.979 48.566,83.279 48.366,83.279
VDD_MCU: C46.2 C47.2 C48.2 C49.2 C50.2 C52.2 C55.2 C56.2 C57.2 C59.2 C62.1 C67.2 JP4.2 R37.2 R40.1 SB25.2 SB32.2 SB83.1 SB92.2 U14.7 U14.13 U14.19 U14.32 U14.42 U14.56 U14.71 U14.79 U14.92 U14.106 U14.129 U14.144 | length 56.5
  Top Layer w0.3: C56.2@21.516,71.029 C57.2@21.516,70.129 21.516,70.054 U14.129@24.291,70.054 v1(25.881,70.054) ; U14.106@27.366,82.129 v1(27.366,84.129) ; U14.7@29.366,60.479 v1(29.366,61.644) ; U14.13@32.366,60.479 32.366,61.411 v1@32.743,61.788 ; U14.92@34.366,82.129 34.366,83.379 v1(33.839,83.906) C47.2@33.839,84.429 C48.2@34.866,84.429 C49.2@35.866,84.429 ; U14.19@35.366,60.479 v1(35.366,61.778) ; U14.79@40.866,82.129 C50.2@40.866,84.429 ; C67.2@41.866,58.329 42.141,58.604 v1(42.141,59.179) 41.866,59.454 U14.32@41.866,60.479 ; U14.42@45.941,65.054 47.585,65.054 v1(47.616,65.023) ; U14.56@45.941,72.054 v1(47.356,72.054) 47.431,72.129 C55.2@48.166,72.129 ; U14.71@45.941,79.554 46.916,79.554 47.139,79.777 47.139,79.808 47.96,80.629 v1(48.866,80.629) C52.2@49.666,80.629 ; R40.1@49.766,57.929 50.366,57.329 v1(50.616,57.329) 50.716,57.429 C62.1@50.716,58.079
  Top Layer w0.4: v1@19.016,63.954 19.066,64.004 v1(19.066,64.404) ; v1@19.016,63.954 v1(18.866,63.954) 18.816,63.954 18.716,64.054 v1(18.716,64.829) 19.066,64.479 v1(19.066,64.404) ; v1@19.016,63.954 19.465,63.954 R37.2@19.666,63.753 19.666,63.804 v1(19.066,64.404)
  Top Layer w0.5: C59.2@21.066,61.129 22.066,61.129 v1(22.316,61.379) 22.566,61.629 22.566,61.809 23.211,62.454 U14.144@24.291,62.454 ; v1(27.366,84.129) C46.2@27.366,84.679 ; v1(34.641,53.016) 35.332,53.016 v1(35.366,53.051)
  Signal Layer 2 w0.3: v1(34.641,53.016) 35.332,53.016 v1(35.366,53.051)
  Signal Layer 2 w0.4: v1(18.716,64.829) 18.716,64.754 v1(19.066,64.404) 18.866,64.204 v1(18.866,63.954)
  Bottom Layer w0.3: SB32.2@32.591,76.454 33.116,76.979 v1(33.716,76.979)
  Bottom Layer w0.4: v1(18.866,63.954) 18.716,64.104 v1(18.716,64.829) 19.066,64.479 v1(19.066,64.404) ; v1(28.71,55.498) 28.489,55.719 28.489,56.276 28.866,56.654
  Bottom Layer w0.5: 19.697,63.772 19.516,63.954 ; v1(22.316,61.379) 22.091,61.379 19.516,63.954 ; 28.866,56.654 SB83.1@28.866,57.129 ; v1(34.641,53.016) SB92.2@34.641,54.029 35.366,53.304 v1(35.366,53.051) ; v1(48.866,80.629) SB25.2@48.866,81.879 v1(49.841,81.879) ; 19.516,63.954 v1(19.066,64.404) 19.066,64.154 v1(18.866,63.954) 19.516,63.954
  other v1: 32.841,61.829 40.866,83.879
VDD_SMPS_IN: C65.2 C68.2 SB74.2 SB92.1 U14.16 | length 10.7
  Top Layer w0.3: v1(33.516,62.144) 33.839,61.821 33.839,61.51 33.866,61.483 U14.16@33.866,60.479 33.866,59.454 34.416,58.904
  Top Layer w0.4: C65.2@34.416,58.379 34.416,58.904
  Top Layer w0.5: v1(34.416,56.279) 34.416,57.129 35.068,56.476 v1@35.068,56.376
  Top Layer w0.6: C68.2@34.416,57.129 C65.2@34.416,58.379
  Bottom Layer w0.3: v1@33.509,62.151 SB74.2@33.509,63.153
  Bottom Layer w0.5: v1@33.509,62.151 v1(33.516,62.144) ; v1(34.416,56.279) 34.416,55.894 34.641,55.669 34.641,55.329 ; SB92.1@34.641,55.129 34.641,55.329 ; v1(35.116,56.279) 35.116,55.804 34.641,55.329
VDD_SMPS_IND_OUT: C75.2 L1.2 SB79.2 | length 10.7
  Top Layer w0.5: v1(31.216,55.079) 32.316,55.079 L1.2@32.366,55.129 ; C75.2@32.366,54.079 L1.2@32.366,55.129 ; v1(33.416,54.279) 33.416,54.579 L1.2@32.616,55.379 L1.2@32.366,55.129
  Bottom Layer w0.6: SB79.2@31.966,60.229 31.839,60.102 31.839,59.406 33.416,57.829 v1(33.416,54.279)
VDD_SMPS_OUT: C64.2 L1.1 U14.15 | length 3.9
  Top Layer w0.3: 33.366,59.029 U14.15@33.366,60.479
  Top Layer w0.4: C64.2@33.066,58.379 33.066,58.729 33.366,59.029
  Top Layer w0.5: L1.1@32.616,56.879 L1.1@33.066,57.329
  Top Layer w0.6: L1.1@33.066,57.329 C64.2@33.066,58.379
VDDA: C61.1 C72.1 C73.2 CN10.1 R39.1 R40.2 U14.36 | length 34.2
  Top Layer w0.3: U14.36@43.966,60.479 43.966,59.729 45.366,58.329 R39.1@45.366,58.054 45.891,58.054 46.391,57.554 C73.2@46.391,56.804 C72.1@47.466,56.804 48.366,57.704 R40.2@48.366,57.929 ; C61.1@48.891,59.079 48.366,58.554 R40.2@48.366,57.929 ; v1(55.391,57.454) 53.816,55.879 50.416,55.879 R40.2@48.366,57.929
  Bottom Layer w0.3: v1(55.391,57.454) 55.391,72.464 CN10.1@56.586,73.659
VFBSD: R33.1 R34.2 R35.2 U14.17 | length 88.7
  Top Layer w0.127: R34.2@28.291,85.029 v1(28.291,85.629) R33.1@28.291,86.229 ; U14.17@34.366,60.479 v1(34.366,61.729) ; v1(47.866,76.879) 49.091,76.879 49.566,77.354 R35.2@49.566,77.629
  Signal Layer 3 w0.127: v1(28.291,85.629) 28.291,83.759 28.78,83.27 40.995,83.27 41.575,83.85 48.525,83.85 48.825,83.55 48.825,81.166 48.458,80.798 48.458,80.46 48.85,80.067 48.85,77.863 v1(47.866,76.879) 47.021,76.879 46.25,77.65 46.25,79.025 45.905,79.37 23.858,79.37 23.366,78.879 23.366,67.879 23.866,67.379 32.771,67.379 33.116,67.034 v1(33.116,66.611)
  Bottom Layer w0.127: v1(33.116,66.611) 33.4,66.611 34.45,65.561 34.45,65.156 34.336,65.042 34.336,61.759 v1(34.366,61.729)
VIN: C42.2 CN8.15 CN11.24 U12.3 | length 80.6
  Top Layer w0.5: v1@18.266,100.654 U12.3@18.266,101.754 ; U12.3@18.266,101.754 v1(19.641,101.754) v1(19.641,100.629) v1(18.266,100.629) v1(16.541,100.629) C42.2@16.541,101.774 18.246,101.774 U12.3@18.266,101.754
  Top Layer w1: CN11.24@5.786,73.659 CN8.15@10.866,73.659
  Signal Layer 2 w0.4: 1.491,77.379 1.556,77.444 4.501,77.444 4.516,77.429 ; 1.491,80.129 1.636,79.984 3.986,79.984 4.516,79.454 4.516,77.429 ; 1.791,75.404 2.266,74.929 4.161,74.929 ; 4.516,74.929 4.516,77.429
  Signal Layer 2 w0.8: 1.791,75.404 1.491,75.704 1.491,77.379 1.491,80.129 1.491,103.754 2.041,104.304 7.191,104.304 8.451,103.044 11.465,103.044 12.05,102.459 13.337,102.459 13.402,102.524 14.225,102.524 14.495,102.254 15.026,102.254 v1@16.541,100.739
  Signal Layer 2 w1: 4.161,74.929 4.516,74.929 CN11.24@5.786,73.659 CN8.15@10.866,73.659
VOUTVDD: CN6.3 SB97.1 | length 3.2
  Bottom Layer w0.4: v1@22.866,47.654 v1(22.891,47.629) 22.891,48.466 23.675,49.25 SB97.1@23.725,49.25 23.866,49.109 v1(23.866,48.129)
VREFP: C69.1 C70.2 C71.2 R39.2 SB60.2 U14.35 | length 13.7
  Top Layer w0.3: C71.2@42.941,56.929 C69.1@44.016,56.929 ; U14.35@43.366,60.479 v1(43.366,58.879) 43.966,58.279 R39.2@43.966,58.054 43.966,56.979 C69.1@44.016,56.929 ; C70.2@45.316,56.929 C69.1@44.016,56.929
  Bottom Layer w0.3: v1(43.366,58.879) 43.366,61.21 43.811,61.655 43.811,62.738 43.395,63.154 43.395,65.783 SB60.2@43.591,65.979
WAKEUP_KEY: B1.3 B1.4 R67.2 R77.2 U23.1 | length 72.6
  Top Layer w0.12: B1.3@3.017,4.023 B1.4@12.517,4.023 14.56,4.023 U23.1@14.566,4.016 R67.2@14.566,5.029 v1(15.641,5.029)
  Bottom Layer w0.12: v1(15.641,5.029) 16.086,5.474 21.125,5.474 23.026,7.374 23.026,10.639 23.731,11.344 23.731,39.004 26.662,41.935 26.662,42.36 27.936,43.634 27.936,45.166 28.257,45.487 28.257,47.52 28.564,47.827 28.564,53.788 28.98,54.204 R77.2@30.266,54.204
pads on no net: CN1.4 CN5.0 CN5.1 CN5.2 CN5.9 CN8.1 CN11.10 CN11.26 CN11.42 CN11.44 CN11.51 CN11.52 CN11.53 CN11.58 CN11.59 CN11.64 CN11.67 CN12.36 CN12.38 CN12.57 CN12.58 CN12.59 CN12.68 CN12.69 CN13.11 CN13.12 Designator1.1 MIRE-1.1 MIRE-2.1 MIRE-3.1 MIRE-4.1 MIRE-5.1 MIRE-6.1 U1.2 U5.4 U7.A1 U7.A2 U7.A3 U7.A4 U7.A5 U7.A6 U7.A8 U7.A9 U7.A10 U7.A11 U7.A12 U7.A13 U7.B1 U7.B2 U7.B3 U7.B4 U7.B5 U7.B6 U7.B7 U7.B8 U7.B9 U7.B10 U7.B11 U7.B12 U7.B13 U7.B14 U7.B15 U7.C2 U7.C3 U7.C4 U7.C11 U7.C12 U7.C13 U7.C14 U7.C15 U7.D1 U7.D2 U7.D3 U7.D4 U7.D10 U7.D11 U7.D13 U7.D14 U7.E1 U7.E2 U7.E3 U7.E4 U7.E12 U7.E13 U7.E14 U7.E15 U7.F1 U7.F4 U7.F14 U7.G4 U7.G14 U7.G15 U7.H1 U7.H2 U7.H3 U7.H4 U7.H14 U7.H15 U7.J2 U7.J3 U7.J4 U7.K1 U7.K2 U7.K3 U7.K12 U7.K14 U7.K15 U7.L1 U7.L3 U7.L12 U7.L13 U7.L14 U7.L15 U7.M2 U7.M3 U7.M4 U7.M5 U7.M6 U7.M7 U7.M12 U7.M13 U7.M14 U7.M15 U7.N2 U7.N4 U7.N5 U7.N6 U7.N7 U7.N11 U7.N13 U7.N14 U7.N15 U7.P2 U7.P4 U7.P5 U7.P6 U7.P7 U7.P8 U7.P9 U7.P10 U7.P11 U7.P12 U7.P13 U7.P14 U7.P15 U7.R2 U7.R3 U7.R6 U7.R7 U7.R8 U7.R9 U7.R10 U7.R11 U7.R12 U7.R13 U11.3 U14.0 U17.4 U17.5 U17.12 U17.13 U19.5 U24.4

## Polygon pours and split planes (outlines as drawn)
1V2_MCU on Bottom Layer "1V2_MCU_L06_P010" (solid, pour order 10): 32.616,63.379 32.616,61.379 29.866,61.379 29.866,63.379
VDD_SMPS_IND_OUT on Bottom Layer "VDD_SMPS_IND_OUT_L06_P002" (solid, pour order 2): 30.866,60.479 30.866,53.879 33.866,53.879 33.866,60.479
5V_VIN on Bottom Layer "5V_VIN_L06_P036" (solid, remove dead copper, pour order 36): 19.341,104.754 20.291,105.704 20.291,107.479 20.641,107.829 25.616,107.829 25.991,107.454 25.991,100.604 25.641,100.254 20.466,100.254 20.266,100.454 20.266,102.404 19.566,103.104 19.341,103.329
VIN on Bottom Layer "VIN_L06_P084" (solid, remove dead copper, pour order 84): 16.491,102.304 16.141,101.954 16.141,100.604 16.466,100.279 19.816,100.279 20.066,100.529 20.066,102.029 19.791,102.304
SHGND on Bottom Layer "SHGND_L06_P056" (solid, remove dead copper, pour order 56): 35.641,17.325 53.369,17.325 53.369,0 35.741,0 35.641,0.004
VDD on Bottom Layer "VDD_L06_P130" (solid, remove dead copper, pour order 130): 22.175,91.775 21.575,91.175 18.4,91.175 17.925,90.7 17.925,86.575 18.425,86.075 19.8,86.075 20.325,85.55 20.325,84.975 18.85,83.5 16.65,83.5 15.625,82.475 15.625,79.575 16.1,79.1 24.875,79.1 25.425,79.65 25.425,91.525 25.175,91.775
GND on Bottom Layer "GND_L06_P112" (solid, remove dead copper, pour order 112): 13.95,90.825 13.95,78.725 28.025,78.725 28.025,62.345 30.266,60.104 30.266,52.125 36.041,52.125 36.041,0.654 35.591,0.204 1.241,0.204 0.066,1.379 0.066,131.779 1.641,133.354 20.391,133.354 20.441,133.304 20.441,108.104 19.966,107.629 19.966,105.804 19.091,104.929 19.091,103.079 18.691,102.679 16.266,102.679 15.791,102.204 15.791,100.275 16.166,99.9 26.925,99.9 27.425,99.4 27.375,99.35 27.375,98.05 27.479,97.946 27.479,92.653 26.921,92.1 22.025,92.1 21.45,91.525 14.65,91.525
GND on Bottom Layer "GND_L06_P114" (solid, remove dead copper, pour order 114): 20.266,133.254 20.266,108.279 20.441,108.104 25.741,108.104 25.866,107.979 25.866,82.254 25.866,65.679 26.966,64.579 32.583,64.579 34.416,62.746 34.416,53.329 34.141,53.054 29.691,53.054 29.266,52.629 29.266,44.804 29.691,44.379 33.241,44.379 33.791,43.829 33.791,40.354 32.991,39.554 31.191,39.554 30.766,39.129 30.766,37.729 33.316,35.179 33.316,8.779 33.741,8.354 52.091,8.354 52.616,7.829 52.616,0.579 53.141,0.054 68.491,0.054 69.916,1.479 69.916,132.004 68.666,133.254 21.541,133.254
5V on Signal Layer 3 "5V_L04_P070" (solid, remove dead copper, pour order 70): 1.616,113.729 1.616,114.129 2.116,114.629 4.816,114.629 5.316,114.129 5.316,95.454 9.916,90.854 9.916,83.354 10.466,82.804 12.341,82.804 12.556,82.589 12.556,79.819 12.366,79.629 10.491,79.629 9.891,79.029 9.891,76.554 7.741,74.404 7.741,11.254 6.716,10.229 1.216,10.229 0.891,10.554 0.891,80.104 2.141,81.354 4.341,81.354 6.616,83.629 6.616,84.904 5.891,85.629 2.191,85.629 1.616,86.204
VOUTVDD on Signal Layer 3 "VOUTVDD_L04_P030" (solid, remove dead copper, pour order 30): 21.661,49.529 24.201,49.529 24.201,41.909 17.851,41.909 17.851,45.084 21.661,45.084
VCAP on Signal Layer 3 "VCAP_L04_P012" (solid, remove dead copper, pour order 12): 31.366,64.379 31.366,66.129 29.641,66.129 29.641,64.379 21.866,64.379 21.866,80.879 47.866,80.879 47.866,77.629 46.616,77.629 46.616,79.379 23.366,79.379 23.366,67.129 32.859,67.129 32.859,64.379
VDD_LDO on Signal Layer 3 "VDD_LDO_L04_P008" (solid, remove dead copper, pour order 8): 26.189,63.029 26.969,63.81 26.969,63.827 31.272,63.827 31.365,63.919 31.365,66.282 29.791,66.282 29.791,64.379 21.866,64.379 21.866,80.879 47.866,80.879 47.866,79.129 48.616,79.129 48.616,83.629 20.366,83.629 20.366,63.029
3V3_STLK on Signal Layer 3 "3V3_STLK_L04_P044" (solid, remove dead copper, pour order 44): 33.866,132.179 34.691,131.354 34.691,128.554 34.716,128.529 34.716,126.504 44.966,116.254 44.966,110.404 43.766,109.204 15.766,109.204 14.541,110.429 14.541,131.429 15.291,132.179
VIN on Signal Layer 3 "VIN_L04_P040" (solid, remove dead copper, pour order 40): 19.791,100.254 20.041,100.504 20.041,102.004 19.916,102.129 16.416,102.129 16.266,101.979 16.266,100.429 16.441,100.254
5V_VIN on Signal Layer 3 "5V_VIN_L04_P032" (solid, remove dead copper, pour order 32): 19.341,104.754 20.291,105.704 20.291,107.479 20.641,107.829 25.616,107.829 25.991,107.454 25.991,100.604 25.641,100.254 20.466,100.254 20.266,100.454 20.266,102.404 19.566,103.104 19.341,103.329
NetC84_2 on Signal Layer 3 "NETC84_2_L04_P046" (solid, remove dead copper, pour order 46): 31.891,37.104 30.891,36.104 30.891,25.154 32.316,23.729 48.316,23.729 49.116,24.529 49.116,36.604 48.616,37.104
1V2_VOUTCORE on Signal Layer 3 "1V2_VOUTCORE_L04_P018" (solid, remove dead copper, pour order 18): 15.946,50.879 21.749,50.879 21.749,45.084 15.946,45.084
5V_USB_CHGR on Signal Layer 3 "5V_USB_CHGR_L04_P042" (solid, remove dead copper, pour order 42): 58.3,113.488 57.241,112.429 50.141,112.429 35.641,126.929 35.641,129.779 36.741,130.879 62.641,130.879 63.716,129.804 63.716,124.829 63.016,124.129 59.229,124.129 58.3,123.2
GND on Signal Layer 3 "GND_L04_P102" (solid, remove dead copper, pour order 102): 8.75,127.975 8.75,127.575 8.425,127.25 5.5,127.25 0.775,122.525 0.075,122.525 0.1,122.55 0.116,127.975 0.116,131.829 1.466,133.179 8.75,133.179
3V3 on Signal Layer 3 "3V3_L04_P122" (solid, remove dead copper, pour order 122): 52.775,107.575 50.65,107.575 50.175,107.1 50.175,103.525 47.925,101.275 27.45,101.275 26,99.825 19.125,99.825 17.525,98.225 17.525,91.125 19.85,88.8 19.85,86.8 19.129,86.079 16.129,86.079 14.55,84.5 14.55,79.4 8.45,73.3 8.45,32.35 9.65,31.15 13.675,31.15 15.125,29.7 15.125,13.45 21.75,6.825 29.675,6.825 30.375,7.525 30.375,13.375 31.5,14.5 31.5,15 31.225,15.275 23.75,15.275 22,17.025 22,40.775 21.184,41.591 17.084,41.591 16.875,41.8 16.875,41.806 15.925,42.756 15.925,49.45 15.325,50.05 15.325,51.475 16.85,53 16.85,71.05 17.7,71.9 17.7,81.65 18.325,82.275 19.525,82.275 20,82.75 20,83.725 20.225,83.95 21.05,83.95 21.575,84.475 21.575,96.05 22.05,96.525 28.125,96.525 30.1,98.5 35.4,98.5 36.4,97.5 36.4,96.725 36.925,96.2 52.8,96.2 53.35,96.75 53.35,107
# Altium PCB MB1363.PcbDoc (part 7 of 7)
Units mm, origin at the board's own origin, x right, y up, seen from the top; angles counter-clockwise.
Board outline 70 x 133.34 mm, 6 copper layers (Top Layer, Signal Layer 1, Signal Layer 2, Signal Layer 3, Signal Layer 4, Bottom Layer), stack 1.57 mm thick; 355 components, 293 nets, 1446 pads, 1145 vias.

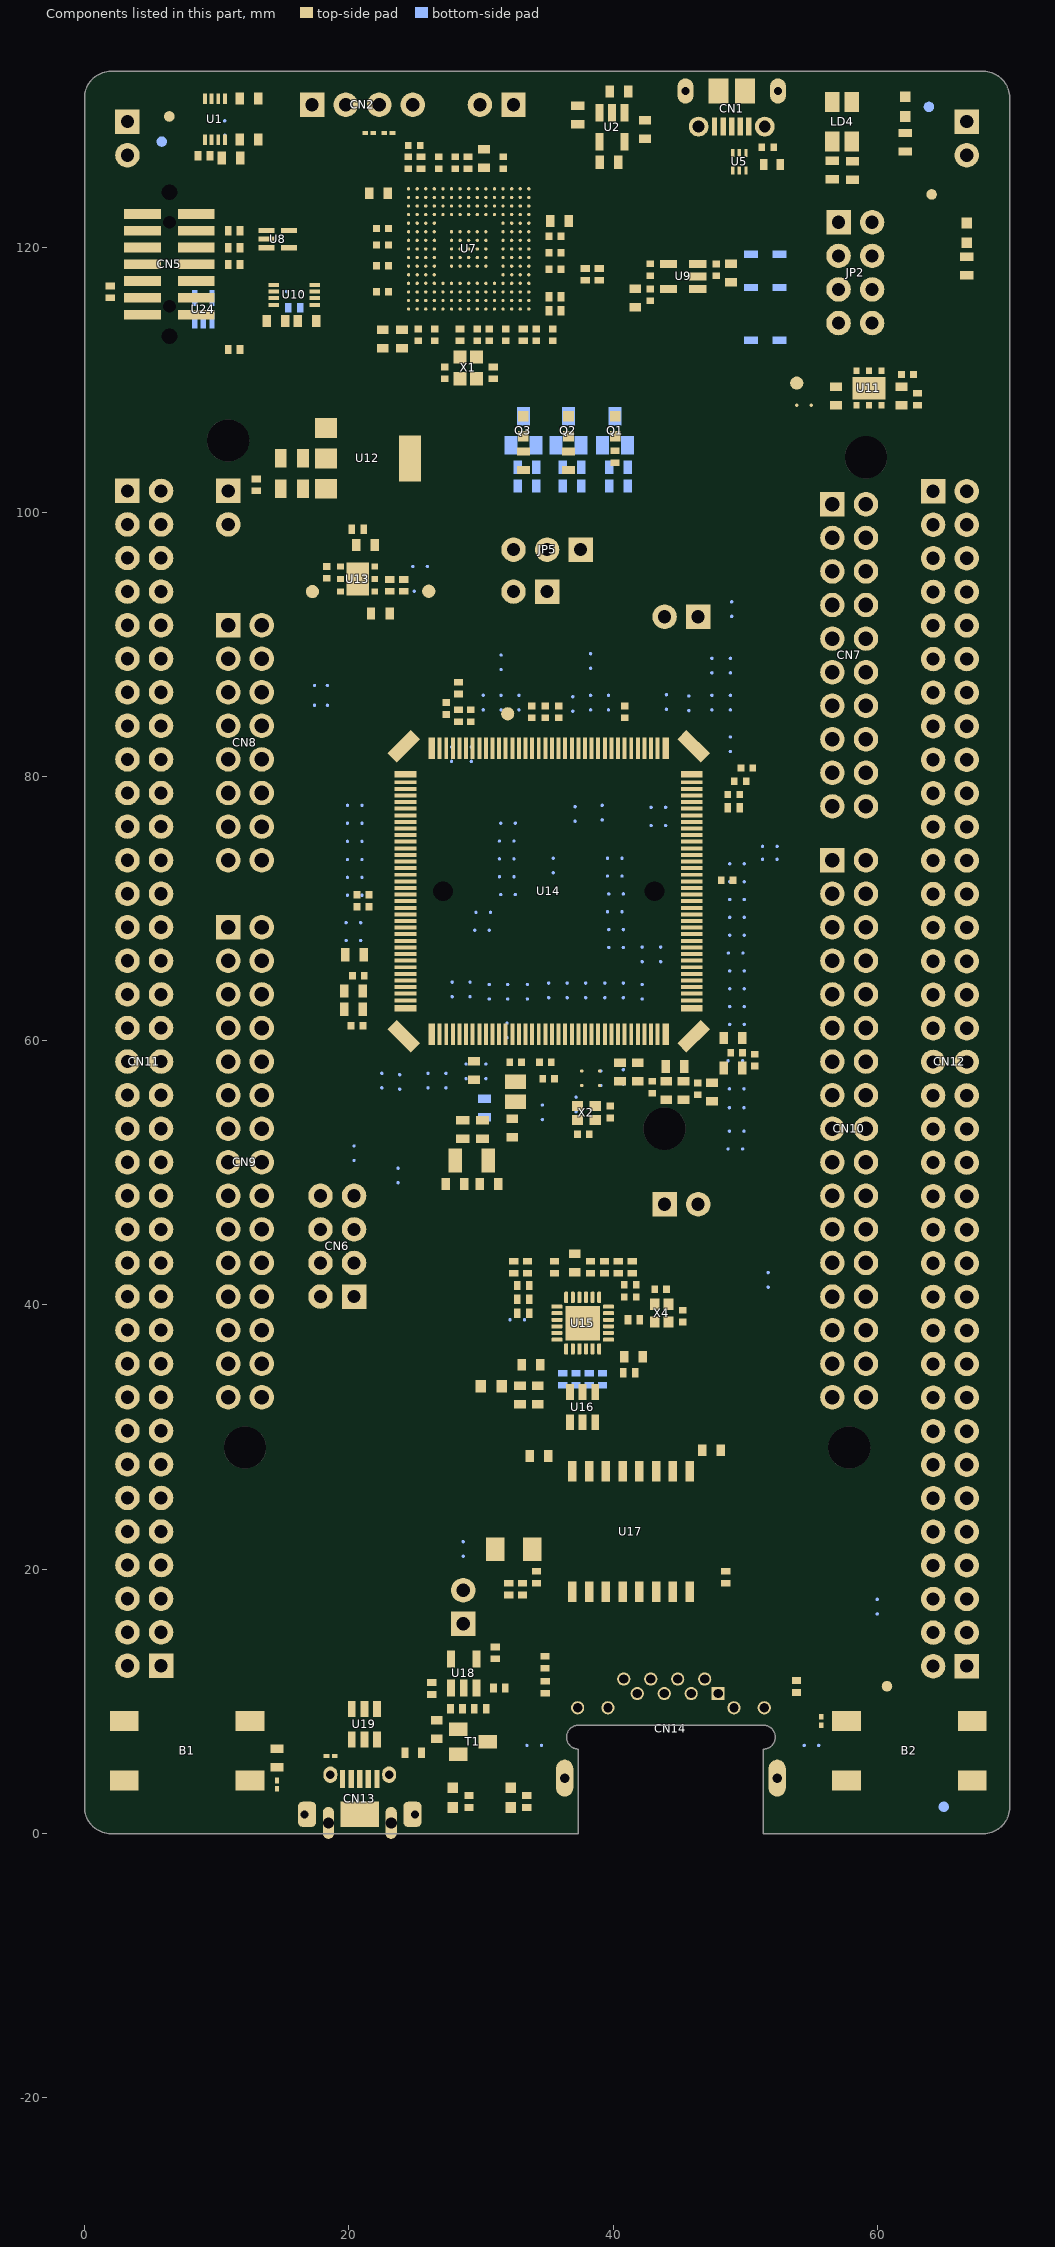
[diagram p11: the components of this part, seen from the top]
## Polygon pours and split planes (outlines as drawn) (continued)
GND on Signal Layer 3 "GND_L04_P106" (solid, remove dead copper, pour order 106): 52.238,49.287 46.112,49.287 44.65,47.825 44.65,43.513 43.312,42.175 42.375,42.175 41.65,41.45 32.8,41.45 31.625,40.275 31.625,38.275 32.575,37.325 49.125,37.325 49.866,36.584 49.866,36.194 49.866,2.904 52.666,0.104 68.416,0.104 69.966,1.654 69.966,131.879 68.691,133.154 34.191,133.154 34.091,133.054 34.091,132.504 35.391,131.204 62.816,131.204 64.091,129.929 64.091,124.654 63.191,123.754 61.616,123.754 60.8,122.938 60.8,113.6 59.204,112.004 49.866,112.004 47.666,114.204 45.866,114.204 45.441,113.779 45.441,110.329 43.916,108.804 26.625,108.804 26.625,101.7 47.625,101.7 49.75,103.825 49.75,108 52.95,108 53.65,107.3 53.65,101.64 53.641,101.631 53.641,96.579 53.641,50.691
NetC90_2 on Signal Layer 3 "NETC90_2_L04_P048" (solid, remove dead copper, pour order 48): 33.941,23.129 33.091,22.279 33.091,17.779 35.116,15.754 48.341,15.754 49.241,16.654 49.241,22.479 48.591,23.129
GND on Signal Layer 3 "GND_L04_P000" (solid, remove dead copper, pour order 0): 31.8,7.725 30.175,6.1 20.95,6.1 13.921,13.129 13.921,26.275 8,26.275 8,10.294 7.61,9.904 0.191,9.904 0.091,9.804 0.091,1.629 1.691,0.029 35.475,0.029 35.475,7.725
5V_EXT on Signal Layer 3 "5V_EXT_L04_P124" (solid, remove dead copper, pour order 124): 6.075,95.1 8.15,95.1 10.25,97.2 10.25,109 9.4,109.85 6.725,109.85 6.075,109.2
VDD on Signal Layer 3 "VDD_L04_P126" (solid, remove dead copper, pour order 126): 9.8,132.3 9.125,131.625 9.125,127.225 8.675,126.775 5.75,126.775 1.55,122.575 1.55,116.7 2.95,115.3 4.975,115.3 6.05,114.225 6.05,111 6.65,110.4 9.9,110.4 11.025,109.275 11.025,85.225 11.675,84.575 13.95,84.575 15.825,86.45 18.775,86.45 19.175,86.85 19.175,88.65 17.025,90.8 17.025,98.95 15.855,100.12 15.855,102.38 16.25,102.775 18.125,102.775 18.675,103.325 18.675,108.075 18.05,108.7 15.55,108.7 14.1,110.15 14.1,131.7 13.5,132.3
1V2_MCU on Signal Layer 3 "1V2_MCU_L04_P006" (solid, remove dead copper, pour order 6): 26.531,62.879 27.131,63.479 31.166,63.479 31.766,62.879 32.616,62.879 32.616,61.879 21.366,61.879 21.366,51.879 19.616,51.879 19.616,62.879
VDD_MCU on Signal Layer 3 "VDD_MCU_L04_P016" (solid, remove dead copper, pour order 16): 25.266,50.129 25.291,50.104 52.104,50.104 52.743,50.744 52.743,94.107 50.85,96 21.866,96 21.866,50.129
VDD on Signal Layer 3 "VDD_L04_P128" (solid, remove dead copper, pour order 128): 18.475,82.05 17.95,81.525 17.95,51.875 18.7,51.125 21.95,51.125 23.175,49.9 24.22,49.9 24.475,49.645 24.475,47.575 23.725,46.825 23.725,42.025 22.55,40.85 22.55,17.55 24.25,15.85 31.325,15.85 31.9,15.275 31.9,14.159 30.75,13.009 30.75,8.775 31.425,8.1 34.125,8.1 34.875,8.85 34.875,15.57 32.7,17.745 32.7,22.775 30.45,25.025 30.45,36.25 31.225,37.025 31.225,40.6 32.45,41.825 41.325,41.825 42,42.5 42.825,42.5 43.9,43.575 43.9,48.275 42.525,49.65 26.207,49.65 23.807,52.05 19.95,52.05 19.3,52.7 19.3,61.5 19.9,62.1 19.9,63.825 20.825,64.75 20.825,70.541 20.2,71.166 20.2,81.65 19.8,82.05
GND on Top Layer "GND_L01_P024" (solid, remove dead copper, pour order 24): 15.541,100.504 15.316,100.279 13.891,100.279 13.666,100.504 13.666,107.429 14.041,107.804 19.966,107.804 19.966,105.604 19.741,105.379 15.816,105.379 15.541,105.104
5V on Top Layer "5V_L01_P064" (solid, remove dead copper, pour order 64): 25.616,14.429 25.466,14.279 25.466,12.929 25.691,12.704 27.941,12.704 28.166,12.929 28.166,13.629 27.941,13.854 27.291,13.854 26.716,14.429
VIN on Top Layer "VIN_L01_P026" (solid, remove dead copper, pour order 26): 16.041,102.829 15.816,102.604 15.816,100.504 16.041,100.279 19.816,100.279 20.016,100.479 20.016,102.604 19.791,102.829
5V_VIN on Top Layer "5V_VIN_L01_P028" (solid, remove dead copper, pour order 28): 16.091,105.154 15.816,104.879 15.816,103.354 16.091,103.079 19.966,103.079 20.291,102.754 20.291,100.479 20.491,100.279 25.641,100.279 25.966,100.604 25.966,107.429 25.591,107.804 20.641,107.804 20.291,107.454 20.291,105.454 19.991,105.154
GND on Top Layer "GND_L01_P022" (solid, remove dead copper, pour order 22): 43.791,133.304 43.791,126.679 42.666,125.554 32.616,125.554 31.991,124.929 31.991,123.179 32.866,122.304 50.741,122.304 54.366,125.929 54.366,133.304
5V on Top Layer "5V_L01_P038" (solid, remove dead copper, pour order 38): 59.189,124.529 58.525,123.865 58.525,113.518 59.339,112.704 62.941,112.704 63.716,111.929 63.716,108.629 63.566,108.479 60.166,108.479 59.991,108.304 59.991,107.554 60.291,107.254 67.116,107.254 67.666,107.804 67.666,118.154 67.366,118.454 64.866,118.454 64.116,119.204 64.116,123.929 63.516,124.529
USB_FS_VBUS on Top Layer "USB_FS_VBUS_L01_P068" (solid, remove dead copper, pour order 68): 27.991,12.079 28.266,11.804 28.266,9.154 26.916,7.804 26.116,7.804 24.941,6.629 24.941,4.554 23.666,3.279 21.966,3.279 21.841,3.404 21.841,5.254 25.666,9.079 25.666,10.779 25.816,10.929 26.816,10.929 27.016,11.129 27.016,11.904 27.191,12.079
GND on Top Layer "GND_L01_P090" (solid, remove dead copper, pour order 90): 1.577,133.34 0.116,131.879 0.116,107.629 20.166,107.629 20.666,108.129 25.866,108.129 26.4,107.595 26.4,100.163 25.991,99.754 16.291,99.754 15.416,100.629 13.866,100.629 13.866,107.629 0.116,107.629 0.116,1.629 1.616,0.129 35.366,0.129 35.366,12.379 28.991,12.379 28.616,12.004 28.616,8.979 27.016,7.379 26.266,7.379 25.366,6.479 25.366,4.379 23.866,2.879 21.866,2.879 21.366,3.379 21.366,5.379 25.116,9.129 25.116,14.629 25.366,14.879 35.866,14.879 35.866,8.379 53.366,8.379 53.369,0 68.237,0 69.866,1.629 69.866,106.879 60.116,106.879 59.616,107.379 59.616,108.629 59.866,108.879 63.116,108.879 63.116,111.879 62.616,112.379 59.016,112.379 58.15,113.245 58.15,124.05 58.979,124.879 63.616,124.879 64.366,124.129 64.366,119.379 64.866,118.879 67.396,118.879 67.396,118.849 67.866,118.379 67.866,107.629 67.616,107.379 67.616,107.129 69.866,107.129 69.866,131.879 68.405,133.34
GND on Signal Layer 2 "GND_L03_P092" (solid, remove dead copper, pour order 92): 2,133.34 1.986,133.354 1.55,133.354 -0.009,131.795 -0.009,117.504 0.166,117.329 0.916,117.329 4.391,120.804 23.941,120.804 26.391,118.354 35.841,118.354 41.566,124.079 48.041,124.079 50.816,126.854 62.041,126.854 64.016,124.879 64.016,114.004 62.841,112.829 62.841,112.079 69.816,112.079 69.816,132.004 68.491,133.329
5V_VIN on Signal Layer 2 "5V_VIN_L03_P034" (solid, remove dead copper, pour order 34): 19.366,104.779 20.316,105.729 20.316,107.504 20.666,107.854 25.641,107.854 26.016,107.479 26.016,100.629 25.666,100.279 20.491,100.279 20.291,100.479 20.291,102.429 19.591,103.129 19.366,103.354
5V on Signal Layer 2 "5V_L03_P062" (solid, remove dead copper, pour order 62): 15.866,14.304 13.316,11.754 1.441,11.754 1.091,11.404 1.091,9.979 1.716,9.354 14.791,9.354 17.816,12.379 27.091,12.379 27.366,12.654 27.366,14.079 27.141,14.304
VIN on Signal Layer 2 "VIN_L03_P082" (solid, remove dead copper, pour order 82): 12.441,104.079 12.016,104.079 11.191,103.254 11.191,101.679 12.566,100.304 19.716,100.304 19.991,100.579 19.991,102.279 19.366,102.904 18.196,104.074 17.341,104.074
5V on Signal Layer 2 "5V_L03_P060" (solid, remove dead copper, pour order 60): 58.575,113.8 59.496,112.879 62.391,112.879 63.616,114.104 63.616,124.429 61.641,126.404 50.866,126.404 48.191,123.729 41.841,123.729 36.066,117.954 26.266,117.954 23.766,120.454 4.541,120.454 1.091,117.004 1.091,113.079 1.691,112.479 3.941,112.479 5.466,114.004 38.241,114.004 44.791,120.554 57.771,120.554 58.63,119.695
GND on Signal Layer 2 "GND_L03_P094" (solid, remove dead copper, pour order 94): 0.091,113.329 0.391,113.329 1.491,112.229 4.166,112.229 5.641,113.704 38.666,113.704 45.116,120.154 57.671,120.154 58.225,119.6 58.225,113.675 59.346,112.554 62.566,112.554 62.841,112.829 69.592,112.829 69.866,112.555 69.866,81.879 43.116,81.879 42.366,82.629 42.366,83.559 42.366,85.429 41.766,86.029 31.966,86.029 26.366,91.629 26.366,107.654 25.716,108.304 20.491,108.304 19.891,107.704 19.891,105.829 18.466,104.404 11.741,104.404 10.716,103.379 10.716,100.529 10.566,100.379 0.341,100.379 0.091,100.629
GND on Signal Layer 2 "GND_L03_P096" (solid, remove dead copper, pour order 96): 26.666,100.854 25.916,100.104 12.241,100.104 10.4,101.945 10.4,103.669 8.751,103.669 7.491,104.929 0.216,104.929 0.116,104.829 0.116,11.404 0.253,11.266 0.579,11.266 1.316,12.004 13.166,12.004 15.691,14.529 27.316,14.529 27.616,14.229 27.616,12.179 69.916,12.179 69.941,12.204 69.941,81.577 64.268,87.25 30.745,87.25 26.666,91.329
GND on Signal Layer 2 "GND_L03_P098" (solid, remove dead copper, pour order 98): 0.566,10.029 1.616,8.979 15.041,8.979 18.116,12.054 27.141,12.054 27.666,12.579 34.091,12.579 34.416,12.904 34.416,13.054 35.291,13.929 69.891,13.929 69.941,13.879 69.941,1.204 68.816,0.079 1.216,0.079 0.216,1.079 0.216,10.004 0.191,10.029
GND on Signal Layer 1 "GND_L02_P020" (solid, remove dead copper, pour order 20): 35.266,9.866 36.068,10.668 52.748,10.668 53.666,9.75 53.666,8.429 53.491,8.254 53.491,0 69.037,0 69.416,0.379 70,0.963 70,132.345 69.005,133.34 68,133.34 -0.034,133.379 -0.034,0.929 0.895,0 35.266,0
GND on Signal Layer 4 "GND_L05_P050" (solid, remove dead copper, pour order 50): 35.369,10.569 36.425,11.625 52.4,11.625 53.425,10.6 53.364,10.263 53.501,10.126 53.5,10 53.525,9.975 53.541,9.975 53.541,0.054 53.591,0.079 68.541,0.079 69.866,1.404 69.866,131.829 68.466,133.229 1.791,133.254 1.516,133.254 0.041,131.779 0.041,1.629 1.591,0.079 35.369,0.079

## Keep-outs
Keep-Out Layer:
  lines w0.127: -0.004,1.999 ccw(c1.996,1.999) 1.996,-0.001

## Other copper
Top Layer:
  pour cut-out: 33.041,51.529 31.941,51.529 30.991,52.479 30.991,53.904 30.191,54.704 30.191,55.529 30.941,56.279 30.941,57.979 31.541,58.579 31.541,61.329 31.691,61.479 35.066,61.479 35.191,61.354 35.191,59.329 35.716,58.804 36.216,58.804 36.991,58.029 36.991,56.879 36.316,56.204 36.316,55.604 33.916,53.204 33.916,52.278 33.166,51.528
  pour cut-out: 24.316,126.629 23.271,126.629 21.721,125.079 21.721,122.206 21.536,122.021 21.536,113.804 22.001,113.339 26.226,113.339 26.891,114.004 26.891,115.779 27.446,116.334 28.79,116.334 29.716,115.408 29.716,113.904 30.416,113.204 35.791,113.204 36.291,113.704 36.291,121.204 36.116,121.379 31.791,121.379 31.791,122.379 32.49,123.078 32.49,126.627
  pour cut-out: 48.616,126.679 48.616,126.254 49.966,126.254 49.966,126.734 48.621,126.734 48.616,126.729
  pour cut-out: 35.366,17.35 53.366,17.35 53.366,-0.121 35.366,-0.121
  pour cut-out: 29.6,22.95 36.366,22.95 36.366,0 29.6,0
  text "1" at 67.218,104.184 h2 r90
Signal Layer 1:
  pour cut-out: 33.041,51.529 31.941,51.529 30.991,52.479 30.991,53.904 30.191,54.704 30.191,55.529 30.941,56.279 30.941,57.979 31.541,58.579 31.541,61.329 31.691,61.479 35.066,61.479 35.191,61.354 35.191,59.329 35.716,58.804 36.216,58.804 36.991,58.029 36.991,56.879 36.316,56.204 36.316,55.604 33.916,53.204 33.916,52.278 33.166,51.528
  pour cut-out: 35.366,17.35 53.366,17.35 53.366,-0.121 35.366,-0.121
  pour cut-out: 29.6,22.95 36.366,22.95 36.366,0 29.6,0
  text "2" at 67.218,105.434 h2 r90
Signal Layer 2:
  pour cut-out: 33.041,51.529 31.941,51.529 30.991,52.479 30.991,53.904 30.191,54.704 30.191,55.529 30.941,56.279 30.941,57.979 31.541,58.579 31.541,61.329 31.691,61.479 35.066,61.479 35.191,61.354 35.191,59.329 35.716,58.804 36.216,58.804 36.991,58.029 36.991,56.879 36.316,56.204 36.316,55.604 33.916,53.204 33.916,52.278 33.166,51.528
  pour cut-out: 35.366,17.35 53.366,17.35 53.366,-0.121 35.366,-0.121
  pour cut-out: 30.125,23.025 36.366,23.025 36.366,0 30.125,0
  text "3" at 67.218,106.934 h2 r90
Signal Layer 3:
  pour cut-out: 35.325,17.421 53.325,17.421 53.325,-0.05 35.325,-0.05
  text "4" at 67.218,109.184 h2 r90
Signal Layer 4:
  pour cut-out: 37.266,61.429 37.216,61.379 37.141,61.304 37.141,58.929 36.966,58.754 36.966,55.804 36.191,55.029 36.191,52.079 36.641,51.629 38.866,51.629 40.741,53.504 40.741,55.404 40.091,56.054 39.591,56.554 39.591,58.554 39.216,58.929 39.216,61.329 39.116,61.429
  pour cut-out: 30.741,61.429 30.666,61.354 30.666,58.729 30.391,58.454 30.391,57.929 30.066,57.604 29.066,57.604 28.841,57.379 28.841,56.604 27.666,55.429 27.666,52.729 26.866,51.929 26.866,48.504 27.541,47.829 30.966,47.829 31.791,48.654 31.791,51.154 30.841,52.104 30.841,54.204 30.641,54.404 30.291,54.404 30.216,54.479 30.216,55.554 31.016,56.354 31.016,58.129 31.591,58.704 31.591,61.354 31.516,61.429
  pour cut-out: 35.366,17.35 53.366,17.35 53.366,-0.121 35.366,-0.121
  pour cut-out: 32.3,8.2 36.366,8.2 36.366,0 32.3,0
  pour cut-out: 52.225,8.2 56.291,8.2 56.291,0 52.225,0
  text "5" at 67.218,110.684 h2 r90
Bottom Layer:
  pour cut-out: 32.541,19.7 35.475,19.7 35.475,0 32.541,0
  pour cut-out: 32.575,17.366 32.575,20.3 56.325,20.3 56.325,17.366
  pour cut-out: 56.459,0 53.525,0 53.525,20.225 56.459,20.225
  text "6" at 67.218,112.184 h2 r90
Multi-Layer:
  pour cut-out: 65.621,103.891 67.621,103.891 67.621,112.391 65.621,112.391
  pour cut-out: 36.441,28.325 36.441,17.359 46.266,17.359 46.266,28.325

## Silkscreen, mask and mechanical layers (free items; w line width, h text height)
Top Overlay:
  drawing of 358 lines, arcs and shapes, not listed
  text "OVCR" at 60.186,132.098 h1.5
  text "COM" at 55.903,132.049 h1.5
  text "SWD" at 27.254,129.311 h1.5 r90
  text "STLK_RST" at 29.705,128.396 h0.91
  text "3V3" at 15.966,128.329 h1.5
  text "USB" at 45.027,127.236 h1.5
  text "STLK" at 15.394,127.064 h1.5
  text "GND" at 1.547,126.954 h1.5 r90
  text "GND" at 69.474,126.947 h1.5 r90
  text "PWR" at 44.861,126.086 h1.5
  text "ST-LINK V3" at 34.721,123.685 h1.5
  text "STLINK" at 50.42,121.407 h1.5
  text "VIN" at 52.85,118.795 h1.5
  text "5V" at 62.324,118.566 h1.5
  text "PWR" at 61.689,117.042 h1.5
  text "EXT" at 52.552,116.332 h1.5
  text "RX" at 0.706,114.299 h1.5
  text "TX" at 10.391,114.299 h1.5
  text "CHGR" at 51.18,113.769 h1.5
  text "MIPI10" at 4.326,111.224 h1.5
  text "3V3" at 52.749,110.764 h1.5
  text "5V_VIN" at 25.824,103.769 h1.5
  text "SCL" at 60.916,101.154 h1.2 r45
  text "User LEDs" at 34.039,101.13 h1.5
  text "D15" at 60.991,100.029 h1.2 r45
  text "VIN" at 17.315,99.842 h1.5
  text "E" at 44.1,99.525 h14
  text "1V8-VDD-3V3" at 30.881,98.754 h1.5
  text "SDA" at 60.916,98.379 h1.2 r45
  text "D14" at 60.991,97.229 h1.2 r45
  text "MCU_RST" at 7.776,96.466 h1.5
  text "+" at 62.291,95.379 h1.2 r45
  text "VREF" at 60.966,95.204 h1.2 r45
  text "I2S_A" at 54.017,94.409 h1.5 r90
  text "IDD" at 37.2,93.425 h1.5
  text "GND" at 60.891,92.779 h1.2 r45
  text "NC" at 7.741,92.154 h1.2 r315
  text "1V8" at 24.965,92.119 h1.5
  text "VDD_MCU" at 30.925,91.425 h1.5
  text "SCK" at 60.916,90.904 h1.2 r45
  text "D13" at 61.016,89.779 h1.2 r45
  text "IO" at 8.216,89.754 h1.2 r315
  text "RMII TXD1" at 41.862,89.533 h1.5
  text "REF" at 7.491,89.004 h1.2 r315
  text "MISO" at 60.966,88.079 h1.2 r45
  text "NRST" at 7.116,86.904 h1.2 r315
  text "D12" at 61.016,86.879 h1.2 r45
  text "I2S_B" at 54.719,85.921 h1.5 r90
  text "MOSI" at 60.991,85.329 h1.2 r45
  text "D11" at 60.966,84.079 h1.2 r45
  text "3V3" at 7.716,83.904 h1.2 r315
  text "SDMMC" at 16.676,82.753 h1.5 r90
  text "CS" at 60.891,82.629 h1.2 r45
  text "D10" at 60.966,81.479 h1.2 r45
  text "5V" at 7.841,81.354 h1.2 r315
  text "PWM" at 60.991,80.104 h1.2 r45
  text "GND" at 7.441,79.054 h1.2 r315
  text "D9" at 61.016,78.904 h1.2 r45
  text "SPI_B" at 54.151,78.837 h1.5 r90
  text "I/O" at 61.016,77.429 h1.2 r45
  text "GND" at 7.416,76.479 h1.2 r315
  text "D8" at 61.016,76.229 h1.2 r45
  text "IO" at 16.64,74.292 h1.5 r90
  text "I/O" at 61.041,74.204 h1.2 r45
  text "VIN" at 7.466,73.879 h1.2 r315
  text "AVDD" at 51.445,73.179 h1.5
  text "D7" at 61.041,72.954 h1.2 r45
  text "PWM" at 61.016,71.554 h1.2 r45
  text "AGND" at 51.342,70.602 h1.5
  text "D6" at 61.041,70.404 h1.2 r45
  text "A0" at 7.758,69.168 h1.2 r315
  text "PWM" at 61.041,69.029 h1.2 r45
  text "GND" at 52.309,68.223 h1.5
  text "D5" at 61.041,67.854 h1.2 r45
  text "A1" at 7.841,66.679 h1.2 r315
  text "I/O" at 61.016,66.429 h1.2 r45
  text "D4" at 61.041,65.204 h1.2 r45
  text "A2" at 7.866,64.129 h1.2 r315
  text "PWM" at 61.016,63.729 h1.2 r45
  text "D3" at 61.016,62.504 h1.2 r45
  text "A3" at 7.766,61.479 h1.2 r315
  text "USART" at 16.249,61.35 h1.5 r90
  text "I/O" at 61.016,61.129 h1.2 r45
  text "D2" at 61.041,59.954 h1.2 r45
  text "ADC_IN" at 54.018,59.134 h1.5 r90
  text "A4" at 7.816,59.004 h1.2 r315
  text "TX" at 60.992,58.483 h1.2 r45
  text "D1" at 60.991,57.254 h1.2 r45
  text "A5" at 7.766,56.429 h1.2 r315
  text "RX" at 61.016,55.729 h1.2 r45
  text "GND" at 14.885,55.395 h1.5
  text "D0" at 61.041,54.554 h1.2 r45
  text "COMP" at 8.392,50.222 h1.5 r90
  text "QSPI" at 53.866,49.124 h1.5 r90
  text "SAI_A" at 16.036,47.769 h1.5 r90
  text "PG" at 22.068,47.578 h1.5
  text "GND" at 24.847,47.553 h1.5
  text "VOUT" at 24.536,45.919 h1.5
  text "SW" at 21.903,45.271 h1.5
  text "RMII MDIO" at 42.543,45.101 h1.5
  text "I2C" at 8.534,44.676 h1.5 r90
  text "CORE" at 24.536,44.649 h1.5
  text "EN" at 21.996,42.744 h1.5
  text "VDD" at 24.872,42.73 h1.5
  text "TIMER" at 62.301,41.166 h1.5 r90
  text "GND" at 7.366,41.129 h1.2 r315
  text "V1" at 21.996,40.204 h1.5
  text "GND" at 52.309,40.207 h1.5
  text "3V3" at 25.093,40.186 h1.5
  text "SAI_B" at 16,37.601 h1.5 r90
  text "CAN" at 8.356,35.361 h1.5 r90
  text "TIMER" at 54.094,33.405 h1.5 r90
  text "IO" at 14.929,32.577 h1.5
  text "IO" at 8.202,32.51 h1.5
  text "USB PWR EN" at 28.325,20.05 h1.5 r90
  text "J" at 50.425,19.15 h18
  text "MB1363D" at 51.85,18.252 h2
  text "Nucleo" at 8.344,16.62 h3.3
  text "GND" at 64.243,10.076 h1.5
  text "GND" at 3.214,9.991 h1.5
  text "RESET" at 60.307,1.922 h1.5
  text "USER" at 6,1.9 h1.5
  text "User" at 13.205,1.729 h1.5
  text "USB" at 13.229,0.491 h1.5
  text "OVCR" at 26.258,0.329 h1.5
  text "VBUS" at 31.537,0.337 h1.5
Bottom Overlay:
  lines w0.12: 32.077,58.881 32.077,59.33
  lines w0.127: 30.875,16.45 30.875,25.45 55.875,25.45 55.875,16.45 30.875,16.45
  text "GND" at 68.326,127 h1.5 r270
  text "GND" at 0.741,126.829 h1.5 r270
  text "CN12" at 65.375,103.25 h1.5
  text "CN11" at 6.265,103.098 h1.5
  text "E" at 26.15,102.275 h14
  text "CN7" at 57.199,102.184 h1.5
  text "PC8" at 69.591,102.183 h1.2 r45
  text "PC11" at 9.533,101.167 h1.2
  text "PC10" at 1.766,100.979 h1.2 r315
  text "PC9" at 62.961,100.938 h1.2
  text "PC6" at 69.743,99.872 h1.2 r45
  text "PC12" at 1.791,98.579 h1.2 r315
  text "PD2" at 9.088,98.525 h1.2
  text "PB8" at 62.961,98.398 h1.2
  text "PC5" at 69.769,97.23 h1.2 r45
  text "3V3" at 1.866,96.504 h1.2 r315
  text "E5V" at 9.088,95.935 h1.2
  text "PB9" at 62.961,95.858 h1.2
  text "VDD" at 1.671,95.381 h1.2 r315
  text "U5V" at 69.667,94.563 h1.2 r45
  text "GND" at 9.088,93.445 h1.2
  text "BT0" at 1.595,93.318 h1.2 r315
  text "CN8" at 13.547,92.934 h1.5
  text "VREF+" at 62.69,92.664 h1.2 r315
  text "PD8" at 69.667,92.099 h1.2 r45
  text "NC" at 8.391,91.054 h1.2
  text "PF6" at 1.671,90.778 h1.2 r315
  text "GND" at 62.961,90.778 h1.2
  text "PA12" at 69.769,89.153 h1.2 r45
  text "+3V3" at 9.748,88.365 h1.2
  text "PA5" at 62.961,88.238 h1.2
  text "PF7" at 1.671,88.137 h1.2 r315
  text "PA11" at 69.489,86.41 h1.2 r45
  text "PA6" at 62.961,85.698 h1.2
  text "NRST" at 9.698,85.648 h1.2
  text "PA13" at 2.078,84.911 h1.2 r315
  text "PB12" at 69.591,83.895 h1.2 r45
  text "3V3" at 9.088,83.285 h1.2
  text "PA7" at 62.961,83.158 h1.2
  text "PA14" at 2.078,82.346 h1.2 r315
  text "PB11" at 69.642,81.38 h1.2 r45
  text "+5V" at 9.088,80.695 h1.2
  text "PB6" at 62.961,80.618 h1.2
  text "PA15" at 2.078,79.856 h1.2 r315
  text "GND" at 69.769,79.323 h1.2 r45
  text "GND" at 9.088,78.231 h1.2
  text "PC7" at 62.961,78.078 h1.2
  text "GND" at 1.671,78.053 h1.2 r315
  text "PB2" at 69.642,76.783 h1.2 r45
  text "GND" at 9.088,75.691 h1.2
  text "PA9" at 62.961,75.538 h1.2
  text "PB7" at 1.671,75.513 h1.2 r315
  text "CN10" at 59.578,75.041 h1.5
  text "PB1" at 69.489,74.065 h1.2 r45
  text "VIN" at 8.936,73.024 h1.2
  text "PA8" at 62.961,72.998 h1.2
  text "PC13" at 2.078,72.313 h1.2 r315
  text "PB15" at 69.591,71.373 h1.2 r45
  text "NC" at 8.466,70.704 h1.2
  text "PB10" at 62.961,70.458 h1.2
  text "CN9" at 13.647,69.951 h1.5
  text "PC14" at 2.078,69.696 h1.2 r315
  text "PB14" at 69.642,68.757 h1.2 r45
  text "PA0" at 9.088,68.096 h1.2
  text "PB4" at 62.961,67.918 h1.2
  text "PC15" at 1.9,67.36 h1.2 r315
  text "PB13" at 69.794,66.344 h1.2 r45
  text "PA1" at 8.783,65.505 h1.2
  text "PB5" at 62.961,65.378 h1.2
  text "OSCI" at 2.078,64.642 h1.2 r315
  text "AGND" at 69.86,64.007 h1.2 r45
  text "PA4" at 9.088,63.067 h1.2
  text "PB3" at 62.961,62.838 h1.2
  text "OSCO" at 2.078,62.102 h1.2 r315
  text "PC4" at 69.616,61.695 h1.2 r45
  text "PB0" at 9.088,60.425 h1.2
  text "PA10" at 62.961,60.298 h1.2
  text "VBAT" at 2.078,59.536 h1.2 r315
  text "NC" at 69.391,57.979 h1.2
  text "PC1" at 8.783,57.809 h1.2
  text "PA2" at 62.961,57.758 h1.2
  text "PC2" at 1.671,57.454 h1.2 r315
  text "NC" at 69.391,55.504 h1.2
  text "PC0" at 9.088,55.32 h1.2
  text "PA3" at 62.961,55.218 h1.2
  text "PC3" at 1.671,54.863 h1.2 r315
  text "PE8" at 69.616,53.847 h1.2 r45
  text "PD3" at 9.088,52.755 h1.2
  text "GND" at 62.961,52.678 h1.2
  text "PD4" at 1.595,52.628 h1.2 r315
  text "PF10" at 69.87,51.332 h1.2 r45
  text "NC" at 8.491,50.379 h1.2
  text "PD13" at 62.961,50.138 h1.2
  text "PD5" at 1.57,50.113 h1.2 r315
  text "PE7" at 69.667,48.716 h1.2 r45
  text "NC" at 8.516,47.904 h1.2
  text "PD6" at 1.57,47.598 h1.2 r315
  text "PD12" at 62.961,47.598 h1.2
  text "PD14" at 69.819,46.176 h1.2 r45
  text "PE2" at 9.088,45.16 h1.2
  text "PD7" at 1.519,45.135 h1.2 r315
  text "PD11" at 62.961,45.058 h1.2
  text "PD15" at 69.667,43.509 h1.2 r45
  text "PE4" at 9.088,42.747 h1.2
  text "PE3" at 1.544,42.544 h1.2 r315
  text "PE10" at 62.961,42.518 h1.2
  text "PF14" at 69.718,40.994 h1.2 r45
  text "GND" at 1.595,40.105 h1.2 r315
  text "PE12" at 62.961,39.978 h1.2
  text "PE5" at 9.088,39.928 h1.2
  text "PE9" at 69.667,38.556 h1.2 r45
  text "NC" at 1.966,37.729 h1.2
  text "NC" at 8.566,37.679 h1.2
  text "PE14" at 62.961,37.438 h1.2
  text "GND" at 69.667,36.041 h1.2 r45
  text "NC" at 2.016,35.179 h1.2
  text "PF8" at 9.088,35 h1.2
  text "PE15" at 62.961,34.898 h1.2
  text "PE11" at 69.794,33.578 h1.2 r45
  text "PF9" at 9.088,32.46 h1.2
  text "PD1" at 1.671,32.384 h1.2 r315
  text "PE13" at 62.961,32.358 h1.2
  text "NC" at 8.591,30.129 h1.2
  text "NC" at 62.941,30.054 h1.2
  text "NC" at 69.441,30.054 h1.2
  text "PD0" at 1.671,29.793 h1.2 r315
  text "J" at 30.925,29.625 h18
  text "PF15" at 69.819,28.32 h1.2 r45
  text "MB1363D" at 30.2,28.175 h2.5
  text "NC" at 1.916,27.554 h1.2
  text "GND" at 9.191,27.504 h1.2
  text "NC" at 62.991,27.479 h1.2
  text "PF11" at 69.642,25.704 h1.2 r45
  text "PE6" at 9.088,24.815 h1.2
  text "PG14" at 62.961,24.738 h1.2
  text "PE1" at 1.595,24.688 h1.2 r315
  text "PE0" at 69.667,23.468 h1.2 r45
  text "NC" at 8.566,22.454 h1.2
  text "GND" at 62.961,22.198 h1.2
  text "PG9" at 1.62,22.097 h1.2 r315
  text "PG8" at 69.616,20.827 h1.2 r45
  text "PG10" at 9.829,19.887 h1.2
  text "PD10" at 62.961,19.658 h1.2
  text "PG12" at 2.078,18.871 h1.2 r315
  text "PG7" at 62.925,17.475 h1.2
  text "NC" at 69.416,17.379 h1.2
  text "NC" at 2.016,17.354 h1.2
  text "PG13" at 9.829,17.322 h1.2
  text "PG6" at 69.743,15.975 h1.2 r45
  text "PG11" at 9.829,14.909 h1.2
  text "NC" at 62.841,14.754 h1.2
  text "PD9" at 1.671,14.477 h1.2 r315
  text "GND" at 67.075,10.1 h1.5
  text "GND" at 6.1,10 h1.5
Top Solder:
  region: 67.625,103.9 67.625,112.4 65.625,112.4 65.625,103.9
Bottom Solder:
  region: 67.625,103.9 67.625,112.4 65.625,112.4 65.625,103.9
M1-Board Shape:
  lines w0.1: 51.369,6.4 ccw(c51.369,6.4) 51.369,6.4 ; 51.369,6.4 ccw(c51.369,7.3) 52.269,7.3 ; 51.369,6.4 51.369,0 68,0 ; 52.269,7.3 ccw(c51.369,7.3) 51.369,8.2 37.369,8.2 ccw(c37.369,7.3) 36.469,7.3 ccw(c37.369,7.3) 37.369,6.4 37.369,0 2,0 cw(c2,2) 0,2 0,131.34 cw(c2,131.34) 2,133.34 68,133.34 cw(c68,131.34) 70,131.34 70,2 cw(c68,2) 68,0 ; 52.269,7.3 52.269,7.3 ; 68,0 68,0
M5-Top Constraints:
  lines w0.2: 94.064,0.553 94.064,14.068 ; 94.064,4.068 183.564,4.068 ; 94.064,7.568 183.564,7.568 ; 94.064,20.365 94.064,33.88 ; 94.064,23.88 183.564,23.88 ; 94.064,27.38 183.564,27.38 ; 94.064,40.304 94.064,53.819 ; 94.064,43.819 183.564,43.819 ; 94.064,47.319 183.564,47.319 ; 94.069,0.553 183.569,0.553 ; 94.069,4.053 183.569,4.053 ; 94.069,20.365 183.569,20.365 ; 94.069,23.865 183.569,23.865 ; 94.069,40.304 183.569,40.304 ; 94.069,43.804 183.569,43.804 ; 94.814,15.818 119.814,15.818 ; 94.814,35.63 119.814,35.63 ; 94.814,55.569 119.814,55.569 ; 114.564,0.553 114.564,14.068 ; 114.564,20.365 114.564,33.88 ; 114.564,40.304 114.564,53.819 ; 125.064,0.553 125.064,14.068 ; 125.064,20.365 125.064,33.88 ; 125.064,40.304 125.064,53.819 ; 138.564,0.553 138.564,14.068 ; 138.564,20.365 138.564,33.88 ; 138.564,40.304 138.564,53.819 ; 155.564,0.553 155.564,14.068 ; 155.564,20.365 155.564,33.88 ; 155.564,40.304 155.564,53.819 ; 172.564,0.553 172.564,14.068 ; 172.564,20.365 172.564,33.88 ; 172.564,40.304 172.564,53.819 ; 183.564,0.553 183.564,14.068 ; 183.564,20.365 183.564,33.88 ; 183.564,40.304 183.564,53.819 ; 94.064,14.068 94.064,14.068 ; 94.064,14.068 94.064,19.318 183.564,19.318 183.564,14.068 ; 94.064,14.068 114.564,14.068 ; 94.064,33.88 94.064,33.88 ; 94.064,33.88 94.064,39.13 183.564,39.13 183.564,33.88 ; 94.064,33.88 114.564,33.88 ; 94.064,53.819 114.564,53.819 ; 94.064,53.819 94.064,59.069 183.564,59.069 183.564,53.819 ; 94.064,53.819 94.064,53.819 ; 114.564,14.068 125.064,14.068 ; 114.564,33.88 125.064,33.88 ; 114.564,53.819 125.064,53.819 ; 125.064,14.068 138.564,14.068 ; 125.064,33.88 138.564,33.88 ; 125.064,53.819 138.564,53.819 ; 138.564,14.068 155.564,14.068 ; 138.564,33.88 155.564,33.88 ; 138.564,53.819 155.564,53.819 ; 155.564,14.068 172.564,14.068 ; 155.564,33.88 172.564,33.88 ; 155.564,53.819 172.564,53.819 ; 172.564,14.068 183.564,14.068 ; 172.564,33.88 183.564,33.88 ; 172.564,53.819 183.564,53.819
  text "IMPEDANCE TABLE    RMII" at 94.814,56.069 h3
  text "LAYER" at 99.064,51.069 h3
  text "TRACE" at 115.314,51.069 h3
  text "SPACING" at 125.814,51.069 h3
  text "IMPEDANCE" at 139.314,51.069 h3
  text "IMPEDANCE" at 156.314,51.069 h3
  text "TOL." at 175.064,51.069 h3
  text "(mm)" at 129.139,48.594 h2.5
  text "(mm)" at 117.314,48.544 h2.5
  text "(Single ended)" at 139.814,48.319 h2.5
  text "(Differential)" at 157.564,48.319 h2.5
  text "+/- 15%" at 174.119,44.679 h3
  text "0.127" at 116.289,44.594 h3
  text "n/a" at 128.314,44.569 h3
  text "TOP/BOTTOM" at 95.294,44.554 h3
  text "50 ohm" at 142.669,44.504 h3
  text "n/a" at 162.219,44.454 h3
  text "+/- 15%" at 174.124,41.164 h3
  text "0.102" at 116.294,41.079 h3
  text "n/a" at 128.319,41.054 h3
  text "LAYER 3" at 97.239,41.019 h3
  text "50 ohm" at 142.674,40.989 h3
  text "n/a" at 162.224,40.939 h3
  text "IMPEDANCE TABLE    RD / RX / TD / TX" at 94.814,35.749 h3
  text "LAYER" at 99.064,31.13 h3
  text "TRACE" at 115.314,31.13 h3
  text "SPACING" at 125.814,31.13 h3
  text "IMPEDANCE" at 139.314,31.13 h3
  text "IMPEDANCE" at 156.314,31.13 h3
  text "TOL." at 175.064,31.13 h3
  text "(mm)" at 129.139,28.655 h2.5
  text "(mm)" at 117.314,28.605 h2.5
  text "(Single ended)" at 139.814,28.38 h2.5
  text "(Differential)" at 157.564,28.38 h2.5
  text "+/- 15%" at 174.119,24.74 h3
  text "0.130" at 116.289,24.655 h3
  text "0.251" at 128.314,24.63 h3
  text "TOP/BOTTOM" at 95.294,24.615 h3
  text "n/a" at 142.669,24.565 h3
  text "100 ohm" at 158.755,24.516 h3
  text "+/- 15%" at 174.124,21.225 h3
  text "0.104" at 116.294,21.14 h3
  text "0.277" at 128.319,21.115 h3
  text "LAYER 3" at 97.239,21.08 h3
  text "100 ohm" at 158.755,21.087 h3
  text "n/a" at 142.674,21.05 h3
  text "IMPEDANCE TABLE   USB FS, USB HS USER, USB HS STLINK" at 94.814,16.318 h3
  text "LAYER" at 99.064,11.318 h3
  text "TRACE" at 115.314,11.318 h3
  text "SPACING" at 125.814,11.318 h3
  text "IMPEDANCE" at 139.314,11.318 h3
  text "IMPEDANCE" at 156.314,11.318 h3
  text "TOL." at 175.064,11.318 h3
  text "(mm)" at 129.139,8.843 h2.5
  text "(mm)" at 117.314,8.793 h2.5
  text "(Single ended)" at 139.814,8.568 h2.5
  text "(Differential)" at 157.564,8.568 h2.5
  text "+/- 15%" at 174.119,4.928 h3
  text "0.155" at 116.289,4.843 h3
  text "0.226" at 128.314,4.818 h3
  text "TOP/BOTTOM" at 95.294,4.803 h3
  text "n/a" at 142.669,4.753 h3
  text "90 ohm" at 158.755,4.577 h3
  text "+/- 15%" at 174.124,1.413 h3
  text "0.130" at 116.294,1.328 h3
  text "0.251" at 128.319,1.303 h3
  text "LAYER 3" at 97.239,1.268 h3
  text "90 ohm" at 158.755,1.275 h3
  text "n/a" at 142.674,1.238 h3
Drill Drawing:
  drawing of 495 lines, arcs and shapes, not listed
  text "PCB SPECIFICATIONS :" at 2.036,176.169 h3
  text "PCB : TYPE 3" at 150.448,175.937 h3
  text "A.   MATERIAL :" at 2.036,172.169 h3
  text "FR-4" at 40.536,172.169 h3
  text "TG-170" at 57.036,172.169 h3
  text "X  TG-150" at 75.286,172.169 h3
  text "TG-140" at 91.286,172.169 h3
  text "ASPECT-RATIO, AXE Z :" at 150.448,170.437 h3
  text "B.   MATERIAL FAMILY :" at 2.036,169.169 h3
  text "N/A" at 40.536,169.169 h3
  text "C.   SOLDERMASK COLOR :" at 2.036,166.169 h3
  text "GREEN" at 40.536,166.169 h3
  text "X  WHITE" at 57.036,166.169 h3
  text "RED" at 75.286,166.169 h3
  text "BLACK" at 91.286,166.169 h3
  text "6:1 to 8:1 / LEVEL \"B\"" at 150.466,163.689 h3
  text "D.   SILKSCREEN COLOR :" at 2.036,163.169 h3
  text "WHITE" at 40.536,163.169 h3
  text "YELLOW" at 57.036,163.169 h3
  text "BLACK" at 75.286,163.169 h3
  text "X  Blue ink PANTONE 2955" at 91.286,163.169 h3
  text "E.   SURFACE FINISH :" at 2.036,160.169 h3
  text "X  ENIG" at 40.536,160.169 h3
  text "IMMERSION SILVER" at 57.036,160.169 h3
  text "IMMERSION TIN" at 91.286,160.169 h3
  text "MINIMUM PARAMETERS" at 150.493,158.088 h3
  text "HASL" at 40.536,157.169 h3
  text "HASL (PB-FREE)" at 57.036,157.169 h3
  text "GOLDEN FINGER" at 91.286,157.169 h3
  text "F.   IMPEDANCE CONTROL :" at 2.036,154.169 h3
  text "NO" at 40.536,154.169 h3
  text "X  YES  (SEE IMPEDANCE TABLE FOR DETAIL INFORMATION)" at 57.036,154.169 h3
  text "DEFAULT" at 150.493,152.588 h3
  text "G.   THROUGH VIA :" at 2.036,151.169 h3
  text "PLUG THE VIAS WHICH ARE COVERED WITH SOLDERMASK ONE OR TWO SIDE." at 40.536,151.169 h3
  text "PLUG MATERIAL :" at 40.536,148.169 h3
  text "X  SOLDERMASK" at 66.036,148.169 h3
  text "NON-CONDUCTIVE EPOXY." at 91.286,148.169 h3
  text "TRACKS : 0.120mm           / GAPS : 0.120mm" at 150.493,146.838 h3
  text "H.   STACK-UP :" at 2.036,145.169 h3
  text "SEE LAYER STACK-UP SEQUENCE FOR OVERALL THICKNESS." at 40.536,145.169 h3
  text "Layer" at 79.741,134.779 h2
  text "Name" at 88.115,134.779 h2
  text "Material" at 104.312,134.779 h2
  text "Thickness" at 118.866,134.779 h2
  text "Constant" at 130.821,134.779 h2
  text "Board Layer Stack" at 141.885,134.779 h2
  text "1" at 79.741,130.779 h2
  text "Top Overlay" at 88.115,130.779 h2
  text "2" at 79.741,126.779 h2
  text "Top Solder" at 88.115,126.779 h2
  text "Solder Resist" at 104.312,126.779 h2
  text "0,015mm" at 118.866,126.779 h2
  text "3,5" at 130.821,126.779 h2
  text "3" at 79.741,122.779 h2
  text "Top Layer" at 88.115,122.779 h2
  text "Copper" at 104.312,122.779 h2
  text "0,042mm" at 118.866,122.779 h2
  text "4" at 79.741,118.779 h2
  text "Dielectric 1" at 88.115,118.779 h2
  text "FR-4" at 104.312,118.779 h2
  text "0,099mm" at 118.866,118.779 h2
  text "4,2" at 130.821,118.779 h2
  text "5" at 79.741,114.779 h2
  text "Signal Layer 1" at 88.115,114.779 h2
  text "Copper" at 104.312,114.779 h2
  text "0,035mm" at 118.866,114.779 h2
  text "6" at 79.741,110.779 h2
  text "Dielectric 2" at 88.115,110.779 h2
  text "0,102mm" at 118.866,110.779 h2
  text "4,2" at 130.821,110.779 h2
  text "7" at 79.741,106.779 h2
  text "Signal Layer 2" at 88.115,106.779 h2
  text "Copper" at 104.312,106.779 h2
  text "0,035mm" at 118.866,106.779 h2
  text "8" at 79.741,102.779 h2
  text "Dielectric 3" at 88.115,102.779 h2
  text "0,946mm" at 118.866,102.779 h2
  text "4,2" at 130.821,102.779 h2
  text "9" at 79.741,98.779 h2
  text "Signal Layer 3" at 88.115,98.779 h2
  text "Copper" at 104.312,98.779 h2
  text "0,035mm" at 118.866,98.779 h2
  text "10" at 79.741,94.779 h2
  text "Dielectric 4" at 88.115,94.779 h2
  text "0,102mm" at 118.866,94.779 h2
  text "4,2" at 130.821,94.779 h2
  text "11" at 79.741,90.779 h2
  text "Signal Layer 4" at 88.115,90.779 h2
  text "Copper" at 104.312,90.779 h2
  text "0,035mm" at 118.866,90.779 h2
  text "12" at 79.741,86.779 h2
  text "Dielectric 5" at 88.115,86.779 h2
  text "0,099mm" at 118.866,86.779 h2
  text "4,2" at 130.821,86.779 h2
  text "13" at 79.741,82.779 h2
  text "Bottom Layer" at 88.115,82.779 h2
  text "Copper" at 104.312,82.779 h2
  text "0,042mm" at 118.866,82.779 h2
  text "14" at 79.741,78.779 h2
  text "Bottom Solder" at 88.115,78.779 h2
  text "Solder Resist" at 104.312,78.779 h2
  text "0,015mm" at 118.866,78.779 h2
  text "3,5" at 130.821,78.779 h2
  text "15" at 79.741,74.779 h2
  text "Bottom Overlay" at 88.115,74.779 h2
  text "Symbol" at 80.452,67.033 h2.4
  text "Count" at 89.851,67.033 h2.4
  text "Hole Size" at 100.482,67.033 h2.4
  text "Plated" at 119.753,67.033 h2.4
  text "Hole Type" at 128.004,67.033 h2.4
  text "Drill Layer Pair" at 140.016,67.033 h2.4
  text "Hole Length" at 162.796,67.033 h2.4
  text "Routed Path Length" at 181.095,67.033 h2.4
  text "1136" at 89.851,62.89 h2
  text "0,200mm (7,87mil)" at 100.482,62.89 h2
  text "PTH" at 119.753,62.89 h2
  text "Round" at 128.004,62.89 h2
  text "Top Layer - Bottom Layer" at 140.016,62.89 h2
  text "-" at 162.796,62.89 h2
  text "-" at 181.095,62.89 h2
  text "9" at 89.851,58.747 h2
  text "0,300mm (11,81mil)" at 100.482,58.747 h2
  text "PTH" at 119.753,58.747 h2
  text "Round" at 128.004,58.747 h2
  text "Top Layer - Bottom Layer" at 140.016,58.747 h2
  text "-" at 162.796,58.747 h2
  text "-" at 181.095,58.747 h2
  text "4" at 89.851,54.604 h2
  text "0,600mm (23,62mil)" at 100.482,54.604 h2
  text "PTH" at 119.753,54.604 h2
  text "Slot" at 128.004,54.604 h2
  text "Top Layer - Bottom Layer" at 140.016,54.604 h2
  text "1,300mm (51,18mil)" at 162.796,54.604 h2
  text "0,700mm (27,56mil)" at 181.095,54.604 h2
  text "2" at 89.851,50.461 h2
  text "0,650mm (25,59mil)" at 100.482,50.461 h2
  text "PTH" at 119.753,50.461 h2
  text "Slot" at 128.004,50.461 h2
  text "Top Layer - Bottom Layer" at 140.016,50.461 h2
  text "0,850mm (33,47mil)" at 162.796,50.461 h2
  text "0,200mm (7,88mil)" at 181.095,50.461 h2
  text "12" at 89.851,46.318 h2
  text "0,700mm (27,56mil)" at 100.482,46.318 h2
  text "PTH" at 119.753,46.318 h2
  text "Round" at 128.004,46.318 h2
  text "Top Layer - Bottom Layer" at 140.016,46.318 h2
  text "-" at 162.796,46.318 h2
  text "-" at 181.095,46.318 h2
  text "2" at 89.851,42.175 h2
  text "0,700mm (27,56mil)" at 100.482,42.175 h2
  text "PTH" at 119.753,42.175 h2
  text "Slot" at 128.004,42.175 h2
  text "Top Layer - Bottom Layer" at 140.016,42.175 h2
  text "2,200mm (86,61mil)" at 162.796,42.175 h2
  text "1,500mm (59,06mil)" at 181.095,42.175 h2
  text "2" at 89.851,38.032 h2
  text "0,850mm (33,47mil)" at 100.482,38.032 h2
  text "NPTH" at 119.753,38.032 h2
  text "Slot" at 128.004,38.032 h2
  text "Top Layer - Bottom Layer" at 140.016,38.032 h2
  text "2,425mm (95,47mil)" at 162.796,38.032 h2
  text "1,575mm (62,01mil)" at 181.095,38.032 h2
  text "2" at 89.851,33.889 h2
  text "0,900mm (35,43mil)" at 100.482,33.889 h2
  text "PTH" at 119.753,33.889 h2
  text "Round" at 128.004,33.889 h2
  text "Top Layer - Bottom Layer" at 140.016,33.889 h2
  text "-" at 162.796,33.889 h2
  text "-" at 181.095,33.889 h2
  text "2" at 89.851,29.746 h2
  text "0,970mm (38,19mil)" at 100.482,29.746 h2
  text "NPTH" at 119.753,29.746 h2
  text "Round" at 128.004,29.746 h2
  text "Top Layer - Bottom Layer" at 140.016,29.746 h2
  text "-" at 162.796,29.746 h2
  text "-" at 181.095,29.746 h2
  text "B" at 79.664,29.492 h1.84
  text "183" at 89.851,25.603 h2
  text "1,000mm (39,37mil)" at 100.482,25.603 h2
  text "PTH" at 119.753,25.603 h2
  text "Round" at 128.004,25.603 h2
  text "Top Layer - Bottom Layer" at 140.016,25.603 h2
  text "-" at 162.796,25.603 h2
  text "-" at 181.095,25.603 h2
  text "100" at 89.851,21.46 h2
  text "1,100mm (43,31mil)" at 100.482,21.46 h2
  text "PTH" at 119.753,21.46 h2
  text "Round" at 128.004,21.46 h2
  text "Top Layer - Bottom Layer" at 140.016,21.46 h2
  text "-" at 162.796,21.46 h2
  text "-" at 181.095,21.46 h2
  text "2" at 89.851,17.316 h2
  text "1,190mm (46,85mil)" at 100.482,17.316 h2
  text "NPTH" at 119.753,17.316 h2
  text "Round" at 128.004,17.316 h2
  text "Top Layer - Bottom Layer" at 140.016,17.316 h2
  text "-" at 162.796,17.316 h2
  text "-" at 181.095,17.316 h2
  text "C" at 79.664,17.063 h1.84
  text "2" at 89.851,13.173 h2
  text "1,500mm (59,06mil)" at 100.482,13.173 h2
  text "NPTH" at 119.753,13.173 h2
  text "Round" at 128.004,13.173 h2
  text "Top Layer - Bottom Layer" at 140.016,13.173 h2
  text "-" at 162.796,13.173 h2
  text "-" at 181.095,13.173 h2
  text "5" at 89.851,9.03 h2
  text "3,200mm (125,98mil)" at 100.482,9.03 h2
  text "NPTH" at 119.753,9.03 h2
  text "Round" at 128.004,9.03 h2
  text "Top Layer - Bottom Layer" at 140.016,9.03 h2
  text "-" at 162.796,9.03 h2
  text "-" at 181.095,9.03 h2
  text "1463 Total" at 89.851,4.887 h2
  text "Slot definitions :" at 80.452,1.987 h2
  text "Routed Path Length" at 94.105,1.987 h2
  text "= Calculated from tool start centre position to tool end centre position." at 111.018,1.987 h2
  text "Hole Length" at 94.105,0.33 h2
  text "= Routed Path Length + Tool Size = Slot length as defined in the PCB layout" at 104.739,0.33 h2

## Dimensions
10.866,105.4 to 59.126,104.13 on M4-Bottom Dimensions
43.886,53.33 to 59.126,104.13 on M4-Bottom Dimensions
3.246,126.99 to 3.246,12.69 on M4-Bottom Dimensions
10.866,33.01 to 3.246,12.69 on M4-Bottom Dimensions
3.246,12.69 to 2,-0.009 on M4-Bottom Dimensions
12.136,29.2 to 3.246,12.69 on M4-Bottom Dimensions
12.136,29.2 to 57.856,29.2 on M4-Bottom Dimensions
10.866,33.01 to 59.126,33.01 on M4-Bottom Dimensions
3.246,12.69 to 66.746,12.665 on M4-Bottom Dimensions
0,1.991 to 70,1.991 on M4-Bottom Dimensions
43.886,53.33 to 59.126,104.13 on M4-Bottom Dimensions
59.126,104.13 to 66.746,101.565 on M4-Bottom Dimensions
3.246,126.99 to 3.246,101.59 on M4-Bottom Dimensions
3.246,129.53 to 2,133.331 on M4-Bottom Dimensions
59.126,104.13 to 66.746,126.99 on M4-Bottom Dimensions
68,133.331 to 68,-0.009 on M4-Bottom Dimensions
10.866,105.4 to 3.246,101.59 on M4-Bottom Dimensions
10.866,105.409 to 3.246,101.599 on M3-Top Dimensions
68,133.34 to 68,0 on M3-Top Dimensions
59.126,104.139 to 66.746,126.999 on M3-Top Dimensions
3.246,129.539 to 2,133.34 on M3-Top Dimensions
3.246,126.999 to 3.246,101.599 on M3-Top Dimensions
59.126,104.139 to 66.746,101.574 on M3-Top Dimensions
43.886,53.339 to 59.126,104.139 on M3-Top Dimensions
0,2 to 70,2 on M3-Top Dimensions
5.786,12.699 to 64.206,12.674 on M3-Top Dimensions
10.866,33.019 to 59.126,33.019 on M3-Top Dimensions
12.136,29.209 to 57.856,29.209 on M3-Top Dimensions
12.136,29.209 to 5.786,12.699 on M3-Top Dimensions
5.786,12.699 to 2,0 on M3-Top Dimensions
10.866,33.019 to 5.786,12.699 on M3-Top Dimensions
3.246,126.999 to 5.786,12.699 on M3-Top Dimensions
43.886,53.339 to 59.126,104.139 on M3-Top Dimensions
10.866,105.409 to 59.126,104.139 on M3-Top Dimensions
0,131.34 to 70,131.34 on M2-Board Dimensions
2,0 to 2,133.34 on M2-Board Dimensions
